VERSION 5.8 ;
BUSBITCHARS "[]" ;
DIVIDERCHAR "/" ;
UNITS
    DATABASE MICRONS 1000 ;
END UNITS

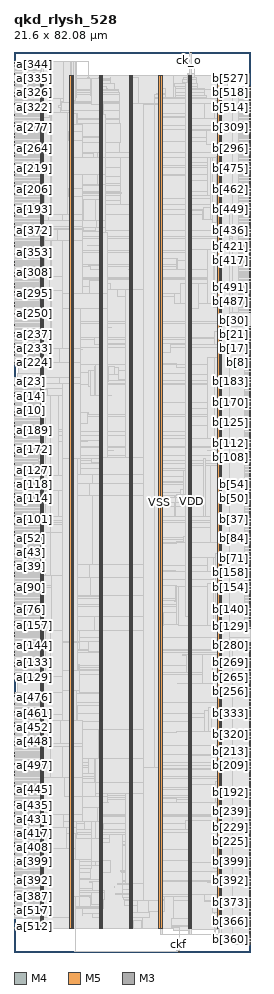
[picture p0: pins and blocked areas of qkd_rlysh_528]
MACRO qkd_rlysh_528
  FOREIGN qkd_rlysh_528 0 0 ;
  CLASS BLOCK ;
  SIZE 21.6 BY 82.08 ;
  PIN a[0]
    DIRECTION INPUT ;
    USE SIGNAL ;
    PORT
      LAYER M4 ;
        RECT  0 47.952 0.084 47.976 ;
    END
  END a[0]
  PIN a[100]
    DIRECTION INPUT ;
    USE SIGNAL ;
    PORT
      LAYER M4 ;
        RECT  0 39.312 0.084 39.336 ;
    END
  END a[100]
  PIN a[101]
    DIRECTION INPUT ;
    USE SIGNAL ;
    PORT
      LAYER M4 ;
        RECT  0 39.456 0.084 39.48 ;
    END
  END a[101]
  PIN a[102]
    DIRECTION INPUT ;
    USE SIGNAL ;
    PORT
      LAYER M4 ;
        RECT  0 39.6 0.084 39.624 ;
    END
  END a[102]
  PIN a[103]
    DIRECTION INPUT ;
    USE SIGNAL ;
    PORT
      LAYER M4 ;
        RECT  0 39.744 0.084 39.768 ;
    END
  END a[103]
  PIN a[104]
    DIRECTION INPUT ;
    USE SIGNAL ;
    PORT
      LAYER M4 ;
        RECT  0 39.888 0.084 39.912 ;
    END
  END a[104]
  PIN a[105]
    DIRECTION INPUT ;
    USE SIGNAL ;
    PORT
      LAYER M4 ;
        RECT  0 40.032 0.084 40.056 ;
    END
  END a[105]
  PIN a[106]
    DIRECTION INPUT ;
    USE SIGNAL ;
    PORT
      LAYER M4 ;
        RECT  0 40.176 0.084 40.2 ;
    END
  END a[106]
  PIN a[107]
    DIRECTION INPUT ;
    USE SIGNAL ;
    PORT
      LAYER M4 ;
        RECT  0 40.32 0.084 40.344 ;
    END
  END a[107]
  PIN a[108]
    DIRECTION INPUT ;
    USE SIGNAL ;
    PORT
      LAYER M4 ;
        RECT  0 40.464 0.084 40.488 ;
    END
  END a[108]
  PIN a[109]
    DIRECTION INPUT ;
    USE SIGNAL ;
    PORT
      LAYER M4 ;
        RECT  0 40.608 0.084 40.632 ;
    END
  END a[109]
  PIN a[10]
    DIRECTION INPUT ;
    USE SIGNAL ;
    PORT
      LAYER M4 ;
        RECT  0 49.392 0.084 49.416 ;
    END
  END a[10]
  PIN a[110]
    DIRECTION INPUT ;
    USE SIGNAL ;
    PORT
      LAYER M4 ;
        RECT  0 40.752 0.084 40.776 ;
    END
  END a[110]
  PIN a[111]
    DIRECTION INPUT ;
    USE SIGNAL ;
    PORT
      LAYER M4 ;
        RECT  0 40.896 0.084 40.92 ;
    END
  END a[111]
  PIN a[112]
    DIRECTION INPUT ;
    USE SIGNAL ;
    PORT
      LAYER M4 ;
        RECT  0 41.04 0.084 41.064 ;
    END
  END a[112]
  PIN a[113]
    DIRECTION INPUT ;
    USE SIGNAL ;
    PORT
      LAYER M4 ;
        RECT  0 41.184 0.084 41.208 ;
    END
  END a[113]
  PIN a[114]
    DIRECTION INPUT ;
    USE SIGNAL ;
    PORT
      LAYER M4 ;
        RECT  0 41.328 0.084 41.352 ;
    END
  END a[114]
  PIN a[115]
    DIRECTION INPUT ;
    USE SIGNAL ;
    PORT
      LAYER M4 ;
        RECT  0 41.472 0.084 41.496 ;
    END
  END a[115]
  PIN a[116]
    DIRECTION INPUT ;
    USE SIGNAL ;
    PORT
      LAYER M4 ;
        RECT  0 41.616 0.084 41.64 ;
    END
  END a[116]
  PIN a[117]
    DIRECTION INPUT ;
    USE SIGNAL ;
    PORT
      LAYER M4 ;
        RECT  0 41.76 0.084 41.784 ;
    END
  END a[117]
  PIN a[118]
    DIRECTION INPUT ;
    USE SIGNAL ;
    PORT
      LAYER M4 ;
        RECT  0 41.904 0.084 41.928 ;
    END
  END a[118]
  PIN a[119]
    DIRECTION INPUT ;
    USE SIGNAL ;
    PORT
      LAYER M4 ;
        RECT  0 42.048 0.084 42.072 ;
    END
  END a[119]
  PIN a[11]
    DIRECTION INPUT ;
    USE SIGNAL ;
    PORT
      LAYER M4 ;
        RECT  0 49.536 0.084 49.56 ;
    END
  END a[11]
  PIN a[120]
    DIRECTION INPUT ;
    USE SIGNAL ;
    PORT
      LAYER M4 ;
        RECT  0 42.192 0.084 42.216 ;
    END
  END a[120]
  PIN a[121]
    DIRECTION INPUT ;
    USE SIGNAL ;
    PORT
      LAYER M4 ;
        RECT  0 42.336 0.084 42.36 ;
    END
  END a[121]
  PIN a[122]
    DIRECTION INPUT ;
    USE SIGNAL ;
    PORT
      LAYER M4 ;
        RECT  0 42.48 0.084 42.504 ;
    END
  END a[122]
  PIN a[123]
    DIRECTION INPUT ;
    USE SIGNAL ;
    PORT
      LAYER M4 ;
        RECT  0 42.624 0.084 42.648 ;
    END
  END a[123]
  PIN a[124]
    DIRECTION INPUT ;
    USE SIGNAL ;
    PORT
      LAYER M4 ;
        RECT  0 42.768 0.084 42.792 ;
    END
  END a[124]
  PIN a[125]
    DIRECTION INPUT ;
    USE SIGNAL ;
    PORT
      LAYER M4 ;
        RECT  0 42.912 0.084 42.936 ;
    END
  END a[125]
  PIN a[126]
    DIRECTION INPUT ;
    USE SIGNAL ;
    PORT
      LAYER M4 ;
        RECT  0 43.056 0.084 43.08 ;
    END
  END a[126]
  PIN a[127]
    DIRECTION INPUT ;
    USE SIGNAL ;
    PORT
      LAYER M4 ;
        RECT  0 43.2 0.084 43.224 ;
    END
  END a[127]
  PIN a[128]
    DIRECTION INPUT ;
    USE SIGNAL ;
    PORT
      LAYER M4 ;
        RECT  0 24.912 0.084 24.936 ;
    END
  END a[128]
  PIN a[129]
    DIRECTION INPUT ;
    USE SIGNAL ;
    PORT
      LAYER M4 ;
        RECT  0 25.056 0.084 25.08 ;
    END
  END a[129]
  PIN a[12]
    DIRECTION INPUT ;
    USE SIGNAL ;
    PORT
      LAYER M4 ;
        RECT  0 49.68 0.084 49.704 ;
    END
  END a[12]
  PIN a[130]
    DIRECTION INPUT ;
    USE SIGNAL ;
    PORT
      LAYER M4 ;
        RECT  0 25.2 0.084 25.224 ;
    END
  END a[130]
  PIN a[131]
    DIRECTION INPUT ;
    USE SIGNAL ;
    PORT
      LAYER M4 ;
        RECT  0 25.344 0.084 25.368 ;
    END
  END a[131]
  PIN a[132]
    DIRECTION INPUT ;
    USE SIGNAL ;
    PORT
      LAYER M4 ;
        RECT  0 25.488 0.084 25.512 ;
    END
  END a[132]
  PIN a[133]
    DIRECTION INPUT ;
    USE SIGNAL ;
    PORT
      LAYER M4 ;
        RECT  0 25.632 0.084 25.656 ;
    END
  END a[133]
  PIN a[134]
    DIRECTION INPUT ;
    USE SIGNAL ;
    PORT
      LAYER M4 ;
        RECT  0 25.776 0.084 25.8 ;
    END
  END a[134]
  PIN a[135]
    DIRECTION INPUT ;
    USE SIGNAL ;
    PORT
      LAYER M4 ;
        RECT  0 25.92 0.084 25.944 ;
    END
  END a[135]
  PIN a[136]
    DIRECTION INPUT ;
    USE SIGNAL ;
    PORT
      LAYER M4 ;
        RECT  0 26.064 0.084 26.088 ;
    END
  END a[136]
  PIN a[137]
    DIRECTION INPUT ;
    USE SIGNAL ;
    PORT
      LAYER M4 ;
        RECT  0 26.208 0.084 26.232 ;
    END
  END a[137]
  PIN a[138]
    DIRECTION INPUT ;
    USE SIGNAL ;
    PORT
      LAYER M4 ;
        RECT  0 26.352 0.084 26.376 ;
    END
  END a[138]
  PIN a[139]
    DIRECTION INPUT ;
    USE SIGNAL ;
    PORT
      LAYER M4 ;
        RECT  0 26.496 0.084 26.52 ;
    END
  END a[139]
  PIN a[13]
    DIRECTION INPUT ;
    USE SIGNAL ;
    PORT
      LAYER M4 ;
        RECT  0 49.824 0.084 49.848 ;
    END
  END a[13]
  PIN a[140]
    DIRECTION INPUT ;
    USE SIGNAL ;
    PORT
      LAYER M4 ;
        RECT  0 26.64 0.084 26.664 ;
    END
  END a[140]
  PIN a[141]
    DIRECTION INPUT ;
    USE SIGNAL ;
    PORT
      LAYER M4 ;
        RECT  0 26.784 0.084 26.808 ;
    END
  END a[141]
  PIN a[142]
    DIRECTION INPUT ;
    USE SIGNAL ;
    PORT
      LAYER M4 ;
        RECT  0 26.928 0.084 26.952 ;
    END
  END a[142]
  PIN a[143]
    DIRECTION INPUT ;
    USE SIGNAL ;
    PORT
      LAYER M4 ;
        RECT  0 27.072 0.084 27.096 ;
    END
  END a[143]
  PIN a[144]
    DIRECTION INPUT ;
    USE SIGNAL ;
    PORT
      LAYER M4 ;
        RECT  0 27.216 0.084 27.24 ;
    END
  END a[144]
  PIN a[145]
    DIRECTION INPUT ;
    USE SIGNAL ;
    PORT
      LAYER M4 ;
        RECT  0 27.36 0.084 27.384 ;
    END
  END a[145]
  PIN a[146]
    DIRECTION INPUT ;
    USE SIGNAL ;
    PORT
      LAYER M4 ;
        RECT  0 27.504 0.084 27.528 ;
    END
  END a[146]
  PIN a[147]
    DIRECTION INPUT ;
    USE SIGNAL ;
    PORT
      LAYER M4 ;
        RECT  0 27.648 0.084 27.672 ;
    END
  END a[147]
  PIN a[148]
    DIRECTION INPUT ;
    USE SIGNAL ;
    PORT
      LAYER M4 ;
        RECT  0 27.792 0.084 27.816 ;
    END
  END a[148]
  PIN a[149]
    DIRECTION INPUT ;
    USE SIGNAL ;
    PORT
      LAYER M4 ;
        RECT  0 27.936 0.084 27.96 ;
    END
  END a[149]
  PIN a[14]
    DIRECTION INPUT ;
    USE SIGNAL ;
    PORT
      LAYER M4 ;
        RECT  0 49.968 0.084 49.992 ;
    END
  END a[14]
  PIN a[150]
    DIRECTION INPUT ;
    USE SIGNAL ;
    PORT
      LAYER M4 ;
        RECT  0 28.08 0.084 28.104 ;
    END
  END a[150]
  PIN a[151]
    DIRECTION INPUT ;
    USE SIGNAL ;
    PORT
      LAYER M4 ;
        RECT  0 28.224 0.084 28.248 ;
    END
  END a[151]
  PIN a[152]
    DIRECTION INPUT ;
    USE SIGNAL ;
    PORT
      LAYER M4 ;
        RECT  0 28.368 0.084 28.392 ;
    END
  END a[152]
  PIN a[153]
    DIRECTION INPUT ;
    USE SIGNAL ;
    PORT
      LAYER M4 ;
        RECT  0 28.512 0.084 28.536 ;
    END
  END a[153]
  PIN a[154]
    DIRECTION INPUT ;
    USE SIGNAL ;
    PORT
      LAYER M4 ;
        RECT  0 28.656 0.084 28.68 ;
    END
  END a[154]
  PIN a[155]
    DIRECTION INPUT ;
    USE SIGNAL ;
    PORT
      LAYER M4 ;
        RECT  0 28.8 0.084 28.824 ;
    END
  END a[155]
  PIN a[156]
    DIRECTION INPUT ;
    USE SIGNAL ;
    PORT
      LAYER M4 ;
        RECT  0 28.944 0.084 28.968 ;
    END
  END a[156]
  PIN a[157]
    DIRECTION INPUT ;
    USE SIGNAL ;
    PORT
      LAYER M4 ;
        RECT  0 29.088 0.084 29.112 ;
    END
  END a[157]
  PIN a[158]
    DIRECTION INPUT ;
    USE SIGNAL ;
    PORT
      LAYER M4 ;
        RECT  0 29.232 0.084 29.256 ;
    END
  END a[158]
  PIN a[159]
    DIRECTION INPUT ;
    USE SIGNAL ;
    PORT
      LAYER M4 ;
        RECT  0 29.376 0.084 29.4 ;
    END
  END a[159]
  PIN a[15]
    DIRECTION INPUT ;
    USE SIGNAL ;
    PORT
      LAYER M4 ;
        RECT  0 50.112 0.084 50.136 ;
    END
  END a[15]
  PIN a[160]
    DIRECTION INPUT ;
    USE SIGNAL ;
    PORT
      LAYER M4 ;
        RECT  0 43.344 0.084 43.368 ;
    END
  END a[160]
  PIN a[161]
    DIRECTION INPUT ;
    USE SIGNAL ;
    PORT
      LAYER M4 ;
        RECT  0 43.488 0.084 43.512 ;
    END
  END a[161]
  PIN a[162]
    DIRECTION INPUT ;
    USE SIGNAL ;
    PORT
      LAYER M4 ;
        RECT  0 43.632 0.084 43.656 ;
    END
  END a[162]
  PIN a[163]
    DIRECTION INPUT ;
    USE SIGNAL ;
    PORT
      LAYER M4 ;
        RECT  0 43.776 0.084 43.8 ;
    END
  END a[163]
  PIN a[164]
    DIRECTION INPUT ;
    USE SIGNAL ;
    PORT
      LAYER M4 ;
        RECT  0 43.92 0.084 43.944 ;
    END
  END a[164]
  PIN a[165]
    DIRECTION INPUT ;
    USE SIGNAL ;
    PORT
      LAYER M4 ;
        RECT  0 44.064 0.084 44.088 ;
    END
  END a[165]
  PIN a[166]
    DIRECTION INPUT ;
    USE SIGNAL ;
    PORT
      LAYER M4 ;
        RECT  0 44.208 0.084 44.232 ;
    END
  END a[166]
  PIN a[167]
    DIRECTION INPUT ;
    USE SIGNAL ;
    PORT
      LAYER M4 ;
        RECT  0 44.352 0.084 44.376 ;
    END
  END a[167]
  PIN a[168]
    DIRECTION INPUT ;
    USE SIGNAL ;
    PORT
      LAYER M4 ;
        RECT  0 44.496 0.084 44.52 ;
    END
  END a[168]
  PIN a[169]
    DIRECTION INPUT ;
    USE SIGNAL ;
    PORT
      LAYER M4 ;
        RECT  0 44.64 0.084 44.664 ;
    END
  END a[169]
  PIN a[16]
    DIRECTION INPUT ;
    USE SIGNAL ;
    PORT
      LAYER M4 ;
        RECT  0 50.256 0.084 50.28 ;
    END
  END a[16]
  PIN a[170]
    DIRECTION INPUT ;
    USE SIGNAL ;
    PORT
      LAYER M4 ;
        RECT  0 44.784 0.084 44.808 ;
    END
  END a[170]
  PIN a[171]
    DIRECTION INPUT ;
    USE SIGNAL ;
    PORT
      LAYER M4 ;
        RECT  0 44.928 0.084 44.952 ;
    END
  END a[171]
  PIN a[172]
    DIRECTION INPUT ;
    USE SIGNAL ;
    PORT
      LAYER M4 ;
        RECT  0 45.072 0.084 45.096 ;
    END
  END a[172]
  PIN a[173]
    DIRECTION INPUT ;
    USE SIGNAL ;
    PORT
      LAYER M4 ;
        RECT  0 45.216 0.084 45.24 ;
    END
  END a[173]
  PIN a[174]
    DIRECTION INPUT ;
    USE SIGNAL ;
    PORT
      LAYER M4 ;
        RECT  0 45.36 0.084 45.384 ;
    END
  END a[174]
  PIN a[175]
    DIRECTION INPUT ;
    USE SIGNAL ;
    PORT
      LAYER M4 ;
        RECT  0 45.504 0.084 45.528 ;
    END
  END a[175]
  PIN a[176]
    DIRECTION INPUT ;
    USE SIGNAL ;
    PORT
      LAYER M4 ;
        RECT  0 45.648 0.084 45.672 ;
    END
  END a[176]
  PIN a[177]
    DIRECTION INPUT ;
    USE SIGNAL ;
    PORT
      LAYER M4 ;
        RECT  0 45.792 0.084 45.816 ;
    END
  END a[177]
  PIN a[178]
    DIRECTION INPUT ;
    USE SIGNAL ;
    PORT
      LAYER M4 ;
        RECT  0 45.936 0.084 45.96 ;
    END
  END a[178]
  PIN a[179]
    DIRECTION INPUT ;
    USE SIGNAL ;
    PORT
      LAYER M4 ;
        RECT  0 46.08 0.084 46.104 ;
    END
  END a[179]
  PIN a[17]
    DIRECTION INPUT ;
    USE SIGNAL ;
    PORT
      LAYER M4 ;
        RECT  0 50.4 0.084 50.424 ;
    END
  END a[17]
  PIN a[180]
    DIRECTION INPUT ;
    USE SIGNAL ;
    PORT
      LAYER M4 ;
        RECT  0 46.224 0.084 46.248 ;
    END
  END a[180]
  PIN a[181]
    DIRECTION INPUT ;
    USE SIGNAL ;
    PORT
      LAYER M4 ;
        RECT  0 46.368 0.084 46.392 ;
    END
  END a[181]
  PIN a[182]
    DIRECTION INPUT ;
    USE SIGNAL ;
    PORT
      LAYER M4 ;
        RECT  0 46.512 0.084 46.536 ;
    END
  END a[182]
  PIN a[183]
    DIRECTION INPUT ;
    USE SIGNAL ;
    PORT
      LAYER M4 ;
        RECT  0 46.656 0.084 46.68 ;
    END
  END a[183]
  PIN a[184]
    DIRECTION INPUT ;
    USE SIGNAL ;
    PORT
      LAYER M4 ;
        RECT  0 46.8 0.084 46.824 ;
    END
  END a[184]
  PIN a[185]
    DIRECTION INPUT ;
    USE SIGNAL ;
    PORT
      LAYER M4 ;
        RECT  0 46.944 0.084 46.968 ;
    END
  END a[185]
  PIN a[186]
    DIRECTION INPUT ;
    USE SIGNAL ;
    PORT
      LAYER M4 ;
        RECT  0 47.088 0.084 47.112 ;
    END
  END a[186]
  PIN a[187]
    DIRECTION INPUT ;
    USE SIGNAL ;
    PORT
      LAYER M4 ;
        RECT  0 47.232 0.084 47.256 ;
    END
  END a[187]
  PIN a[188]
    DIRECTION INPUT ;
    USE SIGNAL ;
    PORT
      LAYER M4 ;
        RECT  0 47.376 0.084 47.4 ;
    END
  END a[188]
  PIN a[189]
    DIRECTION INPUT ;
    USE SIGNAL ;
    PORT
      LAYER M4 ;
        RECT  0 47.52 0.084 47.544 ;
    END
  END a[189]
  PIN a[18]
    DIRECTION INPUT ;
    USE SIGNAL ;
    PORT
      LAYER M4 ;
        RECT  0 50.544 0.084 50.568 ;
    END
  END a[18]
  PIN a[190]
    DIRECTION INPUT ;
    USE SIGNAL ;
    PORT
      LAYER M4 ;
        RECT  0 47.664 0.084 47.688 ;
    END
  END a[190]
  PIN a[191]
    DIRECTION INPUT ;
    USE SIGNAL ;
    PORT
      LAYER M4 ;
        RECT  0 47.808 0.084 47.832 ;
    END
  END a[191]
  PIN a[192]
    DIRECTION INPUT ;
    USE SIGNAL ;
    PORT
      LAYER M4 ;
        RECT  0 67.536 0.084 67.56 ;
    END
  END a[192]
  PIN a[193]
    DIRECTION INPUT ;
    USE SIGNAL ;
    PORT
      LAYER M4 ;
        RECT  0 67.68 0.084 67.704 ;
    END
  END a[193]
  PIN a[194]
    DIRECTION INPUT ;
    USE SIGNAL ;
    PORT
      LAYER M4 ;
        RECT  0 67.824 0.084 67.848 ;
    END
  END a[194]
  PIN a[195]
    DIRECTION INPUT ;
    USE SIGNAL ;
    PORT
      LAYER M4 ;
        RECT  0 67.968 0.084 67.992 ;
    END
  END a[195]
  PIN a[196]
    DIRECTION INPUT ;
    USE SIGNAL ;
    PORT
      LAYER M4 ;
        RECT  0 68.112 0.084 68.136 ;
    END
  END a[196]
  PIN a[197]
    DIRECTION INPUT ;
    USE SIGNAL ;
    PORT
      LAYER M4 ;
        RECT  0 68.256 0.084 68.28 ;
    END
  END a[197]
  PIN a[198]
    DIRECTION INPUT ;
    USE SIGNAL ;
    PORT
      LAYER M4 ;
        RECT  0 68.4 0.084 68.424 ;
    END
  END a[198]
  PIN a[199]
    DIRECTION INPUT ;
    USE SIGNAL ;
    PORT
      LAYER M4 ;
        RECT  0 68.544 0.084 68.568 ;
    END
  END a[199]
  PIN a[19]
    DIRECTION INPUT ;
    USE SIGNAL ;
    PORT
      LAYER M4 ;
        RECT  0 50.688 0.084 50.712 ;
    END
  END a[19]
  PIN a[1]
    DIRECTION INPUT ;
    USE SIGNAL ;
    PORT
      LAYER M4 ;
        RECT  0 48.096 0.084 48.12 ;
    END
  END a[1]
  PIN a[200]
    DIRECTION INPUT ;
    USE SIGNAL ;
    PORT
      LAYER M4 ;
        RECT  0 68.688 0.084 68.712 ;
    END
  END a[200]
  PIN a[201]
    DIRECTION INPUT ;
    USE SIGNAL ;
    PORT
      LAYER M4 ;
        RECT  0 68.832 0.084 68.856 ;
    END
  END a[201]
  PIN a[202]
    DIRECTION INPUT ;
    USE SIGNAL ;
    PORT
      LAYER M4 ;
        RECT  0 68.976 0.084 69 ;
    END
  END a[202]
  PIN a[203]
    DIRECTION INPUT ;
    USE SIGNAL ;
    PORT
      LAYER M4 ;
        RECT  0 69.12 0.084 69.144 ;
    END
  END a[203]
  PIN a[204]
    DIRECTION INPUT ;
    USE SIGNAL ;
    PORT
      LAYER M4 ;
        RECT  0 69.264 0.084 69.288 ;
    END
  END a[204]
  PIN a[205]
    DIRECTION INPUT ;
    USE SIGNAL ;
    PORT
      LAYER M4 ;
        RECT  0 69.408 0.084 69.432 ;
    END
  END a[205]
  PIN a[206]
    DIRECTION INPUT ;
    USE SIGNAL ;
    PORT
      LAYER M4 ;
        RECT  0 69.552 0.084 69.576 ;
    END
  END a[206]
  PIN a[207]
    DIRECTION INPUT ;
    USE SIGNAL ;
    PORT
      LAYER M4 ;
        RECT  0 69.696 0.084 69.72 ;
    END
  END a[207]
  PIN a[208]
    DIRECTION INPUT ;
    USE SIGNAL ;
    PORT
      LAYER M4 ;
        RECT  0 69.84 0.084 69.864 ;
    END
  END a[208]
  PIN a[209]
    DIRECTION INPUT ;
    USE SIGNAL ;
    PORT
      LAYER M4 ;
        RECT  0 69.984 0.084 70.008 ;
    END
  END a[209]
  PIN a[20]
    DIRECTION INPUT ;
    USE SIGNAL ;
    PORT
      LAYER M4 ;
        RECT  0 50.832 0.084 50.856 ;
    END
  END a[20]
  PIN a[210]
    DIRECTION INPUT ;
    USE SIGNAL ;
    PORT
      LAYER M4 ;
        RECT  0 70.128 0.084 70.152 ;
    END
  END a[210]
  PIN a[211]
    DIRECTION INPUT ;
    USE SIGNAL ;
    PORT
      LAYER M4 ;
        RECT  0 70.272 0.084 70.296 ;
    END
  END a[211]
  PIN a[212]
    DIRECTION INPUT ;
    USE SIGNAL ;
    PORT
      LAYER M4 ;
        RECT  0 70.416 0.084 70.44 ;
    END
  END a[212]
  PIN a[213]
    DIRECTION INPUT ;
    USE SIGNAL ;
    PORT
      LAYER M4 ;
        RECT  0 70.56 0.084 70.584 ;
    END
  END a[213]
  PIN a[214]
    DIRECTION INPUT ;
    USE SIGNAL ;
    PORT
      LAYER M4 ;
        RECT  0 70.704 0.084 70.728 ;
    END
  END a[214]
  PIN a[215]
    DIRECTION INPUT ;
    USE SIGNAL ;
    PORT
      LAYER M4 ;
        RECT  0 70.848 0.084 70.872 ;
    END
  END a[215]
  PIN a[216]
    DIRECTION INPUT ;
    USE SIGNAL ;
    PORT
      LAYER M4 ;
        RECT  0 70.992 0.084 71.016 ;
    END
  END a[216]
  PIN a[217]
    DIRECTION INPUT ;
    USE SIGNAL ;
    PORT
      LAYER M4 ;
        RECT  0 71.136 0.084 71.16 ;
    END
  END a[217]
  PIN a[218]
    DIRECTION INPUT ;
    USE SIGNAL ;
    PORT
      LAYER M4 ;
        RECT  0 71.28 0.084 71.304 ;
    END
  END a[218]
  PIN a[219]
    DIRECTION INPUT ;
    USE SIGNAL ;
    PORT
      LAYER M4 ;
        RECT  0 71.424 0.084 71.448 ;
    END
  END a[219]
  PIN a[21]
    DIRECTION INPUT ;
    USE SIGNAL ;
    PORT
      LAYER M4 ;
        RECT  0 50.976 0.084 51 ;
    END
  END a[21]
  PIN a[220]
    DIRECTION INPUT ;
    USE SIGNAL ;
    PORT
      LAYER M4 ;
        RECT  0 71.568 0.084 71.592 ;
    END
  END a[220]
  PIN a[221]
    DIRECTION INPUT ;
    USE SIGNAL ;
    PORT
      LAYER M4 ;
        RECT  0 71.712 0.084 71.736 ;
    END
  END a[221]
  PIN a[222]
    DIRECTION INPUT ;
    USE SIGNAL ;
    PORT
      LAYER M4 ;
        RECT  0 71.856 0.084 71.88 ;
    END
  END a[222]
  PIN a[223]
    DIRECTION INPUT ;
    USE SIGNAL ;
    PORT
      LAYER M4 ;
        RECT  0 72 0.084 72.024 ;
    END
  END a[223]
  PIN a[224]
    DIRECTION INPUT ;
    USE SIGNAL ;
    PORT
      LAYER M4 ;
        RECT  0 53.712 0.084 53.736 ;
    END
  END a[224]
  PIN a[225]
    DIRECTION INPUT ;
    USE SIGNAL ;
    PORT
      LAYER M4 ;
        RECT  0 53.856 0.084 53.88 ;
    END
  END a[225]
  PIN a[226]
    DIRECTION INPUT ;
    USE SIGNAL ;
    PORT
      LAYER M4 ;
        RECT  0 54 0.084 54.024 ;
    END
  END a[226]
  PIN a[227]
    DIRECTION INPUT ;
    USE SIGNAL ;
    PORT
      LAYER M4 ;
        RECT  0 54.144 0.084 54.168 ;
    END
  END a[227]
  PIN a[228]
    DIRECTION INPUT ;
    USE SIGNAL ;
    PORT
      LAYER M4 ;
        RECT  0 54.288 0.084 54.312 ;
    END
  END a[228]
  PIN a[229]
    DIRECTION INPUT ;
    USE SIGNAL ;
    PORT
      LAYER M4 ;
        RECT  0 54.432 0.084 54.456 ;
    END
  END a[229]
  PIN a[22]
    DIRECTION INPUT ;
    USE SIGNAL ;
    PORT
      LAYER M4 ;
        RECT  0 51.12 0.084 51.144 ;
    END
  END a[22]
  PIN a[230]
    DIRECTION INPUT ;
    USE SIGNAL ;
    PORT
      LAYER M4 ;
        RECT  0 54.576 0.084 54.6 ;
    END
  END a[230]
  PIN a[231]
    DIRECTION INPUT ;
    USE SIGNAL ;
    PORT
      LAYER M4 ;
        RECT  0 54.72 0.084 54.744 ;
    END
  END a[231]
  PIN a[232]
    DIRECTION INPUT ;
    USE SIGNAL ;
    PORT
      LAYER M4 ;
        RECT  0 54.864 0.084 54.888 ;
    END
  END a[232]
  PIN a[233]
    DIRECTION INPUT ;
    USE SIGNAL ;
    PORT
      LAYER M4 ;
        RECT  0 55.008 0.084 55.032 ;
    END
  END a[233]
  PIN a[234]
    DIRECTION INPUT ;
    USE SIGNAL ;
    PORT
      LAYER M4 ;
        RECT  0 55.152 0.084 55.176 ;
    END
  END a[234]
  PIN a[235]
    DIRECTION INPUT ;
    USE SIGNAL ;
    PORT
      LAYER M4 ;
        RECT  0 55.296 0.084 55.32 ;
    END
  END a[235]
  PIN a[236]
    DIRECTION INPUT ;
    USE SIGNAL ;
    PORT
      LAYER M4 ;
        RECT  0 55.44 0.084 55.464 ;
    END
  END a[236]
  PIN a[237]
    DIRECTION INPUT ;
    USE SIGNAL ;
    PORT
      LAYER M4 ;
        RECT  0 55.584 0.084 55.608 ;
    END
  END a[237]
  PIN a[238]
    DIRECTION INPUT ;
    USE SIGNAL ;
    PORT
      LAYER M4 ;
        RECT  0 55.728 0.084 55.752 ;
    END
  END a[238]
  PIN a[239]
    DIRECTION INPUT ;
    USE SIGNAL ;
    PORT
      LAYER M4 ;
        RECT  0 55.872 0.084 55.896 ;
    END
  END a[239]
  PIN a[23]
    DIRECTION INPUT ;
    USE SIGNAL ;
    PORT
      LAYER M4 ;
        RECT  0 51.264 0.084 51.288 ;
    END
  END a[23]
  PIN a[240]
    DIRECTION INPUT ;
    USE SIGNAL ;
    PORT
      LAYER M4 ;
        RECT  0 56.016 0.084 56.04 ;
    END
  END a[240]
  PIN a[241]
    DIRECTION INPUT ;
    USE SIGNAL ;
    PORT
      LAYER M4 ;
        RECT  0 56.16 0.084 56.184 ;
    END
  END a[241]
  PIN a[242]
    DIRECTION INPUT ;
    USE SIGNAL ;
    PORT
      LAYER M4 ;
        RECT  0 56.304 0.084 56.328 ;
    END
  END a[242]
  PIN a[243]
    DIRECTION INPUT ;
    USE SIGNAL ;
    PORT
      LAYER M4 ;
        RECT  0 56.448 0.084 56.472 ;
    END
  END a[243]
  PIN a[244]
    DIRECTION INPUT ;
    USE SIGNAL ;
    PORT
      LAYER M4 ;
        RECT  0 56.592 0.084 56.616 ;
    END
  END a[244]
  PIN a[245]
    DIRECTION INPUT ;
    USE SIGNAL ;
    PORT
      LAYER M4 ;
        RECT  0 56.736 0.084 56.76 ;
    END
  END a[245]
  PIN a[246]
    DIRECTION INPUT ;
    USE SIGNAL ;
    PORT
      LAYER M4 ;
        RECT  0 56.88 0.084 56.904 ;
    END
  END a[246]
  PIN a[247]
    DIRECTION INPUT ;
    USE SIGNAL ;
    PORT
      LAYER M4 ;
        RECT  0 57.024 0.084 57.048 ;
    END
  END a[247]
  PIN a[248]
    DIRECTION INPUT ;
    USE SIGNAL ;
    PORT
      LAYER M4 ;
        RECT  0 57.168 0.084 57.192 ;
    END
  END a[248]
  PIN a[249]
    DIRECTION INPUT ;
    USE SIGNAL ;
    PORT
      LAYER M4 ;
        RECT  0 57.312 0.084 57.336 ;
    END
  END a[249]
  PIN a[24]
    DIRECTION INPUT ;
    USE SIGNAL ;
    PORT
      LAYER M4 ;
        RECT  0 51.408 0.084 51.432 ;
    END
  END a[24]
  PIN a[250]
    DIRECTION INPUT ;
    USE SIGNAL ;
    PORT
      LAYER M4 ;
        RECT  0 57.456 0.084 57.48 ;
    END
  END a[250]
  PIN a[251]
    DIRECTION INPUT ;
    USE SIGNAL ;
    PORT
      LAYER M4 ;
        RECT  0 57.6 0.084 57.624 ;
    END
  END a[251]
  PIN a[252]
    DIRECTION INPUT ;
    USE SIGNAL ;
    PORT
      LAYER M4 ;
        RECT  0 57.744 0.084 57.768 ;
    END
  END a[252]
  PIN a[253]
    DIRECTION INPUT ;
    USE SIGNAL ;
    PORT
      LAYER M4 ;
        RECT  0 57.888 0.084 57.912 ;
    END
  END a[253]
  PIN a[254]
    DIRECTION INPUT ;
    USE SIGNAL ;
    PORT
      LAYER M4 ;
        RECT  0 58.032 0.084 58.056 ;
    END
  END a[254]
  PIN a[255]
    DIRECTION INPUT ;
    USE SIGNAL ;
    PORT
      LAYER M4 ;
        RECT  0 58.176 0.084 58.2 ;
    END
  END a[255]
  PIN a[256]
    DIRECTION INPUT ;
    USE SIGNAL ;
    PORT
      LAYER M4 ;
        RECT  0 72.144 0.084 72.168 ;
    END
  END a[256]
  PIN a[257]
    DIRECTION INPUT ;
    USE SIGNAL ;
    PORT
      LAYER M4 ;
        RECT  0 72.288 0.084 72.312 ;
    END
  END a[257]
  PIN a[258]
    DIRECTION INPUT ;
    USE SIGNAL ;
    PORT
      LAYER M4 ;
        RECT  0 72.432 0.084 72.456 ;
    END
  END a[258]
  PIN a[259]
    DIRECTION INPUT ;
    USE SIGNAL ;
    PORT
      LAYER M4 ;
        RECT  0 72.576 0.084 72.6 ;
    END
  END a[259]
  PIN a[25]
    DIRECTION INPUT ;
    USE SIGNAL ;
    PORT
      LAYER M4 ;
        RECT  0 51.552 0.084 51.576 ;
    END
  END a[25]
  PIN a[260]
    DIRECTION INPUT ;
    USE SIGNAL ;
    PORT
      LAYER M4 ;
        RECT  0 72.72 0.084 72.744 ;
    END
  END a[260]
  PIN a[261]
    DIRECTION INPUT ;
    USE SIGNAL ;
    PORT
      LAYER M4 ;
        RECT  0 72.864 0.084 72.888 ;
    END
  END a[261]
  PIN a[262]
    DIRECTION INPUT ;
    USE SIGNAL ;
    PORT
      LAYER M4 ;
        RECT  0 73.008 0.084 73.032 ;
    END
  END a[262]
  PIN a[263]
    DIRECTION INPUT ;
    USE SIGNAL ;
    PORT
      LAYER M4 ;
        RECT  0 73.152 0.084 73.176 ;
    END
  END a[263]
  PIN a[264]
    DIRECTION INPUT ;
    USE SIGNAL ;
    PORT
      LAYER M4 ;
        RECT  0 73.296 0.084 73.32 ;
    END
  END a[264]
  PIN a[265]
    DIRECTION INPUT ;
    USE SIGNAL ;
    PORT
      LAYER M4 ;
        RECT  0 73.44 0.084 73.464 ;
    END
  END a[265]
  PIN a[266]
    DIRECTION INPUT ;
    USE SIGNAL ;
    PORT
      LAYER M4 ;
        RECT  0 73.584 0.084 73.608 ;
    END
  END a[266]
  PIN a[267]
    DIRECTION INPUT ;
    USE SIGNAL ;
    PORT
      LAYER M4 ;
        RECT  0 73.728 0.084 73.752 ;
    END
  END a[267]
  PIN a[268]
    DIRECTION INPUT ;
    USE SIGNAL ;
    PORT
      LAYER M4 ;
        RECT  0 73.872 0.084 73.896 ;
    END
  END a[268]
  PIN a[269]
    DIRECTION INPUT ;
    USE SIGNAL ;
    PORT
      LAYER M4 ;
        RECT  0 74.016 0.084 74.04 ;
    END
  END a[269]
  PIN a[26]
    DIRECTION INPUT ;
    USE SIGNAL ;
    PORT
      LAYER M4 ;
        RECT  0 51.696 0.084 51.72 ;
    END
  END a[26]
  PIN a[270]
    DIRECTION INPUT ;
    USE SIGNAL ;
    PORT
      LAYER M4 ;
        RECT  0 74.16 0.084 74.184 ;
    END
  END a[270]
  PIN a[271]
    DIRECTION INPUT ;
    USE SIGNAL ;
    PORT
      LAYER M4 ;
        RECT  0 74.304 0.084 74.328 ;
    END
  END a[271]
  PIN a[272]
    DIRECTION INPUT ;
    USE SIGNAL ;
    PORT
      LAYER M4 ;
        RECT  0 74.448 0.084 74.472 ;
    END
  END a[272]
  PIN a[273]
    DIRECTION INPUT ;
    USE SIGNAL ;
    PORT
      LAYER M4 ;
        RECT  0 74.592 0.084 74.616 ;
    END
  END a[273]
  PIN a[274]
    DIRECTION INPUT ;
    USE SIGNAL ;
    PORT
      LAYER M4 ;
        RECT  0 74.736 0.084 74.76 ;
    END
  END a[274]
  PIN a[275]
    DIRECTION INPUT ;
    USE SIGNAL ;
    PORT
      LAYER M4 ;
        RECT  0 74.88 0.084 74.904 ;
    END
  END a[275]
  PIN a[276]
    DIRECTION INPUT ;
    USE SIGNAL ;
    PORT
      LAYER M4 ;
        RECT  0 75.024 0.084 75.048 ;
    END
  END a[276]
  PIN a[277]
    DIRECTION INPUT ;
    USE SIGNAL ;
    PORT
      LAYER M4 ;
        RECT  0 75.168 0.084 75.192 ;
    END
  END a[277]
  PIN a[278]
    DIRECTION INPUT ;
    USE SIGNAL ;
    PORT
      LAYER M4 ;
        RECT  0 75.312 0.084 75.336 ;
    END
  END a[278]
  PIN a[279]
    DIRECTION INPUT ;
    USE SIGNAL ;
    PORT
      LAYER M4 ;
        RECT  0 75.456 0.084 75.48 ;
    END
  END a[279]
  PIN a[27]
    DIRECTION INPUT ;
    USE SIGNAL ;
    PORT
      LAYER M4 ;
        RECT  0 51.84 0.084 51.864 ;
    END
  END a[27]
  PIN a[280]
    DIRECTION INPUT ;
    USE SIGNAL ;
    PORT
      LAYER M4 ;
        RECT  0 75.6 0.084 75.624 ;
    END
  END a[280]
  PIN a[281]
    DIRECTION INPUT ;
    USE SIGNAL ;
    PORT
      LAYER M4 ;
        RECT  0 75.744 0.084 75.768 ;
    END
  END a[281]
  PIN a[282]
    DIRECTION INPUT ;
    USE SIGNAL ;
    PORT
      LAYER M4 ;
        RECT  0 75.888 0.084 75.912 ;
    END
  END a[282]
  PIN a[283]
    DIRECTION INPUT ;
    USE SIGNAL ;
    PORT
      LAYER M4 ;
        RECT  0 76.032 0.084 76.056 ;
    END
  END a[283]
  PIN a[284]
    DIRECTION INPUT ;
    USE SIGNAL ;
    PORT
      LAYER M4 ;
        RECT  0 76.176 0.084 76.2 ;
    END
  END a[284]
  PIN a[285]
    DIRECTION INPUT ;
    USE SIGNAL ;
    PORT
      LAYER M4 ;
        RECT  0 76.32 0.084 76.344 ;
    END
  END a[285]
  PIN a[286]
    DIRECTION INPUT ;
    USE SIGNAL ;
    PORT
      LAYER M4 ;
        RECT  0 76.464 0.084 76.488 ;
    END
  END a[286]
  PIN a[287]
    DIRECTION INPUT ;
    USE SIGNAL ;
    PORT
      LAYER M4 ;
        RECT  0 76.608 0.084 76.632 ;
    END
  END a[287]
  PIN a[288]
    DIRECTION INPUT ;
    USE SIGNAL ;
    PORT
      LAYER M4 ;
        RECT  0 58.32 0.084 58.344 ;
    END
  END a[288]
  PIN a[289]
    DIRECTION INPUT ;
    USE SIGNAL ;
    PORT
      LAYER M4 ;
        RECT  0 58.464 0.084 58.488 ;
    END
  END a[289]
  PIN a[28]
    DIRECTION INPUT ;
    USE SIGNAL ;
    PORT
      LAYER M4 ;
        RECT  0 51.984 0.084 52.008 ;
    END
  END a[28]
  PIN a[290]
    DIRECTION INPUT ;
    USE SIGNAL ;
    PORT
      LAYER M4 ;
        RECT  0 58.608 0.084 58.632 ;
    END
  END a[290]
  PIN a[291]
    DIRECTION INPUT ;
    USE SIGNAL ;
    PORT
      LAYER M4 ;
        RECT  0 58.752 0.084 58.776 ;
    END
  END a[291]
  PIN a[292]
    DIRECTION INPUT ;
    USE SIGNAL ;
    PORT
      LAYER M4 ;
        RECT  0 58.896 0.084 58.92 ;
    END
  END a[292]
  PIN a[293]
    DIRECTION INPUT ;
    USE SIGNAL ;
    PORT
      LAYER M4 ;
        RECT  0 59.04 0.084 59.064 ;
    END
  END a[293]
  PIN a[294]
    DIRECTION INPUT ;
    USE SIGNAL ;
    PORT
      LAYER M4 ;
        RECT  0 59.184 0.084 59.208 ;
    END
  END a[294]
  PIN a[295]
    DIRECTION INPUT ;
    USE SIGNAL ;
    PORT
      LAYER M4 ;
        RECT  0 59.328 0.084 59.352 ;
    END
  END a[295]
  PIN a[296]
    DIRECTION INPUT ;
    USE SIGNAL ;
    PORT
      LAYER M4 ;
        RECT  0 59.472 0.084 59.496 ;
    END
  END a[296]
  PIN a[297]
    DIRECTION INPUT ;
    USE SIGNAL ;
    PORT
      LAYER M4 ;
        RECT  0 59.616 0.084 59.64 ;
    END
  END a[297]
  PIN a[298]
    DIRECTION INPUT ;
    USE SIGNAL ;
    PORT
      LAYER M4 ;
        RECT  0 59.76 0.084 59.784 ;
    END
  END a[298]
  PIN a[299]
    DIRECTION INPUT ;
    USE SIGNAL ;
    PORT
      LAYER M4 ;
        RECT  0 59.904 0.084 59.928 ;
    END
  END a[299]
  PIN a[29]
    DIRECTION INPUT ;
    USE SIGNAL ;
    PORT
      LAYER M4 ;
        RECT  0 52.128 0.084 52.152 ;
    END
  END a[29]
  PIN a[2]
    DIRECTION INPUT ;
    USE SIGNAL ;
    PORT
      LAYER M4 ;
        RECT  0 48.24 0.084 48.264 ;
    END
  END a[2]
  PIN a[300]
    DIRECTION INPUT ;
    USE SIGNAL ;
    PORT
      LAYER M4 ;
        RECT  0 60.048 0.084 60.072 ;
    END
  END a[300]
  PIN a[301]
    DIRECTION INPUT ;
    USE SIGNAL ;
    PORT
      LAYER M4 ;
        RECT  0 60.192 0.084 60.216 ;
    END
  END a[301]
  PIN a[302]
    DIRECTION INPUT ;
    USE SIGNAL ;
    PORT
      LAYER M4 ;
        RECT  0 60.336 0.084 60.36 ;
    END
  END a[302]
  PIN a[303]
    DIRECTION INPUT ;
    USE SIGNAL ;
    PORT
      LAYER M4 ;
        RECT  0 60.48 0.084 60.504 ;
    END
  END a[303]
  PIN a[304]
    DIRECTION INPUT ;
    USE SIGNAL ;
    PORT
      LAYER M4 ;
        RECT  0 60.624 0.084 60.648 ;
    END
  END a[304]
  PIN a[305]
    DIRECTION INPUT ;
    USE SIGNAL ;
    PORT
      LAYER M4 ;
        RECT  0 60.768 0.084 60.792 ;
    END
  END a[305]
  PIN a[306]
    DIRECTION INPUT ;
    USE SIGNAL ;
    PORT
      LAYER M4 ;
        RECT  0 60.912 0.084 60.936 ;
    END
  END a[306]
  PIN a[307]
    DIRECTION INPUT ;
    USE SIGNAL ;
    PORT
      LAYER M4 ;
        RECT  0 61.056 0.084 61.08 ;
    END
  END a[307]
  PIN a[308]
    DIRECTION INPUT ;
    USE SIGNAL ;
    PORT
      LAYER M4 ;
        RECT  0 61.2 0.084 61.224 ;
    END
  END a[308]
  PIN a[309]
    DIRECTION INPUT ;
    USE SIGNAL ;
    PORT
      LAYER M4 ;
        RECT  0 61.344 0.084 61.368 ;
    END
  END a[309]
  PIN a[30]
    DIRECTION INPUT ;
    USE SIGNAL ;
    PORT
      LAYER M4 ;
        RECT  0 52.272 0.084 52.296 ;
    END
  END a[30]
  PIN a[310]
    DIRECTION INPUT ;
    USE SIGNAL ;
    PORT
      LAYER M4 ;
        RECT  0 61.488 0.084 61.512 ;
    END
  END a[310]
  PIN a[311]
    DIRECTION INPUT ;
    USE SIGNAL ;
    PORT
      LAYER M4 ;
        RECT  0 61.632 0.084 61.656 ;
    END
  END a[311]
  PIN a[312]
    DIRECTION INPUT ;
    USE SIGNAL ;
    PORT
      LAYER M4 ;
        RECT  0 61.776 0.084 61.8 ;
    END
  END a[312]
  PIN a[313]
    DIRECTION INPUT ;
    USE SIGNAL ;
    PORT
      LAYER M4 ;
        RECT  0 61.92 0.084 61.944 ;
    END
  END a[313]
  PIN a[314]
    DIRECTION INPUT ;
    USE SIGNAL ;
    PORT
      LAYER M4 ;
        RECT  0 62.064 0.084 62.088 ;
    END
  END a[314]
  PIN a[315]
    DIRECTION INPUT ;
    USE SIGNAL ;
    PORT
      LAYER M4 ;
        RECT  0 62.208 0.084 62.232 ;
    END
  END a[315]
  PIN a[316]
    DIRECTION INPUT ;
    USE SIGNAL ;
    PORT
      LAYER M4 ;
        RECT  0 62.352 0.084 62.376 ;
    END
  END a[316]
  PIN a[317]
    DIRECTION INPUT ;
    USE SIGNAL ;
    PORT
      LAYER M4 ;
        RECT  0 62.496 0.084 62.52 ;
    END
  END a[317]
  PIN a[318]
    DIRECTION INPUT ;
    USE SIGNAL ;
    PORT
      LAYER M4 ;
        RECT  0 62.64 0.084 62.664 ;
    END
  END a[318]
  PIN a[319]
    DIRECTION INPUT ;
    USE SIGNAL ;
    PORT
      LAYER M4 ;
        RECT  0 62.784 0.084 62.808 ;
    END
  END a[319]
  PIN a[31]
    DIRECTION INPUT ;
    USE SIGNAL ;
    PORT
      LAYER M4 ;
        RECT  0 52.416 0.084 52.44 ;
    END
  END a[31]
  PIN a[320]
    DIRECTION INPUT ;
    USE SIGNAL ;
    PORT
      LAYER M4 ;
        RECT  0 76.752 0.084 76.776 ;
    END
  END a[320]
  PIN a[321]
    DIRECTION INPUT ;
    USE SIGNAL ;
    PORT
      LAYER M4 ;
        RECT  0 76.896 0.084 76.92 ;
    END
  END a[321]
  PIN a[322]
    DIRECTION INPUT ;
    USE SIGNAL ;
    PORT
      LAYER M4 ;
        RECT  0 77.04 0.084 77.064 ;
    END
  END a[322]
  PIN a[323]
    DIRECTION INPUT ;
    USE SIGNAL ;
    PORT
      LAYER M4 ;
        RECT  0 77.184 0.084 77.208 ;
    END
  END a[323]
  PIN a[324]
    DIRECTION INPUT ;
    USE SIGNAL ;
    PORT
      LAYER M4 ;
        RECT  0 77.328 0.084 77.352 ;
    END
  END a[324]
  PIN a[325]
    DIRECTION INPUT ;
    USE SIGNAL ;
    PORT
      LAYER M4 ;
        RECT  0 77.472 0.084 77.496 ;
    END
  END a[325]
  PIN a[326]
    DIRECTION INPUT ;
    USE SIGNAL ;
    PORT
      LAYER M4 ;
        RECT  0 77.616 0.084 77.64 ;
    END
  END a[326]
  PIN a[327]
    DIRECTION INPUT ;
    USE SIGNAL ;
    PORT
      LAYER M4 ;
        RECT  0 77.76 0.084 77.784 ;
    END
  END a[327]
  PIN a[328]
    DIRECTION INPUT ;
    USE SIGNAL ;
    PORT
      LAYER M4 ;
        RECT  0 77.904 0.084 77.928 ;
    END
  END a[328]
  PIN a[329]
    DIRECTION INPUT ;
    USE SIGNAL ;
    PORT
      LAYER M4 ;
        RECT  0 78.048 0.084 78.072 ;
    END
  END a[329]
  PIN a[32]
    DIRECTION INPUT ;
    USE SIGNAL ;
    PORT
      LAYER M4 ;
        RECT  0 34.128 0.084 34.152 ;
    END
  END a[32]
  PIN a[330]
    DIRECTION INPUT ;
    USE SIGNAL ;
    PORT
      LAYER M4 ;
        RECT  0 78.192 0.084 78.216 ;
    END
  END a[330]
  PIN a[331]
    DIRECTION INPUT ;
    USE SIGNAL ;
    PORT
      LAYER M4 ;
        RECT  0 78.336 0.084 78.36 ;
    END
  END a[331]
  PIN a[332]
    DIRECTION INPUT ;
    USE SIGNAL ;
    PORT
      LAYER M4 ;
        RECT  0 78.48 0.084 78.504 ;
    END
  END a[332]
  PIN a[333]
    DIRECTION INPUT ;
    USE SIGNAL ;
    PORT
      LAYER M4 ;
        RECT  0 78.624 0.084 78.648 ;
    END
  END a[333]
  PIN a[334]
    DIRECTION INPUT ;
    USE SIGNAL ;
    PORT
      LAYER M4 ;
        RECT  0 78.768 0.084 78.792 ;
    END
  END a[334]
  PIN a[335]
    DIRECTION INPUT ;
    USE SIGNAL ;
    PORT
      LAYER M4 ;
        RECT  0 78.912 0.084 78.936 ;
    END
  END a[335]
  PIN a[336]
    DIRECTION INPUT ;
    USE SIGNAL ;
    PORT
      LAYER M4 ;
        RECT  0 79.056 0.084 79.08 ;
    END
  END a[336]
  PIN a[337]
    DIRECTION INPUT ;
    USE SIGNAL ;
    PORT
      LAYER M4 ;
        RECT  0 79.2 0.084 79.224 ;
    END
  END a[337]
  PIN a[338]
    DIRECTION INPUT ;
    USE SIGNAL ;
    PORT
      LAYER M4 ;
        RECT  0 79.344 0.084 79.368 ;
    END
  END a[338]
  PIN a[339]
    DIRECTION INPUT ;
    USE SIGNAL ;
    PORT
      LAYER M4 ;
        RECT  0 79.488 0.084 79.512 ;
    END
  END a[339]
  PIN a[33]
    DIRECTION INPUT ;
    USE SIGNAL ;
    PORT
      LAYER M4 ;
        RECT  0 34.272 0.084 34.296 ;
    END
  END a[33]
  PIN a[340]
    DIRECTION INPUT ;
    USE SIGNAL ;
    PORT
      LAYER M4 ;
        RECT  0 79.632 0.084 79.656 ;
    END
  END a[340]
  PIN a[341]
    DIRECTION INPUT ;
    USE SIGNAL ;
    PORT
      LAYER M4 ;
        RECT  0 79.776 0.084 79.8 ;
    END
  END a[341]
  PIN a[342]
    DIRECTION INPUT ;
    USE SIGNAL ;
    PORT
      LAYER M4 ;
        RECT  0 79.92 0.084 79.944 ;
    END
  END a[342]
  PIN a[343]
    DIRECTION INPUT ;
    USE SIGNAL ;
    PORT
      LAYER M4 ;
        RECT  0 80.064 0.084 80.088 ;
    END
  END a[343]
  PIN a[344]
    DIRECTION INPUT ;
    USE SIGNAL ;
    PORT
      LAYER M4 ;
        RECT  0 80.208 0.084 80.232 ;
    END
  END a[344]
  PIN a[345]
    DIRECTION INPUT ;
    USE SIGNAL ;
    PORT
      LAYER M4 ;
        RECT  0 80.352 0.084 80.376 ;
    END
  END a[345]
  PIN a[346]
    DIRECTION INPUT ;
    USE SIGNAL ;
    PORT
      LAYER M4 ;
        RECT  0 80.496 0.084 80.52 ;
    END
  END a[346]
  PIN a[347]
    DIRECTION INPUT ;
    USE SIGNAL ;
    PORT
      LAYER M4 ;
        RECT  0 80.64 0.084 80.664 ;
    END
  END a[347]
  PIN a[348]
    DIRECTION INPUT ;
    USE SIGNAL ;
    PORT
      LAYER M4 ;
        RECT  0 80.784 0.084 80.808 ;
    END
  END a[348]
  PIN a[349]
    DIRECTION INPUT ;
    USE SIGNAL ;
    PORT
      LAYER M4 ;
        RECT  0 80.928 0.084 80.952 ;
    END
  END a[349]
  PIN a[34]
    DIRECTION INPUT ;
    USE SIGNAL ;
    PORT
      LAYER M4 ;
        RECT  0 34.416 0.084 34.44 ;
    END
  END a[34]
  PIN a[350]
    DIRECTION INPUT ;
    USE SIGNAL ;
    PORT
      LAYER M4 ;
        RECT  0 81.072 0.084 81.096 ;
    END
  END a[350]
  PIN a[351]
    DIRECTION INPUT ;
    USE SIGNAL ;
    PORT
      LAYER M4 ;
        RECT  0 81.216 0.084 81.24 ;
    END
  END a[351]
  PIN a[352]
    DIRECTION INPUT ;
    USE SIGNAL ;
    PORT
      LAYER M4 ;
        RECT  0 62.928 0.084 62.952 ;
    END
  END a[352]
  PIN a[353]
    DIRECTION INPUT ;
    USE SIGNAL ;
    PORT
      LAYER M4 ;
        RECT  0 63.072 0.084 63.096 ;
    END
  END a[353]
  PIN a[354]
    DIRECTION INPUT ;
    USE SIGNAL ;
    PORT
      LAYER M4 ;
        RECT  0 63.216 0.084 63.24 ;
    END
  END a[354]
  PIN a[355]
    DIRECTION INPUT ;
    USE SIGNAL ;
    PORT
      LAYER M4 ;
        RECT  0 63.36 0.084 63.384 ;
    END
  END a[355]
  PIN a[356]
    DIRECTION INPUT ;
    USE SIGNAL ;
    PORT
      LAYER M4 ;
        RECT  0 63.504 0.084 63.528 ;
    END
  END a[356]
  PIN a[357]
    DIRECTION INPUT ;
    USE SIGNAL ;
    PORT
      LAYER M4 ;
        RECT  0 63.648 0.084 63.672 ;
    END
  END a[357]
  PIN a[358]
    DIRECTION INPUT ;
    USE SIGNAL ;
    PORT
      LAYER M4 ;
        RECT  0 63.792 0.084 63.816 ;
    END
  END a[358]
  PIN a[359]
    DIRECTION INPUT ;
    USE SIGNAL ;
    PORT
      LAYER M4 ;
        RECT  0 63.936 0.084 63.96 ;
    END
  END a[359]
  PIN a[35]
    DIRECTION INPUT ;
    USE SIGNAL ;
    PORT
      LAYER M4 ;
        RECT  0 34.56 0.084 34.584 ;
    END
  END a[35]
  PIN a[360]
    DIRECTION INPUT ;
    USE SIGNAL ;
    PORT
      LAYER M4 ;
        RECT  0 64.08 0.084 64.104 ;
    END
  END a[360]
  PIN a[361]
    DIRECTION INPUT ;
    USE SIGNAL ;
    PORT
      LAYER M4 ;
        RECT  0 64.224 0.084 64.248 ;
    END
  END a[361]
  PIN a[362]
    DIRECTION INPUT ;
    USE SIGNAL ;
    PORT
      LAYER M4 ;
        RECT  0 64.368 0.084 64.392 ;
    END
  END a[362]
  PIN a[363]
    DIRECTION INPUT ;
    USE SIGNAL ;
    PORT
      LAYER M4 ;
        RECT  0 64.512 0.084 64.536 ;
    END
  END a[363]
  PIN a[364]
    DIRECTION INPUT ;
    USE SIGNAL ;
    PORT
      LAYER M4 ;
        RECT  0 64.656 0.084 64.68 ;
    END
  END a[364]
  PIN a[365]
    DIRECTION INPUT ;
    USE SIGNAL ;
    PORT
      LAYER M4 ;
        RECT  0 64.8 0.084 64.824 ;
    END
  END a[365]
  PIN a[366]
    DIRECTION INPUT ;
    USE SIGNAL ;
    PORT
      LAYER M4 ;
        RECT  0 64.944 0.084 64.968 ;
    END
  END a[366]
  PIN a[367]
    DIRECTION INPUT ;
    USE SIGNAL ;
    PORT
      LAYER M4 ;
        RECT  0 65.088 0.084 65.112 ;
    END
  END a[367]
  PIN a[368]
    DIRECTION INPUT ;
    USE SIGNAL ;
    PORT
      LAYER M4 ;
        RECT  0 65.232 0.084 65.256 ;
    END
  END a[368]
  PIN a[369]
    DIRECTION INPUT ;
    USE SIGNAL ;
    PORT
      LAYER M4 ;
        RECT  0 65.376 0.084 65.4 ;
    END
  END a[369]
  PIN a[36]
    DIRECTION INPUT ;
    USE SIGNAL ;
    PORT
      LAYER M4 ;
        RECT  0 34.704 0.084 34.728 ;
    END
  END a[36]
  PIN a[370]
    DIRECTION INPUT ;
    USE SIGNAL ;
    PORT
      LAYER M4 ;
        RECT  0 65.52 0.084 65.544 ;
    END
  END a[370]
  PIN a[371]
    DIRECTION INPUT ;
    USE SIGNAL ;
    PORT
      LAYER M4 ;
        RECT  0 65.664 0.084 65.688 ;
    END
  END a[371]
  PIN a[372]
    DIRECTION INPUT ;
    USE SIGNAL ;
    PORT
      LAYER M4 ;
        RECT  0 65.808 0.084 65.832 ;
    END
  END a[372]
  PIN a[373]
    DIRECTION INPUT ;
    USE SIGNAL ;
    PORT
      LAYER M4 ;
        RECT  0 65.952 0.084 65.976 ;
    END
  END a[373]
  PIN a[374]
    DIRECTION INPUT ;
    USE SIGNAL ;
    PORT
      LAYER M4 ;
        RECT  0 66.096 0.084 66.12 ;
    END
  END a[374]
  PIN a[375]
    DIRECTION INPUT ;
    USE SIGNAL ;
    PORT
      LAYER M4 ;
        RECT  0 66.24 0.084 66.264 ;
    END
  END a[375]
  PIN a[376]
    DIRECTION INPUT ;
    USE SIGNAL ;
    PORT
      LAYER M4 ;
        RECT  0 66.384 0.084 66.408 ;
    END
  END a[376]
  PIN a[377]
    DIRECTION INPUT ;
    USE SIGNAL ;
    PORT
      LAYER M4 ;
        RECT  0 66.528 0.084 66.552 ;
    END
  END a[377]
  PIN a[378]
    DIRECTION INPUT ;
    USE SIGNAL ;
    PORT
      LAYER M4 ;
        RECT  0 66.672 0.084 66.696 ;
    END
  END a[378]
  PIN a[379]
    DIRECTION INPUT ;
    USE SIGNAL ;
    PORT
      LAYER M4 ;
        RECT  0 66.816 0.084 66.84 ;
    END
  END a[379]
  PIN a[37]
    DIRECTION INPUT ;
    USE SIGNAL ;
    PORT
      LAYER M4 ;
        RECT  0 34.848 0.084 34.872 ;
    END
  END a[37]
  PIN a[380]
    DIRECTION INPUT ;
    USE SIGNAL ;
    PORT
      LAYER M4 ;
        RECT  0 66.96 0.084 66.984 ;
    END
  END a[380]
  PIN a[381]
    DIRECTION INPUT ;
    USE SIGNAL ;
    PORT
      LAYER M4 ;
        RECT  0 67.104 0.084 67.128 ;
    END
  END a[381]
  PIN a[382]
    DIRECTION INPUT ;
    USE SIGNAL ;
    PORT
      LAYER M4 ;
        RECT  0 67.248 0.084 67.272 ;
    END
  END a[382]
  PIN a[383]
    DIRECTION INPUT ;
    USE SIGNAL ;
    PORT
      LAYER M4 ;
        RECT  0 67.392 0.084 67.416 ;
    END
  END a[383]
  PIN a[384]
    DIRECTION INPUT ;
    USE SIGNAL ;
    PORT
      LAYER M4 ;
        RECT  0 5.328 0.084 5.352 ;
    END
  END a[384]
  PIN a[385]
    DIRECTION INPUT ;
    USE SIGNAL ;
    PORT
      LAYER M4 ;
        RECT  0 5.472 0.084 5.496 ;
    END
  END a[385]
  PIN a[386]
    DIRECTION INPUT ;
    USE SIGNAL ;
    PORT
      LAYER M4 ;
        RECT  0 5.616 0.084 5.64 ;
    END
  END a[386]
  PIN a[387]
    DIRECTION INPUT ;
    USE SIGNAL ;
    PORT
      LAYER M4 ;
        RECT  0 5.76 0.084 5.784 ;
    END
  END a[387]
  PIN a[388]
    DIRECTION INPUT ;
    USE SIGNAL ;
    PORT
      LAYER M4 ;
        RECT  0 5.904 0.084 5.928 ;
    END
  END a[388]
  PIN a[389]
    DIRECTION INPUT ;
    USE SIGNAL ;
    PORT
      LAYER M4 ;
        RECT  0 6.048 0.084 6.072 ;
    END
  END a[389]
  PIN a[38]
    DIRECTION INPUT ;
    USE SIGNAL ;
    PORT
      LAYER M4 ;
        RECT  0 34.992 0.084 35.016 ;
    END
  END a[38]
  PIN a[390]
    DIRECTION INPUT ;
    USE SIGNAL ;
    PORT
      LAYER M4 ;
        RECT  0 6.192 0.084 6.216 ;
    END
  END a[390]
  PIN a[391]
    DIRECTION INPUT ;
    USE SIGNAL ;
    PORT
      LAYER M4 ;
        RECT  0 6.336 0.084 6.36 ;
    END
  END a[391]
  PIN a[392]
    DIRECTION INPUT ;
    USE SIGNAL ;
    PORT
      LAYER M4 ;
        RECT  0 6.48 0.084 6.504 ;
    END
  END a[392]
  PIN a[393]
    DIRECTION INPUT ;
    USE SIGNAL ;
    PORT
      LAYER M4 ;
        RECT  0 6.624 0.084 6.648 ;
    END
  END a[393]
  PIN a[394]
    DIRECTION INPUT ;
    USE SIGNAL ;
    PORT
      LAYER M4 ;
        RECT  0 6.768 0.084 6.792 ;
    END
  END a[394]
  PIN a[395]
    DIRECTION INPUT ;
    USE SIGNAL ;
    PORT
      LAYER M4 ;
        RECT  0 6.912 0.084 6.936 ;
    END
  END a[395]
  PIN a[396]
    DIRECTION INPUT ;
    USE SIGNAL ;
    PORT
      LAYER M4 ;
        RECT  0 7.056 0.084 7.08 ;
    END
  END a[396]
  PIN a[397]
    DIRECTION INPUT ;
    USE SIGNAL ;
    PORT
      LAYER M4 ;
        RECT  0 7.2 0.084 7.224 ;
    END
  END a[397]
  PIN a[398]
    DIRECTION INPUT ;
    USE SIGNAL ;
    PORT
      LAYER M4 ;
        RECT  0 7.344 0.084 7.368 ;
    END
  END a[398]
  PIN a[399]
    DIRECTION INPUT ;
    USE SIGNAL ;
    PORT
      LAYER M4 ;
        RECT  0 7.488 0.084 7.512 ;
    END
  END a[399]
  PIN a[39]
    DIRECTION INPUT ;
    USE SIGNAL ;
    PORT
      LAYER M4 ;
        RECT  0 35.136 0.084 35.16 ;
    END
  END a[39]
  PIN a[3]
    DIRECTION INPUT ;
    USE SIGNAL ;
    PORT
      LAYER M4 ;
        RECT  0 48.384 0.084 48.408 ;
    END
  END a[3]
  PIN a[400]
    DIRECTION INPUT ;
    USE SIGNAL ;
    PORT
      LAYER M4 ;
        RECT  0 7.632 0.084 7.656 ;
    END
  END a[400]
  PIN a[401]
    DIRECTION INPUT ;
    USE SIGNAL ;
    PORT
      LAYER M4 ;
        RECT  0 7.776 0.084 7.8 ;
    END
  END a[401]
  PIN a[402]
    DIRECTION INPUT ;
    USE SIGNAL ;
    PORT
      LAYER M4 ;
        RECT  0 7.92 0.084 7.944 ;
    END
  END a[402]
  PIN a[403]
    DIRECTION INPUT ;
    USE SIGNAL ;
    PORT
      LAYER M4 ;
        RECT  0 8.064 0.084 8.088 ;
    END
  END a[403]
  PIN a[404]
    DIRECTION INPUT ;
    USE SIGNAL ;
    PORT
      LAYER M4 ;
        RECT  0 8.208 0.084 8.232 ;
    END
  END a[404]
  PIN a[405]
    DIRECTION INPUT ;
    USE SIGNAL ;
    PORT
      LAYER M4 ;
        RECT  0 8.352 0.084 8.376 ;
    END
  END a[405]
  PIN a[406]
    DIRECTION INPUT ;
    USE SIGNAL ;
    PORT
      LAYER M4 ;
        RECT  0 8.496 0.084 8.52 ;
    END
  END a[406]
  PIN a[407]
    DIRECTION INPUT ;
    USE SIGNAL ;
    PORT
      LAYER M4 ;
        RECT  0 8.64 0.084 8.664 ;
    END
  END a[407]
  PIN a[408]
    DIRECTION INPUT ;
    USE SIGNAL ;
    PORT
      LAYER M4 ;
        RECT  0 8.784 0.084 8.808 ;
    END
  END a[408]
  PIN a[409]
    DIRECTION INPUT ;
    USE SIGNAL ;
    PORT
      LAYER M4 ;
        RECT  0 8.928 0.084 8.952 ;
    END
  END a[409]
  PIN a[40]
    DIRECTION INPUT ;
    USE SIGNAL ;
    PORT
      LAYER M4 ;
        RECT  0 35.28 0.084 35.304 ;
    END
  END a[40]
  PIN a[410]
    DIRECTION INPUT ;
    USE SIGNAL ;
    PORT
      LAYER M4 ;
        RECT  0 9.072 0.084 9.096 ;
    END
  END a[410]
  PIN a[411]
    DIRECTION INPUT ;
    USE SIGNAL ;
    PORT
      LAYER M4 ;
        RECT  0 9.216 0.084 9.24 ;
    END
  END a[411]
  PIN a[412]
    DIRECTION INPUT ;
    USE SIGNAL ;
    PORT
      LAYER M4 ;
        RECT  0 9.36 0.084 9.384 ;
    END
  END a[412]
  PIN a[413]
    DIRECTION INPUT ;
    USE SIGNAL ;
    PORT
      LAYER M4 ;
        RECT  0 9.504 0.084 9.528 ;
    END
  END a[413]
  PIN a[414]
    DIRECTION INPUT ;
    USE SIGNAL ;
    PORT
      LAYER M4 ;
        RECT  0 9.648 0.084 9.672 ;
    END
  END a[414]
  PIN a[415]
    DIRECTION INPUT ;
    USE SIGNAL ;
    PORT
      LAYER M4 ;
        RECT  0 9.792 0.084 9.816 ;
    END
  END a[415]
  PIN a[416]
    DIRECTION INPUT ;
    USE SIGNAL ;
    PORT
      LAYER M4 ;
        RECT  0 9.936 0.084 9.96 ;
    END
  END a[416]
  PIN a[417]
    DIRECTION INPUT ;
    USE SIGNAL ;
    PORT
      LAYER M4 ;
        RECT  0 10.08 0.084 10.104 ;
    END
  END a[417]
  PIN a[418]
    DIRECTION INPUT ;
    USE SIGNAL ;
    PORT
      LAYER M4 ;
        RECT  0 10.224 0.084 10.248 ;
    END
  END a[418]
  PIN a[419]
    DIRECTION INPUT ;
    USE SIGNAL ;
    PORT
      LAYER M4 ;
        RECT  0 10.368 0.084 10.392 ;
    END
  END a[419]
  PIN a[41]
    DIRECTION INPUT ;
    USE SIGNAL ;
    PORT
      LAYER M4 ;
        RECT  0 35.424 0.084 35.448 ;
    END
  END a[41]
  PIN a[420]
    DIRECTION INPUT ;
    USE SIGNAL ;
    PORT
      LAYER M4 ;
        RECT  0 10.512 0.084 10.536 ;
    END
  END a[420]
  PIN a[421]
    DIRECTION INPUT ;
    USE SIGNAL ;
    PORT
      LAYER M4 ;
        RECT  0 10.656 0.084 10.68 ;
    END
  END a[421]
  PIN a[422]
    DIRECTION INPUT ;
    USE SIGNAL ;
    PORT
      LAYER M4 ;
        RECT  0 10.8 0.084 10.824 ;
    END
  END a[422]
  PIN a[423]
    DIRECTION INPUT ;
    USE SIGNAL ;
    PORT
      LAYER M4 ;
        RECT  0 10.944 0.084 10.968 ;
    END
  END a[423]
  PIN a[424]
    DIRECTION INPUT ;
    USE SIGNAL ;
    PORT
      LAYER M4 ;
        RECT  0 11.088 0.084 11.112 ;
    END
  END a[424]
  PIN a[425]
    DIRECTION INPUT ;
    USE SIGNAL ;
    PORT
      LAYER M4 ;
        RECT  0 11.232 0.084 11.256 ;
    END
  END a[425]
  PIN a[426]
    DIRECTION INPUT ;
    USE SIGNAL ;
    PORT
      LAYER M4 ;
        RECT  0 11.376 0.084 11.4 ;
    END
  END a[426]
  PIN a[427]
    DIRECTION INPUT ;
    USE SIGNAL ;
    PORT
      LAYER M4 ;
        RECT  0 11.52 0.084 11.544 ;
    END
  END a[427]
  PIN a[428]
    DIRECTION INPUT ;
    USE SIGNAL ;
    PORT
      LAYER M4 ;
        RECT  0 11.664 0.084 11.688 ;
    END
  END a[428]
  PIN a[429]
    DIRECTION INPUT ;
    USE SIGNAL ;
    PORT
      LAYER M4 ;
        RECT  0 11.808 0.084 11.832 ;
    END
  END a[429]
  PIN a[42]
    DIRECTION INPUT ;
    USE SIGNAL ;
    PORT
      LAYER M4 ;
        RECT  0 35.568 0.084 35.592 ;
    END
  END a[42]
  PIN a[430]
    DIRECTION INPUT ;
    USE SIGNAL ;
    PORT
      LAYER M4 ;
        RECT  0 11.952 0.084 11.976 ;
    END
  END a[430]
  PIN a[431]
    DIRECTION INPUT ;
    USE SIGNAL ;
    PORT
      LAYER M4 ;
        RECT  0 12.096 0.084 12.12 ;
    END
  END a[431]
  PIN a[432]
    DIRECTION INPUT ;
    USE SIGNAL ;
    PORT
      LAYER M4 ;
        RECT  0 12.24 0.084 12.264 ;
    END
  END a[432]
  PIN a[433]
    DIRECTION INPUT ;
    USE SIGNAL ;
    PORT
      LAYER M4 ;
        RECT  0 12.384 0.084 12.408 ;
    END
  END a[433]
  PIN a[434]
    DIRECTION INPUT ;
    USE SIGNAL ;
    PORT
      LAYER M4 ;
        RECT  0 12.528 0.084 12.552 ;
    END
  END a[434]
  PIN a[435]
    DIRECTION INPUT ;
    USE SIGNAL ;
    PORT
      LAYER M4 ;
        RECT  0 12.672 0.084 12.696 ;
    END
  END a[435]
  PIN a[436]
    DIRECTION INPUT ;
    USE SIGNAL ;
    PORT
      LAYER M4 ;
        RECT  0 12.816 0.084 12.84 ;
    END
  END a[436]
  PIN a[437]
    DIRECTION INPUT ;
    USE SIGNAL ;
    PORT
      LAYER M4 ;
        RECT  0 12.96 0.084 12.984 ;
    END
  END a[437]
  PIN a[438]
    DIRECTION INPUT ;
    USE SIGNAL ;
    PORT
      LAYER M4 ;
        RECT  0 13.104 0.084 13.128 ;
    END
  END a[438]
  PIN a[439]
    DIRECTION INPUT ;
    USE SIGNAL ;
    PORT
      LAYER M4 ;
        RECT  0 13.248 0.084 13.272 ;
    END
  END a[439]
  PIN a[43]
    DIRECTION INPUT ;
    USE SIGNAL ;
    PORT
      LAYER M4 ;
        RECT  0 35.712 0.084 35.736 ;
    END
  END a[43]
  PIN a[440]
    DIRECTION INPUT ;
    USE SIGNAL ;
    PORT
      LAYER M4 ;
        RECT  0 13.392 0.084 13.416 ;
    END
  END a[440]
  PIN a[441]
    DIRECTION INPUT ;
    USE SIGNAL ;
    PORT
      LAYER M4 ;
        RECT  0 13.536 0.084 13.56 ;
    END
  END a[441]
  PIN a[442]
    DIRECTION INPUT ;
    USE SIGNAL ;
    PORT
      LAYER M4 ;
        RECT  0 13.68 0.084 13.704 ;
    END
  END a[442]
  PIN a[443]
    DIRECTION INPUT ;
    USE SIGNAL ;
    PORT
      LAYER M4 ;
        RECT  0 13.824 0.084 13.848 ;
    END
  END a[443]
  PIN a[444]
    DIRECTION INPUT ;
    USE SIGNAL ;
    PORT
      LAYER M4 ;
        RECT  0 13.968 0.084 13.992 ;
    END
  END a[444]
  PIN a[445]
    DIRECTION INPUT ;
    USE SIGNAL ;
    PORT
      LAYER M4 ;
        RECT  0 14.112 0.084 14.136 ;
    END
  END a[445]
  PIN a[446]
    DIRECTION INPUT ;
    USE SIGNAL ;
    PORT
      LAYER M4 ;
        RECT  0 14.256 0.084 14.28 ;
    END
  END a[446]
  PIN a[447]
    DIRECTION INPUT ;
    USE SIGNAL ;
    PORT
      LAYER M4 ;
        RECT  0 14.4 0.084 14.424 ;
    END
  END a[447]
  PIN a[448]
    DIRECTION INPUT ;
    USE SIGNAL ;
    PORT
      LAYER M4 ;
        RECT  0 19.152 0.084 19.176 ;
    END
  END a[448]
  PIN a[449]
    DIRECTION INPUT ;
    USE SIGNAL ;
    PORT
      LAYER M4 ;
        RECT  0 19.296 0.084 19.32 ;
    END
  END a[449]
  PIN a[44]
    DIRECTION INPUT ;
    USE SIGNAL ;
    PORT
      LAYER M4 ;
        RECT  0 35.856 0.084 35.88 ;
    END
  END a[44]
  PIN a[450]
    DIRECTION INPUT ;
    USE SIGNAL ;
    PORT
      LAYER M4 ;
        RECT  0 19.44 0.084 19.464 ;
    END
  END a[450]
  PIN a[451]
    DIRECTION INPUT ;
    USE SIGNAL ;
    PORT
      LAYER M4 ;
        RECT  0 19.584 0.084 19.608 ;
    END
  END a[451]
  PIN a[452]
    DIRECTION INPUT ;
    USE SIGNAL ;
    PORT
      LAYER M4 ;
        RECT  0 19.728 0.084 19.752 ;
    END
  END a[452]
  PIN a[453]
    DIRECTION INPUT ;
    USE SIGNAL ;
    PORT
      LAYER M4 ;
        RECT  0 19.872 0.084 19.896 ;
    END
  END a[453]
  PIN a[454]
    DIRECTION INPUT ;
    USE SIGNAL ;
    PORT
      LAYER M4 ;
        RECT  0 20.016 0.084 20.04 ;
    END
  END a[454]
  PIN a[455]
    DIRECTION INPUT ;
    USE SIGNAL ;
    PORT
      LAYER M4 ;
        RECT  0 20.16 0.084 20.184 ;
    END
  END a[455]
  PIN a[456]
    DIRECTION INPUT ;
    USE SIGNAL ;
    PORT
      LAYER M4 ;
        RECT  0 20.304 0.084 20.328 ;
    END
  END a[456]
  PIN a[457]
    DIRECTION INPUT ;
    USE SIGNAL ;
    PORT
      LAYER M4 ;
        RECT  0 20.448 0.084 20.472 ;
    END
  END a[457]
  PIN a[458]
    DIRECTION INPUT ;
    USE SIGNAL ;
    PORT
      LAYER M4 ;
        RECT  0 20.592 0.084 20.616 ;
    END
  END a[458]
  PIN a[459]
    DIRECTION INPUT ;
    USE SIGNAL ;
    PORT
      LAYER M4 ;
        RECT  0 20.736 0.084 20.76 ;
    END
  END a[459]
  PIN a[45]
    DIRECTION INPUT ;
    USE SIGNAL ;
    PORT
      LAYER M4 ;
        RECT  0 36 0.084 36.024 ;
    END
  END a[45]
  PIN a[460]
    DIRECTION INPUT ;
    USE SIGNAL ;
    PORT
      LAYER M4 ;
        RECT  0 20.88 0.084 20.904 ;
    END
  END a[460]
  PIN a[461]
    DIRECTION INPUT ;
    USE SIGNAL ;
    PORT
      LAYER M4 ;
        RECT  0 21.024 0.084 21.048 ;
    END
  END a[461]
  PIN a[462]
    DIRECTION INPUT ;
    USE SIGNAL ;
    PORT
      LAYER M4 ;
        RECT  0 21.168 0.084 21.192 ;
    END
  END a[462]
  PIN a[463]
    DIRECTION INPUT ;
    USE SIGNAL ;
    PORT
      LAYER M4 ;
        RECT  0 21.312 0.084 21.336 ;
    END
  END a[463]
  PIN a[464]
    DIRECTION INPUT ;
    USE SIGNAL ;
    PORT
      LAYER M4 ;
        RECT  0 21.456 0.084 21.48 ;
    END
  END a[464]
  PIN a[465]
    DIRECTION INPUT ;
    USE SIGNAL ;
    PORT
      LAYER M4 ;
        RECT  0 21.6 0.084 21.624 ;
    END
  END a[465]
  PIN a[466]
    DIRECTION INPUT ;
    USE SIGNAL ;
    PORT
      LAYER M4 ;
        RECT  0 21.744 0.084 21.768 ;
    END
  END a[466]
  PIN a[467]
    DIRECTION INPUT ;
    USE SIGNAL ;
    PORT
      LAYER M4 ;
        RECT  0 21.888 0.084 21.912 ;
    END
  END a[467]
  PIN a[468]
    DIRECTION INPUT ;
    USE SIGNAL ;
    PORT
      LAYER M4 ;
        RECT  0 22.032 0.084 22.056 ;
    END
  END a[468]
  PIN a[469]
    DIRECTION INPUT ;
    USE SIGNAL ;
    PORT
      LAYER M4 ;
        RECT  0 22.176 0.084 22.2 ;
    END
  END a[469]
  PIN a[46]
    DIRECTION INPUT ;
    USE SIGNAL ;
    PORT
      LAYER M4 ;
        RECT  0 36.144 0.084 36.168 ;
    END
  END a[46]
  PIN a[470]
    DIRECTION INPUT ;
    USE SIGNAL ;
    PORT
      LAYER M4 ;
        RECT  0 22.32 0.084 22.344 ;
    END
  END a[470]
  PIN a[471]
    DIRECTION INPUT ;
    USE SIGNAL ;
    PORT
      LAYER M4 ;
        RECT  0 22.464 0.084 22.488 ;
    END
  END a[471]
  PIN a[472]
    DIRECTION INPUT ;
    USE SIGNAL ;
    PORT
      LAYER M4 ;
        RECT  0 22.608 0.084 22.632 ;
    END
  END a[472]
  PIN a[473]
    DIRECTION INPUT ;
    USE SIGNAL ;
    PORT
      LAYER M4 ;
        RECT  0 22.752 0.084 22.776 ;
    END
  END a[473]
  PIN a[474]
    DIRECTION INPUT ;
    USE SIGNAL ;
    PORT
      LAYER M4 ;
        RECT  0 22.896 0.084 22.92 ;
    END
  END a[474]
  PIN a[475]
    DIRECTION INPUT ;
    USE SIGNAL ;
    PORT
      LAYER M4 ;
        RECT  0 23.04 0.084 23.064 ;
    END
  END a[475]
  PIN a[476]
    DIRECTION INPUT ;
    USE SIGNAL ;
    PORT
      LAYER M4 ;
        RECT  0 23.184 0.084 23.208 ;
    END
  END a[476]
  PIN a[477]
    DIRECTION INPUT ;
    USE SIGNAL ;
    PORT
      LAYER M4 ;
        RECT  0 23.328 0.084 23.352 ;
    END
  END a[477]
  PIN a[478]
    DIRECTION INPUT ;
    USE SIGNAL ;
    PORT
      LAYER M4 ;
        RECT  0 23.472 0.084 23.496 ;
    END
  END a[478]
  PIN a[479]
    DIRECTION INPUT ;
    USE SIGNAL ;
    PORT
      LAYER M4 ;
        RECT  0 23.616 0.084 23.64 ;
    END
  END a[479]
  PIN a[47]
    DIRECTION INPUT ;
    USE SIGNAL ;
    PORT
      LAYER M4 ;
        RECT  0 36.288 0.084 36.312 ;
    END
  END a[47]
  PIN a[480]
    DIRECTION INPUT ;
    USE SIGNAL ;
    PORT
      LAYER M4 ;
        RECT  0 14.544 0.084 14.568 ;
    END
  END a[480]
  PIN a[481]
    DIRECTION INPUT ;
    USE SIGNAL ;
    PORT
      LAYER M4 ;
        RECT  0 14.688 0.084 14.712 ;
    END
  END a[481]
  PIN a[482]
    DIRECTION INPUT ;
    USE SIGNAL ;
    PORT
      LAYER M4 ;
        RECT  0 14.832 0.084 14.856 ;
    END
  END a[482]
  PIN a[483]
    DIRECTION INPUT ;
    USE SIGNAL ;
    PORT
      LAYER M4 ;
        RECT  0 14.976 0.084 15 ;
    END
  END a[483]
  PIN a[484]
    DIRECTION INPUT ;
    USE SIGNAL ;
    PORT
      LAYER M4 ;
        RECT  0 15.12 0.084 15.144 ;
    END
  END a[484]
  PIN a[485]
    DIRECTION INPUT ;
    USE SIGNAL ;
    PORT
      LAYER M4 ;
        RECT  0 15.264 0.084 15.288 ;
    END
  END a[485]
  PIN a[486]
    DIRECTION INPUT ;
    USE SIGNAL ;
    PORT
      LAYER M4 ;
        RECT  0 15.408 0.084 15.432 ;
    END
  END a[486]
  PIN a[487]
    DIRECTION INPUT ;
    USE SIGNAL ;
    PORT
      LAYER M4 ;
        RECT  0 15.552 0.084 15.576 ;
    END
  END a[487]
  PIN a[488]
    DIRECTION INPUT ;
    USE SIGNAL ;
    PORT
      LAYER M4 ;
        RECT  0 15.696 0.084 15.72 ;
    END
  END a[488]
  PIN a[489]
    DIRECTION INPUT ;
    USE SIGNAL ;
    PORT
      LAYER M4 ;
        RECT  0 15.84 0.084 15.864 ;
    END
  END a[489]
  PIN a[48]
    DIRECTION INPUT ;
    USE SIGNAL ;
    PORT
      LAYER M4 ;
        RECT  0 36.432 0.084 36.456 ;
    END
  END a[48]
  PIN a[490]
    DIRECTION INPUT ;
    USE SIGNAL ;
    PORT
      LAYER M4 ;
        RECT  0 15.984 0.084 16.008 ;
    END
  END a[490]
  PIN a[491]
    DIRECTION INPUT ;
    USE SIGNAL ;
    PORT
      LAYER M4 ;
        RECT  0 16.128 0.084 16.152 ;
    END
  END a[491]
  PIN a[492]
    DIRECTION INPUT ;
    USE SIGNAL ;
    PORT
      LAYER M4 ;
        RECT  0 16.272 0.084 16.296 ;
    END
  END a[492]
  PIN a[493]
    DIRECTION INPUT ;
    USE SIGNAL ;
    PORT
      LAYER M4 ;
        RECT  0 16.416 0.084 16.44 ;
    END
  END a[493]
  PIN a[494]
    DIRECTION INPUT ;
    USE SIGNAL ;
    PORT
      LAYER M4 ;
        RECT  0 16.56 0.084 16.584 ;
    END
  END a[494]
  PIN a[495]
    DIRECTION INPUT ;
    USE SIGNAL ;
    PORT
      LAYER M4 ;
        RECT  0 16.704 0.084 16.728 ;
    END
  END a[495]
  PIN a[496]
    DIRECTION INPUT ;
    USE SIGNAL ;
    PORT
      LAYER M4 ;
        RECT  0 16.848 0.084 16.872 ;
    END
  END a[496]
  PIN a[497]
    DIRECTION INPUT ;
    USE SIGNAL ;
    PORT
      LAYER M4 ;
        RECT  0 16.992 0.084 17.016 ;
    END
  END a[497]
  PIN a[498]
    DIRECTION INPUT ;
    USE SIGNAL ;
    PORT
      LAYER M4 ;
        RECT  0 17.136 0.084 17.16 ;
    END
  END a[498]
  PIN a[499]
    DIRECTION INPUT ;
    USE SIGNAL ;
    PORT
      LAYER M4 ;
        RECT  0 17.28 0.084 17.304 ;
    END
  END a[499]
  PIN a[49]
    DIRECTION INPUT ;
    USE SIGNAL ;
    PORT
      LAYER M4 ;
        RECT  0 36.576 0.084 36.6 ;
    END
  END a[49]
  PIN a[4]
    DIRECTION INPUT ;
    USE SIGNAL ;
    PORT
      LAYER M4 ;
        RECT  0 48.528 0.084 48.552 ;
    END
  END a[4]
  PIN a[500]
    DIRECTION INPUT ;
    USE SIGNAL ;
    PORT
      LAYER M4 ;
        RECT  0 17.424 0.084 17.448 ;
    END
  END a[500]
  PIN a[501]
    DIRECTION INPUT ;
    USE SIGNAL ;
    PORT
      LAYER M4 ;
        RECT  0 17.568 0.084 17.592 ;
    END
  END a[501]
  PIN a[502]
    DIRECTION INPUT ;
    USE SIGNAL ;
    PORT
      LAYER M4 ;
        RECT  0 17.712 0.084 17.736 ;
    END
  END a[502]
  PIN a[503]
    DIRECTION INPUT ;
    USE SIGNAL ;
    PORT
      LAYER M4 ;
        RECT  0 17.856 0.084 17.88 ;
    END
  END a[503]
  PIN a[504]
    DIRECTION INPUT ;
    USE SIGNAL ;
    PORT
      LAYER M4 ;
        RECT  0 18 0.084 18.024 ;
    END
  END a[504]
  PIN a[505]
    DIRECTION INPUT ;
    USE SIGNAL ;
    PORT
      LAYER M4 ;
        RECT  0 18.144 0.084 18.168 ;
    END
  END a[505]
  PIN a[506]
    DIRECTION INPUT ;
    USE SIGNAL ;
    PORT
      LAYER M4 ;
        RECT  0 18.288 0.084 18.312 ;
    END
  END a[506]
  PIN a[507]
    DIRECTION INPUT ;
    USE SIGNAL ;
    PORT
      LAYER M4 ;
        RECT  0 18.432 0.084 18.456 ;
    END
  END a[507]
  PIN a[508]
    DIRECTION INPUT ;
    USE SIGNAL ;
    PORT
      LAYER M4 ;
        RECT  0 18.576 0.084 18.6 ;
    END
  END a[508]
  PIN a[509]
    DIRECTION INPUT ;
    USE SIGNAL ;
    PORT
      LAYER M4 ;
        RECT  0 18.72 0.084 18.744 ;
    END
  END a[509]
  PIN a[50]
    DIRECTION INPUT ;
    USE SIGNAL ;
    PORT
      LAYER M4 ;
        RECT  0 36.72 0.084 36.744 ;
    END
  END a[50]
  PIN a[510]
    DIRECTION INPUT ;
    USE SIGNAL ;
    PORT
      LAYER M4 ;
        RECT  0 18.864 0.084 18.888 ;
    END
  END a[510]
  PIN a[511]
    DIRECTION INPUT ;
    USE SIGNAL ;
    PORT
      LAYER M4 ;
        RECT  0 19.008 0.084 19.032 ;
    END
  END a[511]
  PIN a[512]
    DIRECTION INPUT ;
    USE SIGNAL ;
    PORT
      LAYER M4 ;
        RECT  0 3.024 0.084 3.048 ;
    END
  END a[512]
  PIN a[513]
    DIRECTION INPUT ;
    USE SIGNAL ;
    PORT
      LAYER M4 ;
        RECT  0 3.168 0.084 3.192 ;
    END
  END a[513]
  PIN a[514]
    DIRECTION INPUT ;
    USE SIGNAL ;
    PORT
      LAYER M4 ;
        RECT  0 3.312 0.084 3.336 ;
    END
  END a[514]
  PIN a[515]
    DIRECTION INPUT ;
    USE SIGNAL ;
    PORT
      LAYER M4 ;
        RECT  0 3.456 0.084 3.48 ;
    END
  END a[515]
  PIN a[516]
    DIRECTION INPUT ;
    USE SIGNAL ;
    PORT
      LAYER M4 ;
        RECT  0 3.6 0.084 3.624 ;
    END
  END a[516]
  PIN a[517]
    DIRECTION INPUT ;
    USE SIGNAL ;
    PORT
      LAYER M4 ;
        RECT  0 3.744 0.084 3.768 ;
    END
  END a[517]
  PIN a[518]
    DIRECTION INPUT ;
    USE SIGNAL ;
    PORT
      LAYER M4 ;
        RECT  0 3.888 0.084 3.912 ;
    END
  END a[518]
  PIN a[519]
    DIRECTION INPUT ;
    USE SIGNAL ;
    PORT
      LAYER M4 ;
        RECT  0 4.032 0.084 4.056 ;
    END
  END a[519]
  PIN a[51]
    DIRECTION INPUT ;
    USE SIGNAL ;
    PORT
      LAYER M4 ;
        RECT  0 36.864 0.084 36.888 ;
    END
  END a[51]
  PIN a[520]
    DIRECTION INPUT ;
    USE SIGNAL ;
    PORT
      LAYER M4 ;
        RECT  0 4.176 0.084 4.2 ;
    END
  END a[520]
  PIN a[521]
    DIRECTION INPUT ;
    USE SIGNAL ;
    PORT
      LAYER M4 ;
        RECT  0 4.32 0.084 4.344 ;
    END
  END a[521]
  PIN a[522]
    DIRECTION INPUT ;
    USE SIGNAL ;
    PORT
      LAYER M4 ;
        RECT  0 4.464 0.084 4.488 ;
    END
  END a[522]
  PIN a[523]
    DIRECTION INPUT ;
    USE SIGNAL ;
    PORT
      LAYER M4 ;
        RECT  0 4.608 0.084 4.632 ;
    END
  END a[523]
  PIN a[524]
    DIRECTION INPUT ;
    USE SIGNAL ;
    PORT
      LAYER M4 ;
        RECT  0 4.752 0.084 4.776 ;
    END
  END a[524]
  PIN a[525]
    DIRECTION INPUT ;
    USE SIGNAL ;
    PORT
      LAYER M4 ;
        RECT  0 4.896 0.084 4.92 ;
    END
  END a[525]
  PIN a[526]
    DIRECTION INPUT ;
    USE SIGNAL ;
    PORT
      LAYER M4 ;
        RECT  0 5.04 0.084 5.064 ;
    END
  END a[526]
  PIN a[527]
    DIRECTION INPUT ;
    USE SIGNAL ;
    PORT
      LAYER M4 ;
        RECT  0 5.184 0.084 5.208 ;
    END
  END a[527]
  PIN a[52]
    DIRECTION INPUT ;
    USE SIGNAL ;
    PORT
      LAYER M4 ;
        RECT  0 37.008 0.084 37.032 ;
    END
  END a[52]
  PIN a[53]
    DIRECTION INPUT ;
    USE SIGNAL ;
    PORT
      LAYER M4 ;
        RECT  0 37.152 0.084 37.176 ;
    END
  END a[53]
  PIN a[54]
    DIRECTION INPUT ;
    USE SIGNAL ;
    PORT
      LAYER M4 ;
        RECT  0 37.296 0.084 37.32 ;
    END
  END a[54]
  PIN a[55]
    DIRECTION INPUT ;
    USE SIGNAL ;
    PORT
      LAYER M4 ;
        RECT  0 37.44 0.084 37.464 ;
    END
  END a[55]
  PIN a[56]
    DIRECTION INPUT ;
    USE SIGNAL ;
    PORT
      LAYER M4 ;
        RECT  0 37.584 0.084 37.608 ;
    END
  END a[56]
  PIN a[57]
    DIRECTION INPUT ;
    USE SIGNAL ;
    PORT
      LAYER M4 ;
        RECT  0 37.728 0.084 37.752 ;
    END
  END a[57]
  PIN a[58]
    DIRECTION INPUT ;
    USE SIGNAL ;
    PORT
      LAYER M4 ;
        RECT  0 37.872 0.084 37.896 ;
    END
  END a[58]
  PIN a[59]
    DIRECTION INPUT ;
    USE SIGNAL ;
    PORT
      LAYER M4 ;
        RECT  0 38.016 0.084 38.04 ;
    END
  END a[59]
  PIN a[5]
    DIRECTION INPUT ;
    USE SIGNAL ;
    PORT
      LAYER M4 ;
        RECT  0 48.672 0.084 48.696 ;
    END
  END a[5]
  PIN a[60]
    DIRECTION INPUT ;
    USE SIGNAL ;
    PORT
      LAYER M4 ;
        RECT  0 38.16 0.084 38.184 ;
    END
  END a[60]
  PIN a[61]
    DIRECTION INPUT ;
    USE SIGNAL ;
    PORT
      LAYER M4 ;
        RECT  0 38.304 0.084 38.328 ;
    END
  END a[61]
  PIN a[62]
    DIRECTION INPUT ;
    USE SIGNAL ;
    PORT
      LAYER M4 ;
        RECT  0 38.448 0.084 38.472 ;
    END
  END a[62]
  PIN a[63]
    DIRECTION INPUT ;
    USE SIGNAL ;
    PORT
      LAYER M4 ;
        RECT  0 38.592 0.084 38.616 ;
    END
  END a[63]
  PIN a[64]
    DIRECTION INPUT ;
    USE SIGNAL ;
    PORT
      LAYER M4 ;
        RECT  0 29.52 0.084 29.544 ;
    END
  END a[64]
  PIN a[65]
    DIRECTION INPUT ;
    USE SIGNAL ;
    PORT
      LAYER M4 ;
        RECT  0 29.664 0.084 29.688 ;
    END
  END a[65]
  PIN a[66]
    DIRECTION INPUT ;
    USE SIGNAL ;
    PORT
      LAYER M4 ;
        RECT  0 29.808 0.084 29.832 ;
    END
  END a[66]
  PIN a[67]
    DIRECTION INPUT ;
    USE SIGNAL ;
    PORT
      LAYER M4 ;
        RECT  0 29.952 0.084 29.976 ;
    END
  END a[67]
  PIN a[68]
    DIRECTION INPUT ;
    USE SIGNAL ;
    PORT
      LAYER M4 ;
        RECT  0 30.096 0.084 30.12 ;
    END
  END a[68]
  PIN a[69]
    DIRECTION INPUT ;
    USE SIGNAL ;
    PORT
      LAYER M4 ;
        RECT  0 30.24 0.084 30.264 ;
    END
  END a[69]
  PIN a[6]
    DIRECTION INPUT ;
    USE SIGNAL ;
    PORT
      LAYER M4 ;
        RECT  0 48.816 0.084 48.84 ;
    END
  END a[6]
  PIN a[70]
    DIRECTION INPUT ;
    USE SIGNAL ;
    PORT
      LAYER M4 ;
        RECT  0 30.384 0.084 30.408 ;
    END
  END a[70]
  PIN a[71]
    DIRECTION INPUT ;
    USE SIGNAL ;
    PORT
      LAYER M4 ;
        RECT  0 30.528 0.084 30.552 ;
    END
  END a[71]
  PIN a[72]
    DIRECTION INPUT ;
    USE SIGNAL ;
    PORT
      LAYER M4 ;
        RECT  0 30.672 0.084 30.696 ;
    END
  END a[72]
  PIN a[73]
    DIRECTION INPUT ;
    USE SIGNAL ;
    PORT
      LAYER M4 ;
        RECT  0 30.816 0.084 30.84 ;
    END
  END a[73]
  PIN a[74]
    DIRECTION INPUT ;
    USE SIGNAL ;
    PORT
      LAYER M4 ;
        RECT  0 30.96 0.084 30.984 ;
    END
  END a[74]
  PIN a[75]
    DIRECTION INPUT ;
    USE SIGNAL ;
    PORT
      LAYER M4 ;
        RECT  0 31.104 0.084 31.128 ;
    END
  END a[75]
  PIN a[76]
    DIRECTION INPUT ;
    USE SIGNAL ;
    PORT
      LAYER M4 ;
        RECT  0 31.248 0.084 31.272 ;
    END
  END a[76]
  PIN a[77]
    DIRECTION INPUT ;
    USE SIGNAL ;
    PORT
      LAYER M4 ;
        RECT  0 31.392 0.084 31.416 ;
    END
  END a[77]
  PIN a[78]
    DIRECTION INPUT ;
    USE SIGNAL ;
    PORT
      LAYER M4 ;
        RECT  0 31.536 0.084 31.56 ;
    END
  END a[78]
  PIN a[79]
    DIRECTION INPUT ;
    USE SIGNAL ;
    PORT
      LAYER M4 ;
        RECT  0 31.68 0.084 31.704 ;
    END
  END a[79]
  PIN a[7]
    DIRECTION INPUT ;
    USE SIGNAL ;
    PORT
      LAYER M4 ;
        RECT  0 48.96 0.084 48.984 ;
    END
  END a[7]
  PIN a[80]
    DIRECTION INPUT ;
    USE SIGNAL ;
    PORT
      LAYER M4 ;
        RECT  0 31.824 0.084 31.848 ;
    END
  END a[80]
  PIN a[81]
    DIRECTION INPUT ;
    USE SIGNAL ;
    PORT
      LAYER M4 ;
        RECT  0 31.968 0.084 31.992 ;
    END
  END a[81]
  PIN a[82]
    DIRECTION INPUT ;
    USE SIGNAL ;
    PORT
      LAYER M4 ;
        RECT  0 32.112 0.084 32.136 ;
    END
  END a[82]
  PIN a[83]
    DIRECTION INPUT ;
    USE SIGNAL ;
    PORT
      LAYER M4 ;
        RECT  0 32.256 0.084 32.28 ;
    END
  END a[83]
  PIN a[84]
    DIRECTION INPUT ;
    USE SIGNAL ;
    PORT
      LAYER M4 ;
        RECT  0 32.4 0.084 32.424 ;
    END
  END a[84]
  PIN a[85]
    DIRECTION INPUT ;
    USE SIGNAL ;
    PORT
      LAYER M4 ;
        RECT  0 32.544 0.084 32.568 ;
    END
  END a[85]
  PIN a[86]
    DIRECTION INPUT ;
    USE SIGNAL ;
    PORT
      LAYER M4 ;
        RECT  0 32.688 0.084 32.712 ;
    END
  END a[86]
  PIN a[87]
    DIRECTION INPUT ;
    USE SIGNAL ;
    PORT
      LAYER M4 ;
        RECT  0 32.832 0.084 32.856 ;
    END
  END a[87]
  PIN a[88]
    DIRECTION INPUT ;
    USE SIGNAL ;
    PORT
      LAYER M4 ;
        RECT  0 32.976 0.084 33 ;
    END
  END a[88]
  PIN a[89]
    DIRECTION INPUT ;
    USE SIGNAL ;
    PORT
      LAYER M4 ;
        RECT  0 33.12 0.084 33.144 ;
    END
  END a[89]
  PIN a[8]
    DIRECTION INPUT ;
    USE SIGNAL ;
    PORT
      LAYER M4 ;
        RECT  0 49.104 0.084 49.128 ;
    END
  END a[8]
  PIN a[90]
    DIRECTION INPUT ;
    USE SIGNAL ;
    PORT
      LAYER M4 ;
        RECT  0 33.264 0.084 33.288 ;
    END
  END a[90]
  PIN a[91]
    DIRECTION INPUT ;
    USE SIGNAL ;
    PORT
      LAYER M4 ;
        RECT  0 33.408 0.084 33.432 ;
    END
  END a[91]
  PIN a[92]
    DIRECTION INPUT ;
    USE SIGNAL ;
    PORT
      LAYER M4 ;
        RECT  0 33.552 0.084 33.576 ;
    END
  END a[92]
  PIN a[93]
    DIRECTION INPUT ;
    USE SIGNAL ;
    PORT
      LAYER M4 ;
        RECT  0 33.696 0.084 33.72 ;
    END
  END a[93]
  PIN a[94]
    DIRECTION INPUT ;
    USE SIGNAL ;
    PORT
      LAYER M4 ;
        RECT  0 33.84 0.084 33.864 ;
    END
  END a[94]
  PIN a[95]
    DIRECTION INPUT ;
    USE SIGNAL ;
    PORT
      LAYER M4 ;
        RECT  0 33.984 0.084 34.008 ;
    END
  END a[95]
  PIN a[96]
    DIRECTION INPUT ;
    USE SIGNAL ;
    PORT
      LAYER M4 ;
        RECT  0 38.736 0.084 38.76 ;
    END
  END a[96]
  PIN a[97]
    DIRECTION INPUT ;
    USE SIGNAL ;
    PORT
      LAYER M4 ;
        RECT  0 38.88 0.084 38.904 ;
    END
  END a[97]
  PIN a[98]
    DIRECTION INPUT ;
    USE SIGNAL ;
    PORT
      LAYER M4 ;
        RECT  0 39.024 0.084 39.048 ;
    END
  END a[98]
  PIN a[99]
    DIRECTION INPUT ;
    USE SIGNAL ;
    PORT
      LAYER M4 ;
        RECT  0 39.168 0.084 39.192 ;
    END
  END a[99]
  PIN a[9]
    DIRECTION INPUT ;
    USE SIGNAL ;
    PORT
      LAYER M4 ;
        RECT  0 49.248 0.084 49.272 ;
    END
  END a[9]
  PIN b[0]
    DIRECTION OUTPUT ;
    USE SIGNAL ;
    PORT
      LAYER M4 ;
        RECT  21.516 52.56 21.6 52.584 ;
    END
  END b[0]
  PIN b[100]
    DIRECTION OUTPUT ;
    USE SIGNAL ;
    PORT
      LAYER M4 ;
        RECT  21.516 43.92 21.6 43.944 ;
    END
  END b[100]
  PIN b[101]
    DIRECTION OUTPUT ;
    USE SIGNAL ;
    PORT
      LAYER M4 ;
        RECT  21.516 44.064 21.6 44.088 ;
    END
  END b[101]
  PIN b[102]
    DIRECTION OUTPUT ;
    USE SIGNAL ;
    PORT
      LAYER M4 ;
        RECT  21.516 44.208 21.6 44.232 ;
    END
  END b[102]
  PIN b[103]
    DIRECTION OUTPUT ;
    USE SIGNAL ;
    PORT
      LAYER M4 ;
        RECT  21.516 44.352 21.6 44.376 ;
    END
  END b[103]
  PIN b[104]
    DIRECTION OUTPUT ;
    USE SIGNAL ;
    PORT
      LAYER M4 ;
        RECT  21.516 44.496 21.6 44.52 ;
    END
  END b[104]
  PIN b[105]
    DIRECTION OUTPUT ;
    USE SIGNAL ;
    PORT
      LAYER M4 ;
        RECT  21.516 44.64 21.6 44.664 ;
    END
  END b[105]
  PIN b[106]
    DIRECTION OUTPUT ;
    USE SIGNAL ;
    PORT
      LAYER M4 ;
        RECT  21.516 44.784 21.6 44.808 ;
    END
  END b[106]
  PIN b[107]
    DIRECTION OUTPUT ;
    USE SIGNAL ;
    PORT
      LAYER M4 ;
        RECT  21.516 44.928 21.6 44.952 ;
    END
  END b[107]
  PIN b[108]
    DIRECTION OUTPUT ;
    USE SIGNAL ;
    PORT
      LAYER M4 ;
        RECT  21.516 45.072 21.6 45.096 ;
    END
  END b[108]
  PIN b[109]
    DIRECTION OUTPUT ;
    USE SIGNAL ;
    PORT
      LAYER M4 ;
        RECT  21.516 45.216 21.6 45.24 ;
    END
  END b[109]
  PIN b[10]
    DIRECTION OUTPUT ;
    USE SIGNAL ;
    PORT
      LAYER M4 ;
        RECT  21.516 54 21.6 54.024 ;
    END
  END b[10]
  PIN b[110]
    DIRECTION OUTPUT ;
    USE SIGNAL ;
    PORT
      LAYER M4 ;
        RECT  21.516 45.36 21.6 45.384 ;
    END
  END b[110]
  PIN b[111]
    DIRECTION OUTPUT ;
    USE SIGNAL ;
    PORT
      LAYER M4 ;
        RECT  21.516 45.504 21.6 45.528 ;
    END
  END b[111]
  PIN b[112]
    DIRECTION OUTPUT ;
    USE SIGNAL ;
    PORT
      LAYER M4 ;
        RECT  21.516 45.648 21.6 45.672 ;
    END
  END b[112]
  PIN b[113]
    DIRECTION OUTPUT ;
    USE SIGNAL ;
    PORT
      LAYER M4 ;
        RECT  21.516 45.792 21.6 45.816 ;
    END
  END b[113]
  PIN b[114]
    DIRECTION OUTPUT ;
    USE SIGNAL ;
    PORT
      LAYER M4 ;
        RECT  21.516 45.936 21.6 45.96 ;
    END
  END b[114]
  PIN b[115]
    DIRECTION OUTPUT ;
    USE SIGNAL ;
    PORT
      LAYER M4 ;
        RECT  21.516 46.08 21.6 46.104 ;
    END
  END b[115]
  PIN b[116]
    DIRECTION OUTPUT ;
    USE SIGNAL ;
    PORT
      LAYER M4 ;
        RECT  21.516 46.224 21.6 46.248 ;
    END
  END b[116]
  PIN b[117]
    DIRECTION OUTPUT ;
    USE SIGNAL ;
    PORT
      LAYER M4 ;
        RECT  21.516 46.368 21.6 46.392 ;
    END
  END b[117]
  PIN b[118]
    DIRECTION OUTPUT ;
    USE SIGNAL ;
    PORT
      LAYER M4 ;
        RECT  21.516 46.512 21.6 46.536 ;
    END
  END b[118]
  PIN b[119]
    DIRECTION OUTPUT ;
    USE SIGNAL ;
    PORT
      LAYER M4 ;
        RECT  21.516 46.656 21.6 46.68 ;
    END
  END b[119]
  PIN b[11]
    DIRECTION OUTPUT ;
    USE SIGNAL ;
    PORT
      LAYER M4 ;
        RECT  21.516 54.144 21.6 54.168 ;
    END
  END b[11]
  PIN b[120]
    DIRECTION OUTPUT ;
    USE SIGNAL ;
    PORT
      LAYER M4 ;
        RECT  21.516 46.8 21.6 46.824 ;
    END
  END b[120]
  PIN b[121]
    DIRECTION OUTPUT ;
    USE SIGNAL ;
    PORT
      LAYER M4 ;
        RECT  21.516 46.944 21.6 46.968 ;
    END
  END b[121]
  PIN b[122]
    DIRECTION OUTPUT ;
    USE SIGNAL ;
    PORT
      LAYER M4 ;
        RECT  21.516 47.088 21.6 47.112 ;
    END
  END b[122]
  PIN b[123]
    DIRECTION OUTPUT ;
    USE SIGNAL ;
    PORT
      LAYER M4 ;
        RECT  21.516 47.232 21.6 47.256 ;
    END
  END b[123]
  PIN b[124]
    DIRECTION OUTPUT ;
    USE SIGNAL ;
    PORT
      LAYER M4 ;
        RECT  21.516 47.376 21.6 47.4 ;
    END
  END b[124]
  PIN b[125]
    DIRECTION OUTPUT ;
    USE SIGNAL ;
    PORT
      LAYER M4 ;
        RECT  21.516 47.52 21.6 47.544 ;
    END
  END b[125]
  PIN b[126]
    DIRECTION OUTPUT ;
    USE SIGNAL ;
    PORT
      LAYER M4 ;
        RECT  21.516 47.664 21.6 47.688 ;
    END
  END b[126]
  PIN b[127]
    DIRECTION OUTPUT ;
    USE SIGNAL ;
    PORT
      LAYER M4 ;
        RECT  21.516 47.808 21.6 47.832 ;
    END
  END b[127]
  PIN b[128]
    DIRECTION OUTPUT ;
    USE SIGNAL ;
    PORT
      LAYER M4 ;
        RECT  21.516 29.52 21.6 29.544 ;
    END
  END b[128]
  PIN b[129]
    DIRECTION OUTPUT ;
    USE SIGNAL ;
    PORT
      LAYER M4 ;
        RECT  21.516 29.664 21.6 29.688 ;
    END
  END b[129]
  PIN b[12]
    DIRECTION OUTPUT ;
    USE SIGNAL ;
    PORT
      LAYER M4 ;
        RECT  21.516 54.288 21.6 54.312 ;
    END
  END b[12]
  PIN b[130]
    DIRECTION OUTPUT ;
    USE SIGNAL ;
    PORT
      LAYER M4 ;
        RECT  21.516 29.808 21.6 29.832 ;
    END
  END b[130]
  PIN b[131]
    DIRECTION OUTPUT ;
    USE SIGNAL ;
    PORT
      LAYER M4 ;
        RECT  21.516 29.952 21.6 29.976 ;
    END
  END b[131]
  PIN b[132]
    DIRECTION OUTPUT ;
    USE SIGNAL ;
    PORT
      LAYER M4 ;
        RECT  21.516 30.096 21.6 30.12 ;
    END
  END b[132]
  PIN b[133]
    DIRECTION OUTPUT ;
    USE SIGNAL ;
    PORT
      LAYER M4 ;
        RECT  21.516 30.24 21.6 30.264 ;
    END
  END b[133]
  PIN b[134]
    DIRECTION OUTPUT ;
    USE SIGNAL ;
    PORT
      LAYER M4 ;
        RECT  21.516 30.384 21.6 30.408 ;
    END
  END b[134]
  PIN b[135]
    DIRECTION OUTPUT ;
    USE SIGNAL ;
    PORT
      LAYER M4 ;
        RECT  21.516 30.528 21.6 30.552 ;
    END
  END b[135]
  PIN b[136]
    DIRECTION OUTPUT ;
    USE SIGNAL ;
    PORT
      LAYER M4 ;
        RECT  21.516 30.672 21.6 30.696 ;
    END
  END b[136]
  PIN b[137]
    DIRECTION OUTPUT ;
    USE SIGNAL ;
    PORT
      LAYER M4 ;
        RECT  21.516 30.816 21.6 30.84 ;
    END
  END b[137]
  PIN b[138]
    DIRECTION OUTPUT ;
    USE SIGNAL ;
    PORT
      LAYER M4 ;
        RECT  21.516 30.96 21.6 30.984 ;
    END
  END b[138]
  PIN b[139]
    DIRECTION OUTPUT ;
    USE SIGNAL ;
    PORT
      LAYER M4 ;
        RECT  21.516 31.104 21.6 31.128 ;
    END
  END b[139]
  PIN b[13]
    DIRECTION OUTPUT ;
    USE SIGNAL ;
    PORT
      LAYER M4 ;
        RECT  21.516 54.432 21.6 54.456 ;
    END
  END b[13]
  PIN b[140]
    DIRECTION OUTPUT ;
    USE SIGNAL ;
    PORT
      LAYER M4 ;
        RECT  21.516 31.248 21.6 31.272 ;
    END
  END b[140]
  PIN b[141]
    DIRECTION OUTPUT ;
    USE SIGNAL ;
    PORT
      LAYER M4 ;
        RECT  21.516 31.392 21.6 31.416 ;
    END
  END b[141]
  PIN b[142]
    DIRECTION OUTPUT ;
    USE SIGNAL ;
    PORT
      LAYER M4 ;
        RECT  21.516 31.536 21.6 31.56 ;
    END
  END b[142]
  PIN b[143]
    DIRECTION OUTPUT ;
    USE SIGNAL ;
    PORT
      LAYER M4 ;
        RECT  21.516 31.68 21.6 31.704 ;
    END
  END b[143]
  PIN b[144]
    DIRECTION OUTPUT ;
    USE SIGNAL ;
    PORT
      LAYER M4 ;
        RECT  21.516 31.824 21.6 31.848 ;
    END
  END b[144]
  PIN b[145]
    DIRECTION OUTPUT ;
    USE SIGNAL ;
    PORT
      LAYER M4 ;
        RECT  21.516 31.968 21.6 31.992 ;
    END
  END b[145]
  PIN b[146]
    DIRECTION OUTPUT ;
    USE SIGNAL ;
    PORT
      LAYER M4 ;
        RECT  21.516 32.112 21.6 32.136 ;
    END
  END b[146]
  PIN b[147]
    DIRECTION OUTPUT ;
    USE SIGNAL ;
    PORT
      LAYER M4 ;
        RECT  21.516 32.256 21.6 32.28 ;
    END
  END b[147]
  PIN b[148]
    DIRECTION OUTPUT ;
    USE SIGNAL ;
    PORT
      LAYER M4 ;
        RECT  21.516 32.4 21.6 32.424 ;
    END
  END b[148]
  PIN b[149]
    DIRECTION OUTPUT ;
    USE SIGNAL ;
    PORT
      LAYER M4 ;
        RECT  21.516 32.544 21.6 32.568 ;
    END
  END b[149]
  PIN b[14]
    DIRECTION OUTPUT ;
    USE SIGNAL ;
    PORT
      LAYER M4 ;
        RECT  21.516 54.576 21.6 54.6 ;
    END
  END b[14]
  PIN b[150]
    DIRECTION OUTPUT ;
    USE SIGNAL ;
    PORT
      LAYER M4 ;
        RECT  21.516 32.688 21.6 32.712 ;
    END
  END b[150]
  PIN b[151]
    DIRECTION OUTPUT ;
    USE SIGNAL ;
    PORT
      LAYER M4 ;
        RECT  21.516 32.832 21.6 32.856 ;
    END
  END b[151]
  PIN b[152]
    DIRECTION OUTPUT ;
    USE SIGNAL ;
    PORT
      LAYER M4 ;
        RECT  21.516 32.976 21.6 33 ;
    END
  END b[152]
  PIN b[153]
    DIRECTION OUTPUT ;
    USE SIGNAL ;
    PORT
      LAYER M4 ;
        RECT  21.516 33.12 21.6 33.144 ;
    END
  END b[153]
  PIN b[154]
    DIRECTION OUTPUT ;
    USE SIGNAL ;
    PORT
      LAYER M4 ;
        RECT  21.516 33.264 21.6 33.288 ;
    END
  END b[154]
  PIN b[155]
    DIRECTION OUTPUT ;
    USE SIGNAL ;
    PORT
      LAYER M4 ;
        RECT  21.516 33.408 21.6 33.432 ;
    END
  END b[155]
  PIN b[156]
    DIRECTION OUTPUT ;
    USE SIGNAL ;
    PORT
      LAYER M4 ;
        RECT  21.516 33.552 21.6 33.576 ;
    END
  END b[156]
  PIN b[157]
    DIRECTION OUTPUT ;
    USE SIGNAL ;
    PORT
      LAYER M4 ;
        RECT  21.516 33.696 21.6 33.72 ;
    END
  END b[157]
  PIN b[158]
    DIRECTION OUTPUT ;
    USE SIGNAL ;
    PORT
      LAYER M4 ;
        RECT  21.516 33.84 21.6 33.864 ;
    END
  END b[158]
  PIN b[159]
    DIRECTION OUTPUT ;
    USE SIGNAL ;
    PORT
      LAYER M4 ;
        RECT  21.516 33.984 21.6 34.008 ;
    END
  END b[159]
  PIN b[15]
    DIRECTION OUTPUT ;
    USE SIGNAL ;
    PORT
      LAYER M4 ;
        RECT  21.516 54.72 21.6 54.744 ;
    END
  END b[15]
  PIN b[160]
    DIRECTION OUTPUT ;
    USE SIGNAL ;
    PORT
      LAYER M4 ;
        RECT  21.516 47.952 21.6 47.976 ;
    END
  END b[160]
  PIN b[161]
    DIRECTION OUTPUT ;
    USE SIGNAL ;
    PORT
      LAYER M4 ;
        RECT  21.516 48.096 21.6 48.12 ;
    END
  END b[161]
  PIN b[162]
    DIRECTION OUTPUT ;
    USE SIGNAL ;
    PORT
      LAYER M4 ;
        RECT  21.516 48.24 21.6 48.264 ;
    END
  END b[162]
  PIN b[163]
    DIRECTION OUTPUT ;
    USE SIGNAL ;
    PORT
      LAYER M4 ;
        RECT  21.516 48.384 21.6 48.408 ;
    END
  END b[163]
  PIN b[164]
    DIRECTION OUTPUT ;
    USE SIGNAL ;
    PORT
      LAYER M4 ;
        RECT  21.516 48.528 21.6 48.552 ;
    END
  END b[164]
  PIN b[165]
    DIRECTION OUTPUT ;
    USE SIGNAL ;
    PORT
      LAYER M4 ;
        RECT  21.516 48.672 21.6 48.696 ;
    END
  END b[165]
  PIN b[166]
    DIRECTION OUTPUT ;
    USE SIGNAL ;
    PORT
      LAYER M4 ;
        RECT  21.516 48.816 21.6 48.84 ;
    END
  END b[166]
  PIN b[167]
    DIRECTION OUTPUT ;
    USE SIGNAL ;
    PORT
      LAYER M4 ;
        RECT  21.516 48.96 21.6 48.984 ;
    END
  END b[167]
  PIN b[168]
    DIRECTION OUTPUT ;
    USE SIGNAL ;
    PORT
      LAYER M4 ;
        RECT  21.516 49.104 21.6 49.128 ;
    END
  END b[168]
  PIN b[169]
    DIRECTION OUTPUT ;
    USE SIGNAL ;
    PORT
      LAYER M4 ;
        RECT  21.516 49.248 21.6 49.272 ;
    END
  END b[169]
  PIN b[16]
    DIRECTION OUTPUT ;
    USE SIGNAL ;
    PORT
      LAYER M4 ;
        RECT  21.516 54.864 21.6 54.888 ;
    END
  END b[16]
  PIN b[170]
    DIRECTION OUTPUT ;
    USE SIGNAL ;
    PORT
      LAYER M4 ;
        RECT  21.516 49.392 21.6 49.416 ;
    END
  END b[170]
  PIN b[171]
    DIRECTION OUTPUT ;
    USE SIGNAL ;
    PORT
      LAYER M4 ;
        RECT  21.516 49.536 21.6 49.56 ;
    END
  END b[171]
  PIN b[172]
    DIRECTION OUTPUT ;
    USE SIGNAL ;
    PORT
      LAYER M4 ;
        RECT  21.516 49.68 21.6 49.704 ;
    END
  END b[172]
  PIN b[173]
    DIRECTION OUTPUT ;
    USE SIGNAL ;
    PORT
      LAYER M4 ;
        RECT  21.516 49.824 21.6 49.848 ;
    END
  END b[173]
  PIN b[174]
    DIRECTION OUTPUT ;
    USE SIGNAL ;
    PORT
      LAYER M4 ;
        RECT  21.516 49.968 21.6 49.992 ;
    END
  END b[174]
  PIN b[175]
    DIRECTION OUTPUT ;
    USE SIGNAL ;
    PORT
      LAYER M4 ;
        RECT  21.516 50.112 21.6 50.136 ;
    END
  END b[175]
  PIN b[176]
    DIRECTION OUTPUT ;
    USE SIGNAL ;
    PORT
      LAYER M4 ;
        RECT  21.516 50.256 21.6 50.28 ;
    END
  END b[176]
  PIN b[177]
    DIRECTION OUTPUT ;
    USE SIGNAL ;
    PORT
      LAYER M4 ;
        RECT  21.516 50.4 21.6 50.424 ;
    END
  END b[177]
  PIN b[178]
    DIRECTION OUTPUT ;
    USE SIGNAL ;
    PORT
      LAYER M4 ;
        RECT  21.516 50.544 21.6 50.568 ;
    END
  END b[178]
  PIN b[179]
    DIRECTION OUTPUT ;
    USE SIGNAL ;
    PORT
      LAYER M4 ;
        RECT  21.516 50.688 21.6 50.712 ;
    END
  END b[179]
  PIN b[17]
    DIRECTION OUTPUT ;
    USE SIGNAL ;
    PORT
      LAYER M4 ;
        RECT  21.516 55.008 21.6 55.032 ;
    END
  END b[17]
  PIN b[180]
    DIRECTION OUTPUT ;
    USE SIGNAL ;
    PORT
      LAYER M4 ;
        RECT  21.516 50.832 21.6 50.856 ;
    END
  END b[180]
  PIN b[181]
    DIRECTION OUTPUT ;
    USE SIGNAL ;
    PORT
      LAYER M4 ;
        RECT  21.516 50.976 21.6 51 ;
    END
  END b[181]
  PIN b[182]
    DIRECTION OUTPUT ;
    USE SIGNAL ;
    PORT
      LAYER M4 ;
        RECT  21.516 51.12 21.6 51.144 ;
    END
  END b[182]
  PIN b[183]
    DIRECTION OUTPUT ;
    USE SIGNAL ;
    PORT
      LAYER M4 ;
        RECT  21.516 51.264 21.6 51.288 ;
    END
  END b[183]
  PIN b[184]
    DIRECTION OUTPUT ;
    USE SIGNAL ;
    PORT
      LAYER M4 ;
        RECT  21.516 51.408 21.6 51.432 ;
    END
  END b[184]
  PIN b[185]
    DIRECTION OUTPUT ;
    USE SIGNAL ;
    PORT
      LAYER M4 ;
        RECT  21.516 51.552 21.6 51.576 ;
    END
  END b[185]
  PIN b[186]
    DIRECTION OUTPUT ;
    USE SIGNAL ;
    PORT
      LAYER M4 ;
        RECT  21.516 51.696 21.6 51.72 ;
    END
  END b[186]
  PIN b[187]
    DIRECTION OUTPUT ;
    USE SIGNAL ;
    PORT
      LAYER M4 ;
        RECT  21.516 51.84 21.6 51.864 ;
    END
  END b[187]
  PIN b[188]
    DIRECTION OUTPUT ;
    USE SIGNAL ;
    PORT
      LAYER M4 ;
        RECT  21.516 51.984 21.6 52.008 ;
    END
  END b[188]
  PIN b[189]
    DIRECTION OUTPUT ;
    USE SIGNAL ;
    PORT
      LAYER M4 ;
        RECT  21.516 52.128 21.6 52.152 ;
    END
  END b[189]
  PIN b[18]
    DIRECTION OUTPUT ;
    USE SIGNAL ;
    PORT
      LAYER M4 ;
        RECT  21.516 55.152 21.6 55.176 ;
    END
  END b[18]
  PIN b[190]
    DIRECTION OUTPUT ;
    USE SIGNAL ;
    PORT
      LAYER M4 ;
        RECT  21.516 52.272 21.6 52.296 ;
    END
  END b[190]
  PIN b[191]
    DIRECTION OUTPUT ;
    USE SIGNAL ;
    PORT
      LAYER M4 ;
        RECT  21.516 52.416 21.6 52.44 ;
    END
  END b[191]
  PIN b[192]
    DIRECTION OUTPUT ;
    USE SIGNAL ;
    PORT
      LAYER M4 ;
        RECT  21.516 14.544 21.6 14.568 ;
    END
  END b[192]
  PIN b[193]
    DIRECTION OUTPUT ;
    USE SIGNAL ;
    PORT
      LAYER M4 ;
        RECT  21.516 14.688 21.6 14.712 ;
    END
  END b[193]
  PIN b[194]
    DIRECTION OUTPUT ;
    USE SIGNAL ;
    PORT
      LAYER M4 ;
        RECT  21.516 14.832 21.6 14.856 ;
    END
  END b[194]
  PIN b[195]
    DIRECTION OUTPUT ;
    USE SIGNAL ;
    PORT
      LAYER M4 ;
        RECT  21.516 14.976 21.6 15 ;
    END
  END b[195]
  PIN b[196]
    DIRECTION OUTPUT ;
    USE SIGNAL ;
    PORT
      LAYER M4 ;
        RECT  21.516 15.12 21.6 15.144 ;
    END
  END b[196]
  PIN b[197]
    DIRECTION OUTPUT ;
    USE SIGNAL ;
    PORT
      LAYER M4 ;
        RECT  21.516 15.264 21.6 15.288 ;
    END
  END b[197]
  PIN b[198]
    DIRECTION OUTPUT ;
    USE SIGNAL ;
    PORT
      LAYER M4 ;
        RECT  21.516 15.408 21.6 15.432 ;
    END
  END b[198]
  PIN b[199]
    DIRECTION OUTPUT ;
    USE SIGNAL ;
    PORT
      LAYER M4 ;
        RECT  21.516 15.552 21.6 15.576 ;
    END
  END b[199]
  PIN b[19]
    DIRECTION OUTPUT ;
    USE SIGNAL ;
    PORT
      LAYER M4 ;
        RECT  21.516 55.296 21.6 55.32 ;
    END
  END b[19]
  PIN b[1]
    DIRECTION OUTPUT ;
    USE SIGNAL ;
    PORT
      LAYER M4 ;
        RECT  21.516 52.704 21.6 52.728 ;
    END
  END b[1]
  PIN b[200]
    DIRECTION OUTPUT ;
    USE SIGNAL ;
    PORT
      LAYER M4 ;
        RECT  21.516 15.696 21.6 15.72 ;
    END
  END b[200]
  PIN b[201]
    DIRECTION OUTPUT ;
    USE SIGNAL ;
    PORT
      LAYER M4 ;
        RECT  21.516 15.84 21.6 15.864 ;
    END
  END b[201]
  PIN b[202]
    DIRECTION OUTPUT ;
    USE SIGNAL ;
    PORT
      LAYER M4 ;
        RECT  21.516 15.984 21.6 16.008 ;
    END
  END b[202]
  PIN b[203]
    DIRECTION OUTPUT ;
    USE SIGNAL ;
    PORT
      LAYER M4 ;
        RECT  21.516 16.128 21.6 16.152 ;
    END
  END b[203]
  PIN b[204]
    DIRECTION OUTPUT ;
    USE SIGNAL ;
    PORT
      LAYER M4 ;
        RECT  21.516 16.272 21.6 16.296 ;
    END
  END b[204]
  PIN b[205]
    DIRECTION OUTPUT ;
    USE SIGNAL ;
    PORT
      LAYER M4 ;
        RECT  21.516 16.416 21.6 16.44 ;
    END
  END b[205]
  PIN b[206]
    DIRECTION OUTPUT ;
    USE SIGNAL ;
    PORT
      LAYER M4 ;
        RECT  21.516 16.56 21.6 16.584 ;
    END
  END b[206]
  PIN b[207]
    DIRECTION OUTPUT ;
    USE SIGNAL ;
    PORT
      LAYER M4 ;
        RECT  21.516 16.704 21.6 16.728 ;
    END
  END b[207]
  PIN b[208]
    DIRECTION OUTPUT ;
    USE SIGNAL ;
    PORT
      LAYER M4 ;
        RECT  21.516 16.848 21.6 16.872 ;
    END
  END b[208]
  PIN b[209]
    DIRECTION OUTPUT ;
    USE SIGNAL ;
    PORT
      LAYER M4 ;
        RECT  21.516 16.992 21.6 17.016 ;
    END
  END b[209]
  PIN b[20]
    DIRECTION OUTPUT ;
    USE SIGNAL ;
    PORT
      LAYER M4 ;
        RECT  21.516 55.44 21.6 55.464 ;
    END
  END b[20]
  PIN b[210]
    DIRECTION OUTPUT ;
    USE SIGNAL ;
    PORT
      LAYER M4 ;
        RECT  21.516 17.136 21.6 17.16 ;
    END
  END b[210]
  PIN b[211]
    DIRECTION OUTPUT ;
    USE SIGNAL ;
    PORT
      LAYER M4 ;
        RECT  21.516 17.28 21.6 17.304 ;
    END
  END b[211]
  PIN b[212]
    DIRECTION OUTPUT ;
    USE SIGNAL ;
    PORT
      LAYER M4 ;
        RECT  21.516 17.424 21.6 17.448 ;
    END
  END b[212]
  PIN b[213]
    DIRECTION OUTPUT ;
    USE SIGNAL ;
    PORT
      LAYER M4 ;
        RECT  21.516 17.568 21.6 17.592 ;
    END
  END b[213]
  PIN b[214]
    DIRECTION OUTPUT ;
    USE SIGNAL ;
    PORT
      LAYER M4 ;
        RECT  21.516 17.712 21.6 17.736 ;
    END
  END b[214]
  PIN b[215]
    DIRECTION OUTPUT ;
    USE SIGNAL ;
    PORT
      LAYER M4 ;
        RECT  21.516 17.856 21.6 17.88 ;
    END
  END b[215]
  PIN b[216]
    DIRECTION OUTPUT ;
    USE SIGNAL ;
    PORT
      LAYER M4 ;
        RECT  21.516 18 21.6 18.024 ;
    END
  END b[216]
  PIN b[217]
    DIRECTION OUTPUT ;
    USE SIGNAL ;
    PORT
      LAYER M4 ;
        RECT  21.516 18.144 21.6 18.168 ;
    END
  END b[217]
  PIN b[218]
    DIRECTION OUTPUT ;
    USE SIGNAL ;
    PORT
      LAYER M4 ;
        RECT  21.516 18.288 21.6 18.312 ;
    END
  END b[218]
  PIN b[219]
    DIRECTION OUTPUT ;
    USE SIGNAL ;
    PORT
      LAYER M4 ;
        RECT  21.516 18.432 21.6 18.456 ;
    END
  END b[219]
  PIN b[21]
    DIRECTION OUTPUT ;
    USE SIGNAL ;
    PORT
      LAYER M4 ;
        RECT  21.516 55.584 21.6 55.608 ;
    END
  END b[21]
  PIN b[220]
    DIRECTION OUTPUT ;
    USE SIGNAL ;
    PORT
      LAYER M4 ;
        RECT  21.516 18.576 21.6 18.6 ;
    END
  END b[220]
  PIN b[221]
    DIRECTION OUTPUT ;
    USE SIGNAL ;
    PORT
      LAYER M4 ;
        RECT  21.516 18.72 21.6 18.744 ;
    END
  END b[221]
  PIN b[222]
    DIRECTION OUTPUT ;
    USE SIGNAL ;
    PORT
      LAYER M4 ;
        RECT  21.516 18.864 21.6 18.888 ;
    END
  END b[222]
  PIN b[223]
    DIRECTION OUTPUT ;
    USE SIGNAL ;
    PORT
      LAYER M4 ;
        RECT  21.516 19.008 21.6 19.032 ;
    END
  END b[223]
  PIN b[224]
    DIRECTION OUTPUT ;
    USE SIGNAL ;
    PORT
      LAYER M4 ;
        RECT  21.516 9.936 21.6 9.96 ;
    END
  END b[224]
  PIN b[225]
    DIRECTION OUTPUT ;
    USE SIGNAL ;
    PORT
      LAYER M4 ;
        RECT  21.516 10.08 21.6 10.104 ;
    END
  END b[225]
  PIN b[226]
    DIRECTION OUTPUT ;
    USE SIGNAL ;
    PORT
      LAYER M4 ;
        RECT  21.516 10.224 21.6 10.248 ;
    END
  END b[226]
  PIN b[227]
    DIRECTION OUTPUT ;
    USE SIGNAL ;
    PORT
      LAYER M4 ;
        RECT  21.516 10.368 21.6 10.392 ;
    END
  END b[227]
  PIN b[228]
    DIRECTION OUTPUT ;
    USE SIGNAL ;
    PORT
      LAYER M4 ;
        RECT  21.516 10.512 21.6 10.536 ;
    END
  END b[228]
  PIN b[229]
    DIRECTION OUTPUT ;
    USE SIGNAL ;
    PORT
      LAYER M4 ;
        RECT  21.516 10.656 21.6 10.68 ;
    END
  END b[229]
  PIN b[22]
    DIRECTION OUTPUT ;
    USE SIGNAL ;
    PORT
      LAYER M4 ;
        RECT  21.516 55.728 21.6 55.752 ;
    END
  END b[22]
  PIN b[230]
    DIRECTION OUTPUT ;
    USE SIGNAL ;
    PORT
      LAYER M4 ;
        RECT  21.516 10.8 21.6 10.824 ;
    END
  END b[230]
  PIN b[231]
    DIRECTION OUTPUT ;
    USE SIGNAL ;
    PORT
      LAYER M4 ;
        RECT  21.516 10.944 21.6 10.968 ;
    END
  END b[231]
  PIN b[232]
    DIRECTION OUTPUT ;
    USE SIGNAL ;
    PORT
      LAYER M4 ;
        RECT  21.516 11.088 21.6 11.112 ;
    END
  END b[232]
  PIN b[233]
    DIRECTION OUTPUT ;
    USE SIGNAL ;
    PORT
      LAYER M4 ;
        RECT  21.516 11.232 21.6 11.256 ;
    END
  END b[233]
  PIN b[234]
    DIRECTION OUTPUT ;
    USE SIGNAL ;
    PORT
      LAYER M4 ;
        RECT  21.516 11.376 21.6 11.4 ;
    END
  END b[234]
  PIN b[235]
    DIRECTION OUTPUT ;
    USE SIGNAL ;
    PORT
      LAYER M4 ;
        RECT  21.516 11.52 21.6 11.544 ;
    END
  END b[235]
  PIN b[236]
    DIRECTION OUTPUT ;
    USE SIGNAL ;
    PORT
      LAYER M4 ;
        RECT  21.516 11.664 21.6 11.688 ;
    END
  END b[236]
  PIN b[237]
    DIRECTION OUTPUT ;
    USE SIGNAL ;
    PORT
      LAYER M4 ;
        RECT  21.516 11.808 21.6 11.832 ;
    END
  END b[237]
  PIN b[238]
    DIRECTION OUTPUT ;
    USE SIGNAL ;
    PORT
      LAYER M4 ;
        RECT  21.516 11.952 21.6 11.976 ;
    END
  END b[238]
  PIN b[239]
    DIRECTION OUTPUT ;
    USE SIGNAL ;
    PORT
      LAYER M4 ;
        RECT  21.516 12.096 21.6 12.12 ;
    END
  END b[239]
  PIN b[23]
    DIRECTION OUTPUT ;
    USE SIGNAL ;
    PORT
      LAYER M4 ;
        RECT  21.516 55.872 21.6 55.896 ;
    END
  END b[23]
  PIN b[240]
    DIRECTION OUTPUT ;
    USE SIGNAL ;
    PORT
      LAYER M4 ;
        RECT  21.516 12.24 21.6 12.264 ;
    END
  END b[240]
  PIN b[241]
    DIRECTION OUTPUT ;
    USE SIGNAL ;
    PORT
      LAYER M4 ;
        RECT  21.516 12.384 21.6 12.408 ;
    END
  END b[241]
  PIN b[242]
    DIRECTION OUTPUT ;
    USE SIGNAL ;
    PORT
      LAYER M4 ;
        RECT  21.516 12.528 21.6 12.552 ;
    END
  END b[242]
  PIN b[243]
    DIRECTION OUTPUT ;
    USE SIGNAL ;
    PORT
      LAYER M4 ;
        RECT  21.516 12.672 21.6 12.696 ;
    END
  END b[243]
  PIN b[244]
    DIRECTION OUTPUT ;
    USE SIGNAL ;
    PORT
      LAYER M4 ;
        RECT  21.516 12.816 21.6 12.84 ;
    END
  END b[244]
  PIN b[245]
    DIRECTION OUTPUT ;
    USE SIGNAL ;
    PORT
      LAYER M4 ;
        RECT  21.516 12.96 21.6 12.984 ;
    END
  END b[245]
  PIN b[246]
    DIRECTION OUTPUT ;
    USE SIGNAL ;
    PORT
      LAYER M4 ;
        RECT  21.516 13.104 21.6 13.128 ;
    END
  END b[246]
  PIN b[247]
    DIRECTION OUTPUT ;
    USE SIGNAL ;
    PORT
      LAYER M4 ;
        RECT  21.516 13.248 21.6 13.272 ;
    END
  END b[247]
  PIN b[248]
    DIRECTION OUTPUT ;
    USE SIGNAL ;
    PORT
      LAYER M4 ;
        RECT  21.516 13.392 21.6 13.416 ;
    END
  END b[248]
  PIN b[249]
    DIRECTION OUTPUT ;
    USE SIGNAL ;
    PORT
      LAYER M4 ;
        RECT  21.516 13.536 21.6 13.56 ;
    END
  END b[249]
  PIN b[24]
    DIRECTION OUTPUT ;
    USE SIGNAL ;
    PORT
      LAYER M4 ;
        RECT  21.516 56.016 21.6 56.04 ;
    END
  END b[24]
  PIN b[250]
    DIRECTION OUTPUT ;
    USE SIGNAL ;
    PORT
      LAYER M4 ;
        RECT  21.516 13.68 21.6 13.704 ;
    END
  END b[250]
  PIN b[251]
    DIRECTION OUTPUT ;
    USE SIGNAL ;
    PORT
      LAYER M4 ;
        RECT  21.516 13.824 21.6 13.848 ;
    END
  END b[251]
  PIN b[252]
    DIRECTION OUTPUT ;
    USE SIGNAL ;
    PORT
      LAYER M4 ;
        RECT  21.516 13.968 21.6 13.992 ;
    END
  END b[252]
  PIN b[253]
    DIRECTION OUTPUT ;
    USE SIGNAL ;
    PORT
      LAYER M4 ;
        RECT  21.516 14.112 21.6 14.136 ;
    END
  END b[253]
  PIN b[254]
    DIRECTION OUTPUT ;
    USE SIGNAL ;
    PORT
      LAYER M4 ;
        RECT  21.516 14.256 21.6 14.28 ;
    END
  END b[254]
  PIN b[255]
    DIRECTION OUTPUT ;
    USE SIGNAL ;
    PORT
      LAYER M4 ;
        RECT  21.516 14.4 21.6 14.424 ;
    END
  END b[255]
  PIN b[256]
    DIRECTION OUTPUT ;
    USE SIGNAL ;
    PORT
      LAYER M4 ;
        RECT  21.516 23.76 21.6 23.784 ;
    END
  END b[256]
  PIN b[257]
    DIRECTION OUTPUT ;
    USE SIGNAL ;
    PORT
      LAYER M4 ;
        RECT  21.516 23.904 21.6 23.928 ;
    END
  END b[257]
  PIN b[258]
    DIRECTION OUTPUT ;
    USE SIGNAL ;
    PORT
      LAYER M4 ;
        RECT  21.516 24.048 21.6 24.072 ;
    END
  END b[258]
  PIN b[259]
    DIRECTION OUTPUT ;
    USE SIGNAL ;
    PORT
      LAYER M4 ;
        RECT  21.516 24.192 21.6 24.216 ;
    END
  END b[259]
  PIN b[25]
    DIRECTION OUTPUT ;
    USE SIGNAL ;
    PORT
      LAYER M4 ;
        RECT  21.516 56.16 21.6 56.184 ;
    END
  END b[25]
  PIN b[260]
    DIRECTION OUTPUT ;
    USE SIGNAL ;
    PORT
      LAYER M4 ;
        RECT  21.516 24.336 21.6 24.36 ;
    END
  END b[260]
  PIN b[261]
    DIRECTION OUTPUT ;
    USE SIGNAL ;
    PORT
      LAYER M4 ;
        RECT  21.516 24.48 21.6 24.504 ;
    END
  END b[261]
  PIN b[262]
    DIRECTION OUTPUT ;
    USE SIGNAL ;
    PORT
      LAYER M4 ;
        RECT  21.516 24.624 21.6 24.648 ;
    END
  END b[262]
  PIN b[263]
    DIRECTION OUTPUT ;
    USE SIGNAL ;
    PORT
      LAYER M4 ;
        RECT  21.516 24.768 21.6 24.792 ;
    END
  END b[263]
  PIN b[264]
    DIRECTION OUTPUT ;
    USE SIGNAL ;
    PORT
      LAYER M4 ;
        RECT  21.516 24.912 21.6 24.936 ;
    END
  END b[264]
  PIN b[265]
    DIRECTION OUTPUT ;
    USE SIGNAL ;
    PORT
      LAYER M4 ;
        RECT  21.516 25.056 21.6 25.08 ;
    END
  END b[265]
  PIN b[266]
    DIRECTION OUTPUT ;
    USE SIGNAL ;
    PORT
      LAYER M4 ;
        RECT  21.516 25.2 21.6 25.224 ;
    END
  END b[266]
  PIN b[267]
    DIRECTION OUTPUT ;
    USE SIGNAL ;
    PORT
      LAYER M4 ;
        RECT  21.516 25.344 21.6 25.368 ;
    END
  END b[267]
  PIN b[268]
    DIRECTION OUTPUT ;
    USE SIGNAL ;
    PORT
      LAYER M4 ;
        RECT  21.516 25.488 21.6 25.512 ;
    END
  END b[268]
  PIN b[269]
    DIRECTION OUTPUT ;
    USE SIGNAL ;
    PORT
      LAYER M4 ;
        RECT  21.516 25.632 21.6 25.656 ;
    END
  END b[269]
  PIN b[26]
    DIRECTION OUTPUT ;
    USE SIGNAL ;
    PORT
      LAYER M4 ;
        RECT  21.516 56.304 21.6 56.328 ;
    END
  END b[26]
  PIN b[270]
    DIRECTION OUTPUT ;
    USE SIGNAL ;
    PORT
      LAYER M4 ;
        RECT  21.516 25.776 21.6 25.8 ;
    END
  END b[270]
  PIN b[271]
    DIRECTION OUTPUT ;
    USE SIGNAL ;
    PORT
      LAYER M4 ;
        RECT  21.516 25.92 21.6 25.944 ;
    END
  END b[271]
  PIN b[272]
    DIRECTION OUTPUT ;
    USE SIGNAL ;
    PORT
      LAYER M4 ;
        RECT  21.516 26.064 21.6 26.088 ;
    END
  END b[272]
  PIN b[273]
    DIRECTION OUTPUT ;
    USE SIGNAL ;
    PORT
      LAYER M4 ;
        RECT  21.516 26.208 21.6 26.232 ;
    END
  END b[273]
  PIN b[274]
    DIRECTION OUTPUT ;
    USE SIGNAL ;
    PORT
      LAYER M4 ;
        RECT  21.516 26.352 21.6 26.376 ;
    END
  END b[274]
  PIN b[275]
    DIRECTION OUTPUT ;
    USE SIGNAL ;
    PORT
      LAYER M4 ;
        RECT  21.516 26.496 21.6 26.52 ;
    END
  END b[275]
  PIN b[276]
    DIRECTION OUTPUT ;
    USE SIGNAL ;
    PORT
      LAYER M4 ;
        RECT  21.516 26.64 21.6 26.664 ;
    END
  END b[276]
  PIN b[277]
    DIRECTION OUTPUT ;
    USE SIGNAL ;
    PORT
      LAYER M4 ;
        RECT  21.516 26.784 21.6 26.808 ;
    END
  END b[277]
  PIN b[278]
    DIRECTION OUTPUT ;
    USE SIGNAL ;
    PORT
      LAYER M4 ;
        RECT  21.516 26.928 21.6 26.952 ;
    END
  END b[278]
  PIN b[279]
    DIRECTION OUTPUT ;
    USE SIGNAL ;
    PORT
      LAYER M4 ;
        RECT  21.516 27.072 21.6 27.096 ;
    END
  END b[279]
  PIN b[27]
    DIRECTION OUTPUT ;
    USE SIGNAL ;
    PORT
      LAYER M4 ;
        RECT  21.516 56.448 21.6 56.472 ;
    END
  END b[27]
  PIN b[280]
    DIRECTION OUTPUT ;
    USE SIGNAL ;
    PORT
      LAYER M4 ;
        RECT  21.516 27.216 21.6 27.24 ;
    END
  END b[280]
  PIN b[281]
    DIRECTION OUTPUT ;
    USE SIGNAL ;
    PORT
      LAYER M4 ;
        RECT  21.516 27.36 21.6 27.384 ;
    END
  END b[281]
  PIN b[282]
    DIRECTION OUTPUT ;
    USE SIGNAL ;
    PORT
      LAYER M4 ;
        RECT  21.516 27.504 21.6 27.528 ;
    END
  END b[282]
  PIN b[283]
    DIRECTION OUTPUT ;
    USE SIGNAL ;
    PORT
      LAYER M4 ;
        RECT  21.516 27.648 21.6 27.672 ;
    END
  END b[283]
  PIN b[284]
    DIRECTION OUTPUT ;
    USE SIGNAL ;
    PORT
      LAYER M4 ;
        RECT  21.516 27.792 21.6 27.816 ;
    END
  END b[284]
  PIN b[285]
    DIRECTION OUTPUT ;
    USE SIGNAL ;
    PORT
      LAYER M4 ;
        RECT  21.516 27.936 21.6 27.96 ;
    END
  END b[285]
  PIN b[286]
    DIRECTION OUTPUT ;
    USE SIGNAL ;
    PORT
      LAYER M4 ;
        RECT  21.516 28.08 21.6 28.104 ;
    END
  END b[286]
  PIN b[287]
    DIRECTION OUTPUT ;
    USE SIGNAL ;
    PORT
      LAYER M4 ;
        RECT  21.516 28.224 21.6 28.248 ;
    END
  END b[287]
  PIN b[288]
    DIRECTION OUTPUT ;
    USE SIGNAL ;
    PORT
      LAYER M4 ;
        RECT  21.516 72.144 21.6 72.168 ;
    END
  END b[288]
  PIN b[289]
    DIRECTION OUTPUT ;
    USE SIGNAL ;
    PORT
      LAYER M4 ;
        RECT  21.516 72.288 21.6 72.312 ;
    END
  END b[289]
  PIN b[28]
    DIRECTION OUTPUT ;
    USE SIGNAL ;
    PORT
      LAYER M4 ;
        RECT  21.516 56.592 21.6 56.616 ;
    END
  END b[28]
  PIN b[290]
    DIRECTION OUTPUT ;
    USE SIGNAL ;
    PORT
      LAYER M4 ;
        RECT  21.516 72.432 21.6 72.456 ;
    END
  END b[290]
  PIN b[291]
    DIRECTION OUTPUT ;
    USE SIGNAL ;
    PORT
      LAYER M4 ;
        RECT  21.516 72.576 21.6 72.6 ;
    END
  END b[291]
  PIN b[292]
    DIRECTION OUTPUT ;
    USE SIGNAL ;
    PORT
      LAYER M4 ;
        RECT  21.516 72.72 21.6 72.744 ;
    END
  END b[292]
  PIN b[293]
    DIRECTION OUTPUT ;
    USE SIGNAL ;
    PORT
      LAYER M4 ;
        RECT  21.516 72.864 21.6 72.888 ;
    END
  END b[293]
  PIN b[294]
    DIRECTION OUTPUT ;
    USE SIGNAL ;
    PORT
      LAYER M4 ;
        RECT  21.516 73.008 21.6 73.032 ;
    END
  END b[294]
  PIN b[295]
    DIRECTION OUTPUT ;
    USE SIGNAL ;
    PORT
      LAYER M4 ;
        RECT  21.516 73.152 21.6 73.176 ;
    END
  END b[295]
  PIN b[296]
    DIRECTION OUTPUT ;
    USE SIGNAL ;
    PORT
      LAYER M4 ;
        RECT  21.516 73.296 21.6 73.32 ;
    END
  END b[296]
  PIN b[297]
    DIRECTION OUTPUT ;
    USE SIGNAL ;
    PORT
      LAYER M4 ;
        RECT  21.516 73.44 21.6 73.464 ;
    END
  END b[297]
  PIN b[298]
    DIRECTION OUTPUT ;
    USE SIGNAL ;
    PORT
      LAYER M4 ;
        RECT  21.516 73.584 21.6 73.608 ;
    END
  END b[298]
  PIN b[299]
    DIRECTION OUTPUT ;
    USE SIGNAL ;
    PORT
      LAYER M4 ;
        RECT  21.516 73.728 21.6 73.752 ;
    END
  END b[299]
  PIN b[29]
    DIRECTION OUTPUT ;
    USE SIGNAL ;
    PORT
      LAYER M4 ;
        RECT  21.516 56.736 21.6 56.76 ;
    END
  END b[29]
  PIN b[2]
    DIRECTION OUTPUT ;
    USE SIGNAL ;
    PORT
      LAYER M4 ;
        RECT  21.516 52.848 21.6 52.872 ;
    END
  END b[2]
  PIN b[300]
    DIRECTION OUTPUT ;
    USE SIGNAL ;
    PORT
      LAYER M4 ;
        RECT  21.516 73.872 21.6 73.896 ;
    END
  END b[300]
  PIN b[301]
    DIRECTION OUTPUT ;
    USE SIGNAL ;
    PORT
      LAYER M4 ;
        RECT  21.516 74.016 21.6 74.04 ;
    END
  END b[301]
  PIN b[302]
    DIRECTION OUTPUT ;
    USE SIGNAL ;
    PORT
      LAYER M4 ;
        RECT  21.516 74.16 21.6 74.184 ;
    END
  END b[302]
  PIN b[303]
    DIRECTION OUTPUT ;
    USE SIGNAL ;
    PORT
      LAYER M4 ;
        RECT  21.516 74.304 21.6 74.328 ;
    END
  END b[303]
  PIN b[304]
    DIRECTION OUTPUT ;
    USE SIGNAL ;
    PORT
      LAYER M4 ;
        RECT  21.516 74.448 21.6 74.472 ;
    END
  END b[304]
  PIN b[305]
    DIRECTION OUTPUT ;
    USE SIGNAL ;
    PORT
      LAYER M4 ;
        RECT  21.516 74.592 21.6 74.616 ;
    END
  END b[305]
  PIN b[306]
    DIRECTION OUTPUT ;
    USE SIGNAL ;
    PORT
      LAYER M4 ;
        RECT  21.516 74.736 21.6 74.76 ;
    END
  END b[306]
  PIN b[307]
    DIRECTION OUTPUT ;
    USE SIGNAL ;
    PORT
      LAYER M4 ;
        RECT  21.516 74.88 21.6 74.904 ;
    END
  END b[307]
  PIN b[308]
    DIRECTION OUTPUT ;
    USE SIGNAL ;
    PORT
      LAYER M4 ;
        RECT  21.516 75.024 21.6 75.048 ;
    END
  END b[308]
  PIN b[309]
    DIRECTION OUTPUT ;
    USE SIGNAL ;
    PORT
      LAYER M4 ;
        RECT  21.516 75.168 21.6 75.192 ;
    END
  END b[309]
  PIN b[30]
    DIRECTION OUTPUT ;
    USE SIGNAL ;
    PORT
      LAYER M4 ;
        RECT  21.516 56.88 21.6 56.904 ;
    END
  END b[30]
  PIN b[310]
    DIRECTION OUTPUT ;
    USE SIGNAL ;
    PORT
      LAYER M4 ;
        RECT  21.516 75.312 21.6 75.336 ;
    END
  END b[310]
  PIN b[311]
    DIRECTION OUTPUT ;
    USE SIGNAL ;
    PORT
      LAYER M4 ;
        RECT  21.516 75.456 21.6 75.48 ;
    END
  END b[311]
  PIN b[312]
    DIRECTION OUTPUT ;
    USE SIGNAL ;
    PORT
      LAYER M4 ;
        RECT  21.516 75.6 21.6 75.624 ;
    END
  END b[312]
  PIN b[313]
    DIRECTION OUTPUT ;
    USE SIGNAL ;
    PORT
      LAYER M4 ;
        RECT  21.516 75.744 21.6 75.768 ;
    END
  END b[313]
  PIN b[314]
    DIRECTION OUTPUT ;
    USE SIGNAL ;
    PORT
      LAYER M4 ;
        RECT  21.516 75.888 21.6 75.912 ;
    END
  END b[314]
  PIN b[315]
    DIRECTION OUTPUT ;
    USE SIGNAL ;
    PORT
      LAYER M4 ;
        RECT  21.516 76.032 21.6 76.056 ;
    END
  END b[315]
  PIN b[316]
    DIRECTION OUTPUT ;
    USE SIGNAL ;
    PORT
      LAYER M4 ;
        RECT  21.516 76.176 21.6 76.2 ;
    END
  END b[316]
  PIN b[317]
    DIRECTION OUTPUT ;
    USE SIGNAL ;
    PORT
      LAYER M4 ;
        RECT  21.516 76.32 21.6 76.344 ;
    END
  END b[317]
  PIN b[318]
    DIRECTION OUTPUT ;
    USE SIGNAL ;
    PORT
      LAYER M4 ;
        RECT  21.516 76.464 21.6 76.488 ;
    END
  END b[318]
  PIN b[319]
    DIRECTION OUTPUT ;
    USE SIGNAL ;
    PORT
      LAYER M4 ;
        RECT  21.516 76.608 21.6 76.632 ;
    END
  END b[319]
  PIN b[31]
    DIRECTION OUTPUT ;
    USE SIGNAL ;
    PORT
      LAYER M4 ;
        RECT  21.516 57.024 21.6 57.048 ;
    END
  END b[31]
  PIN b[320]
    DIRECTION OUTPUT ;
    USE SIGNAL ;
    PORT
      LAYER M4 ;
        RECT  21.516 19.152 21.6 19.176 ;
    END
  END b[320]
  PIN b[321]
    DIRECTION OUTPUT ;
    USE SIGNAL ;
    PORT
      LAYER M4 ;
        RECT  21.516 19.296 21.6 19.32 ;
    END
  END b[321]
  PIN b[322]
    DIRECTION OUTPUT ;
    USE SIGNAL ;
    PORT
      LAYER M4 ;
        RECT  21.516 19.44 21.6 19.464 ;
    END
  END b[322]
  PIN b[323]
    DIRECTION OUTPUT ;
    USE SIGNAL ;
    PORT
      LAYER M4 ;
        RECT  21.516 19.584 21.6 19.608 ;
    END
  END b[323]
  PIN b[324]
    DIRECTION OUTPUT ;
    USE SIGNAL ;
    PORT
      LAYER M4 ;
        RECT  21.516 19.728 21.6 19.752 ;
    END
  END b[324]
  PIN b[325]
    DIRECTION OUTPUT ;
    USE SIGNAL ;
    PORT
      LAYER M4 ;
        RECT  21.516 19.872 21.6 19.896 ;
    END
  END b[325]
  PIN b[326]
    DIRECTION OUTPUT ;
    USE SIGNAL ;
    PORT
      LAYER M4 ;
        RECT  21.516 20.016 21.6 20.04 ;
    END
  END b[326]
  PIN b[327]
    DIRECTION OUTPUT ;
    USE SIGNAL ;
    PORT
      LAYER M4 ;
        RECT  21.516 20.16 21.6 20.184 ;
    END
  END b[327]
  PIN b[328]
    DIRECTION OUTPUT ;
    USE SIGNAL ;
    PORT
      LAYER M4 ;
        RECT  21.516 20.304 21.6 20.328 ;
    END
  END b[328]
  PIN b[329]
    DIRECTION OUTPUT ;
    USE SIGNAL ;
    PORT
      LAYER M4 ;
        RECT  21.516 20.448 21.6 20.472 ;
    END
  END b[329]
  PIN b[32]
    DIRECTION OUTPUT ;
    USE SIGNAL ;
    PORT
      LAYER M4 ;
        RECT  21.516 38.736 21.6 38.76 ;
    END
  END b[32]
  PIN b[330]
    DIRECTION OUTPUT ;
    USE SIGNAL ;
    PORT
      LAYER M4 ;
        RECT  21.516 20.592 21.6 20.616 ;
    END
  END b[330]
  PIN b[331]
    DIRECTION OUTPUT ;
    USE SIGNAL ;
    PORT
      LAYER M4 ;
        RECT  21.516 20.736 21.6 20.76 ;
    END
  END b[331]
  PIN b[332]
    DIRECTION OUTPUT ;
    USE SIGNAL ;
    PORT
      LAYER M4 ;
        RECT  21.516 20.88 21.6 20.904 ;
    END
  END b[332]
  PIN b[333]
    DIRECTION OUTPUT ;
    USE SIGNAL ;
    PORT
      LAYER M4 ;
        RECT  21.516 21.024 21.6 21.048 ;
    END
  END b[333]
  PIN b[334]
    DIRECTION OUTPUT ;
    USE SIGNAL ;
    PORT
      LAYER M4 ;
        RECT  21.516 21.168 21.6 21.192 ;
    END
  END b[334]
  PIN b[335]
    DIRECTION OUTPUT ;
    USE SIGNAL ;
    PORT
      LAYER M4 ;
        RECT  21.516 21.312 21.6 21.336 ;
    END
  END b[335]
  PIN b[336]
    DIRECTION OUTPUT ;
    USE SIGNAL ;
    PORT
      LAYER M4 ;
        RECT  21.516 21.456 21.6 21.48 ;
    END
  END b[336]
  PIN b[337]
    DIRECTION OUTPUT ;
    USE SIGNAL ;
    PORT
      LAYER M4 ;
        RECT  21.516 21.6 21.6 21.624 ;
    END
  END b[337]
  PIN b[338]
    DIRECTION OUTPUT ;
    USE SIGNAL ;
    PORT
      LAYER M4 ;
        RECT  21.516 21.744 21.6 21.768 ;
    END
  END b[338]
  PIN b[339]
    DIRECTION OUTPUT ;
    USE SIGNAL ;
    PORT
      LAYER M4 ;
        RECT  21.516 21.888 21.6 21.912 ;
    END
  END b[339]
  PIN b[33]
    DIRECTION OUTPUT ;
    USE SIGNAL ;
    PORT
      LAYER M4 ;
        RECT  21.516 38.88 21.6 38.904 ;
    END
  END b[33]
  PIN b[340]
    DIRECTION OUTPUT ;
    USE SIGNAL ;
    PORT
      LAYER M4 ;
        RECT  21.516 22.032 21.6 22.056 ;
    END
  END b[340]
  PIN b[341]
    DIRECTION OUTPUT ;
    USE SIGNAL ;
    PORT
      LAYER M4 ;
        RECT  21.516 22.176 21.6 22.2 ;
    END
  END b[341]
  PIN b[342]
    DIRECTION OUTPUT ;
    USE SIGNAL ;
    PORT
      LAYER M4 ;
        RECT  21.516 22.32 21.6 22.344 ;
    END
  END b[342]
  PIN b[343]
    DIRECTION OUTPUT ;
    USE SIGNAL ;
    PORT
      LAYER M4 ;
        RECT  21.516 22.464 21.6 22.488 ;
    END
  END b[343]
  PIN b[344]
    DIRECTION OUTPUT ;
    USE SIGNAL ;
    PORT
      LAYER M4 ;
        RECT  21.516 22.608 21.6 22.632 ;
    END
  END b[344]
  PIN b[345]
    DIRECTION OUTPUT ;
    USE SIGNAL ;
    PORT
      LAYER M4 ;
        RECT  21.516 22.752 21.6 22.776 ;
    END
  END b[345]
  PIN b[346]
    DIRECTION OUTPUT ;
    USE SIGNAL ;
    PORT
      LAYER M4 ;
        RECT  21.516 22.896 21.6 22.92 ;
    END
  END b[346]
  PIN b[347]
    DIRECTION OUTPUT ;
    USE SIGNAL ;
    PORT
      LAYER M4 ;
        RECT  21.516 23.04 21.6 23.064 ;
    END
  END b[347]
  PIN b[348]
    DIRECTION OUTPUT ;
    USE SIGNAL ;
    PORT
      LAYER M4 ;
        RECT  21.516 23.184 21.6 23.208 ;
    END
  END b[348]
  PIN b[349]
    DIRECTION OUTPUT ;
    USE SIGNAL ;
    PORT
      LAYER M4 ;
        RECT  21.516 23.328 21.6 23.352 ;
    END
  END b[349]
  PIN b[34]
    DIRECTION OUTPUT ;
    USE SIGNAL ;
    PORT
      LAYER M4 ;
        RECT  21.516 39.024 21.6 39.048 ;
    END
  END b[34]
  PIN b[350]
    DIRECTION OUTPUT ;
    USE SIGNAL ;
    PORT
      LAYER M4 ;
        RECT  21.516 23.472 21.6 23.496 ;
    END
  END b[350]
  PIN b[351]
    DIRECTION OUTPUT ;
    USE SIGNAL ;
    PORT
      LAYER M4 ;
        RECT  21.516 23.616 21.6 23.64 ;
    END
  END b[351]
  PIN b[352]
    DIRECTION OUTPUT ;
    USE SIGNAL ;
    PORT
      LAYER M4 ;
        RECT  21.516 0.72 21.6 0.744 ;
    END
  END b[352]
  PIN b[353]
    DIRECTION OUTPUT ;
    USE SIGNAL ;
    PORT
      LAYER M4 ;
        RECT  21.516 0.864 21.6 0.888 ;
    END
  END b[353]
  PIN b[354]
    DIRECTION OUTPUT ;
    USE SIGNAL ;
    PORT
      LAYER M4 ;
        RECT  21.516 1.008 21.6 1.032 ;
    END
  END b[354]
  PIN b[355]
    DIRECTION OUTPUT ;
    USE SIGNAL ;
    PORT
      LAYER M4 ;
        RECT  21.516 1.152 21.6 1.176 ;
    END
  END b[355]
  PIN b[356]
    DIRECTION OUTPUT ;
    USE SIGNAL ;
    PORT
      LAYER M4 ;
        RECT  21.516 1.296 21.6 1.32 ;
    END
  END b[356]
  PIN b[357]
    DIRECTION OUTPUT ;
    USE SIGNAL ;
    PORT
      LAYER M4 ;
        RECT  21.516 1.44 21.6 1.464 ;
    END
  END b[357]
  PIN b[358]
    DIRECTION OUTPUT ;
    USE SIGNAL ;
    PORT
      LAYER M4 ;
        RECT  21.516 1.584 21.6 1.608 ;
    END
  END b[358]
  PIN b[359]
    DIRECTION OUTPUT ;
    USE SIGNAL ;
    PORT
      LAYER M4 ;
        RECT  21.516 1.728 21.6 1.752 ;
    END
  END b[359]
  PIN b[35]
    DIRECTION OUTPUT ;
    USE SIGNAL ;
    PORT
      LAYER M4 ;
        RECT  21.516 39.168 21.6 39.192 ;
    END
  END b[35]
  PIN b[360]
    DIRECTION OUTPUT ;
    USE SIGNAL ;
    PORT
      LAYER M4 ;
        RECT  21.516 1.872 21.6 1.896 ;
    END
  END b[360]
  PIN b[361]
    DIRECTION OUTPUT ;
    USE SIGNAL ;
    PORT
      LAYER M4 ;
        RECT  21.516 2.016 21.6 2.04 ;
    END
  END b[361]
  PIN b[362]
    DIRECTION OUTPUT ;
    USE SIGNAL ;
    PORT
      LAYER M4 ;
        RECT  21.516 2.16 21.6 2.184 ;
    END
  END b[362]
  PIN b[363]
    DIRECTION OUTPUT ;
    USE SIGNAL ;
    PORT
      LAYER M4 ;
        RECT  21.516 2.304 21.6 2.328 ;
    END
  END b[363]
  PIN b[364]
    DIRECTION OUTPUT ;
    USE SIGNAL ;
    PORT
      LAYER M4 ;
        RECT  21.516 2.448 21.6 2.472 ;
    END
  END b[364]
  PIN b[365]
    DIRECTION OUTPUT ;
    USE SIGNAL ;
    PORT
      LAYER M4 ;
        RECT  21.516 2.592 21.6 2.616 ;
    END
  END b[365]
  PIN b[366]
    DIRECTION OUTPUT ;
    USE SIGNAL ;
    PORT
      LAYER M4 ;
        RECT  21.516 2.736 21.6 2.76 ;
    END
  END b[366]
  PIN b[367]
    DIRECTION OUTPUT ;
    USE SIGNAL ;
    PORT
      LAYER M4 ;
        RECT  21.516 2.88 21.6 2.904 ;
    END
  END b[367]
  PIN b[368]
    DIRECTION OUTPUT ;
    USE SIGNAL ;
    PORT
      LAYER M4 ;
        RECT  21.516 3.024 21.6 3.048 ;
    END
  END b[368]
  PIN b[369]
    DIRECTION OUTPUT ;
    USE SIGNAL ;
    PORT
      LAYER M4 ;
        RECT  21.516 3.168 21.6 3.192 ;
    END
  END b[369]
  PIN b[36]
    DIRECTION OUTPUT ;
    USE SIGNAL ;
    PORT
      LAYER M4 ;
        RECT  21.516 39.312 21.6 39.336 ;
    END
  END b[36]
  PIN b[370]
    DIRECTION OUTPUT ;
    USE SIGNAL ;
    PORT
      LAYER M4 ;
        RECT  21.516 3.312 21.6 3.336 ;
    END
  END b[370]
  PIN b[371]
    DIRECTION OUTPUT ;
    USE SIGNAL ;
    PORT
      LAYER M4 ;
        RECT  21.516 3.456 21.6 3.48 ;
    END
  END b[371]
  PIN b[372]
    DIRECTION OUTPUT ;
    USE SIGNAL ;
    PORT
      LAYER M4 ;
        RECT  21.516 3.6 21.6 3.624 ;
    END
  END b[372]
  PIN b[373]
    DIRECTION OUTPUT ;
    USE SIGNAL ;
    PORT
      LAYER M4 ;
        RECT  21.516 3.744 21.6 3.768 ;
    END
  END b[373]
  PIN b[374]
    DIRECTION OUTPUT ;
    USE SIGNAL ;
    PORT
      LAYER M4 ;
        RECT  21.516 3.888 21.6 3.912 ;
    END
  END b[374]
  PIN b[375]
    DIRECTION OUTPUT ;
    USE SIGNAL ;
    PORT
      LAYER M4 ;
        RECT  21.516 4.032 21.6 4.056 ;
    END
  END b[375]
  PIN b[376]
    DIRECTION OUTPUT ;
    USE SIGNAL ;
    PORT
      LAYER M4 ;
        RECT  21.516 4.176 21.6 4.2 ;
    END
  END b[376]
  PIN b[377]
    DIRECTION OUTPUT ;
    USE SIGNAL ;
    PORT
      LAYER M4 ;
        RECT  21.516 4.32 21.6 4.344 ;
    END
  END b[377]
  PIN b[378]
    DIRECTION OUTPUT ;
    USE SIGNAL ;
    PORT
      LAYER M4 ;
        RECT  21.516 4.464 21.6 4.488 ;
    END
  END b[378]
  PIN b[379]
    DIRECTION OUTPUT ;
    USE SIGNAL ;
    PORT
      LAYER M4 ;
        RECT  21.516 4.608 21.6 4.632 ;
    END
  END b[379]
  PIN b[37]
    DIRECTION OUTPUT ;
    USE SIGNAL ;
    PORT
      LAYER M4 ;
        RECT  21.516 39.456 21.6 39.48 ;
    END
  END b[37]
  PIN b[380]
    DIRECTION OUTPUT ;
    USE SIGNAL ;
    PORT
      LAYER M4 ;
        RECT  21.516 4.752 21.6 4.776 ;
    END
  END b[380]
  PIN b[381]
    DIRECTION OUTPUT ;
    USE SIGNAL ;
    PORT
      LAYER M4 ;
        RECT  21.516 4.896 21.6 4.92 ;
    END
  END b[381]
  PIN b[382]
    DIRECTION OUTPUT ;
    USE SIGNAL ;
    PORT
      LAYER M4 ;
        RECT  21.516 5.04 21.6 5.064 ;
    END
  END b[382]
  PIN b[383]
    DIRECTION OUTPUT ;
    USE SIGNAL ;
    PORT
      LAYER M4 ;
        RECT  21.516 5.184 21.6 5.208 ;
    END
  END b[383]
  PIN b[384]
    DIRECTION OUTPUT ;
    USE SIGNAL ;
    PORT
      LAYER M4 ;
        RECT  21.516 5.328 21.6 5.352 ;
    END
  END b[384]
  PIN b[385]
    DIRECTION OUTPUT ;
    USE SIGNAL ;
    PORT
      LAYER M4 ;
        RECT  21.516 5.472 21.6 5.496 ;
    END
  END b[385]
  PIN b[386]
    DIRECTION OUTPUT ;
    USE SIGNAL ;
    PORT
      LAYER M4 ;
        RECT  21.516 5.616 21.6 5.64 ;
    END
  END b[386]
  PIN b[387]
    DIRECTION OUTPUT ;
    USE SIGNAL ;
    PORT
      LAYER M4 ;
        RECT  21.516 5.76 21.6 5.784 ;
    END
  END b[387]
  PIN b[388]
    DIRECTION OUTPUT ;
    USE SIGNAL ;
    PORT
      LAYER M4 ;
        RECT  21.516 5.904 21.6 5.928 ;
    END
  END b[388]
  PIN b[389]
    DIRECTION OUTPUT ;
    USE SIGNAL ;
    PORT
      LAYER M4 ;
        RECT  21.516 6.048 21.6 6.072 ;
    END
  END b[389]
  PIN b[38]
    DIRECTION OUTPUT ;
    USE SIGNAL ;
    PORT
      LAYER M4 ;
        RECT  21.516 39.6 21.6 39.624 ;
    END
  END b[38]
  PIN b[390]
    DIRECTION OUTPUT ;
    USE SIGNAL ;
    PORT
      LAYER M4 ;
        RECT  21.516 6.192 21.6 6.216 ;
    END
  END b[390]
  PIN b[391]
    DIRECTION OUTPUT ;
    USE SIGNAL ;
    PORT
      LAYER M4 ;
        RECT  21.516 6.336 21.6 6.36 ;
    END
  END b[391]
  PIN b[392]
    DIRECTION OUTPUT ;
    USE SIGNAL ;
    PORT
      LAYER M4 ;
        RECT  21.516 6.48 21.6 6.504 ;
    END
  END b[392]
  PIN b[393]
    DIRECTION OUTPUT ;
    USE SIGNAL ;
    PORT
      LAYER M4 ;
        RECT  21.516 6.624 21.6 6.648 ;
    END
  END b[393]
  PIN b[394]
    DIRECTION OUTPUT ;
    USE SIGNAL ;
    PORT
      LAYER M4 ;
        RECT  21.516 6.768 21.6 6.792 ;
    END
  END b[394]
  PIN b[395]
    DIRECTION OUTPUT ;
    USE SIGNAL ;
    PORT
      LAYER M4 ;
        RECT  21.516 6.912 21.6 6.936 ;
    END
  END b[395]
  PIN b[396]
    DIRECTION OUTPUT ;
    USE SIGNAL ;
    PORT
      LAYER M4 ;
        RECT  21.516 7.056 21.6 7.08 ;
    END
  END b[396]
  PIN b[397]
    DIRECTION OUTPUT ;
    USE SIGNAL ;
    PORT
      LAYER M4 ;
        RECT  21.516 7.2 21.6 7.224 ;
    END
  END b[397]
  PIN b[398]
    DIRECTION OUTPUT ;
    USE SIGNAL ;
    PORT
      LAYER M4 ;
        RECT  21.516 7.344 21.6 7.368 ;
    END
  END b[398]
  PIN b[399]
    DIRECTION OUTPUT ;
    USE SIGNAL ;
    PORT
      LAYER M4 ;
        RECT  21.516 7.488 21.6 7.512 ;
    END
  END b[399]
  PIN b[39]
    DIRECTION OUTPUT ;
    USE SIGNAL ;
    PORT
      LAYER M4 ;
        RECT  21.516 39.744 21.6 39.768 ;
    END
  END b[39]
  PIN b[3]
    DIRECTION OUTPUT ;
    USE SIGNAL ;
    PORT
      LAYER M4 ;
        RECT  21.516 52.992 21.6 53.016 ;
    END
  END b[3]
  PIN b[400]
    DIRECTION OUTPUT ;
    USE SIGNAL ;
    PORT
      LAYER M4 ;
        RECT  21.516 7.632 21.6 7.656 ;
    END
  END b[400]
  PIN b[401]
    DIRECTION OUTPUT ;
    USE SIGNAL ;
    PORT
      LAYER M4 ;
        RECT  21.516 7.776 21.6 7.8 ;
    END
  END b[401]
  PIN b[402]
    DIRECTION OUTPUT ;
    USE SIGNAL ;
    PORT
      LAYER M4 ;
        RECT  21.516 7.92 21.6 7.944 ;
    END
  END b[402]
  PIN b[403]
    DIRECTION OUTPUT ;
    USE SIGNAL ;
    PORT
      LAYER M4 ;
        RECT  21.516 8.064 21.6 8.088 ;
    END
  END b[403]
  PIN b[404]
    DIRECTION OUTPUT ;
    USE SIGNAL ;
    PORT
      LAYER M4 ;
        RECT  21.516 8.208 21.6 8.232 ;
    END
  END b[404]
  PIN b[405]
    DIRECTION OUTPUT ;
    USE SIGNAL ;
    PORT
      LAYER M4 ;
        RECT  21.516 8.352 21.6 8.376 ;
    END
  END b[405]
  PIN b[406]
    DIRECTION OUTPUT ;
    USE SIGNAL ;
    PORT
      LAYER M4 ;
        RECT  21.516 8.496 21.6 8.52 ;
    END
  END b[406]
  PIN b[407]
    DIRECTION OUTPUT ;
    USE SIGNAL ;
    PORT
      LAYER M4 ;
        RECT  21.516 8.64 21.6 8.664 ;
    END
  END b[407]
  PIN b[408]
    DIRECTION OUTPUT ;
    USE SIGNAL ;
    PORT
      LAYER M4 ;
        RECT  21.516 8.784 21.6 8.808 ;
    END
  END b[408]
  PIN b[409]
    DIRECTION OUTPUT ;
    USE SIGNAL ;
    PORT
      LAYER M4 ;
        RECT  21.516 8.928 21.6 8.952 ;
    END
  END b[409]
  PIN b[40]
    DIRECTION OUTPUT ;
    USE SIGNAL ;
    PORT
      LAYER M4 ;
        RECT  21.516 39.888 21.6 39.912 ;
    END
  END b[40]
  PIN b[410]
    DIRECTION OUTPUT ;
    USE SIGNAL ;
    PORT
      LAYER M4 ;
        RECT  21.516 9.072 21.6 9.096 ;
    END
  END b[410]
  PIN b[411]
    DIRECTION OUTPUT ;
    USE SIGNAL ;
    PORT
      LAYER M4 ;
        RECT  21.516 9.216 21.6 9.24 ;
    END
  END b[411]
  PIN b[412]
    DIRECTION OUTPUT ;
    USE SIGNAL ;
    PORT
      LAYER M4 ;
        RECT  21.516 9.36 21.6 9.384 ;
    END
  END b[412]
  PIN b[413]
    DIRECTION OUTPUT ;
    USE SIGNAL ;
    PORT
      LAYER M4 ;
        RECT  21.516 9.504 21.6 9.528 ;
    END
  END b[413]
  PIN b[414]
    DIRECTION OUTPUT ;
    USE SIGNAL ;
    PORT
      LAYER M4 ;
        RECT  21.516 9.648 21.6 9.672 ;
    END
  END b[414]
  PIN b[415]
    DIRECTION OUTPUT ;
    USE SIGNAL ;
    PORT
      LAYER M4 ;
        RECT  21.516 9.792 21.6 9.816 ;
    END
  END b[415]
  PIN b[416]
    DIRECTION OUTPUT ;
    USE SIGNAL ;
    PORT
      LAYER M4 ;
        RECT  21.516 62.928 21.6 62.952 ;
    END
  END b[416]
  PIN b[417]
    DIRECTION OUTPUT ;
    USE SIGNAL ;
    PORT
      LAYER M4 ;
        RECT  21.516 63.072 21.6 63.096 ;
    END
  END b[417]
  PIN b[418]
    DIRECTION OUTPUT ;
    USE SIGNAL ;
    PORT
      LAYER M4 ;
        RECT  21.516 63.216 21.6 63.24 ;
    END
  END b[418]
  PIN b[419]
    DIRECTION OUTPUT ;
    USE SIGNAL ;
    PORT
      LAYER M4 ;
        RECT  21.516 63.36 21.6 63.384 ;
    END
  END b[419]
  PIN b[41]
    DIRECTION OUTPUT ;
    USE SIGNAL ;
    PORT
      LAYER M4 ;
        RECT  21.516 40.032 21.6 40.056 ;
    END
  END b[41]
  PIN b[420]
    DIRECTION OUTPUT ;
    USE SIGNAL ;
    PORT
      LAYER M4 ;
        RECT  21.516 63.504 21.6 63.528 ;
    END
  END b[420]
  PIN b[421]
    DIRECTION OUTPUT ;
    USE SIGNAL ;
    PORT
      LAYER M4 ;
        RECT  21.516 63.648 21.6 63.672 ;
    END
  END b[421]
  PIN b[422]
    DIRECTION OUTPUT ;
    USE SIGNAL ;
    PORT
      LAYER M4 ;
        RECT  21.516 63.792 21.6 63.816 ;
    END
  END b[422]
  PIN b[423]
    DIRECTION OUTPUT ;
    USE SIGNAL ;
    PORT
      LAYER M4 ;
        RECT  21.516 63.936 21.6 63.96 ;
    END
  END b[423]
  PIN b[424]
    DIRECTION OUTPUT ;
    USE SIGNAL ;
    PORT
      LAYER M4 ;
        RECT  21.516 64.08 21.6 64.104 ;
    END
  END b[424]
  PIN b[425]
    DIRECTION OUTPUT ;
    USE SIGNAL ;
    PORT
      LAYER M4 ;
        RECT  21.516 64.224 21.6 64.248 ;
    END
  END b[425]
  PIN b[426]
    DIRECTION OUTPUT ;
    USE SIGNAL ;
    PORT
      LAYER M4 ;
        RECT  21.516 64.368 21.6 64.392 ;
    END
  END b[426]
  PIN b[427]
    DIRECTION OUTPUT ;
    USE SIGNAL ;
    PORT
      LAYER M4 ;
        RECT  21.516 64.512 21.6 64.536 ;
    END
  END b[427]
  PIN b[428]
    DIRECTION OUTPUT ;
    USE SIGNAL ;
    PORT
      LAYER M4 ;
        RECT  21.516 64.656 21.6 64.68 ;
    END
  END b[428]
  PIN b[429]
    DIRECTION OUTPUT ;
    USE SIGNAL ;
    PORT
      LAYER M4 ;
        RECT  21.516 64.8 21.6 64.824 ;
    END
  END b[429]
  PIN b[42]
    DIRECTION OUTPUT ;
    USE SIGNAL ;
    PORT
      LAYER M4 ;
        RECT  21.516 40.176 21.6 40.2 ;
    END
  END b[42]
  PIN b[430]
    DIRECTION OUTPUT ;
    USE SIGNAL ;
    PORT
      LAYER M4 ;
        RECT  21.516 64.944 21.6 64.968 ;
    END
  END b[430]
  PIN b[431]
    DIRECTION OUTPUT ;
    USE SIGNAL ;
    PORT
      LAYER M4 ;
        RECT  21.516 65.088 21.6 65.112 ;
    END
  END b[431]
  PIN b[432]
    DIRECTION OUTPUT ;
    USE SIGNAL ;
    PORT
      LAYER M4 ;
        RECT  21.516 65.232 21.6 65.256 ;
    END
  END b[432]
  PIN b[433]
    DIRECTION OUTPUT ;
    USE SIGNAL ;
    PORT
      LAYER M4 ;
        RECT  21.516 65.376 21.6 65.4 ;
    END
  END b[433]
  PIN b[434]
    DIRECTION OUTPUT ;
    USE SIGNAL ;
    PORT
      LAYER M4 ;
        RECT  21.516 65.52 21.6 65.544 ;
    END
  END b[434]
  PIN b[435]
    DIRECTION OUTPUT ;
    USE SIGNAL ;
    PORT
      LAYER M4 ;
        RECT  21.516 65.664 21.6 65.688 ;
    END
  END b[435]
  PIN b[436]
    DIRECTION OUTPUT ;
    USE SIGNAL ;
    PORT
      LAYER M4 ;
        RECT  21.516 65.808 21.6 65.832 ;
    END
  END b[436]
  PIN b[437]
    DIRECTION OUTPUT ;
    USE SIGNAL ;
    PORT
      LAYER M4 ;
        RECT  21.516 65.952 21.6 65.976 ;
    END
  END b[437]
  PIN b[438]
    DIRECTION OUTPUT ;
    USE SIGNAL ;
    PORT
      LAYER M4 ;
        RECT  21.516 66.096 21.6 66.12 ;
    END
  END b[438]
  PIN b[439]
    DIRECTION OUTPUT ;
    USE SIGNAL ;
    PORT
      LAYER M4 ;
        RECT  21.516 66.24 21.6 66.264 ;
    END
  END b[439]
  PIN b[43]
    DIRECTION OUTPUT ;
    USE SIGNAL ;
    PORT
      LAYER M4 ;
        RECT  21.516 40.32 21.6 40.344 ;
    END
  END b[43]
  PIN b[440]
    DIRECTION OUTPUT ;
    USE SIGNAL ;
    PORT
      LAYER M4 ;
        RECT  21.516 66.384 21.6 66.408 ;
    END
  END b[440]
  PIN b[441]
    DIRECTION OUTPUT ;
    USE SIGNAL ;
    PORT
      LAYER M4 ;
        RECT  21.516 66.528 21.6 66.552 ;
    END
  END b[441]
  PIN b[442]
    DIRECTION OUTPUT ;
    USE SIGNAL ;
    PORT
      LAYER M4 ;
        RECT  21.516 66.672 21.6 66.696 ;
    END
  END b[442]
  PIN b[443]
    DIRECTION OUTPUT ;
    USE SIGNAL ;
    PORT
      LAYER M4 ;
        RECT  21.516 66.816 21.6 66.84 ;
    END
  END b[443]
  PIN b[444]
    DIRECTION OUTPUT ;
    USE SIGNAL ;
    PORT
      LAYER M4 ;
        RECT  21.516 66.96 21.6 66.984 ;
    END
  END b[444]
  PIN b[445]
    DIRECTION OUTPUT ;
    USE SIGNAL ;
    PORT
      LAYER M4 ;
        RECT  21.516 67.104 21.6 67.128 ;
    END
  END b[445]
  PIN b[446]
    DIRECTION OUTPUT ;
    USE SIGNAL ;
    PORT
      LAYER M4 ;
        RECT  21.516 67.248 21.6 67.272 ;
    END
  END b[446]
  PIN b[447]
    DIRECTION OUTPUT ;
    USE SIGNAL ;
    PORT
      LAYER M4 ;
        RECT  21.516 67.392 21.6 67.416 ;
    END
  END b[447]
  PIN b[448]
    DIRECTION OUTPUT ;
    USE SIGNAL ;
    PORT
      LAYER M4 ;
        RECT  21.516 67.536 21.6 67.56 ;
    END
  END b[448]
  PIN b[449]
    DIRECTION OUTPUT ;
    USE SIGNAL ;
    PORT
      LAYER M4 ;
        RECT  21.516 67.68 21.6 67.704 ;
    END
  END b[449]
  PIN b[44]
    DIRECTION OUTPUT ;
    USE SIGNAL ;
    PORT
      LAYER M4 ;
        RECT  21.516 40.464 21.6 40.488 ;
    END
  END b[44]
  PIN b[450]
    DIRECTION OUTPUT ;
    USE SIGNAL ;
    PORT
      LAYER M4 ;
        RECT  21.516 67.824 21.6 67.848 ;
    END
  END b[450]
  PIN b[451]
    DIRECTION OUTPUT ;
    USE SIGNAL ;
    PORT
      LAYER M4 ;
        RECT  21.516 67.968 21.6 67.992 ;
    END
  END b[451]
  PIN b[452]
    DIRECTION OUTPUT ;
    USE SIGNAL ;
    PORT
      LAYER M4 ;
        RECT  21.516 68.112 21.6 68.136 ;
    END
  END b[452]
  PIN b[453]
    DIRECTION OUTPUT ;
    USE SIGNAL ;
    PORT
      LAYER M4 ;
        RECT  21.516 68.256 21.6 68.28 ;
    END
  END b[453]
  PIN b[454]
    DIRECTION OUTPUT ;
    USE SIGNAL ;
    PORT
      LAYER M4 ;
        RECT  21.516 68.4 21.6 68.424 ;
    END
  END b[454]
  PIN b[455]
    DIRECTION OUTPUT ;
    USE SIGNAL ;
    PORT
      LAYER M4 ;
        RECT  21.516 68.544 21.6 68.568 ;
    END
  END b[455]
  PIN b[456]
    DIRECTION OUTPUT ;
    USE SIGNAL ;
    PORT
      LAYER M4 ;
        RECT  21.516 68.688 21.6 68.712 ;
    END
  END b[456]
  PIN b[457]
    DIRECTION OUTPUT ;
    USE SIGNAL ;
    PORT
      LAYER M4 ;
        RECT  21.516 68.832 21.6 68.856 ;
    END
  END b[457]
  PIN b[458]
    DIRECTION OUTPUT ;
    USE SIGNAL ;
    PORT
      LAYER M4 ;
        RECT  21.516 68.976 21.6 69 ;
    END
  END b[458]
  PIN b[459]
    DIRECTION OUTPUT ;
    USE SIGNAL ;
    PORT
      LAYER M4 ;
        RECT  21.516 69.12 21.6 69.144 ;
    END
  END b[459]
  PIN b[45]
    DIRECTION OUTPUT ;
    USE SIGNAL ;
    PORT
      LAYER M4 ;
        RECT  21.516 40.608 21.6 40.632 ;
    END
  END b[45]
  PIN b[460]
    DIRECTION OUTPUT ;
    USE SIGNAL ;
    PORT
      LAYER M4 ;
        RECT  21.516 69.264 21.6 69.288 ;
    END
  END b[460]
  PIN b[461]
    DIRECTION OUTPUT ;
    USE SIGNAL ;
    PORT
      LAYER M4 ;
        RECT  21.516 69.408 21.6 69.432 ;
    END
  END b[461]
  PIN b[462]
    DIRECTION OUTPUT ;
    USE SIGNAL ;
    PORT
      LAYER M4 ;
        RECT  21.516 69.552 21.6 69.576 ;
    END
  END b[462]
  PIN b[463]
    DIRECTION OUTPUT ;
    USE SIGNAL ;
    PORT
      LAYER M4 ;
        RECT  21.516 69.696 21.6 69.72 ;
    END
  END b[463]
  PIN b[464]
    DIRECTION OUTPUT ;
    USE SIGNAL ;
    PORT
      LAYER M4 ;
        RECT  21.516 69.84 21.6 69.864 ;
    END
  END b[464]
  PIN b[465]
    DIRECTION OUTPUT ;
    USE SIGNAL ;
    PORT
      LAYER M4 ;
        RECT  21.516 69.984 21.6 70.008 ;
    END
  END b[465]
  PIN b[466]
    DIRECTION OUTPUT ;
    USE SIGNAL ;
    PORT
      LAYER M4 ;
        RECT  21.516 70.128 21.6 70.152 ;
    END
  END b[466]
  PIN b[467]
    DIRECTION OUTPUT ;
    USE SIGNAL ;
    PORT
      LAYER M4 ;
        RECT  21.516 70.272 21.6 70.296 ;
    END
  END b[467]
  PIN b[468]
    DIRECTION OUTPUT ;
    USE SIGNAL ;
    PORT
      LAYER M4 ;
        RECT  21.516 70.416 21.6 70.44 ;
    END
  END b[468]
  PIN b[469]
    DIRECTION OUTPUT ;
    USE SIGNAL ;
    PORT
      LAYER M4 ;
        RECT  21.516 70.56 21.6 70.584 ;
    END
  END b[469]
  PIN b[46]
    DIRECTION OUTPUT ;
    USE SIGNAL ;
    PORT
      LAYER M4 ;
        RECT  21.516 40.752 21.6 40.776 ;
    END
  END b[46]
  PIN b[470]
    DIRECTION OUTPUT ;
    USE SIGNAL ;
    PORT
      LAYER M4 ;
        RECT  21.516 70.704 21.6 70.728 ;
    END
  END b[470]
  PIN b[471]
    DIRECTION OUTPUT ;
    USE SIGNAL ;
    PORT
      LAYER M4 ;
        RECT  21.516 70.848 21.6 70.872 ;
    END
  END b[471]
  PIN b[472]
    DIRECTION OUTPUT ;
    USE SIGNAL ;
    PORT
      LAYER M4 ;
        RECT  21.516 70.992 21.6 71.016 ;
    END
  END b[472]
  PIN b[473]
    DIRECTION OUTPUT ;
    USE SIGNAL ;
    PORT
      LAYER M4 ;
        RECT  21.516 71.136 21.6 71.16 ;
    END
  END b[473]
  PIN b[474]
    DIRECTION OUTPUT ;
    USE SIGNAL ;
    PORT
      LAYER M4 ;
        RECT  21.516 71.28 21.6 71.304 ;
    END
  END b[474]
  PIN b[475]
    DIRECTION OUTPUT ;
    USE SIGNAL ;
    PORT
      LAYER M4 ;
        RECT  21.516 71.424 21.6 71.448 ;
    END
  END b[475]
  PIN b[476]
    DIRECTION OUTPUT ;
    USE SIGNAL ;
    PORT
      LAYER M4 ;
        RECT  21.516 71.568 21.6 71.592 ;
    END
  END b[476]
  PIN b[477]
    DIRECTION OUTPUT ;
    USE SIGNAL ;
    PORT
      LAYER M4 ;
        RECT  21.516 71.712 21.6 71.736 ;
    END
  END b[477]
  PIN b[478]
    DIRECTION OUTPUT ;
    USE SIGNAL ;
    PORT
      LAYER M4 ;
        RECT  21.516 71.856 21.6 71.88 ;
    END
  END b[478]
  PIN b[479]
    DIRECTION OUTPUT ;
    USE SIGNAL ;
    PORT
      LAYER M4 ;
        RECT  21.516 72 21.6 72.024 ;
    END
  END b[479]
  PIN b[47]
    DIRECTION OUTPUT ;
    USE SIGNAL ;
    PORT
      LAYER M4 ;
        RECT  21.516 40.896 21.6 40.92 ;
    END
  END b[47]
  PIN b[480]
    DIRECTION OUTPUT ;
    USE SIGNAL ;
    PORT
      LAYER M4 ;
        RECT  21.516 58.32 21.6 58.344 ;
    END
  END b[480]
  PIN b[481]
    DIRECTION OUTPUT ;
    USE SIGNAL ;
    PORT
      LAYER M4 ;
        RECT  21.516 58.464 21.6 58.488 ;
    END
  END b[481]
  PIN b[482]
    DIRECTION OUTPUT ;
    USE SIGNAL ;
    PORT
      LAYER M4 ;
        RECT  21.516 58.608 21.6 58.632 ;
    END
  END b[482]
  PIN b[483]
    DIRECTION OUTPUT ;
    USE SIGNAL ;
    PORT
      LAYER M4 ;
        RECT  21.516 58.752 21.6 58.776 ;
    END
  END b[483]
  PIN b[484]
    DIRECTION OUTPUT ;
    USE SIGNAL ;
    PORT
      LAYER M4 ;
        RECT  21.516 58.896 21.6 58.92 ;
    END
  END b[484]
  PIN b[485]
    DIRECTION OUTPUT ;
    USE SIGNAL ;
    PORT
      LAYER M4 ;
        RECT  21.516 59.04 21.6 59.064 ;
    END
  END b[485]
  PIN b[486]
    DIRECTION OUTPUT ;
    USE SIGNAL ;
    PORT
      LAYER M4 ;
        RECT  21.516 59.184 21.6 59.208 ;
    END
  END b[486]
  PIN b[487]
    DIRECTION OUTPUT ;
    USE SIGNAL ;
    PORT
      LAYER M4 ;
        RECT  21.516 59.328 21.6 59.352 ;
    END
  END b[487]
  PIN b[488]
    DIRECTION OUTPUT ;
    USE SIGNAL ;
    PORT
      LAYER M4 ;
        RECT  21.516 59.472 21.6 59.496 ;
    END
  END b[488]
  PIN b[489]
    DIRECTION OUTPUT ;
    USE SIGNAL ;
    PORT
      LAYER M4 ;
        RECT  21.516 59.616 21.6 59.64 ;
    END
  END b[489]
  PIN b[48]
    DIRECTION OUTPUT ;
    USE SIGNAL ;
    PORT
      LAYER M4 ;
        RECT  21.516 41.04 21.6 41.064 ;
    END
  END b[48]
  PIN b[490]
    DIRECTION OUTPUT ;
    USE SIGNAL ;
    PORT
      LAYER M4 ;
        RECT  21.516 59.76 21.6 59.784 ;
    END
  END b[490]
  PIN b[491]
    DIRECTION OUTPUT ;
    USE SIGNAL ;
    PORT
      LAYER M4 ;
        RECT  21.516 59.904 21.6 59.928 ;
    END
  END b[491]
  PIN b[492]
    DIRECTION OUTPUT ;
    USE SIGNAL ;
    PORT
      LAYER M4 ;
        RECT  21.516 60.048 21.6 60.072 ;
    END
  END b[492]
  PIN b[493]
    DIRECTION OUTPUT ;
    USE SIGNAL ;
    PORT
      LAYER M4 ;
        RECT  21.516 60.192 21.6 60.216 ;
    END
  END b[493]
  PIN b[494]
    DIRECTION OUTPUT ;
    USE SIGNAL ;
    PORT
      LAYER M4 ;
        RECT  21.516 60.336 21.6 60.36 ;
    END
  END b[494]
  PIN b[495]
    DIRECTION OUTPUT ;
    USE SIGNAL ;
    PORT
      LAYER M4 ;
        RECT  21.516 60.48 21.6 60.504 ;
    END
  END b[495]
  PIN b[496]
    DIRECTION OUTPUT ;
    USE SIGNAL ;
    PORT
      LAYER M4 ;
        RECT  21.516 60.624 21.6 60.648 ;
    END
  END b[496]
  PIN b[497]
    DIRECTION OUTPUT ;
    USE SIGNAL ;
    PORT
      LAYER M4 ;
        RECT  21.516 60.768 21.6 60.792 ;
    END
  END b[497]
  PIN b[498]
    DIRECTION OUTPUT ;
    USE SIGNAL ;
    PORT
      LAYER M4 ;
        RECT  21.516 60.912 21.6 60.936 ;
    END
  END b[498]
  PIN b[499]
    DIRECTION OUTPUT ;
    USE SIGNAL ;
    PORT
      LAYER M4 ;
        RECT  21.516 61.056 21.6 61.08 ;
    END
  END b[499]
  PIN b[49]
    DIRECTION OUTPUT ;
    USE SIGNAL ;
    PORT
      LAYER M4 ;
        RECT  21.516 41.184 21.6 41.208 ;
    END
  END b[49]
  PIN b[4]
    DIRECTION OUTPUT ;
    USE SIGNAL ;
    PORT
      LAYER M4 ;
        RECT  21.516 53.136 21.6 53.16 ;
    END
  END b[4]
  PIN b[500]
    DIRECTION OUTPUT ;
    USE SIGNAL ;
    PORT
      LAYER M4 ;
        RECT  21.516 61.2 21.6 61.224 ;
    END
  END b[500]
  PIN b[501]
    DIRECTION OUTPUT ;
    USE SIGNAL ;
    PORT
      LAYER M4 ;
        RECT  21.516 61.344 21.6 61.368 ;
    END
  END b[501]
  PIN b[502]
    DIRECTION OUTPUT ;
    USE SIGNAL ;
    PORT
      LAYER M4 ;
        RECT  21.516 61.488 21.6 61.512 ;
    END
  END b[502]
  PIN b[503]
    DIRECTION OUTPUT ;
    USE SIGNAL ;
    PORT
      LAYER M4 ;
        RECT  21.516 61.632 21.6 61.656 ;
    END
  END b[503]
  PIN b[504]
    DIRECTION OUTPUT ;
    USE SIGNAL ;
    PORT
      LAYER M4 ;
        RECT  21.516 61.776 21.6 61.8 ;
    END
  END b[504]
  PIN b[505]
    DIRECTION OUTPUT ;
    USE SIGNAL ;
    PORT
      LAYER M4 ;
        RECT  21.516 61.92 21.6 61.944 ;
    END
  END b[505]
  PIN b[506]
    DIRECTION OUTPUT ;
    USE SIGNAL ;
    PORT
      LAYER M4 ;
        RECT  21.516 62.064 21.6 62.088 ;
    END
  END b[506]
  PIN b[507]
    DIRECTION OUTPUT ;
    USE SIGNAL ;
    PORT
      LAYER M4 ;
        RECT  21.516 62.208 21.6 62.232 ;
    END
  END b[507]
  PIN b[508]
    DIRECTION OUTPUT ;
    USE SIGNAL ;
    PORT
      LAYER M4 ;
        RECT  21.516 62.352 21.6 62.376 ;
    END
  END b[508]
  PIN b[509]
    DIRECTION OUTPUT ;
    USE SIGNAL ;
    PORT
      LAYER M4 ;
        RECT  21.516 62.496 21.6 62.52 ;
    END
  END b[509]
  PIN b[50]
    DIRECTION OUTPUT ;
    USE SIGNAL ;
    PORT
      LAYER M4 ;
        RECT  21.516 41.328 21.6 41.352 ;
    END
  END b[50]
  PIN b[510]
    DIRECTION OUTPUT ;
    USE SIGNAL ;
    PORT
      LAYER M4 ;
        RECT  21.516 62.64 21.6 62.664 ;
    END
  END b[510]
  PIN b[511]
    DIRECTION OUTPUT ;
    USE SIGNAL ;
    PORT
      LAYER M4 ;
        RECT  21.516 62.784 21.6 62.808 ;
    END
  END b[511]
  PIN b[512]
    DIRECTION OUTPUT ;
    USE SIGNAL ;
    PORT
      LAYER M4 ;
        RECT  21.516 76.752 21.6 76.776 ;
    END
  END b[512]
  PIN b[513]
    DIRECTION OUTPUT ;
    USE SIGNAL ;
    PORT
      LAYER M4 ;
        RECT  21.516 76.896 21.6 76.92 ;
    END
  END b[513]
  PIN b[514]
    DIRECTION OUTPUT ;
    USE SIGNAL ;
    PORT
      LAYER M4 ;
        RECT  21.516 77.04 21.6 77.064 ;
    END
  END b[514]
  PIN b[515]
    DIRECTION OUTPUT ;
    USE SIGNAL ;
    PORT
      LAYER M4 ;
        RECT  21.516 77.184 21.6 77.208 ;
    END
  END b[515]
  PIN b[516]
    DIRECTION OUTPUT ;
    USE SIGNAL ;
    PORT
      LAYER M4 ;
        RECT  21.516 77.328 21.6 77.352 ;
    END
  END b[516]
  PIN b[517]
    DIRECTION OUTPUT ;
    USE SIGNAL ;
    PORT
      LAYER M4 ;
        RECT  21.516 77.472 21.6 77.496 ;
    END
  END b[517]
  PIN b[518]
    DIRECTION OUTPUT ;
    USE SIGNAL ;
    PORT
      LAYER M4 ;
        RECT  21.516 77.616 21.6 77.64 ;
    END
  END b[518]
  PIN b[519]
    DIRECTION OUTPUT ;
    USE SIGNAL ;
    PORT
      LAYER M4 ;
        RECT  21.516 77.76 21.6 77.784 ;
    END
  END b[519]
  PIN b[51]
    DIRECTION OUTPUT ;
    USE SIGNAL ;
    PORT
      LAYER M4 ;
        RECT  21.516 41.472 21.6 41.496 ;
    END
  END b[51]
  PIN b[520]
    DIRECTION OUTPUT ;
    USE SIGNAL ;
    PORT
      LAYER M4 ;
        RECT  21.516 77.904 21.6 77.928 ;
    END
  END b[520]
  PIN b[521]
    DIRECTION OUTPUT ;
    USE SIGNAL ;
    PORT
      LAYER M4 ;
        RECT  21.516 78.048 21.6 78.072 ;
    END
  END b[521]
  PIN b[522]
    DIRECTION OUTPUT ;
    USE SIGNAL ;
    PORT
      LAYER M4 ;
        RECT  21.516 78.192 21.6 78.216 ;
    END
  END b[522]
  PIN b[523]
    DIRECTION OUTPUT ;
    USE SIGNAL ;
    PORT
      LAYER M4 ;
        RECT  21.516 78.336 21.6 78.36 ;
    END
  END b[523]
  PIN b[524]
    DIRECTION OUTPUT ;
    USE SIGNAL ;
    PORT
      LAYER M4 ;
        RECT  21.516 78.48 21.6 78.504 ;
    END
  END b[524]
  PIN b[525]
    DIRECTION OUTPUT ;
    USE SIGNAL ;
    PORT
      LAYER M4 ;
        RECT  21.516 78.624 21.6 78.648 ;
    END
  END b[525]
  PIN b[526]
    DIRECTION OUTPUT ;
    USE SIGNAL ;
    PORT
      LAYER M4 ;
        RECT  21.516 78.768 21.6 78.792 ;
    END
  END b[526]
  PIN b[527]
    DIRECTION OUTPUT ;
    USE SIGNAL ;
    PORT
      LAYER M4 ;
        RECT  21.516 78.912 21.6 78.936 ;
    END
  END b[527]
  PIN b[52]
    DIRECTION OUTPUT ;
    USE SIGNAL ;
    PORT
      LAYER M4 ;
        RECT  21.516 41.616 21.6 41.64 ;
    END
  END b[52]
  PIN b[53]
    DIRECTION OUTPUT ;
    USE SIGNAL ;
    PORT
      LAYER M4 ;
        RECT  21.516 41.76 21.6 41.784 ;
    END
  END b[53]
  PIN b[54]
    DIRECTION OUTPUT ;
    USE SIGNAL ;
    PORT
      LAYER M4 ;
        RECT  21.516 41.904 21.6 41.928 ;
    END
  END b[54]
  PIN b[55]
    DIRECTION OUTPUT ;
    USE SIGNAL ;
    PORT
      LAYER M4 ;
        RECT  21.516 42.048 21.6 42.072 ;
    END
  END b[55]
  PIN b[56]
    DIRECTION OUTPUT ;
    USE SIGNAL ;
    PORT
      LAYER M4 ;
        RECT  21.516 42.192 21.6 42.216 ;
    END
  END b[56]
  PIN b[57]
    DIRECTION OUTPUT ;
    USE SIGNAL ;
    PORT
      LAYER M4 ;
        RECT  21.516 42.336 21.6 42.36 ;
    END
  END b[57]
  PIN b[58]
    DIRECTION OUTPUT ;
    USE SIGNAL ;
    PORT
      LAYER M4 ;
        RECT  21.516 42.48 21.6 42.504 ;
    END
  END b[58]
  PIN b[59]
    DIRECTION OUTPUT ;
    USE SIGNAL ;
    PORT
      LAYER M4 ;
        RECT  21.516 42.624 21.6 42.648 ;
    END
  END b[59]
  PIN b[5]
    DIRECTION OUTPUT ;
    USE SIGNAL ;
    PORT
      LAYER M4 ;
        RECT  21.516 53.28 21.6 53.304 ;
    END
  END b[5]
  PIN b[60]
    DIRECTION OUTPUT ;
    USE SIGNAL ;
    PORT
      LAYER M4 ;
        RECT  21.516 42.768 21.6 42.792 ;
    END
  END b[60]
  PIN b[61]
    DIRECTION OUTPUT ;
    USE SIGNAL ;
    PORT
      LAYER M4 ;
        RECT  21.516 42.912 21.6 42.936 ;
    END
  END b[61]
  PIN b[62]
    DIRECTION OUTPUT ;
    USE SIGNAL ;
    PORT
      LAYER M4 ;
        RECT  21.516 43.056 21.6 43.08 ;
    END
  END b[62]
  PIN b[63]
    DIRECTION OUTPUT ;
    USE SIGNAL ;
    PORT
      LAYER M4 ;
        RECT  21.516 43.2 21.6 43.224 ;
    END
  END b[63]
  PIN b[64]
    DIRECTION OUTPUT ;
    USE SIGNAL ;
    PORT
      LAYER M4 ;
        RECT  21.516 34.128 21.6 34.152 ;
    END
  END b[64]
  PIN b[65]
    DIRECTION OUTPUT ;
    USE SIGNAL ;
    PORT
      LAYER M4 ;
        RECT  21.516 34.272 21.6 34.296 ;
    END
  END b[65]
  PIN b[66]
    DIRECTION OUTPUT ;
    USE SIGNAL ;
    PORT
      LAYER M4 ;
        RECT  21.516 34.416 21.6 34.44 ;
    END
  END b[66]
  PIN b[67]
    DIRECTION OUTPUT ;
    USE SIGNAL ;
    PORT
      LAYER M4 ;
        RECT  21.516 34.56 21.6 34.584 ;
    END
  END b[67]
  PIN b[68]
    DIRECTION OUTPUT ;
    USE SIGNAL ;
    PORT
      LAYER M4 ;
        RECT  21.516 34.704 21.6 34.728 ;
    END
  END b[68]
  PIN b[69]
    DIRECTION OUTPUT ;
    USE SIGNAL ;
    PORT
      LAYER M4 ;
        RECT  21.516 34.848 21.6 34.872 ;
    END
  END b[69]
  PIN b[6]
    DIRECTION OUTPUT ;
    USE SIGNAL ;
    PORT
      LAYER M4 ;
        RECT  21.516 53.424 21.6 53.448 ;
    END
  END b[6]
  PIN b[70]
    DIRECTION OUTPUT ;
    USE SIGNAL ;
    PORT
      LAYER M4 ;
        RECT  21.516 34.992 21.6 35.016 ;
    END
  END b[70]
  PIN b[71]
    DIRECTION OUTPUT ;
    USE SIGNAL ;
    PORT
      LAYER M4 ;
        RECT  21.516 35.136 21.6 35.16 ;
    END
  END b[71]
  PIN b[72]
    DIRECTION OUTPUT ;
    USE SIGNAL ;
    PORT
      LAYER M4 ;
        RECT  21.516 35.28 21.6 35.304 ;
    END
  END b[72]
  PIN b[73]
    DIRECTION OUTPUT ;
    USE SIGNAL ;
    PORT
      LAYER M4 ;
        RECT  21.516 35.424 21.6 35.448 ;
    END
  END b[73]
  PIN b[74]
    DIRECTION OUTPUT ;
    USE SIGNAL ;
    PORT
      LAYER M4 ;
        RECT  21.516 35.568 21.6 35.592 ;
    END
  END b[74]
  PIN b[75]
    DIRECTION OUTPUT ;
    USE SIGNAL ;
    PORT
      LAYER M4 ;
        RECT  21.516 35.712 21.6 35.736 ;
    END
  END b[75]
  PIN b[76]
    DIRECTION OUTPUT ;
    USE SIGNAL ;
    PORT
      LAYER M4 ;
        RECT  21.516 35.856 21.6 35.88 ;
    END
  END b[76]
  PIN b[77]
    DIRECTION OUTPUT ;
    USE SIGNAL ;
    PORT
      LAYER M4 ;
        RECT  21.516 36 21.6 36.024 ;
    END
  END b[77]
  PIN b[78]
    DIRECTION OUTPUT ;
    USE SIGNAL ;
    PORT
      LAYER M4 ;
        RECT  21.516 36.144 21.6 36.168 ;
    END
  END b[78]
  PIN b[79]
    DIRECTION OUTPUT ;
    USE SIGNAL ;
    PORT
      LAYER M4 ;
        RECT  21.516 36.288 21.6 36.312 ;
    END
  END b[79]
  PIN b[7]
    DIRECTION OUTPUT ;
    USE SIGNAL ;
    PORT
      LAYER M4 ;
        RECT  21.516 53.568 21.6 53.592 ;
    END
  END b[7]
  PIN b[80]
    DIRECTION OUTPUT ;
    USE SIGNAL ;
    PORT
      LAYER M4 ;
        RECT  21.516 36.432 21.6 36.456 ;
    END
  END b[80]
  PIN b[81]
    DIRECTION OUTPUT ;
    USE SIGNAL ;
    PORT
      LAYER M4 ;
        RECT  21.516 36.576 21.6 36.6 ;
    END
  END b[81]
  PIN b[82]
    DIRECTION OUTPUT ;
    USE SIGNAL ;
    PORT
      LAYER M4 ;
        RECT  21.516 36.72 21.6 36.744 ;
    END
  END b[82]
  PIN b[83]
    DIRECTION OUTPUT ;
    USE SIGNAL ;
    PORT
      LAYER M4 ;
        RECT  21.516 36.864 21.6 36.888 ;
    END
  END b[83]
  PIN b[84]
    DIRECTION OUTPUT ;
    USE SIGNAL ;
    PORT
      LAYER M4 ;
        RECT  21.516 37.008 21.6 37.032 ;
    END
  END b[84]
  PIN b[85]
    DIRECTION OUTPUT ;
    USE SIGNAL ;
    PORT
      LAYER M4 ;
        RECT  21.516 37.152 21.6 37.176 ;
    END
  END b[85]
  PIN b[86]
    DIRECTION OUTPUT ;
    USE SIGNAL ;
    PORT
      LAYER M4 ;
        RECT  21.516 37.296 21.6 37.32 ;
    END
  END b[86]
  PIN b[87]
    DIRECTION OUTPUT ;
    USE SIGNAL ;
    PORT
      LAYER M4 ;
        RECT  21.516 37.44 21.6 37.464 ;
    END
  END b[87]
  PIN b[88]
    DIRECTION OUTPUT ;
    USE SIGNAL ;
    PORT
      LAYER M4 ;
        RECT  21.516 37.584 21.6 37.608 ;
    END
  END b[88]
  PIN b[89]
    DIRECTION OUTPUT ;
    USE SIGNAL ;
    PORT
      LAYER M4 ;
        RECT  21.516 37.728 21.6 37.752 ;
    END
  END b[89]
  PIN b[8]
    DIRECTION OUTPUT ;
    USE SIGNAL ;
    PORT
      LAYER M4 ;
        RECT  21.516 53.712 21.6 53.736 ;
    END
  END b[8]
  PIN b[90]
    DIRECTION OUTPUT ;
    USE SIGNAL ;
    PORT
      LAYER M4 ;
        RECT  21.516 37.872 21.6 37.896 ;
    END
  END b[90]
  PIN b[91]
    DIRECTION OUTPUT ;
    USE SIGNAL ;
    PORT
      LAYER M4 ;
        RECT  21.516 38.016 21.6 38.04 ;
    END
  END b[91]
  PIN b[92]
    DIRECTION OUTPUT ;
    USE SIGNAL ;
    PORT
      LAYER M4 ;
        RECT  21.516 38.16 21.6 38.184 ;
    END
  END b[92]
  PIN b[93]
    DIRECTION OUTPUT ;
    USE SIGNAL ;
    PORT
      LAYER M4 ;
        RECT  21.516 38.304 21.6 38.328 ;
    END
  END b[93]
  PIN b[94]
    DIRECTION OUTPUT ;
    USE SIGNAL ;
    PORT
      LAYER M4 ;
        RECT  21.516 38.448 21.6 38.472 ;
    END
  END b[94]
  PIN b[95]
    DIRECTION OUTPUT ;
    USE SIGNAL ;
    PORT
      LAYER M4 ;
        RECT  21.516 38.592 21.6 38.616 ;
    END
  END b[95]
  PIN b[96]
    DIRECTION OUTPUT ;
    USE SIGNAL ;
    PORT
      LAYER M4 ;
        RECT  21.516 43.344 21.6 43.368 ;
    END
  END b[96]
  PIN b[97]
    DIRECTION OUTPUT ;
    USE SIGNAL ;
    PORT
      LAYER M4 ;
        RECT  21.516 43.488 21.6 43.512 ;
    END
  END b[97]
  PIN b[98]
    DIRECTION OUTPUT ;
    USE SIGNAL ;
    PORT
      LAYER M4 ;
        RECT  21.516 43.632 21.6 43.656 ;
    END
  END b[98]
  PIN b[99]
    DIRECTION OUTPUT ;
    USE SIGNAL ;
    PORT
      LAYER M4 ;
        RECT  21.516 43.776 21.6 43.8 ;
    END
  END b[99]
  PIN b[9]
    DIRECTION OUTPUT ;
    USE SIGNAL ;
    PORT
      LAYER M4 ;
        RECT  21.516 53.856 21.6 53.88 ;
    END
  END b[9]
  PIN ck_o
    DIRECTION OUTPUT ;
    USE SIGNAL ;
    PORT
      LAYER M5 ;
        RECT  15.984 81.996 16.008 82.08 ;
    END
  END ck_o
  PIN ckf
    DIRECTION INPUT ;
    USE SIGNAL ;
    PORT
      LAYER M3 ;
        RECT  15.012 0 15.03 0.037 ;
    END
  END ckf
  PIN ea
    DIRECTION INPUT ;
    USE SIGNAL ;
    PORT
      LAYER M3 ;
        RECT  15.12 0 15.138 0.037 ;
    END
  END ea
  PIN eb
    DIRECTION OUTPUT ;
    USE SIGNAL ;
    PORT
      LAYER M5 ;
        RECT  16.128 81.996 16.152 82.08 ;
    END
  END eb
  PIN VDD
    DIRECTION INOUT ;
    USE POWER ;
    PORT
      LAYER M5 ;
        RECT  18.792 2.151 18.912 79.929 ;
        RECT  16.092 2.151 16.212 79.929 ;
        RECT  13.392 2.151 13.512 79.929 ;
        RECT  10.692 2.151 10.812 79.929 ;
        RECT  7.992 2.151 8.112 79.929 ;
        RECT  5.292 2.151 5.412 79.929 ;
        RECT  2.592 2.151 2.712 79.929 ;
    END
  END VDD
  PIN VSS
    DIRECTION INOUT ;
    USE GROUND ;
    PORT
      LAYER M5 ;
        RECT  18.6 2.137 18.72 79.943 ;
        RECT  15.9 2.137 16.02 79.943 ;
        RECT  13.2 2.137 13.32 79.943 ;
        RECT  10.5 2.137 10.62 79.943 ;
        RECT  7.8 2.137 7.92 79.943 ;
        RECT  5.1 2.137 5.22 79.943 ;
        RECT  2.4 2.137 2.52 79.943 ;
    END
  END VSS
  # OT_OBS_CLOSED layer=M5 d_um=1.536 added=41
  OBS
    LAYER RVTN ;
     RECT  2.16 2.16 19.44 2.295 ;
     RECT  2.16 2.565 19.44 2.835 ;
     RECT  2.16 3.105 19.44 3.375 ;
     RECT  2.16 3.645 19.44 3.915 ;
     RECT  2.16 4.185 19.44 4.455 ;
     RECT  2.16 4.725 19.44 4.995 ;
     RECT  2.16 5.265 19.44 5.535 ;
     RECT  2.16 5.805 19.44 6.075 ;
     RECT  2.16 6.345 19.44 6.615 ;
     RECT  2.16 6.885 19.44 7.155 ;
     RECT  2.16 7.425 19.44 7.695 ;
     RECT  2.16 7.965 19.44 8.235 ;
     RECT  2.16 8.505 19.44 8.775 ;
     RECT  2.16 9.045 19.44 9.315 ;
     RECT  2.16 9.585 19.44 9.855 ;
     RECT  2.16 10.125 19.44 10.395 ;
     RECT  2.16 10.665 19.44 10.935 ;
     RECT  2.16 11.205 19.44 11.475 ;
     RECT  2.16 11.745 19.44 12.015 ;
     RECT  2.16 12.285 19.44 12.555 ;
     RECT  2.16 12.825 19.44 13.095 ;
     RECT  2.16 13.365 19.44 13.635 ;
     RECT  2.16 13.905 19.44 14.175 ;
     RECT  2.16 14.445 19.44 14.715 ;
     RECT  2.16 14.985 19.44 15.255 ;
     RECT  2.16 15.525 19.44 15.795 ;
     RECT  2.16 16.065 19.44 16.335 ;
     RECT  2.16 16.605 19.44 16.875 ;
     RECT  2.16 17.145 19.44 17.415 ;
     RECT  2.16 17.685 19.44 17.955 ;
     RECT  2.16 18.225 19.44 18.495 ;
     RECT  2.16 18.765 19.44 19.035 ;
     RECT  2.16 19.305 19.44 19.575 ;
     RECT  2.16 19.845 19.44 20.115 ;
     RECT  2.16 20.385 19.44 20.655 ;
     RECT  2.16 20.925 19.44 21.195 ;
     RECT  2.16 21.465 19.44 21.735 ;
     RECT  2.16 22.005 19.44 22.275 ;
     RECT  2.16 22.545 19.44 22.815 ;
     RECT  2.16 23.085 19.44 23.355 ;
     RECT  2.16 23.625 19.44 23.895 ;
     RECT  2.16 24.165 19.44 24.435 ;
     RECT  2.16 24.705 19.44 24.975 ;
     RECT  2.16 25.245 19.44 25.515 ;
     RECT  2.16 25.785 19.44 26.055 ;
     RECT  2.16 26.325 19.44 26.595 ;
     RECT  2.16 26.865 19.44 27.135 ;
     RECT  2.16 27.405 19.44 27.675 ;
     RECT  2.16 27.945 19.44 28.215 ;
     RECT  2.16 28.485 19.44 28.755 ;
     RECT  2.16 29.025 19.44 29.295 ;
     RECT  2.16 29.565 19.44 29.835 ;
     RECT  2.16 30.105 19.44 30.375 ;
     RECT  2.16 30.645 19.44 30.915 ;
     RECT  2.16 31.185 19.44 31.455 ;
     RECT  2.16 31.725 19.44 31.995 ;
     RECT  2.16 32.265 19.44 32.535 ;
     RECT  2.16 32.805 19.44 33.075 ;
     RECT  2.16 33.345 19.44 33.615 ;
     RECT  2.16 33.885 19.44 34.155 ;
     RECT  2.16 34.425 19.44 34.695 ;
     RECT  2.16 34.965 19.44 35.235 ;
     RECT  2.16 35.505 19.44 35.775 ;
     RECT  2.16 36.045 19.44 36.315 ;
     RECT  2.16 36.585 19.44 36.855 ;
     RECT  2.16 37.125 19.44 37.395 ;
     RECT  2.16 37.665 19.44 37.935 ;
     RECT  2.16 38.205 19.44 38.475 ;
     RECT  2.16 38.745 19.44 39.015 ;
     RECT  2.16 39.285 19.44 39.555 ;
     RECT  2.16 39.825 19.44 40.095 ;
     RECT  2.16 40.365 19.44 40.635 ;
     RECT  2.16 40.905 19.44 41.175 ;
     RECT  2.16 41.445 19.44 41.715 ;
     RECT  2.16 41.985 19.44 42.255 ;
     RECT  2.16 42.525 19.44 42.795 ;
     RECT  2.16 43.065 19.44 43.335 ;
     RECT  2.16 43.605 19.44 43.875 ;
     RECT  2.16 44.145 19.44 44.415 ;
     RECT  2.16 44.685 19.44 44.955 ;
     RECT  2.16 45.225 19.44 45.495 ;
     RECT  2.16 45.765 19.44 46.035 ;
     RECT  2.16 46.305 19.44 46.575 ;
     RECT  2.16 46.845 19.44 47.115 ;
     RECT  2.16 47.385 19.44 47.655 ;
     RECT  2.16 47.925 19.44 48.195 ;
     RECT  2.16 48.465 19.44 48.735 ;
     RECT  2.16 49.005 19.44 49.275 ;
     RECT  2.16 49.545 19.44 49.815 ;
     RECT  2.16 50.085 19.44 50.355 ;
     RECT  2.16 50.625 19.44 50.895 ;
     RECT  2.16 51.165 19.44 51.435 ;
     RECT  2.16 51.705 19.44 51.975 ;
     RECT  2.16 52.245 19.44 52.515 ;
     RECT  2.16 52.785 19.44 53.055 ;
     RECT  2.16 53.325 19.44 53.595 ;
     RECT  2.16 53.865 19.44 54.135 ;
     RECT  2.16 54.405 19.44 54.675 ;
     RECT  2.16 54.945 19.44 55.215 ;
     RECT  2.16 55.485 19.44 55.755 ;
     RECT  2.16 56.025 19.44 56.295 ;
     RECT  2.16 56.565 19.44 56.835 ;
     RECT  2.16 57.105 19.44 57.375 ;
     RECT  2.16 57.645 19.44 57.915 ;
     RECT  2.16 58.185 19.44 58.455 ;
     RECT  2.16 58.725 19.44 58.995 ;
     RECT  2.16 59.265 19.44 59.535 ;
     RECT  2.16 59.805 19.44 60.075 ;
     RECT  2.16 60.345 19.44 60.615 ;
     RECT  2.16 60.885 19.44 61.155 ;
     RECT  2.16 61.425 19.44 61.695 ;
     RECT  2.16 61.965 19.44 62.235 ;
     RECT  2.16 62.505 19.44 62.775 ;
     RECT  2.16 63.045 19.44 63.315 ;
     RECT  2.16 63.585 19.44 63.855 ;
     RECT  2.16 64.125 19.44 64.395 ;
     RECT  2.16 64.665 19.44 64.935 ;
     RECT  2.16 65.205 19.44 65.475 ;
     RECT  2.16 65.745 19.44 66.015 ;
     RECT  2.16 66.285 19.44 66.555 ;
     RECT  2.16 66.825 19.44 67.095 ;
     RECT  2.16 67.365 19.44 67.635 ;
     RECT  2.16 67.905 19.44 68.175 ;
     RECT  2.16 68.445 19.44 68.715 ;
     RECT  2.16 68.985 19.44 69.255 ;
     RECT  2.16 69.525 19.44 69.795 ;
     RECT  2.16 70.065 19.44 70.335 ;
     RECT  2.16 70.605 19.44 70.875 ;
     RECT  2.16 71.145 19.44 71.415 ;
     RECT  2.16 71.685 19.44 71.955 ;
     RECT  2.16 72.225 19.44 72.495 ;
     RECT  2.16 72.765 19.44 73.035 ;
     RECT  2.16 73.305 19.44 73.575 ;
     RECT  2.16 73.845 19.44 74.115 ;
     RECT  2.16 74.385 19.44 74.655 ;
     RECT  2.16 74.925 19.44 75.195 ;
     RECT  2.16 75.465 19.44 75.735 ;
     RECT  2.16 76.005 19.44 76.275 ;
     RECT  2.16 76.545 19.44 76.815 ;
     RECT  2.16 77.085 19.44 77.355 ;
     RECT  2.16 77.625 19.44 77.895 ;
     RECT  2.16 78.165 19.44 78.435 ;
     RECT  2.16 78.705 19.44 78.975 ;
     RECT  2.16 79.245 19.44 79.515 ;
     RECT  2.16 79.785 19.44 79.92 ;
    LAYER RVTP ;
     RECT  2.16 2.295 19.44 2.565 ;
     RECT  2.16 2.835 19.44 3.105 ;
     RECT  2.16 3.375 19.44 3.645 ;
     RECT  2.16 3.915 19.44 4.185 ;
     RECT  2.16 4.455 19.44 4.725 ;
     RECT  2.16 4.995 19.44 5.265 ;
     RECT  2.16 5.535 19.44 5.805 ;
     RECT  2.16 6.075 19.44 6.345 ;
     RECT  2.16 6.615 19.44 6.885 ;
     RECT  2.16 7.155 19.44 7.425 ;
     RECT  2.16 7.695 19.44 7.965 ;
     RECT  2.16 8.235 19.44 8.505 ;
     RECT  2.16 8.775 19.44 9.045 ;
     RECT  2.16 9.315 19.44 9.585 ;
     RECT  2.16 9.855 19.44 10.125 ;
     RECT  2.16 10.395 19.44 10.665 ;
     RECT  2.16 10.935 19.44 11.205 ;
     RECT  2.16 11.475 19.44 11.745 ;
     RECT  2.16 12.015 19.44 12.285 ;
     RECT  2.16 12.555 19.44 12.825 ;
     RECT  2.16 13.095 19.44 13.365 ;
     RECT  2.16 13.635 19.44 13.905 ;
     RECT  2.16 14.175 19.44 14.445 ;
     RECT  2.16 14.715 19.44 14.985 ;
     RECT  2.16 15.255 19.44 15.525 ;
     RECT  2.16 15.795 19.44 16.065 ;
     RECT  2.16 16.335 19.44 16.605 ;
     RECT  2.16 16.875 19.44 17.145 ;
     RECT  2.16 17.415 19.44 17.685 ;
     RECT  2.16 17.955 19.44 18.225 ;
     RECT  2.16 18.495 19.44 18.765 ;
     RECT  2.16 19.035 19.44 19.305 ;
     RECT  2.16 19.575 19.44 19.845 ;
     RECT  2.16 20.115 19.44 20.385 ;
     RECT  2.16 20.655 19.44 20.925 ;
     RECT  2.16 21.195 19.44 21.465 ;
     RECT  2.16 21.735 19.44 22.005 ;
     RECT  2.16 22.275 19.44 22.545 ;
     RECT  2.16 22.815 19.44 23.085 ;
     RECT  2.16 23.355 19.44 23.625 ;
     RECT  2.16 23.895 19.44 24.165 ;
     RECT  2.16 24.435 19.44 24.705 ;
     RECT  2.16 24.975 19.44 25.245 ;
     RECT  2.16 25.515 19.44 25.785 ;
     RECT  2.16 26.055 19.44 26.325 ;
     RECT  2.16 26.595 19.44 26.865 ;
     RECT  2.16 27.135 19.44 27.405 ;
     RECT  2.16 27.675 19.44 27.945 ;
     RECT  2.16 28.215 19.44 28.485 ;
     RECT  2.16 28.755 19.44 29.025 ;
     RECT  2.16 29.295 19.44 29.565 ;
     RECT  2.16 29.835 19.44 30.105 ;
     RECT  2.16 30.375 19.44 30.645 ;
     RECT  2.16 30.915 19.44 31.185 ;
     RECT  2.16 31.455 19.44 31.725 ;
     RECT  2.16 31.995 19.44 32.265 ;
     RECT  2.16 32.535 19.44 32.805 ;
     RECT  2.16 33.075 19.44 33.345 ;
     RECT  2.16 33.615 19.44 33.885 ;
     RECT  2.16 34.155 19.44 34.425 ;
     RECT  2.16 34.695 19.44 34.965 ;
     RECT  2.16 35.235 19.44 35.505 ;
     RECT  2.16 35.775 19.44 36.045 ;
     RECT  2.16 36.315 19.44 36.585 ;
     RECT  2.16 36.855 19.44 37.125 ;
     RECT  2.16 37.395 19.44 37.665 ;
     RECT  2.16 37.935 19.44 38.205 ;
     RECT  2.16 38.475 19.44 38.745 ;
     RECT  2.16 39.015 19.44 39.285 ;
     RECT  2.16 39.555 19.44 39.825 ;
     RECT  2.16 40.095 19.44 40.365 ;
     RECT  2.16 40.635 19.44 40.905 ;
     RECT  2.16 41.175 19.44 41.445 ;
     RECT  2.16 41.715 19.44 41.985 ;
     RECT  2.16 42.255 19.44 42.525 ;
     RECT  2.16 42.795 19.44 43.065 ;
     RECT  2.16 43.335 19.44 43.605 ;
     RECT  2.16 43.875 19.44 44.145 ;
     RECT  2.16 44.415 19.44 44.685 ;
     RECT  2.16 44.955 19.44 45.225 ;
     RECT  2.16 45.495 19.44 45.765 ;
     RECT  2.16 46.035 19.44 46.305 ;
     RECT  2.16 46.575 19.44 46.845 ;
     RECT  2.16 47.115 19.44 47.385 ;
     RECT  2.16 47.655 19.44 47.925 ;
     RECT  2.16 48.195 19.44 48.465 ;
     RECT  2.16 48.735 19.44 49.005 ;
     RECT  2.16 49.275 19.44 49.545 ;
     RECT  2.16 49.815 19.44 50.085 ;
     RECT  2.16 50.355 19.44 50.625 ;
     RECT  2.16 50.895 19.44 51.165 ;
     RECT  2.16 51.435 19.44 51.705 ;
     RECT  2.16 51.975 19.44 52.245 ;
     RECT  2.16 52.515 19.44 52.785 ;
     RECT  2.16 53.055 19.44 53.325 ;
     RECT  2.16 53.595 19.44 53.865 ;
     RECT  2.16 54.135 19.44 54.405 ;
     RECT  2.16 54.675 19.44 54.945 ;
     RECT  2.16 55.215 19.44 55.485 ;
     RECT  2.16 55.755 19.44 56.025 ;
     RECT  2.16 56.295 19.44 56.565 ;
     RECT  2.16 56.835 19.44 57.105 ;
     RECT  2.16 57.375 19.44 57.645 ;
     RECT  2.16 57.915 19.44 58.185 ;
     RECT  2.16 58.455 19.44 58.725 ;
     RECT  2.16 58.995 19.44 59.265 ;
     RECT  2.16 59.535 19.44 59.805 ;
     RECT  2.16 60.075 19.44 60.345 ;
     RECT  2.16 60.615 19.44 60.885 ;
     RECT  2.16 61.155 19.44 61.425 ;
     RECT  2.16 61.695 19.44 61.965 ;
     RECT  2.16 62.235 19.44 62.505 ;
     RECT  2.16 62.775 19.44 63.045 ;
     RECT  2.16 63.315 19.44 63.585 ;
     RECT  2.16 63.855 19.44 64.125 ;
     RECT  2.16 64.395 19.44 64.665 ;
     RECT  2.16 64.935 19.44 65.205 ;
     RECT  2.16 65.475 19.44 65.745 ;
     RECT  2.16 66.015 19.44 66.285 ;
     RECT  2.16 66.555 19.44 66.825 ;
     RECT  2.16 67.095 19.44 67.365 ;
     RECT  2.16 67.635 19.44 67.905 ;
     RECT  2.16 68.175 19.44 68.445 ;
     RECT  2.16 68.715 19.44 68.985 ;
     RECT  2.16 69.255 19.44 69.525 ;
     RECT  2.16 69.795 19.44 70.065 ;
     RECT  2.16 70.335 19.44 70.605 ;
     RECT  2.16 70.875 19.44 71.145 ;
     RECT  2.16 71.415 19.44 71.685 ;
     RECT  2.16 71.955 19.44 72.225 ;
     RECT  2.16 72.495 19.44 72.765 ;
     RECT  2.16 73.035 19.44 73.305 ;
     RECT  2.16 73.575 19.44 73.845 ;
     RECT  2.16 74.115 19.44 74.385 ;
     RECT  2.16 74.655 19.44 74.925 ;
     RECT  2.16 75.195 19.44 75.465 ;
     RECT  2.16 75.735 19.44 76.005 ;
     RECT  2.16 76.275 19.44 76.545 ;
     RECT  2.16 76.815 19.44 77.085 ;
     RECT  2.16 77.355 19.44 77.625 ;
     RECT  2.16 77.895 19.44 78.165 ;
     RECT  2.16 78.435 19.44 78.705 ;
     RECT  2.16 78.975 19.44 79.245 ;
     RECT  2.16 79.515 19.44 79.785 ;
    LAYER M1 ;
     RECT  2.16 2.151 19.44 79.929 ;
    LAYER M2 ;
     RECT  0.103 3.456 0.175 3.474 ;
     RECT  0.103 72.576 0.175 72.594 ;
     RECT  0.175 3.348 0.203 3.474 ;
     RECT  0.175 72.468 0.203 72.594 ;
     RECT  0.103 40.338 0.239 40.356 ;
     RECT  0.203 3.348 0.275 3.366 ;
     RECT  0.203 72.468 0.275 72.486 ;
     RECT  0.355 55.188 0.427 55.278 ;
     RECT  0.391 24.066 0.463 24.084 ;
     RECT  0.391 65.754 0.499 65.772 ;
     RECT  0.427 12.834 0.535 12.852 ;
     RECT  0.463 79.182 0.535 79.2 ;
     RECT  0.427 55.188 0.599 55.404 ;
     RECT  0.355 13.878 0.859 13.896 ;
     RECT  0.355 52.722 0.859 52.74 ;
     RECT  0.535 68.724 0.895 68.742 ;
     RECT  0.895 68.724 0.931 69.012 ;
     RECT  0.931 22.518 0.967 22.536 ;
     RECT  0.859 13.878 1.003 14.544 ;
     RECT  0.931 68.688 1.003 69.012 ;
     RECT  0.499 19.89 1.039 19.908 ;
     RECT  0.103 67.266 1.039 67.284 ;
     RECT  0.499 65.556 1.075 65.772 ;
     RECT  0.103 10.206 1.111 10.224 ;
     RECT  0.967 22.518 1.147 23.076 ;
     RECT  0.319 27.342 1.183 27.36 ;
     RECT  1.183 27.108 1.319 27.36 ;
     RECT  0.103 16.686 1.399 16.704 ;
     RECT  0.859 52.722 1.399 53.046 ;
     RECT  1.435 15.876 1.471 15.894 ;
     RECT  1.399 16.686 1.471 16.974 ;
     RECT  1.399 52.29 1.471 53.046 ;
     RECT  1.147 22.518 1.543 23.112 ;
     RECT  0.463 24.066 1.543 24.66 ;
     RECT  0.967 69.876 1.543 69.894 ;
     RECT  1.039 19.89 1.579 20.484 ;
     RECT  0.535 21.276 1.579 21.294 ;
     RECT  1.039 66.87 1.579 67.284 ;
     RECT  1.543 69.876 1.615 70.092 ;
     RECT  0.463 70.956 1.615 70.974 ;
     RECT  1.579 19.89 1.651 21.294 ;
     RECT  0.535 78.642 1.687 79.236 ;
     RECT  0.103 39.294 1.939 39.312 ;
     RECT  1.543 22.518 1.975 24.66 ;
     RECT  0.599 55.26 2.011 55.404 ;
     RECT  1.975 60.084 2.047 60.102 ;
     RECT  1.111 62.514 2.083 62.532 ;
     RECT  2.047 18.774 2.119 18.792 ;
     RECT  2.119 18.306 2.155 18.792 ;
     RECT  2.047 60.084 2.155 60.174 ;
     RECT  1.687 2.466 2.16 2.484 ;
     RECT  0.139 8.046 2.16 8.064 ;
     RECT  1.111 10.206 2.16 10.656 ;
     RECT  2.083 11.682 2.16 11.7 ;
     RECT  0.535 12.528 2.16 12.852 ;
     RECT  1.003 13.842 2.16 14.544 ;
     RECT  1.471 15.876 2.16 16.974 ;
     RECT  2.155 18.036 2.16 18.792 ;
     RECT  1.651 19.656 2.16 21.294 ;
     RECT  1.975 22.086 2.16 24.66 ;
     RECT  1.319 27.342 2.16 27.36 ;
     RECT  0.103 31.698 2.16 31.716 ;
     RECT  0.103 34.704 2.16 34.722 ;
     RECT  0.319 37.602 2.16 37.62 ;
     RECT  1.939 39.294 2.16 39.582 ;
     RECT  0.319 42.606 2.16 42.624 ;
     RECT  0.319 45.54 2.16 45.558 ;
     RECT  1.939 50.706 2.16 50.724 ;
     RECT  1.471 52.29 2.16 53.154 ;
     RECT  2.011 55.26 2.16 55.512 ;
     RECT  0.427 58.122 2.16 58.14 ;
     RECT  2.155 60.084 2.16 60.444 ;
     RECT  2.119 61.2 2.16 61.218 ;
     RECT  2.083 61.974 2.16 62.532 ;
     RECT  1.687 63.936 2.16 63.954 ;
     RECT  1.075 65.25 2.16 65.772 ;
     RECT  1.579 66.87 2.16 67.464 ;
     RECT  1.003 68.688 2.16 69.084 ;
     RECT  1.615 69.876 2.16 70.974 ;
     RECT  0.535 74.628 2.16 74.646 ;
     RECT  0.103 77.292 2.16 77.31 ;
     RECT  1.687 78.642 2.16 79.506 ;
     RECT  2.16 2.151 10.831 79.929 ;
     RECT  10.831 2.106 14.575 79.929 ;
     RECT  14.575 1.998 16.151 79.929 ;
     RECT  16.151 2.07 19.44 79.929 ;
     RECT  19.44 70.236 19.463 70.596 ;
     RECT  19.44 29.808 19.571 42.624 ;
     RECT  19.44 26.028 19.607 29.052 ;
     RECT  19.44 59.544 19.679 65.934 ;
     RECT  19.44 73.242 19.679 73.26 ;
     RECT  19.44 23.796 19.715 24.192 ;
     RECT  19.679 59.616 19.787 65.934 ;
     RECT  19.44 11.016 19.895 15.084 ;
     RECT  19.44 22.626 19.895 22.734 ;
     RECT  19.571 29.808 19.895 41.742 ;
     RECT  19.44 3.546 19.931 3.564 ;
     RECT  19.44 4.626 19.931 9.846 ;
     RECT  19.607 26.028 19.967 26.964 ;
     RECT  19.895 32.472 19.967 41.742 ;
     RECT  19.571 42.498 19.967 42.624 ;
     RECT  19.44 48.204 19.967 56.52 ;
     RECT  19.44 57.42 19.967 58.446 ;
     RECT  19.44 66.906 19.967 68.238 ;
     RECT  19.44 69.228 19.967 69.246 ;
     RECT  19.463 70.236 19.967 70.56 ;
     RECT  19.44 77.166 19.967 78.354 ;
     RECT  19.931 4.626 20.003 7.524 ;
     RECT  19.967 35.82 20.003 41.742 ;
     RECT  19.44 45.126 20.003 47.304 ;
     RECT  19.967 48.276 20.039 55.314 ;
     RECT  20.039 48.276 20.183 51.894 ;
     RECT  19.44 71.586 20.219 72.414 ;
     RECT  19.931 8.316 20.255 9.774 ;
     RECT  20.039 52.956 20.255 55.314 ;
     RECT  19.967 57.42 20.291 58.284 ;
     RECT  19.787 59.616 20.291 61.65 ;
     RECT  20.291 59.814 20.363 61.65 ;
     RECT  19.44 17.586 20.435 17.784 ;
     RECT  19.44 21.636 20.435 21.654 ;
     RECT  19.895 22.716 20.435 22.734 ;
     RECT  20.255 52.956 20.435 55.278 ;
     RECT  19.895 11.016 20.471 14.238 ;
     RECT  19.967 42.534 20.471 42.624 ;
     RECT  19.44 2.07 20.507 2.484 ;
     RECT  20.471 11.016 20.507 12.384 ;
     RECT  20.471 13.176 20.507 14.238 ;
     RECT  19.44 15.966 20.507 16.794 ;
     RECT  20.435 17.586 20.507 17.604 ;
     RECT  20.003 36.486 20.507 41.742 ;
     RECT  19.787 62.712 20.507 65.934 ;
     RECT  19.967 77.328 20.507 78.354 ;
     RECT  20.507 11.016 20.515 11.97 ;
     RECT  20.003 4.626 20.543 7.344 ;
     RECT  20.255 8.316 20.543 9.648 ;
     RECT  19.967 26.028 20.543 26.928 ;
     RECT  19.895 29.808 20.543 31.716 ;
     RECT  19.967 34.164 20.543 34.614 ;
     RECT  20.507 36.486 20.543 39.078 ;
     RECT  20.507 39.87 20.543 41.742 ;
     RECT  20.471 42.534 20.543 42.552 ;
     RECT  20.003 45.126 20.543 46.8 ;
     RECT  20.183 48.276 20.543 50.274 ;
     RECT  20.183 51.138 20.543 51.894 ;
     RECT  20.435 52.956 20.543 53.658 ;
     RECT  20.435 54.612 20.543 55.278 ;
     RECT  19.967 56.07 20.543 56.52 ;
     RECT  20.363 60.894 20.543 61.65 ;
     RECT  20.507 62.712 20.543 63.918 ;
     RECT  20.507 64.674 20.543 65.934 ;
     RECT  19.967 67.104 20.543 67.554 ;
     RECT  20.219 71.586 20.543 71.712 ;
     RECT  20.507 77.976 20.543 78.354 ;
     RECT  20.543 31.392 20.579 31.716 ;
     RECT  20.543 40.68 20.579 41.544 ;
     RECT  20.543 49.626 20.579 50.148 ;
     RECT  20.543 51.336 20.579 51.894 ;
     RECT  20.543 54.612 20.579 55.242 ;
     RECT  20.543 56.196 20.579 56.52 ;
     RECT  20.543 62.712 20.579 62.73 ;
     RECT  20.543 63.792 20.579 63.918 ;
     RECT  20.543 64.908 20.579 65.664 ;
     RECT  19.967 32.472 20.615 33.372 ;
     RECT  20.543 37.836 20.615 39.078 ;
     RECT  20.579 55.224 20.615 55.242 ;
     RECT  20.615 33.354 20.875 33.372 ;
     RECT  20.543 34.164 20.875 34.416 ;
     RECT  19.44 25.218 20.947 25.236 ;
     RECT  20.543 26.028 20.947 26.046 ;
     RECT  19.715 23.976 21.011 24.192 ;
     RECT  20.947 24.984 21.047 26.046 ;
     RECT  19.607 27.918 21.083 29.052 ;
     RECT  20.579 56.196 21.083 56.358 ;
     RECT  21.011 24.174 21.119 24.192 ;
     RECT  21.047 24.984 21.119 25.704 ;
     RECT  20.543 36.486 21.119 36.954 ;
     RECT  20.363 59.814 21.119 60.066 ;
     RECT  20.543 29.808 21.155 30.438 ;
     RECT  21.083 56.34 21.155 56.358 ;
     RECT  20.615 37.836 21.191 38.394 ;
     RECT  20.291 57.924 21.191 58.284 ;
     RECT  20.875 33.354 21.227 34.416 ;
     RECT  20.543 52.956 21.227 53.586 ;
     RECT  20.543 4.626 21.263 6.174 ;
     RECT  20.579 31.392 21.263 31.41 ;
     RECT  21.191 37.944 21.263 38.394 ;
     RECT  20.543 48.276 21.263 48.384 ;
     RECT  21.263 38.376 21.299 38.394 ;
     RECT  20.543 7.326 21.335 7.344 ;
     RECT  21.155 30.42 21.335 30.438 ;
     RECT  21.119 36.936 21.335 36.954 ;
     RECT  20.543 45.126 21.335 46.224 ;
     RECT  21.119 59.814 21.335 59.994 ;
     RECT  20.543 26.91 21.343 26.928 ;
     RECT  21.263 4.698 21.371 6.174 ;
     RECT  21.119 24.984 21.371 25.614 ;
     RECT  20.803 32.274 21.371 32.364 ;
     RECT  20.579 40.914 21.371 41.202 ;
     RECT  20.579 51.876 21.371 51.894 ;
     RECT  21.227 52.956 21.371 52.974 ;
     RECT  19.967 70.236 21.371 70.254 ;
     RECT  20.507 2.106 21.379 2.484 ;
     RECT  20.507 16.272 21.379 16.794 ;
     RECT  20.543 60.894 21.379 61.614 ;
     RECT  21.371 5.778 21.407 6.174 ;
     RECT  21.227 33.354 21.407 33.678 ;
     RECT  21.335 45.126 21.407 46.098 ;
     RECT  21.379 60.741 21.407 62.226 ;
     RECT  20.579 64.908 21.407 64.926 ;
     RECT  21.379 16.272 21.415 17.1 ;
     RECT  21.407 33.354 21.415 33.606 ;
     RECT  21.371 4.698 21.443 4.716 ;
     RECT  21.407 5.778 21.443 5.796 ;
     RECT  20.543 8.946 21.443 9.648 ;
     RECT  21.371 25.056 21.443 25.542 ;
     RECT  21.343 26.91 21.443 26.964 ;
     RECT  21.371 32.274 21.443 32.292 ;
     RECT  19.44 43.578 21.443 44.334 ;
     RECT  20.543 71.694 21.443 71.712 ;
     RECT  21.415 56.88 21.451 56.898 ;
     RECT  21.379 2.106 21.479 2.934 ;
     RECT  20.515 10.908 21.479 11.97 ;
     RECT  21.415 16.272 21.479 17.172 ;
     RECT  21.371 40.914 21.479 40.932 ;
     RECT  21.443 43.578 21.479 43.596 ;
     RECT  21.335 59.976 21.479 59.994 ;
     RECT  21.407 60.741 21.479 61.344 ;
     RECT  20.579 63.792 21.479 63.81 ;
     RECT  21.479 2.106 21.515 2.862 ;
     RECT  21.479 10.98 21.515 11.97 ;
     RECT  20.507 13.176 21.515 13.968 ;
     RECT  19.895 15.066 21.515 15.084 ;
     RECT  21.479 16.776 21.515 17.172 ;
     RECT  19.44 20.088 21.515 20.106 ;
     RECT  21.443 26.91 21.515 26.928 ;
     RECT  21.083 27.918 21.515 28.44 ;
     RECT  21.415 33.084 21.515 33.606 ;
     RECT  21.407 45.702 21.515 45.792 ;
     RECT  20.579 49.716 21.515 50.148 ;
     RECT  21.191 58.266 21.515 58.284 ;
     RECT  21.515 2.844 21.551 2.862 ;
     RECT  21.515 11.016 21.551 11.034 ;
     RECT  21.379 21.096 21.551 21.114 ;
     RECT  21.515 49.716 21.551 50.076 ;
     RECT  21.451 56.88 21.551 56.979 ;
     RECT  21.407 62.136 21.551 62.226 ;
     RECT  21.451 76.716 21.551 76.734 ;
     RECT  21.487 1.188 21.587 1.206 ;
     RECT  21.515 13.68 21.587 13.698 ;
     RECT  21.515 17.154 21.587 17.172 ;
     RECT  21.263 48.276 21.587 48.294 ;
     RECT  21.479 61.326 21.587 61.344 ;
     RECT  21.487 78.75 21.587 78.768 ;
    LAYER M3 ;
     RECT  15.03 0.012 15.12 0.037 ;
     RECT  15.012 0.037 15.138 0.043 ;
     RECT  14.832 0.043 15.138 0.173 ;
     RECT  19.908 0.715 19.926 0.859 ;
     RECT  21.42 1.003 21.438 1.147 ;
     RECT  21.42 1.147 21.51 1.183 ;
     RECT  15.12 0.173 15.138 1.993 ;
     RECT  21.42 1.183 21.582 2.011 ;
     RECT  16.128 1.993 16.146 2.065 ;
     RECT  19.908 0.859 20.502 2.093 ;
     RECT  10.836 2.101 10.854 2.143 ;
     RECT  13.356 1.579 13.374 2.143 ;
     RECT  18.324 1.291 18.342 2.143 ;
     RECT  18.324 2.143 18.705 2.155 ;
     RECT  14.58 1.993 15.138 2.227 ;
     RECT  19.908 2.093 20.466 2.291 ;
     RECT  5.115 2.143 5.205 2.335 ;
     RECT  14.4 2.227 15.138 2.335 ;
     RECT  15.876 2.065 16.146 2.335 ;
     RECT  2.415 2.143 2.505 2.413 ;
     RECT  7.815 2.143 7.905 2.413 ;
     RECT  13.215 2.143 13.374 2.413 ;
     RECT  14.4 2.335 16.146 2.413 ;
     RECT  2.415 2.413 2.697 2.461 ;
     RECT  18.324 2.155 19.17 2.587 ;
     RECT  19.908 2.291 20.25 2.587 ;
     RECT  11.664 2.263 11.682 2.605 ;
     RECT  5.115 2.335 5.562 2.731 ;
     RECT  5.04 2.731 5.562 2.759 ;
     RECT  10.515 2.143 10.854 2.911 ;
     RECT  11.664 2.605 11.754 2.911 ;
     RECT  21.384 2.011 21.582 2.939 ;
     RECT  14.4 2.413 16.197 3.029 ;
     RECT  5.04 2.759 5.397 3.163 ;
     RECT  7.815 2.413 8.097 3.181 ;
     RECT  10.515 2.911 11.754 3.181 ;
     RECT  0.144 3.067 0.162 3.307 ;
     RECT  4.464 3.163 5.397 3.307 ;
     RECT  0.144 3.307 0.198 3.343 ;
     RECT  0.144 3.343 0.27 3.389 ;
     RECT  0.144 3.389 0.198 3.451 ;
     RECT  0.108 3.451 0.198 3.479 ;
     RECT  0.108 3.479 0.126 3.488 ;
     RECT  6.264 3.343 6.282 3.541 ;
     RECT  7.2 3.181 8.097 3.541 ;
     RECT  10.515 3.181 12.33 3.569 ;
     RECT  18.324 2.587 20.25 3.595 ;
     RECT  12.276 3.569 12.33 3.649 ;
     RECT  13.215 2.413 13.497 3.649 ;
     RECT  1.692 2.461 2.697 3.721 ;
     RECT  3.816 3.307 5.397 3.721 ;
     RECT  12.276 3.649 13.497 3.721 ;
     RECT  21.42 2.939 21.582 3.883 ;
     RECT  6.264 3.541 8.097 3.955 ;
     RECT  1.692 3.721 5.397 3.965 ;
     RECT  3.816 3.965 5.397 3.991 ;
     RECT  6.264 3.955 8.154 3.991 ;
     RECT  3.816 3.991 8.154 4.061 ;
     RECT  6.84 4.061 8.154 4.109 ;
     RECT  21.384 3.883 21.582 4.171 ;
     RECT  10.515 3.569 11.286 4.225 ;
     RECT  6.984 4.109 8.154 4.289 ;
     RECT  18.072 3.595 20.25 4.651 ;
     RECT  21.24 4.171 21.582 4.652 ;
     RECT  10.044 4.225 11.286 4.657 ;
     RECT  12.276 3.721 13.734 4.657 ;
     RECT  14.544 3.029 16.197 4.657 ;
     RECT  21.276 4.652 21.582 4.757 ;
     RECT  7.815 4.289 8.154 4.765 ;
     RECT  10.044 4.657 13.734 4.765 ;
     RECT  9.972 4.765 13.734 4.793 ;
     RECT  1.692 3.965 2.862 4.801 ;
     RECT  6.984 4.289 7.074 4.963 ;
     RECT  9.972 4.793 11.43 4.999 ;
     RECT  3.816 4.061 5.994 5.035 ;
     RECT  6.912 4.963 7.074 5.035 ;
     RECT  12.276 4.793 13.734 5.071 ;
     RECT  14.508 4.657 16.197 5.071 ;
     RECT  1.692 4.801 3.078 5.179 ;
     RECT  3.816 5.035 7.074 5.179 ;
     RECT  12.276 5.071 16.197 5.233 ;
     RECT  17.352 4.651 20.25 5.233 ;
     RECT  9.936 4.999 11.43 5.269 ;
     RECT  0.144 4.603 0.162 5.309 ;
     RECT  9.216 5.269 11.43 5.369 ;
     RECT  1.692 5.179 7.074 5.431 ;
     RECT  7.815 4.765 8.262 5.431 ;
     RECT  1.692 5.431 8.262 5.459 ;
     RECT  4.14 5.459 8.262 5.597 ;
     RECT  9.936 5.369 11.43 5.737 ;
     RECT  4.14 5.597 8.097 5.765 ;
     RECT  1.692 5.459 3.33 5.873 ;
     RECT  9.144 5.881 9.162 5.999 ;
     RECT  9.936 5.737 11.502 6.115 ;
     RECT  9.468 6.115 11.502 6.269 ;
     RECT  1.692 5.873 2.97 6.317 ;
     RECT  12.276 5.233 20.25 6.385 ;
     RECT  9.936 6.269 11.502 6.421 ;
     RECT  12.276 6.385 20.538 6.421 ;
     RECT  9.936 6.421 20.538 6.539 ;
     RECT  5.04 5.765 8.097 6.575 ;
     RECT  4.14 5.765 4.302 6.619 ;
     RECT  5.04 6.575 7.002 6.619 ;
     RECT  4.14 6.619 7.002 6.691 ;
     RECT  1.692 6.317 2.826 7.051 ;
     RECT  1.692 7.051 3.258 7.231 ;
     RECT  4.068 6.691 7.002 7.231 ;
     RECT  7.815 6.575 8.097 7.231 ;
     RECT  9.936 6.539 11.43 7.231 ;
     RECT  9.828 7.231 11.43 7.321 ;
     RECT  12.276 6.539 20.538 7.373 ;
     RECT  9.756 7.321 11.43 7.421 ;
     RECT  1.692 7.231 7.002 7.627 ;
     RECT  21.312 4.757 21.582 7.661 ;
     RECT  21.42 7.661 21.582 8.189 ;
     RECT  12.276 7.373 20.25 8.311 ;
     RECT  1.692 7.627 7.074 8.339 ;
     RECT  7.815 7.231 8.802 8.339 ;
     RECT  12.276 8.311 20.538 8.381 ;
     RECT  0.144 7.723 0.162 8.669 ;
     RECT  0.216 8.683 0.234 8.813 ;
     RECT  3.708 8.339 7.074 8.815 ;
     RECT  7.815 8.339 8.097 8.815 ;
     RECT  3.708 8.815 8.097 8.861 ;
     RECT  21.456 8.189 21.582 8.923 ;
     RECT  3.708 8.861 7.074 9.005 ;
     RECT  3.816 9.005 7.074 9.011 ;
     RECT  12.276 8.381 20.25 9.355 ;
     RECT  1.692 8.339 2.934 9.391 ;
     RECT  1.692 9.391 3.078 9.509 ;
     RECT  1.692 9.509 2.79 9.545 ;
     RECT  21.42 8.923 21.582 9.653 ;
     RECT  0.144 9.547 0.162 9.677 ;
     RECT  9.936 7.421 11.43 9.751 ;
     RECT  9.936 9.751 11.466 9.787 ;
     RECT  3.996 9.011 7.074 9.931 ;
     RECT  7.815 8.861 8.097 9.931 ;
     RECT  3.996 9.931 8.097 10.021 ;
     RECT  9.936 9.787 11.502 10.049 ;
     RECT  0.108 10.201 0.126 10.253 ;
     RECT  3.996 10.021 8.694 10.327 ;
     RECT  1.692 9.545 2.697 10.633 ;
     RECT  1.116 10.633 2.697 10.651 ;
     RECT  3.816 10.327 8.694 10.741 ;
     RECT  9.936 10.049 11.43 10.741 ;
     RECT  0.144 10.699 0.162 10.829 ;
     RECT  3.816 10.741 11.43 10.867 ;
     RECT  12.276 9.355 20.502 10.867 ;
     RECT  3.816 10.867 20.502 10.903 ;
     RECT  21.456 9.653 21.582 10.939 ;
     RECT  3.816 10.903 20.538 11.129 ;
     RECT  1.116 10.651 2.862 11.227 ;
     RECT  1.116 11.227 2.97 11.749 ;
     RECT  3.816 11.129 20.502 11.749 ;
     RECT  0.144 11.755 0.162 12.317 ;
     RECT  1.116 11.749 20.502 12.389 ;
     RECT  1.116 12.389 20.466 12.479 ;
     RECT  1.116 12.479 20.214 12.517 ;
     RECT  21.312 10.939 21.582 13.703 ;
     RECT  0.432 12.517 20.214 13.873 ;
     RECT  0.36 13.873 20.214 14.107 ;
     RECT  0.36 14.107 20.502 14.243 ;
     RECT  0.36 14.243 19.926 14.251 ;
     RECT  21.312 13.703 21.51 14.395 ;
     RECT  0.324 14.251 19.926 14.827 ;
     RECT  0.144 14.827 19.926 14.957 ;
     RECT  21.24 14.395 21.51 15.089 ;
     RECT  0.36 14.957 19.926 15.835 ;
     RECT  0.36 15.835 20.502 15.989 ;
     RECT  21.24 15.089 21.474 16.411 ;
     RECT  0.36 15.989 20.466 16.681 ;
     RECT  0.108 16.681 20.466 16.733 ;
     RECT  0.144 16.733 20.466 16.987 ;
     RECT  21.24 16.411 21.51 17.149 ;
     RECT  0.144 16.987 20.502 17.275 ;
     RECT  21.24 17.149 21.582 17.275 ;
     RECT  0.144 17.275 21.582 17.981 ;
     RECT  0.36 17.981 21.582 18.859 ;
     RECT  0.144 18.859 21.582 21.053 ;
     RECT  0.36 21.053 21.582 21.787 ;
     RECT  0.144 21.787 21.582 22.781 ;
     RECT  0.36 22.781 21.582 25.339 ;
     RECT  0.144 25.339 21.582 25.949 ;
     RECT  0.216 25.949 21.582 26.093 ;
     RECT  0.36 26.093 21.582 27.337 ;
     RECT  0.324 27.337 21.582 27.499 ;
     RECT  0.144 27.499 21.582 27.629 ;
     RECT  0.36 27.629 21.582 28.651 ;
     RECT  0.144 28.651 21.582 30.557 ;
     RECT  0.36 30.557 21.582 31.531 ;
     RECT  0.252 31.531 21.582 31.675 ;
     RECT  0.108 31.675 21.582 31.721 ;
     RECT  0.144 31.721 21.582 32.237 ;
     RECT  0.36 32.237 21.582 33.979 ;
     RECT  0.144 33.979 21.582 34.699 ;
     RECT  0.108 34.699 21.582 34.736 ;
     RECT  0.144 34.736 21.582 35.261 ;
     RECT  0.36 35.261 21.582 37.597 ;
     RECT  0.324 37.597 21.582 37.757 ;
     RECT  0.36 37.757 21.582 39.163 ;
     RECT  0.108 39.163 21.582 39.317 ;
     RECT  0.36 39.317 21.582 40.171 ;
     RECT  0.324 40.171 21.582 40.315 ;
     RECT  0.108 40.315 21.582 40.361 ;
     RECT  0.216 40.361 21.582 40.397 ;
     RECT  0.36 40.397 21.582 41.933 ;
     RECT  0.36 41.933 20.574 42.601 ;
     RECT  0.324 42.601 20.574 42.797 ;
     RECT  0.36 42.797 20.538 42.941 ;
     RECT  0.36 42.941 20.502 44.077 ;
     RECT  21.312 41.933 21.582 44.077 ;
     RECT  0.36 44.077 21.582 44.525 ;
     RECT  0.36 44.525 20.61 44.813 ;
     RECT  0.36 44.813 20.502 45.259 ;
     RECT  21.384 44.525 21.582 45.697 ;
     RECT  0.144 45.259 20.502 46.003 ;
     RECT  0.144 46.003 20.538 46.061 ;
     RECT  21.348 45.697 21.582 46.201 ;
     RECT  0.36 46.061 20.538 47.117 ;
     RECT  0.36 47.117 20.502 47.515 ;
     RECT  21.312 46.201 21.582 48.299 ;
     RECT  21.312 48.299 21.546 48.361 ;
     RECT  0.144 47.515 20.502 48.811 ;
     RECT  21.24 48.361 21.546 48.811 ;
     RECT  0.144 48.811 21.546 48.845 ;
     RECT  0.216 48.845 21.546 48.989 ;
     RECT  0.36 48.989 21.546 51.739 ;
     RECT  0.144 51.739 21.546 51.869 ;
     RECT  0.36 51.869 21.546 52.157 ;
     RECT  0.36 52.157 20.502 52.745 ;
     RECT  0.396 52.745 20.502 53.563 ;
     RECT  21.24 52.157 21.546 53.563 ;
     RECT  0.396 53.563 21.546 55.147 ;
     RECT  0.36 55.147 21.546 55.867 ;
     RECT  0.144 55.867 21.546 55.997 ;
     RECT  0.396 55.997 21.546 57.355 ;
     RECT  0.18 57.355 21.546 57.485 ;
     RECT  0.396 57.485 21.546 61.321 ;
     RECT  0.396 61.321 21.582 61.387 ;
     RECT  0.144 61.387 21.582 61.517 ;
     RECT  0.396 61.517 21.582 62.539 ;
     RECT  0.144 62.539 21.582 62.669 ;
     RECT  0.396 62.669 21.582 63.835 ;
     RECT  0.144 63.835 21.582 63.965 ;
     RECT  0.396 63.965 21.582 65.083 ;
     RECT  0.144 65.083 21.582 65.213 ;
     RECT  0.396 65.213 21.582 65.777 ;
     RECT  0.468 65.777 21.582 67.243 ;
     RECT  0.108 67.243 21.582 67.289 ;
     RECT  0.468 67.289 21.582 68.135 ;
     RECT  0.468 68.135 9.738 68.539 ;
     RECT  10.515 68.135 21.582 68.717 ;
     RECT  0.18 68.539 9.738 69.019 ;
     RECT  0.144 69.019 9.738 69.151 ;
     RECT  0.144 69.151 9.774 69.251 ;
     RECT  0.144 69.251 9.738 69.389 ;
     RECT  21.168 68.717 21.582 69.725 ;
     RECT  0.468 69.389 9.738 69.899 ;
     RECT  1.548 69.899 9.738 70.097 ;
     RECT  21.204 69.725 21.582 70.589 ;
     RECT  0.468 69.899 0.486 70.699 ;
     RECT  1.62 70.097 9.738 70.709 ;
     RECT  0.144 70.699 0.486 70.925 ;
     RECT  0.468 70.925 0.486 70.979 ;
     RECT  2.232 70.709 9.738 71.519 ;
     RECT  10.515 68.717 20.43 71.581 ;
     RECT  21.24 70.589 21.582 71.581 ;
     RECT  10.515 71.581 21.582 71.741 ;
     RECT  0.18 72.427 0.198 72.463 ;
     RECT  2.304 71.519 9.738 72.463 ;
     RECT  10.515 71.741 20.43 72.463 ;
     RECT  0.18 72.463 0.27 72.509 ;
     RECT  0.18 72.509 0.198 72.571 ;
     RECT  0.108 72.571 0.198 72.599 ;
     RECT  0.108 72.599 0.126 72.608 ;
     RECT  2.304 72.463 20.43 72.893 ;
     RECT  2.415 72.893 20.43 72.959 ;
     RECT  1.152 73.339 1.17 73.469 ;
     RECT  2.415 72.959 9.63 73.813 ;
     RECT  2.415 73.813 9.702 73.867 ;
     RECT  10.515 72.959 20.43 73.901 ;
     RECT  21.24 71.741 21.582 74.621 ;
     RECT  0.54 74.623 0.558 74.765 ;
     RECT  10.515 73.901 20.358 75.053 ;
     RECT  10.515 75.053 20.322 75.389 ;
     RECT  2.304 73.867 9.702 75.569 ;
     RECT  21.384 74.621 21.582 75.629 ;
     RECT  2.304 75.569 9.594 75.883 ;
     RECT  2.268 75.883 9.594 76.013 ;
     RECT  12.816 75.389 20.322 76.061 ;
     RECT  2.304 76.013 3.474 76.109 ;
     RECT  12.816 76.061 20.214 76.205 ;
     RECT  2.304 76.109 3.33 76.469 ;
     RECT  1.152 76.507 1.17 76.637 ;
     RECT  4.212 76.013 9.594 76.775 ;
     RECT  12.816 76.205 19.674 76.781 ;
     RECT  2.304 76.469 2.718 76.784 ;
     RECT  21.456 75.629 21.582 76.925 ;
     RECT  4.212 76.775 4.374 76.981 ;
     RECT  10.515 75.389 12.006 77.009 ;
     RECT  19.656 76.781 19.674 77.069 ;
     RECT  10.515 77.009 11.862 77.081 ;
     RECT  4.068 76.981 4.374 77.189 ;
     RECT  10.515 77.081 11.394 77.279 ;
     RECT  0.108 77.179 0.126 77.315 ;
     RECT  19.944 77.161 19.962 77.323 ;
     RECT  2.415 76.784 2.718 77.371 ;
     RECT  5.115 76.775 9.594 77.395 ;
     RECT  4.212 77.189 4.374 77.512 ;
     RECT  5.115 77.395 9.666 77.512 ;
     RECT  4.212 77.512 9.666 77.549 ;
     RECT  2.415 77.371 3.294 77.585 ;
     RECT  0.144 77.371 0.162 77.803 ;
     RECT  2.415 77.585 3.186 77.803 ;
     RECT  12.816 76.781 18.897 77.855 ;
     RECT  12.816 77.855 17.514 77.891 ;
     RECT  19.944 77.323 20.502 77.971 ;
     RECT  18.615 77.855 18.897 78.061 ;
     RECT  0.144 77.803 0.234 78.077 ;
     RECT  14.688 77.891 17.514 78.089 ;
     RECT  12.816 77.891 13.806 78.161 ;
     RECT  4.212 77.549 9.594 78.241 ;
     RECT  12.996 78.161 13.806 78.269 ;
     RECT  4.104 78.241 9.594 78.359 ;
     RECT  18.615 78.061 18.99 78.365 ;
     RECT  14.688 78.089 17.406 78.395 ;
     RECT  19.944 77.971 20.538 78.509 ;
     RECT  2.304 77.803 3.186 78.511 ;
     RECT  2.304 78.511 3.294 78.601 ;
     RECT  4.104 78.359 9.558 78.601 ;
     RECT  2.304 78.601 9.558 78.629 ;
     RECT  14.688 78.395 17.37 78.737 ;
     RECT  21.564 76.925 21.582 78.745 ;
     RECT  13.215 78.269 13.806 78.773 ;
     RECT  21.492 78.745 21.582 78.773 ;
     RECT  21.492 78.773 21.51 78.797 ;
     RECT  20.52 78.509 20.538 78.941 ;
     RECT  14.688 78.737 16.758 78.943 ;
     RECT  14.616 78.943 16.758 79.169 ;
     RECT  0.54 78.637 0.558 79.177 ;
     RECT  15.336 79.169 16.758 79.205 ;
     RECT  2.304 78.629 9.162 79.241 ;
     RECT  0.468 79.177 0.558 79.243 ;
     RECT  2.304 79.241 8.802 79.439 ;
     RECT  2.304 79.439 3.69 79.483 ;
     RECT  5.115 79.439 8.802 79.52 ;
     RECT  6.66 79.52 8.802 79.583 ;
     RECT  15.336 79.205 16.614 79.583 ;
     RECT  6.66 79.583 6.93 79.619 ;
     RECT  7.668 79.583 8.802 79.667 ;
     RECT  13.215 78.773 13.497 79.667 ;
     RECT  18.615 78.365 18.897 79.667 ;
     RECT  6.66 79.619 6.858 79.709 ;
     RECT  7.668 79.667 7.905 79.709 ;
     RECT  8.784 79.667 8.802 79.709 ;
     RECT  10.515 77.279 11.358 79.709 ;
     RECT  15.48 79.583 16.614 79.709 ;
     RECT  6.732 79.709 6.822 79.745 ;
     RECT  7.74 79.709 7.905 79.745 ;
     RECT  15.732 79.709 16.614 79.745 ;
     RECT  15.732 79.745 16.434 79.781 ;
     RECT  0.18 79.243 0.558 79.819 ;
     RECT  1.692 79.483 3.69 79.853 ;
     RECT  1.692 79.853 2.574 79.937 ;
     RECT  5.115 79.52 5.706 79.937 ;
     RECT  7.815 79.745 7.905 79.937 ;
     RECT  10.515 79.709 10.605 79.937 ;
     RECT  13.215 79.667 13.305 79.937 ;
     RECT  18.615 79.667 18.705 79.937 ;
     RECT  0.144 79.819 0.558 79.949 ;
     RECT  15.876 79.781 16.434 80.093 ;
     RECT  0.468 79.949 0.558 80.237 ;
     RECT  0.468 80.237 0.486 80.381 ;
     RECT  3.672 79.853 3.69 80.525 ;
     RECT  5.256 79.937 5.706 80.669 ;
     RECT  2.556 79.937 2.574 80.813 ;
     RECT  1.692 79.937 1.71 80.957 ;
     RECT  16.416 80.093 16.434 80.957 ;
     RECT  5.256 80.669 5.274 81.101 ;
     RECT  6.804 79.745 6.822 81.245 ;
    LAYER M4 ;
     RECT  0.084 3.024 2.408 3.048 ;
     RECT  0.06 3.048 2.408 3.168 ;
     RECT  0.084 3.168 2.408 3.192 ;
     RECT  0.06 3.192 2.408 3.312 ;
     RECT  0.084 3.312 2.408 3.336 ;
     RECT  0.06 3.336 2.408 3.456 ;
     RECT  0.084 3.456 2.408 3.48 ;
     RECT  0.06 3.48 2.408 3.6 ;
     RECT  0.084 3.6 2.408 3.624 ;
     RECT  0.06 3.624 2.408 3.744 ;
     RECT  0.084 3.744 2.408 3.768 ;
     RECT  0.06 3.768 2.408 3.888 ;
     RECT  0.084 3.888 2.408 3.912 ;
     RECT  0.06 3.912 2.408 4.032 ;
     RECT  0.084 4.032 2.408 4.056 ;
     RECT  0.06 4.056 2.408 4.176 ;
     RECT  0.084 4.176 2.408 4.2 ;
     RECT  0.06 4.2 2.408 4.32 ;
     RECT  0.084 4.32 2.408 4.344 ;
     RECT  0.06 4.344 2.408 4.464 ;
     RECT  0.084 4.464 2.408 4.488 ;
     RECT  0.06 4.488 2.408 4.608 ;
     RECT  0.084 4.608 2.408 4.632 ;
     RECT  0.06 4.632 2.408 4.752 ;
     RECT  0.084 4.752 2.408 4.776 ;
     RECT  0.06 4.776 2.408 4.896 ;
     RECT  0.084 4.896 2.408 4.92 ;
     RECT  0.06 4.92 2.408 5.04 ;
     RECT  0.084 5.04 2.408 5.064 ;
     RECT  0.06 5.064 2.408 5.184 ;
     RECT  0.084 5.184 2.408 5.208 ;
     RECT  0.06 5.208 2.408 5.328 ;
     RECT  0.084 5.328 2.408 5.352 ;
     RECT  0.06 5.352 2.408 5.472 ;
     RECT  0.084 5.472 2.408 5.496 ;
     RECT  0.06 5.496 2.408 5.616 ;
     RECT  0.084 5.616 2.408 5.64 ;
     RECT  0.06 5.64 2.408 5.76 ;
     RECT  0.084 5.76 2.408 5.784 ;
     RECT  0.06 5.784 2.408 5.904 ;
     RECT  0.084 5.904 2.408 5.928 ;
     RECT  0.06 5.928 2.408 6.048 ;
     RECT  0.084 6.048 2.408 6.072 ;
     RECT  0.06 6.072 2.408 6.192 ;
     RECT  0.084 6.192 2.408 6.216 ;
     RECT  0.06 6.216 2.408 6.336 ;
     RECT  0.084 6.336 2.408 6.36 ;
     RECT  0.06 6.36 2.408 6.48 ;
     RECT  0.084 6.48 2.408 6.504 ;
     RECT  0.06 6.504 2.408 6.624 ;
     RECT  0.084 6.624 2.408 6.648 ;
     RECT  0.06 6.648 2.408 6.768 ;
     RECT  0.084 6.768 2.408 6.792 ;
     RECT  0.06 6.792 2.408 6.912 ;
     RECT  0.084 6.912 2.408 6.936 ;
     RECT  0.06 6.936 2.408 7.056 ;
     RECT  0.084 7.056 2.408 7.08 ;
     RECT  0.06 7.08 2.408 7.2 ;
     RECT  0.084 7.2 2.408 7.224 ;
     RECT  0.06 7.224 2.408 7.344 ;
     RECT  0.084 7.344 2.408 7.368 ;
     RECT  0.06 7.368 2.408 7.488 ;
     RECT  0.084 7.488 2.408 7.512 ;
     RECT  0.06 7.512 2.408 7.632 ;
     RECT  0.084 7.632 2.408 7.656 ;
     RECT  0.06 7.656 2.408 7.776 ;
     RECT  0.084 7.776 2.408 7.8 ;
     RECT  0.06 7.8 2.408 7.92 ;
     RECT  0.084 7.92 2.408 7.944 ;
     RECT  0.06 7.944 2.408 8.064 ;
     RECT  0.084 8.064 2.408 8.088 ;
     RECT  0.06 8.088 2.408 8.208 ;
     RECT  0.084 8.208 2.408 8.232 ;
     RECT  0.06 8.232 2.408 8.352 ;
     RECT  0.084 8.352 2.408 8.376 ;
     RECT  0.06 8.376 2.408 8.496 ;
     RECT  0.084 8.496 2.408 8.52 ;
     RECT  0.06 8.52 2.408 8.64 ;
     RECT  0.084 8.64 2.408 8.664 ;
     RECT  0.06 8.664 2.408 8.784 ;
     RECT  0.084 8.784 2.408 8.808 ;
     RECT  0.06 8.808 2.408 8.928 ;
     RECT  0.084 8.928 2.408 8.952 ;
     RECT  0.06 8.952 2.408 9.072 ;
     RECT  0.084 9.072 2.408 9.096 ;
     RECT  0.06 9.096 2.408 9.216 ;
     RECT  0.084 9.216 2.408 9.24 ;
     RECT  0.06 9.24 2.408 9.36 ;
     RECT  0.084 9.36 2.408 9.384 ;
     RECT  0.06 9.384 2.408 9.504 ;
     RECT  0.084 9.504 2.408 9.528 ;
     RECT  0.06 9.528 2.408 9.648 ;
     RECT  0.084 9.648 2.408 9.672 ;
     RECT  0.06 9.672 2.408 9.792 ;
     RECT  0.084 9.792 2.408 9.816 ;
     RECT  0.06 9.816 2.408 9.936 ;
     RECT  0.084 9.936 2.408 9.96 ;
     RECT  0.06 9.96 2.408 10.08 ;
     RECT  0.084 10.08 2.408 10.104 ;
     RECT  0.06 10.104 2.408 10.224 ;
     RECT  0.084 10.224 2.408 10.248 ;
     RECT  0.06 10.248 2.408 10.368 ;
     RECT  0.084 10.368 2.408 10.392 ;
     RECT  0.06 10.392 2.408 10.512 ;
     RECT  0.084 10.512 2.408 10.536 ;
     RECT  0.06 10.536 2.408 10.656 ;
     RECT  0.084 10.656 2.408 10.68 ;
     RECT  0.06 10.68 2.408 10.8 ;
     RECT  0.084 10.8 2.408 10.824 ;
     RECT  0.06 10.824 2.408 10.944 ;
     RECT  0.084 10.944 2.408 10.968 ;
     RECT  0.06 10.968 2.408 11.088 ;
     RECT  0.084 11.088 2.408 11.112 ;
     RECT  0.06 11.112 2.408 11.232 ;
     RECT  0.084 11.232 2.408 11.256 ;
     RECT  0.06 11.256 2.408 11.376 ;
     RECT  0.084 11.376 2.408 11.4 ;
     RECT  0.06 11.4 2.408 11.52 ;
     RECT  0.084 11.52 2.408 11.544 ;
     RECT  0.06 11.544 2.408 11.664 ;
     RECT  0.084 11.664 2.408 11.688 ;
     RECT  0.06 11.688 2.408 11.808 ;
     RECT  0.084 11.808 2.408 11.832 ;
     RECT  0.06 11.832 2.408 11.952 ;
     RECT  0.084 11.952 2.408 11.976 ;
     RECT  0.06 11.976 2.408 12.096 ;
     RECT  0.084 12.096 2.408 12.12 ;
     RECT  0.06 12.12 2.408 12.24 ;
     RECT  0.084 12.24 2.408 12.264 ;
     RECT  0.06 12.264 2.408 12.384 ;
     RECT  0.084 12.384 2.408 12.408 ;
     RECT  0.06 12.408 2.408 12.528 ;
     RECT  0.084 12.528 2.408 12.552 ;
     RECT  0.06 12.552 2.408 12.672 ;
     RECT  0.084 12.672 2.408 12.696 ;
     RECT  0.06 12.696 2.408 12.816 ;
     RECT  0.084 12.816 2.408 12.84 ;
     RECT  0.06 12.84 2.408 12.96 ;
     RECT  0.084 12.96 2.408 12.984 ;
     RECT  0.06 12.984 2.408 13.104 ;
     RECT  0.084 13.104 2.408 13.128 ;
     RECT  0.06 13.128 2.408 13.248 ;
     RECT  0.084 13.248 2.408 13.272 ;
     RECT  0.06 13.272 2.408 13.392 ;
     RECT  0.084 13.392 2.408 13.416 ;
     RECT  0.06 13.416 2.408 13.536 ;
     RECT  0.084 13.536 2.408 13.56 ;
     RECT  0.06 13.56 2.408 13.68 ;
     RECT  0.084 13.68 2.408 13.704 ;
     RECT  0.06 13.704 2.408 13.824 ;
     RECT  0.084 13.824 2.408 13.848 ;
     RECT  0.06 13.848 2.408 13.968 ;
     RECT  0.084 13.968 2.408 13.992 ;
     RECT  0.06 13.992 2.408 14.112 ;
     RECT  0.084 14.112 2.408 14.136 ;
     RECT  0.06 14.136 2.408 14.256 ;
     RECT  0.084 14.256 2.408 14.28 ;
     RECT  0.06 14.28 2.408 14.4 ;
     RECT  0.084 14.4 2.408 14.424 ;
     RECT  0.06 14.424 2.408 14.544 ;
     RECT  0.084 14.544 2.408 14.568 ;
     RECT  0.06 14.568 2.408 14.688 ;
     RECT  0.084 14.688 2.408 14.712 ;
     RECT  0.06 14.712 2.408 14.832 ;
     RECT  0.084 14.832 2.408 14.856 ;
     RECT  0.06 14.856 2.408 14.976 ;
     RECT  0.084 14.976 2.408 15 ;
     RECT  0.06 15 2.408 15.12 ;
     RECT  0.084 15.12 2.408 15.144 ;
     RECT  0.06 15.144 2.408 15.264 ;
     RECT  0.084 15.264 2.408 15.288 ;
     RECT  0.06 15.288 2.408 15.408 ;
     RECT  0.084 15.408 2.408 15.432 ;
     RECT  0.06 15.432 2.408 15.552 ;
     RECT  0.084 15.552 2.408 15.576 ;
     RECT  0.06 15.576 2.408 15.696 ;
     RECT  0.084 15.696 2.408 15.72 ;
     RECT  0.06 15.72 2.408 15.84 ;
     RECT  0.084 15.84 2.408 15.864 ;
     RECT  0.06 15.864 2.408 15.984 ;
     RECT  0.084 15.984 2.408 16.008 ;
     RECT  0.06 16.008 2.408 16.128 ;
     RECT  0.084 16.128 2.408 16.152 ;
     RECT  0.06 16.152 2.408 16.272 ;
     RECT  0.084 16.272 2.408 16.296 ;
     RECT  0.06 16.296 2.408 16.416 ;
     RECT  0.084 16.416 2.408 16.44 ;
     RECT  0.06 16.44 2.408 16.56 ;
     RECT  0.084 16.56 2.408 16.584 ;
     RECT  0.06 16.584 2.408 16.704 ;
     RECT  0.084 16.704 2.408 16.728 ;
     RECT  0.06 16.728 2.408 16.848 ;
     RECT  0.084 16.848 2.408 16.872 ;
     RECT  0.06 16.872 2.408 16.992 ;
     RECT  0.084 16.992 2.408 17.016 ;
     RECT  0.06 17.016 2.408 17.136 ;
     RECT  0.084 17.136 2.408 17.16 ;
     RECT  0.06 17.16 2.408 17.28 ;
     RECT  0.084 17.28 2.408 17.304 ;
     RECT  0.06 17.304 2.408 17.424 ;
     RECT  0.084 17.424 2.408 17.448 ;
     RECT  0.06 17.448 2.408 17.568 ;
     RECT  0.084 17.568 2.408 17.592 ;
     RECT  0.06 17.592 2.408 17.712 ;
     RECT  0.084 17.712 2.408 17.736 ;
     RECT  0.06 17.736 2.408 17.856 ;
     RECT  0.084 17.856 2.408 17.88 ;
     RECT  0.06 17.88 2.408 18 ;
     RECT  0.084 18 2.408 18.024 ;
     RECT  0.06 18.024 2.408 18.144 ;
     RECT  0.084 18.144 2.408 18.168 ;
     RECT  0.06 18.168 2.408 18.288 ;
     RECT  0.084 18.288 2.408 18.312 ;
     RECT  0.06 18.312 2.408 18.432 ;
     RECT  0.084 18.432 2.408 18.456 ;
     RECT  0.06 18.456 2.408 18.576 ;
     RECT  0.084 18.576 2.408 18.6 ;
     RECT  0.06 18.6 2.408 18.72 ;
     RECT  0.084 18.72 2.408 18.744 ;
     RECT  0.06 18.744 2.408 18.864 ;
     RECT  0.084 18.864 2.408 18.888 ;
     RECT  0.06 18.888 2.408 19.008 ;
     RECT  0.084 19.008 2.408 19.032 ;
     RECT  0.06 19.032 2.408 19.152 ;
     RECT  0.084 19.152 2.408 19.176 ;
     RECT  0.06 19.176 2.408 19.296 ;
     RECT  0.084 19.296 2.408 19.32 ;
     RECT  0.06 19.32 2.408 19.44 ;
     RECT  0.084 19.44 2.408 19.464 ;
     RECT  0.06 19.464 2.408 19.584 ;
     RECT  0.084 19.584 2.408 19.608 ;
     RECT  0.06 19.608 2.408 19.728 ;
     RECT  0.084 19.728 2.408 19.752 ;
     RECT  0.06 19.752 2.408 19.872 ;
     RECT  0.084 19.872 2.408 19.896 ;
     RECT  0.06 19.896 2.408 20.016 ;
     RECT  0.084 20.016 2.408 20.04 ;
     RECT  0.06 20.04 2.408 20.16 ;
     RECT  0.084 20.16 2.408 20.184 ;
     RECT  0.06 20.184 2.408 20.304 ;
     RECT  0.084 20.304 2.408 20.328 ;
     RECT  0.06 20.328 2.408 20.448 ;
     RECT  0.084 20.448 2.408 20.472 ;
     RECT  0.06 20.472 2.408 20.592 ;
     RECT  0.084 20.592 2.408 20.616 ;
     RECT  0.06 20.616 2.408 20.736 ;
     RECT  0.084 20.736 2.408 20.76 ;
     RECT  0.06 20.76 2.408 20.88 ;
     RECT  0.084 20.88 2.408 20.904 ;
     RECT  0.06 20.904 2.408 21.024 ;
     RECT  0.084 21.024 2.408 21.048 ;
     RECT  0.06 21.048 2.408 21.168 ;
     RECT  0.084 21.168 2.408 21.192 ;
     RECT  0.06 21.192 2.408 21.312 ;
     RECT  0.084 21.312 2.408 21.336 ;
     RECT  0.06 21.336 2.408 21.456 ;
     RECT  0.084 21.456 2.408 21.48 ;
     RECT  0.06 21.48 2.408 21.6 ;
     RECT  0.084 21.6 2.408 21.624 ;
     RECT  0.06 21.624 2.408 21.744 ;
     RECT  0.084 21.744 2.408 21.768 ;
     RECT  0.06 21.768 2.408 21.888 ;
     RECT  0.084 21.888 2.408 21.912 ;
     RECT  0.06 21.912 2.408 22.032 ;
     RECT  0.084 22.032 2.408 22.056 ;
     RECT  0.06 22.056 2.408 22.176 ;
     RECT  0.084 22.176 2.408 22.2 ;
     RECT  0.06 22.2 2.408 22.32 ;
     RECT  0.084 22.32 2.408 22.344 ;
     RECT  0.06 22.344 2.408 22.464 ;
     RECT  0.084 22.464 2.408 22.488 ;
     RECT  0.06 22.488 2.408 22.608 ;
     RECT  0.084 22.608 2.408 22.632 ;
     RECT  0.06 22.632 2.408 22.752 ;
     RECT  0.084 22.752 2.408 22.776 ;
     RECT  0.06 22.776 2.408 22.896 ;
     RECT  0.084 22.896 2.408 22.92 ;
     RECT  0.06 22.92 2.408 23.04 ;
     RECT  0.084 23.04 2.408 23.064 ;
     RECT  0.06 23.064 2.408 23.184 ;
     RECT  0.084 23.184 2.408 23.208 ;
     RECT  0.06 23.208 2.408 23.328 ;
     RECT  0.084 23.328 2.408 23.352 ;
     RECT  0.06 23.352 2.408 23.472 ;
     RECT  0.084 23.472 2.408 23.496 ;
     RECT  0.06 23.496 2.408 23.616 ;
     RECT  0.084 23.616 2.408 23.64 ;
     RECT  0.084 24.912 2.408 24.936 ;
     RECT  0.06 24.936 2.408 25.056 ;
     RECT  0.084 25.056 2.408 25.08 ;
     RECT  0.06 25.08 2.408 25.2 ;
     RECT  0.084 25.2 2.408 25.224 ;
     RECT  0.06 25.224 2.408 25.344 ;
     RECT  0.084 25.344 2.408 25.368 ;
     RECT  0.06 25.368 2.408 25.488 ;
     RECT  0.084 25.488 2.408 25.512 ;
     RECT  0.06 25.512 2.408 25.632 ;
     RECT  0.084 25.632 2.408 25.656 ;
     RECT  0.06 25.656 2.408 25.776 ;
     RECT  0.084 25.776 2.408 25.8 ;
     RECT  0.06 25.8 2.408 25.92 ;
     RECT  0.084 25.92 2.408 25.944 ;
     RECT  0.06 25.944 2.408 26.064 ;
     RECT  0.084 26.064 2.408 26.088 ;
     RECT  0.06 26.088 2.408 26.208 ;
     RECT  0.084 26.208 2.408 26.232 ;
     RECT  0.06 26.232 2.408 26.352 ;
     RECT  0.084 26.352 2.408 26.376 ;
     RECT  0.06 26.376 2.408 26.496 ;
     RECT  0.084 26.496 2.408 26.52 ;
     RECT  0.06 26.52 2.408 26.64 ;
     RECT  0.084 26.64 2.408 26.664 ;
     RECT  0.06 26.664 2.408 26.784 ;
     RECT  0.084 26.784 2.408 26.808 ;
     RECT  0.06 26.808 2.408 26.928 ;
     RECT  0.084 26.928 2.408 26.952 ;
     RECT  0.06 26.952 2.408 27.072 ;
     RECT  0.084 27.072 2.408 27.096 ;
     RECT  0.06 27.096 2.408 27.216 ;
     RECT  0.084 27.216 2.408 27.24 ;
     RECT  0.06 27.24 2.408 27.36 ;
     RECT  0.084 27.36 2.408 27.384 ;
     RECT  0.06 27.384 2.408 27.504 ;
     RECT  0.084 27.504 2.408 27.528 ;
     RECT  0.06 27.528 2.408 27.648 ;
     RECT  0.084 27.648 2.408 27.672 ;
     RECT  0.06 27.672 2.408 27.792 ;
     RECT  0.084 27.792 2.408 27.816 ;
     RECT  0.06 27.816 2.408 27.936 ;
     RECT  0.084 27.936 2.408 27.96 ;
     RECT  0.06 27.96 2.408 28.08 ;
     RECT  0.084 28.08 2.408 28.104 ;
     RECT  0.06 28.104 2.408 28.224 ;
     RECT  0.084 28.224 2.408 28.248 ;
     RECT  0.06 28.248 2.408 28.368 ;
     RECT  0.084 28.368 2.408 28.392 ;
     RECT  0.06 28.392 2.408 28.512 ;
     RECT  0.084 28.512 2.408 28.536 ;
     RECT  0.06 28.536 2.408 28.656 ;
     RECT  0.084 28.656 2.408 28.68 ;
     RECT  0.06 28.68 2.408 28.8 ;
     RECT  0.084 28.8 2.408 28.824 ;
     RECT  0.06 28.824 2.408 28.944 ;
     RECT  0.084 28.944 2.408 28.968 ;
     RECT  0.06 28.968 2.408 29.088 ;
     RECT  0.084 29.088 2.408 29.112 ;
     RECT  0.06 29.112 2.408 29.232 ;
     RECT  0.084 29.232 2.408 29.256 ;
     RECT  0.06 29.256 2.408 29.376 ;
     RECT  0.084 29.376 2.408 29.4 ;
     RECT  0.06 29.4 2.408 29.52 ;
     RECT  0.084 29.52 2.408 29.544 ;
     RECT  0.06 29.544 2.408 29.664 ;
     RECT  0.084 29.664 2.408 29.688 ;
     RECT  0.06 29.688 2.408 29.808 ;
     RECT  0.084 29.808 2.408 29.832 ;
     RECT  0.06 29.832 2.408 29.952 ;
     RECT  0.084 29.952 2.408 29.976 ;
     RECT  0.06 29.976 2.408 30.096 ;
     RECT  0.084 30.096 2.408 30.12 ;
     RECT  0.06 30.12 2.408 30.24 ;
     RECT  0.084 30.24 2.408 30.264 ;
     RECT  0.06 30.264 2.408 30.384 ;
     RECT  0.084 30.384 2.408 30.408 ;
     RECT  0.06 30.408 2.408 30.528 ;
     RECT  0.084 30.528 2.408 30.552 ;
     RECT  0.06 30.552 2.408 30.672 ;
     RECT  0.084 30.672 2.408 30.696 ;
     RECT  0.06 30.696 2.408 30.816 ;
     RECT  0.084 30.816 2.408 30.84 ;
     RECT  0.06 30.84 2.408 30.96 ;
     RECT  0.084 30.96 2.408 30.984 ;
     RECT  0.06 30.984 2.408 31.104 ;
     RECT  0.084 31.104 2.408 31.128 ;
     RECT  0.06 31.128 2.408 31.248 ;
     RECT  0.084 31.248 2.408 31.272 ;
     RECT  0.06 31.272 2.408 31.392 ;
     RECT  0.084 31.392 2.408 31.416 ;
     RECT  0.06 31.416 2.408 31.536 ;
     RECT  0.084 31.536 2.408 31.56 ;
     RECT  0.06 31.56 2.408 31.68 ;
     RECT  0.084 31.68 2.408 31.704 ;
     RECT  0.06 31.704 2.408 31.824 ;
     RECT  0.084 31.824 2.408 31.848 ;
     RECT  0.06 31.848 2.408 31.968 ;
     RECT  0.084 31.968 2.408 31.992 ;
     RECT  0.06 31.992 2.408 32.112 ;
     RECT  0.084 32.112 2.408 32.136 ;
     RECT  0.06 32.136 2.408 32.256 ;
     RECT  0.084 32.256 2.408 32.28 ;
     RECT  0.06 32.28 2.408 32.4 ;
     RECT  0.084 32.4 2.408 32.424 ;
     RECT  0.06 32.424 2.408 32.544 ;
     RECT  0.084 32.544 2.408 32.568 ;
     RECT  0.06 32.568 2.408 32.688 ;
     RECT  0.084 32.688 2.408 32.712 ;
     RECT  0.06 32.712 2.408 32.832 ;
     RECT  0.084 32.832 2.408 32.856 ;
     RECT  0.06 32.856 2.408 32.976 ;
     RECT  0.084 32.976 2.408 33 ;
     RECT  0.06 33 2.408 33.12 ;
     RECT  0.084 33.12 2.408 33.144 ;
     RECT  0.06 33.144 2.408 33.264 ;
     RECT  0.084 33.264 2.408 33.288 ;
     RECT  0.06 33.288 2.408 33.408 ;
     RECT  0.084 33.408 2.408 33.432 ;
     RECT  0.06 33.432 2.408 33.552 ;
     RECT  0.084 33.552 2.408 33.576 ;
     RECT  0.06 33.576 2.408 33.696 ;
     RECT  0.084 33.696 2.408 33.72 ;
     RECT  0.06 33.72 2.408 33.84 ;
     RECT  0.084 33.84 2.408 33.864 ;
     RECT  0.06 33.864 2.408 33.984 ;
     RECT  0.084 33.984 2.408 34.008 ;
     RECT  0.06 34.008 2.408 34.128 ;
     RECT  0.084 34.128 2.408 34.152 ;
     RECT  0.06 34.152 2.408 34.272 ;
     RECT  0.084 34.272 2.408 34.296 ;
     RECT  0.06 34.296 2.408 34.416 ;
     RECT  0.084 34.416 2.408 34.44 ;
     RECT  0.06 34.44 2.408 34.56 ;
     RECT  0.084 34.56 2.408 34.584 ;
     RECT  0.06 34.584 2.408 34.704 ;
     RECT  0.084 34.704 2.408 34.728 ;
     RECT  0.06 34.728 2.408 34.848 ;
     RECT  0.084 34.848 2.408 34.872 ;
     RECT  0.06 34.872 2.408 34.992 ;
     RECT  0.084 34.992 2.408 35.016 ;
     RECT  0.06 35.016 2.408 35.136 ;
     RECT  0.084 35.136 2.408 35.16 ;
     RECT  0.06 35.16 2.408 35.28 ;
     RECT  0.084 35.28 2.408 35.304 ;
     RECT  0.06 35.304 2.408 35.424 ;
     RECT  0.084 35.424 2.408 35.448 ;
     RECT  0.06 35.448 2.408 35.568 ;
     RECT  0.084 35.568 2.408 35.592 ;
     RECT  0.06 35.592 2.408 35.712 ;
     RECT  0.084 35.712 2.408 35.736 ;
     RECT  0.06 35.736 2.408 35.856 ;
     RECT  0.084 35.856 2.408 35.88 ;
     RECT  0.06 35.88 2.408 36 ;
     RECT  0.084 36 2.408 36.024 ;
     RECT  0.06 36.024 2.408 36.144 ;
     RECT  0.084 36.144 2.408 36.168 ;
     RECT  0.06 36.168 2.408 36.288 ;
     RECT  0.084 36.288 2.408 36.312 ;
     RECT  0.06 36.312 2.408 36.432 ;
     RECT  0.084 36.432 2.408 36.456 ;
     RECT  0.06 36.456 2.408 36.576 ;
     RECT  0.084 36.576 2.408 36.6 ;
     RECT  0.06 36.6 2.408 36.72 ;
     RECT  0.084 36.72 2.408 36.744 ;
     RECT  0.06 36.744 2.408 36.864 ;
     RECT  0.084 36.864 2.408 36.888 ;
     RECT  0.06 36.888 2.408 37.008 ;
     RECT  0.084 37.008 2.408 37.032 ;
     RECT  0.06 37.032 2.408 37.152 ;
     RECT  0.084 37.152 2.408 37.176 ;
     RECT  0.06 37.176 2.408 37.296 ;
     RECT  0.084 37.296 2.408 37.32 ;
     RECT  0.06 37.32 2.408 37.44 ;
     RECT  0.084 37.44 2.408 37.464 ;
     RECT  0.06 37.464 2.408 37.584 ;
     RECT  0.084 37.584 2.408 37.608 ;
     RECT  0.06 37.608 2.408 37.728 ;
     RECT  0.084 37.728 2.408 37.752 ;
     RECT  0.06 37.752 2.408 37.872 ;
     RECT  0.084 37.872 2.408 37.896 ;
     RECT  0.06 37.896 2.408 38.016 ;
     RECT  0.084 38.016 2.408 38.04 ;
     RECT  0.06 38.04 2.408 38.16 ;
     RECT  0.084 38.16 2.408 38.184 ;
     RECT  0.06 38.184 2.408 38.304 ;
     RECT  0.084 38.304 2.408 38.328 ;
     RECT  0.06 38.328 2.408 38.448 ;
     RECT  0.084 38.448 2.408 38.472 ;
     RECT  0.06 38.472 2.408 38.592 ;
     RECT  0.084 38.592 2.408 38.616 ;
     RECT  0.06 38.616 2.408 38.736 ;
     RECT  0.084 38.736 2.408 38.76 ;
     RECT  0.06 38.76 2.408 38.88 ;
     RECT  0.084 38.88 2.408 38.904 ;
     RECT  0.06 38.904 2.408 39.024 ;
     RECT  0.084 39.024 2.408 39.048 ;
     RECT  0.06 39.048 2.408 39.168 ;
     RECT  0.084 39.168 2.408 39.192 ;
     RECT  0.06 39.192 2.408 39.312 ;
     RECT  0.084 39.312 2.408 39.336 ;
     RECT  0.06 39.336 2.408 39.456 ;
     RECT  0.084 39.456 2.408 39.48 ;
     RECT  0.06 39.48 2.408 39.6 ;
     RECT  0.084 39.6 2.408 39.624 ;
     RECT  0.06 39.624 2.408 39.744 ;
     RECT  0.084 39.744 2.408 39.768 ;
     RECT  0.06 39.768 2.408 39.888 ;
     RECT  0.084 39.888 2.408 39.912 ;
     RECT  0.06 39.912 2.408 40.032 ;
     RECT  0.084 40.032 2.408 40.056 ;
     RECT  0.06 40.056 2.408 40.176 ;
     RECT  0.084 40.176 2.408 40.2 ;
     RECT  0.06 40.2 2.408 40.32 ;
     RECT  0.084 40.32 2.408 40.344 ;
     RECT  0.06 40.344 2.408 40.464 ;
     RECT  0.084 40.464 2.408 40.488 ;
     RECT  0.06 40.488 2.408 40.608 ;
     RECT  0.084 40.608 2.408 40.632 ;
     RECT  0.06 40.632 2.408 40.752 ;
     RECT  0.084 40.752 2.408 40.776 ;
     RECT  0.06 40.776 2.408 40.896 ;
     RECT  0.084 40.896 2.408 40.92 ;
     RECT  0.06 40.92 2.408 41.04 ;
     RECT  0.084 41.04 2.408 41.064 ;
     RECT  0.06 41.064 2.408 41.184 ;
     RECT  0.084 41.184 2.408 41.208 ;
     RECT  0.06 41.208 2.408 41.328 ;
     RECT  0.084 41.328 2.408 41.352 ;
     RECT  0.06 41.352 2.408 41.472 ;
     RECT  0.084 41.472 2.408 41.496 ;
     RECT  0.06 41.496 2.408 41.616 ;
     RECT  0.084 41.616 2.408 41.64 ;
     RECT  0.06 41.64 2.408 41.76 ;
     RECT  0.084 41.76 2.408 41.784 ;
     RECT  0.06 41.784 2.408 41.904 ;
     RECT  0.084 41.904 2.408 41.928 ;
     RECT  0.06 41.928 2.408 42.048 ;
     RECT  0.084 42.048 2.408 42.072 ;
     RECT  0.06 42.072 2.408 42.192 ;
     RECT  0.084 42.192 2.408 42.216 ;
     RECT  0.06 42.216 2.408 42.336 ;
     RECT  0.084 42.336 2.408 42.36 ;
     RECT  0.06 42.36 2.408 42.48 ;
     RECT  0.084 42.48 2.408 42.504 ;
     RECT  0.06 42.504 2.408 42.624 ;
     RECT  0.084 42.624 2.408 42.648 ;
     RECT  0.06 42.648 2.408 42.768 ;
     RECT  0.084 42.768 2.408 42.792 ;
     RECT  0.06 42.792 2.408 42.912 ;
     RECT  0.084 42.912 2.408 42.936 ;
     RECT  0.06 42.936 2.408 43.056 ;
     RECT  0.084 43.056 2.408 43.08 ;
     RECT  0.06 43.08 2.408 43.2 ;
     RECT  0.084 43.2 2.408 43.224 ;
     RECT  0.06 43.224 2.408 43.344 ;
     RECT  0.084 43.344 2.408 43.368 ;
     RECT  0.06 43.368 2.408 43.488 ;
     RECT  0.084 43.488 2.408 43.512 ;
     RECT  0.06 43.512 2.408 43.632 ;
     RECT  0.084 43.632 2.408 43.656 ;
     RECT  0.06 43.656 2.408 43.776 ;
     RECT  0.084 43.776 2.408 43.8 ;
     RECT  0.06 43.8 2.408 43.92 ;
     RECT  0.084 43.92 2.408 43.944 ;
     RECT  0.06 43.944 2.408 44.064 ;
     RECT  0.084 44.064 2.408 44.088 ;
     RECT  0.06 44.088 2.408 44.208 ;
     RECT  0.084 44.208 2.408 44.232 ;
     RECT  0.06 44.232 2.408 44.352 ;
     RECT  0.084 44.352 2.408 44.376 ;
     RECT  0.06 44.376 2.408 44.496 ;
     RECT  0.084 44.496 2.408 44.52 ;
     RECT  0.06 44.52 2.408 44.64 ;
     RECT  0.084 44.64 2.408 44.664 ;
     RECT  0.06 44.664 2.408 44.784 ;
     RECT  0.084 44.784 2.408 44.808 ;
     RECT  0.06 44.808 2.408 44.928 ;
     RECT  0.084 44.928 2.408 44.952 ;
     RECT  0.06 44.952 2.408 45.072 ;
     RECT  0.084 45.072 2.408 45.096 ;
     RECT  0.06 45.096 2.408 45.216 ;
     RECT  0.084 45.216 2.408 45.24 ;
     RECT  0.06 45.24 2.408 45.36 ;
     RECT  0.084 45.36 2.408 45.384 ;
     RECT  0.06 45.384 2.408 45.504 ;
     RECT  0.084 45.504 2.408 45.528 ;
     RECT  0.06 45.528 2.408 45.648 ;
     RECT  0.084 45.648 2.408 45.672 ;
     RECT  0.06 45.672 2.408 45.792 ;
     RECT  0.084 45.792 2.408 45.816 ;
     RECT  0.06 45.816 2.408 45.936 ;
     RECT  0.084 45.936 2.408 45.96 ;
     RECT  0.06 45.96 2.408 46.08 ;
     RECT  0.084 46.08 2.408 46.104 ;
     RECT  0.06 46.104 2.408 46.224 ;
     RECT  0.084 46.224 2.408 46.248 ;
     RECT  0.06 46.248 2.408 46.368 ;
     RECT  0.084 46.368 2.408 46.392 ;
     RECT  0.06 46.392 2.408 46.512 ;
     RECT  0.084 46.512 2.408 46.536 ;
     RECT  0.06 46.536 2.408 46.656 ;
     RECT  0.084 46.656 2.408 46.68 ;
     RECT  0.06 46.68 2.408 46.8 ;
     RECT  0.084 46.8 2.408 46.824 ;
     RECT  0.06 46.824 2.408 46.944 ;
     RECT  0.084 46.944 2.408 46.968 ;
     RECT  0.06 46.968 2.408 47.088 ;
     RECT  0.084 47.088 2.408 47.112 ;
     RECT  0.06 47.112 2.408 47.232 ;
     RECT  0.084 47.232 2.408 47.256 ;
     RECT  0.06 47.256 2.408 47.376 ;
     RECT  0.084 47.376 2.408 47.4 ;
     RECT  0.06 47.4 2.408 47.52 ;
     RECT  0.084 47.52 2.408 47.544 ;
     RECT  0.06 47.544 2.408 47.664 ;
     RECT  0.084 47.664 2.408 47.688 ;
     RECT  0.06 47.688 2.408 47.808 ;
     RECT  0.084 47.808 2.408 47.832 ;
     RECT  0.06 47.832 2.408 47.952 ;
     RECT  0.084 47.952 2.408 47.976 ;
     RECT  0.06 47.976 2.408 48.096 ;
     RECT  0.084 48.096 2.408 48.12 ;
     RECT  0.06 48.12 2.408 48.24 ;
     RECT  0.084 48.24 2.408 48.264 ;
     RECT  0.06 48.264 2.408 48.384 ;
     RECT  0.084 48.384 2.408 48.408 ;
     RECT  0.06 48.408 2.408 48.528 ;
     RECT  0.084 48.528 2.408 48.552 ;
     RECT  0.06 48.552 2.408 48.672 ;
     RECT  0.084 48.672 2.408 48.696 ;
     RECT  0.06 48.696 2.408 48.816 ;
     RECT  0.084 48.816 2.408 48.84 ;
     RECT  0.06 48.84 2.408 48.96 ;
     RECT  0.084 48.96 2.408 48.984 ;
     RECT  0.06 48.984 2.408 49.104 ;
     RECT  0.084 49.104 2.408 49.128 ;
     RECT  0.06 49.128 2.408 49.248 ;
     RECT  0.084 49.248 2.408 49.272 ;
     RECT  0.06 49.272 2.408 49.392 ;
     RECT  0.084 49.392 2.408 49.416 ;
     RECT  0.06 49.416 2.408 49.536 ;
     RECT  0.084 49.536 2.408 49.56 ;
     RECT  0.06 49.56 2.408 49.68 ;
     RECT  0.084 49.68 2.408 49.704 ;
     RECT  0.06 49.704 2.408 49.824 ;
     RECT  0.084 49.824 2.408 49.848 ;
     RECT  0.06 49.848 2.408 49.968 ;
     RECT  0.084 49.968 2.408 49.992 ;
     RECT  0.06 49.992 2.408 50.112 ;
     RECT  0.084 50.112 2.408 50.136 ;
     RECT  0.06 50.136 2.408 50.256 ;
     RECT  0.084 50.256 2.408 50.28 ;
     RECT  0.06 50.28 2.408 50.4 ;
     RECT  0.084 50.4 2.408 50.424 ;
     RECT  0.06 50.424 2.408 50.544 ;
     RECT  0.084 50.544 2.408 50.568 ;
     RECT  0.06 50.568 2.408 50.688 ;
     RECT  0.084 50.688 2.408 50.712 ;
     RECT  0.06 50.712 2.408 50.832 ;
     RECT  0.084 50.832 2.408 50.856 ;
     RECT  0.06 50.856 2.408 50.976 ;
     RECT  0.084 50.976 2.408 51 ;
     RECT  0.06 51 2.408 51.12 ;
     RECT  0.084 51.12 2.408 51.144 ;
     RECT  0.06 51.144 2.408 51.264 ;
     RECT  0.084 51.264 2.408 51.288 ;
     RECT  0.06 51.288 2.408 51.408 ;
     RECT  0.084 51.408 2.408 51.432 ;
     RECT  0.06 51.432 2.408 51.552 ;
     RECT  0.084 51.552 2.408 51.576 ;
     RECT  0.06 51.576 2.408 51.696 ;
     RECT  0.084 51.696 2.408 51.72 ;
     RECT  0.06 51.72 2.408 51.84 ;
     RECT  0.084 51.84 2.408 51.864 ;
     RECT  0.06 51.864 2.408 51.984 ;
     RECT  0.084 51.984 2.408 52.008 ;
     RECT  0.06 52.008 2.408 52.128 ;
     RECT  0.084 52.128 2.408 52.152 ;
     RECT  0.06 52.152 2.408 52.272 ;
     RECT  0.084 52.272 2.408 52.296 ;
     RECT  0.06 52.296 2.408 52.416 ;
     RECT  0.084 52.416 2.408 52.44 ;
     RECT  0.084 53.712 2.408 53.736 ;
     RECT  0.06 53.736 2.408 53.856 ;
     RECT  0.084 53.856 2.408 53.88 ;
     RECT  0.06 53.88 2.408 54 ;
     RECT  0.084 54 2.408 54.024 ;
     RECT  0.06 54.024 2.408 54.144 ;
     RECT  0.084 54.144 2.408 54.168 ;
     RECT  0.06 54.168 2.408 54.288 ;
     RECT  0.084 54.288 2.408 54.312 ;
     RECT  0.06 54.312 2.408 54.432 ;
     RECT  0.084 54.432 2.408 54.456 ;
     RECT  0.06 54.456 2.408 54.576 ;
     RECT  0.084 54.576 2.408 54.6 ;
     RECT  0.06 54.6 2.408 54.72 ;
     RECT  0.084 54.72 2.408 54.744 ;
     RECT  0.06 54.744 2.408 54.864 ;
     RECT  0.084 54.864 2.408 54.888 ;
     RECT  0.06 54.888 2.408 55.008 ;
     RECT  0.084 55.008 2.408 55.032 ;
     RECT  0.06 55.032 2.408 55.152 ;
     RECT  0.084 55.152 2.408 55.176 ;
     RECT  0.06 55.176 2.408 55.296 ;
     RECT  0.084 55.296 2.408 55.32 ;
     RECT  0.06 55.32 2.408 55.44 ;
     RECT  0.084 55.44 2.408 55.464 ;
     RECT  0.06 55.464 2.408 55.584 ;
     RECT  0.084 55.584 2.408 55.608 ;
     RECT  0.06 55.608 2.408 55.728 ;
     RECT  0.084 55.728 2.408 55.752 ;
     RECT  0.06 55.752 2.408 55.872 ;
     RECT  0.084 55.872 2.408 55.896 ;
     RECT  0.06 55.896 2.408 56.016 ;
     RECT  0.084 56.016 2.408 56.04 ;
     RECT  0.06 56.04 2.408 56.16 ;
     RECT  0.084 56.16 2.408 56.184 ;
     RECT  0.06 56.184 2.408 56.304 ;
     RECT  0.084 56.304 2.408 56.328 ;
     RECT  0.06 56.328 2.408 56.448 ;
     RECT  0.084 56.448 2.408 56.472 ;
     RECT  0.06 56.472 2.408 56.592 ;
     RECT  0.084 56.592 2.408 56.616 ;
     RECT  0.06 56.616 2.408 56.736 ;
     RECT  0.084 56.736 2.408 56.76 ;
     RECT  0.06 56.76 2.408 56.88 ;
     RECT  0.084 56.88 2.408 56.904 ;
     RECT  0.06 56.904 2.408 57.024 ;
     RECT  0.084 57.024 2.408 57.048 ;
     RECT  0.06 57.048 2.408 57.168 ;
     RECT  0.084 57.168 2.408 57.192 ;
     RECT  0.06 57.192 2.408 57.312 ;
     RECT  0.084 57.312 2.408 57.336 ;
     RECT  0.06 57.336 2.408 57.456 ;
     RECT  0.084 57.456 2.408 57.48 ;
     RECT  0.06 57.48 2.408 57.6 ;
     RECT  0.084 57.6 2.408 57.624 ;
     RECT  0.06 57.624 2.408 57.744 ;
     RECT  0.084 57.744 2.408 57.768 ;
     RECT  0.06 57.768 2.408 57.888 ;
     RECT  0.084 57.888 2.408 57.912 ;
     RECT  0.06 57.912 2.408 58.032 ;
     RECT  0.084 58.032 2.408 58.056 ;
     RECT  0.06 58.056 2.408 58.176 ;
     RECT  0.084 58.176 2.408 58.2 ;
     RECT  0.06 58.2 2.408 58.32 ;
     RECT  0.084 58.32 2.408 58.344 ;
     RECT  0.06 58.344 2.408 58.464 ;
     RECT  0.084 58.464 2.408 58.488 ;
     RECT  0.06 58.488 2.408 58.608 ;
     RECT  0.084 58.608 2.408 58.632 ;
     RECT  0.06 58.632 2.408 58.752 ;
     RECT  0.084 58.752 2.408 58.776 ;
     RECT  0.06 58.776 2.408 58.896 ;
     RECT  0.084 58.896 2.408 58.92 ;
     RECT  0.06 58.92 2.408 59.04 ;
     RECT  0.084 59.04 2.408 59.064 ;
     RECT  0.06 59.064 2.408 59.184 ;
     RECT  0.084 59.184 2.408 59.208 ;
     RECT  0.06 59.208 2.408 59.328 ;
     RECT  0.084 59.328 2.408 59.352 ;
     RECT  0.06 59.352 2.408 59.472 ;
     RECT  0.084 59.472 2.408 59.496 ;
     RECT  0.06 59.496 2.408 59.616 ;
     RECT  0.084 59.616 2.408 59.64 ;
     RECT  0.06 59.64 2.408 59.76 ;
     RECT  0.084 59.76 2.408 59.784 ;
     RECT  0.06 59.784 2.408 59.904 ;
     RECT  0.084 59.904 2.408 59.928 ;
     RECT  0.06 59.928 2.408 60.048 ;
     RECT  0.084 60.048 2.408 60.072 ;
     RECT  0.06 60.072 2.408 60.192 ;
     RECT  0.084 60.192 2.408 60.216 ;
     RECT  0.06 60.216 2.408 60.336 ;
     RECT  0.084 60.336 2.408 60.36 ;
     RECT  0.06 60.36 2.408 60.48 ;
     RECT  0.084 60.48 2.408 60.504 ;
     RECT  0.06 60.504 2.408 60.624 ;
     RECT  0.084 60.624 2.408 60.648 ;
     RECT  0.06 60.648 2.408 60.768 ;
     RECT  0.084 60.768 2.408 60.792 ;
     RECT  0.06 60.792 2.408 60.912 ;
     RECT  0.084 60.912 2.408 60.936 ;
     RECT  0.06 60.936 2.408 61.056 ;
     RECT  0.084 61.056 2.408 61.08 ;
     RECT  0.06 61.08 2.408 61.2 ;
     RECT  0.084 61.2 2.408 61.224 ;
     RECT  0.06 61.224 2.408 61.344 ;
     RECT  0.084 61.344 2.408 61.368 ;
     RECT  0.06 61.368 2.408 61.488 ;
     RECT  0.084 61.488 2.408 61.512 ;
     RECT  0.06 61.512 2.408 61.632 ;
     RECT  0.084 61.632 2.408 61.656 ;
     RECT  0.06 61.656 2.408 61.776 ;
     RECT  0.084 61.776 2.408 61.8 ;
     RECT  0.06 61.8 2.408 61.92 ;
     RECT  0.084 61.92 2.408 61.944 ;
     RECT  0.06 61.944 2.408 62.064 ;
     RECT  0.084 62.064 2.408 62.088 ;
     RECT  0.06 62.088 2.408 62.208 ;
     RECT  0.084 62.208 2.408 62.232 ;
     RECT  0.06 62.232 2.408 62.352 ;
     RECT  0.084 62.352 2.408 62.376 ;
     RECT  0.06 62.376 2.408 62.496 ;
     RECT  0.084 62.496 2.408 62.52 ;
     RECT  0.06 62.52 2.408 62.64 ;
     RECT  0.084 62.64 2.408 62.664 ;
     RECT  0.06 62.664 2.408 62.784 ;
     RECT  0.084 62.784 2.408 62.808 ;
     RECT  0.06 62.808 2.408 62.928 ;
     RECT  0.084 62.928 2.408 62.952 ;
     RECT  0.06 62.952 2.408 63.072 ;
     RECT  0.084 63.072 2.408 63.096 ;
     RECT  0.06 63.096 2.408 63.216 ;
     RECT  0.084 63.216 2.408 63.24 ;
     RECT  0.06 63.24 2.408 63.36 ;
     RECT  0.084 63.36 2.408 63.384 ;
     RECT  0.06 63.384 2.408 63.504 ;
     RECT  0.084 63.504 2.408 63.528 ;
     RECT  0.06 63.528 2.408 63.648 ;
     RECT  0.084 63.648 2.408 63.672 ;
     RECT  0.06 63.672 2.408 63.792 ;
     RECT  0.084 63.792 2.408 63.816 ;
     RECT  0.06 63.816 2.408 63.936 ;
     RECT  0.084 63.936 2.408 63.96 ;
     RECT  0.06 63.96 2.408 64.08 ;
     RECT  0.084 64.08 2.408 64.104 ;
     RECT  0.06 64.104 2.408 64.224 ;
     RECT  0.084 64.224 2.408 64.248 ;
     RECT  0.06 64.248 2.408 64.368 ;
     RECT  0.084 64.368 2.408 64.392 ;
     RECT  0.06 64.392 2.408 64.512 ;
     RECT  0.084 64.512 2.408 64.536 ;
     RECT  0.06 64.536 2.408 64.656 ;
     RECT  0.084 64.656 2.408 64.68 ;
     RECT  0.06 64.68 2.408 64.8 ;
     RECT  0.084 64.8 2.408 64.824 ;
     RECT  0.06 64.824 2.408 64.944 ;
     RECT  0.084 64.944 2.408 64.968 ;
     RECT  0.06 64.968 2.408 65.088 ;
     RECT  0.084 65.088 2.408 65.112 ;
     RECT  0.06 65.112 2.408 65.232 ;
     RECT  0.084 65.232 2.408 65.256 ;
     RECT  0.06 65.256 2.408 65.376 ;
     RECT  0.084 65.376 2.408 65.4 ;
     RECT  0.06 65.4 2.408 65.52 ;
     RECT  0.084 65.52 2.408 65.544 ;
     RECT  0.06 65.544 2.408 65.664 ;
     RECT  0.084 65.664 2.408 65.688 ;
     RECT  0.06 65.688 2.408 65.808 ;
     RECT  0.084 65.808 2.408 65.832 ;
     RECT  0.06 65.832 2.408 65.952 ;
     RECT  0.084 65.952 2.408 65.976 ;
     RECT  0.06 65.976 2.408 66.096 ;
     RECT  0.084 66.096 2.408 66.12 ;
     RECT  0.06 66.12 2.408 66.24 ;
     RECT  0.084 66.24 2.408 66.264 ;
     RECT  0.06 66.264 2.408 66.384 ;
     RECT  0.084 66.384 2.408 66.408 ;
     RECT  0.06 66.408 2.408 66.528 ;
     RECT  0.084 66.528 2.408 66.552 ;
     RECT  0.06 66.552 2.408 66.672 ;
     RECT  0.084 66.672 2.408 66.696 ;
     RECT  0.06 66.696 2.408 66.816 ;
     RECT  0.084 66.816 2.408 66.84 ;
     RECT  0.06 66.84 2.408 66.96 ;
     RECT  0.084 66.96 2.408 66.984 ;
     RECT  0.06 66.984 2.408 67.104 ;
     RECT  0.084 67.104 2.408 67.128 ;
     RECT  0.06 67.128 2.408 67.248 ;
     RECT  0.084 67.248 2.408 67.272 ;
     RECT  0.06 67.272 2.408 67.392 ;
     RECT  0.084 67.392 2.408 67.416 ;
     RECT  0.06 67.416 2.408 67.536 ;
     RECT  0.084 67.536 2.408 67.56 ;
     RECT  0.06 67.56 2.408 67.68 ;
     RECT  0.084 67.68 2.408 67.704 ;
     RECT  0.06 67.704 2.408 67.824 ;
     RECT  0.084 67.824 2.408 67.848 ;
     RECT  0.06 67.848 2.408 67.968 ;
     RECT  0.084 67.968 2.408 67.992 ;
     RECT  0.06 67.992 2.408 68.112 ;
     RECT  0.084 68.112 2.408 68.136 ;
     RECT  0.06 68.136 2.408 68.256 ;
     RECT  0.084 68.256 2.408 68.28 ;
     RECT  0.06 68.28 2.408 68.4 ;
     RECT  0.084 68.4 2.408 68.424 ;
     RECT  0.06 68.424 2.408 68.544 ;
     RECT  0.084 68.544 2.408 68.568 ;
     RECT  0.06 68.568 2.408 68.688 ;
     RECT  0.084 68.688 2.408 68.712 ;
     RECT  0.06 68.712 2.408 68.832 ;
     RECT  0.084 68.832 2.408 68.856 ;
     RECT  0.06 68.856 2.408 68.976 ;
     RECT  0.084 68.976 2.408 69 ;
     RECT  0.06 69 2.408 69.12 ;
     RECT  0.084 69.12 2.408 69.144 ;
     RECT  0.06 69.144 2.408 69.264 ;
     RECT  0.084 69.264 2.408 69.288 ;
     RECT  0.06 69.288 2.408 69.408 ;
     RECT  0.084 69.408 2.408 69.432 ;
     RECT  0.06 69.432 2.408 69.552 ;
     RECT  0.084 69.552 2.408 69.576 ;
     RECT  0.06 69.576 2.408 69.696 ;
     RECT  0.084 69.696 2.408 69.72 ;
     RECT  0.06 69.72 2.408 69.84 ;
     RECT  0.084 69.84 2.408 69.864 ;
     RECT  0.06 69.864 2.408 69.984 ;
     RECT  0.084 69.984 2.408 70.008 ;
     RECT  0.06 70.008 2.408 70.128 ;
     RECT  0.084 70.128 2.408 70.152 ;
     RECT  0.06 70.152 2.408 70.272 ;
     RECT  0.084 70.272 2.408 70.296 ;
     RECT  0.06 70.296 2.408 70.416 ;
     RECT  0.084 70.416 2.408 70.44 ;
     RECT  0.06 70.44 2.408 70.56 ;
     RECT  0.084 70.56 2.408 70.584 ;
     RECT  0.06 70.584 2.408 70.704 ;
     RECT  0.084 70.704 2.408 70.728 ;
     RECT  0.06 70.728 2.408 70.848 ;
     RECT  0.084 70.848 2.408 70.872 ;
     RECT  0.06 70.872 2.408 70.992 ;
     RECT  0.084 70.992 2.408 71.016 ;
     RECT  0.06 71.016 2.408 71.136 ;
     RECT  0.084 71.136 2.408 71.16 ;
     RECT  0.06 71.16 2.408 71.28 ;
     RECT  0.084 71.28 2.408 71.304 ;
     RECT  0.06 71.304 2.408 71.424 ;
     RECT  0.084 71.424 2.408 71.448 ;
     RECT  0.06 71.448 2.408 71.568 ;
     RECT  0.084 71.568 2.408 71.592 ;
     RECT  0.06 71.592 2.408 71.712 ;
     RECT  0.084 71.712 2.408 71.736 ;
     RECT  0.06 71.736 2.408 71.856 ;
     RECT  0.084 71.856 2.408 71.88 ;
     RECT  0.06 71.88 2.408 72 ;
     RECT  0.084 72 2.408 72.024 ;
     RECT  0.06 72.024 2.408 72.144 ;
     RECT  0.084 72.144 2.408 72.168 ;
     RECT  0.06 72.168 2.408 72.288 ;
     RECT  0.084 72.288 2.408 72.312 ;
     RECT  0.06 72.312 2.408 72.432 ;
     RECT  0.084 72.432 2.408 72.456 ;
     RECT  0.06 72.456 2.408 72.576 ;
     RECT  0.084 72.576 2.408 72.6 ;
     RECT  0.06 72.6 2.408 72.72 ;
     RECT  0.084 72.72 2.408 72.744 ;
     RECT  0.06 72.744 2.408 72.864 ;
     RECT  0.084 72.864 2.408 72.888 ;
     RECT  0.06 72.888 2.408 73.008 ;
     RECT  0.084 73.008 2.408 73.032 ;
     RECT  0.06 73.032 2.408 73.152 ;
     RECT  0.084 73.152 2.408 73.176 ;
     RECT  0.06 73.176 2.408 73.296 ;
     RECT  0.084 73.296 2.408 73.32 ;
     RECT  0.06 73.32 2.408 73.44 ;
     RECT  0.084 73.44 2.408 73.464 ;
     RECT  0.06 73.464 2.408 73.584 ;
     RECT  0.084 73.584 2.408 73.608 ;
     RECT  0.06 73.608 2.408 73.728 ;
     RECT  0.084 73.728 2.408 73.752 ;
     RECT  0.06 73.752 2.408 73.872 ;
     RECT  0.084 73.872 2.408 73.896 ;
     RECT  0.06 73.896 2.408 74.016 ;
     RECT  0.084 74.016 2.408 74.04 ;
     RECT  0.06 74.04 2.408 74.16 ;
     RECT  0.084 74.16 2.408 74.184 ;
     RECT  0.06 74.184 2.408 74.304 ;
     RECT  0.084 74.304 2.408 74.328 ;
     RECT  0.06 74.328 2.408 74.448 ;
     RECT  0.084 74.448 2.408 74.472 ;
     RECT  0.06 74.472 2.408 74.592 ;
     RECT  0.084 74.592 2.408 74.616 ;
     RECT  0.06 74.616 2.408 74.736 ;
     RECT  0.084 74.736 2.408 74.76 ;
     RECT  0.06 74.76 2.408 74.88 ;
     RECT  0.084 74.88 2.408 74.904 ;
     RECT  0.06 74.904 2.408 75.024 ;
     RECT  0.084 75.024 2.408 75.048 ;
     RECT  0.06 75.048 2.408 75.168 ;
     RECT  0.084 75.168 2.408 75.192 ;
     RECT  0.06 75.192 2.408 75.312 ;
     RECT  0.084 75.312 2.408 75.336 ;
     RECT  0.06 75.336 2.408 75.456 ;
     RECT  0.084 75.456 2.408 75.48 ;
     RECT  0.06 75.48 2.408 75.6 ;
     RECT  0.084 75.6 2.408 75.624 ;
     RECT  0.06 75.624 2.408 75.744 ;
     RECT  0.084 75.744 2.408 75.768 ;
     RECT  0.06 75.768 2.408 75.888 ;
     RECT  0.084 75.888 2.408 75.912 ;
     RECT  0.06 75.912 2.408 76.032 ;
     RECT  0.084 76.032 2.408 76.056 ;
     RECT  0.06 76.056 2.408 76.176 ;
     RECT  0.084 76.176 2.408 76.2 ;
     RECT  0.06 76.2 2.408 76.32 ;
     RECT  0.084 76.32 2.408 76.344 ;
     RECT  0.06 76.344 2.408 76.464 ;
     RECT  0.084 76.464 2.408 76.488 ;
     RECT  0.06 76.488 2.408 76.608 ;
     RECT  0.084 76.608 2.408 76.632 ;
     RECT  0.06 76.632 2.408 76.752 ;
     RECT  0.084 76.752 2.408 76.776 ;
     RECT  0.06 76.776 2.408 76.896 ;
     RECT  0.084 76.896 2.408 76.92 ;
     RECT  0.06 76.92 2.408 77.04 ;
     RECT  0.084 77.04 2.408 77.064 ;
     RECT  0.06 77.064 2.408 77.184 ;
     RECT  0.084 77.184 2.408 77.208 ;
     RECT  0.06 77.208 2.408 77.328 ;
     RECT  0.084 77.328 2.408 77.352 ;
     RECT  0.06 77.352 2.408 77.472 ;
     RECT  0.084 77.472 2.408 77.496 ;
     RECT  0.06 77.496 2.408 77.616 ;
     RECT  0.084 77.616 2.408 77.64 ;
     RECT  0.06 77.64 2.408 77.76 ;
     RECT  0.084 77.76 2.408 77.784 ;
     RECT  0.06 77.784 2.408 77.904 ;
     RECT  0.084 77.904 2.408 77.928 ;
     RECT  0.06 77.928 2.408 78.048 ;
     RECT  0.084 78.048 2.408 78.072 ;
     RECT  0.06 78.072 2.408 78.192 ;
     RECT  0.084 78.192 2.408 78.216 ;
     RECT  0.06 78.216 2.408 78.336 ;
     RECT  0.084 78.336 2.408 78.36 ;
     RECT  0.06 78.36 2.408 78.48 ;
     RECT  0.084 78.48 2.408 78.504 ;
     RECT  0.06 78.504 2.408 78.624 ;
     RECT  0.084 78.624 2.408 78.648 ;
     RECT  0.06 78.648 2.408 78.768 ;
     RECT  0.084 78.768 2.408 78.792 ;
     RECT  0.06 78.792 2.408 78.912 ;
     RECT  0.084 78.912 2.408 78.936 ;
     RECT  0.06 78.936 2.408 79.056 ;
     RECT  0.084 79.056 2.408 79.08 ;
     RECT  0.06 79.08 2.408 79.2 ;
     RECT  0.084 79.2 2.408 79.224 ;
     RECT  0.06 79.224 2.408 79.344 ;
     RECT  0.084 79.344 2.408 79.368 ;
     RECT  0.06 79.368 2.408 79.488 ;
     RECT  0.084 79.488 2.408 79.512 ;
     RECT  0.06 79.512 2.408 79.632 ;
     RECT  0.084 79.632 2.408 79.656 ;
     RECT  0.06 79.656 2.408 79.776 ;
     RECT  0.084 79.776 2.408 79.8 ;
     RECT  0.06 79.8 2.408 79.92 ;
     RECT  0.084 79.92 2.408 79.944 ;
     RECT  0.06 79.944 2.408 80.064 ;
     RECT  0.084 80.064 2.408 80.088 ;
     RECT  0.06 80.088 2.408 80.208 ;
     RECT  0.084 80.208 2.408 80.232 ;
     RECT  0.06 80.232 2.408 80.352 ;
     RECT  0.084 80.352 2.408 80.376 ;
     RECT  0.06 80.376 2.408 80.496 ;
     RECT  0.084 80.496 2.408 80.52 ;
     RECT  0.06 80.52 2.408 80.64 ;
     RECT  0.084 80.64 2.408 80.664 ;
     RECT  0.06 80.664 2.408 80.784 ;
     RECT  0.084 80.784 2.408 80.808 ;
     RECT  0.06 80.808 2.408 80.928 ;
     RECT  0.084 80.928 2.408 80.952 ;
     RECT  0.06 80.952 2.408 81.072 ;
     RECT  0.084 81.072 2.408 81.096 ;
     RECT  0.06 81.096 2.408 81.216 ;
     RECT  0.084 81.216 2.408 81.24 ;
     RECT  2.408 2.148 2.512 81.24 ;
     RECT  2.512 2.418 2.704 81.24 ;
     RECT  2.704 24.912 2.837 52.44 ;
     RECT  2.704 53.76 3.305 81.24 ;
     RECT  2.837 25.152 3.34 52.44 ;
     RECT  3.34 39.744 3.347 52.44 ;
     RECT  3.305 53.76 3.388 76.536 ;
     RECT  3.347 39.744 4.025 52.248 ;
     RECT  3.305 77.808 4.525 81.24 ;
     RECT  3.388 54.048 4.921 76.536 ;
     RECT  4.025 47.664 4.957 52.248 ;
     RECT  2.704 3.168 5.108 23.64 ;
     RECT  3.34 25.152 5.108 38.568 ;
     RECT  4.025 39.744 5.108 46.584 ;
     RECT  4.957 47.664 5.108 52.728 ;
     RECT  4.921 53.856 5.108 76.536 ;
     RECT  4.525 77.52 5.108 81.24 ;
     RECT  5.108 2.148 5.212 81.24 ;
     RECT  5.212 2.418 5.404 81.24 ;
     RECT  5.404 62.784 5.465 63.816 ;
     RECT  5.404 7.872 5.501 9.816 ;
     RECT  5.404 65.52 5.501 68.952 ;
     RECT  5.404 6.336 5.537 6.84 ;
     RECT  5.404 47.712 5.555 50.184 ;
     RECT  5.404 27.36 5.573 32.856 ;
     RECT  5.555 50.16 5.573 50.184 ;
     RECT  5.404 77.664 5.573 81.24 ;
     RECT  5.404 4.128 5.609 5.304 ;
     RECT  5.404 11.952 5.609 19.608 ;
     RECT  5.404 57.024 5.609 57.048 ;
     RECT  5.404 58.416 5.609 60.936 ;
     RECT  5.537 6.816 5.645 6.84 ;
     RECT  5.404 21.12 5.645 23.88 ;
     RECT  5.465 63.36 5.645 63.384 ;
     RECT  5.573 27.36 5.681 31.128 ;
     RECT  5.573 32.16 5.681 32.856 ;
     RECT  5.404 34.08 5.681 36.6 ;
     RECT  5.681 32.16 5.699 32.472 ;
     RECT  5.681 34.368 5.699 36.6 ;
     RECT  5.609 16.272 5.717 19.608 ;
     RECT  5.404 70.272 5.717 74.328 ;
     RECT  5.573 77.904 5.717 81.24 ;
     RECT  5.717 18 5.747 19.224 ;
     RECT  5.645 21.12 5.747 22.488 ;
     RECT  5.404 53.856 5.747 55.8 ;
     RECT  5.404 75.408 5.747 76.44 ;
     RECT  5.717 72 5.753 74.328 ;
     RECT  5.747 76.416 5.788 76.44 ;
     RECT  5.404 10.8 5.789 10.824 ;
     RECT  5.681 27.36 5.789 30.984 ;
     RECT  5.699 34.368 5.789 36.504 ;
     RECT  5.404 38.688 5.789 42.744 ;
     RECT  5.404 44.976 5.789 45.528 ;
     RECT  5.404 51.168 5.789 52.824 ;
     RECT  5.501 65.52 5.789 68.664 ;
     RECT  5.753 74.064 5.789 74.328 ;
     RECT  5.404 24.864 5.825 26.232 ;
     RECT  5.789 27.36 5.825 29.064 ;
     RECT  5.789 30.96 5.825 30.984 ;
     RECT  5.825 24.96 5.843 26.232 ;
     RECT  5.609 58.416 5.843 60.648 ;
     RECT  5.753 72 5.861 72.936 ;
     RECT  5.609 4.128 5.939 5.064 ;
     RECT  5.747 19.2 6.005 19.224 ;
     RECT  5.645 23.616 6.005 23.88 ;
     RECT  5.843 25.68 6.005 26.232 ;
     RECT  5.825 27.6 6.005 29.064 ;
     RECT  5.747 53.952 6.005 54.936 ;
     RECT  5.555 47.712 6.083 49.176 ;
     RECT  5.699 32.4 6.149 32.472 ;
     RECT  6.005 54.912 6.221 54.936 ;
     RECT  5.609 11.952 6.227 15 ;
     RECT  5.747 21.12 6.227 21.144 ;
     RECT  5.747 75.408 6.275 75.432 ;
     RECT  5.789 35.328 6.293 36.504 ;
     RECT  5.789 65.664 6.293 68.664 ;
     RECT  6.227 11.952 6.397 13.848 ;
     RECT  5.789 40.032 6.473 42.744 ;
     RECT  5.939 4.128 6.505 4.152 ;
     RECT  5.404 46.56 6.689 46.68 ;
     RECT  6.083 48.192 6.689 49.176 ;
     RECT  6.473 40.608 6.721 42.744 ;
     RECT  6.689 49.008 6.761 49.176 ;
     RECT  5.717 16.272 6.829 16.824 ;
     RECT  5.747 18 6.829 18.024 ;
     RECT  6.005 27.6 6.829 28.344 ;
     RECT  5.789 51.744 6.829 52.824 ;
     RECT  5.717 81.216 6.833 81.24 ;
     RECT  5.843 58.656 6.865 60.648 ;
     RECT  6.149 32.448 6.901 32.472 ;
     RECT  6.829 34.32 6.901 34.344 ;
     RECT  6.649 38.112 6.901 38.136 ;
     RECT  6.901 32.448 6.929 32.568 ;
     RECT  6.901 34.128 6.929 34.344 ;
     RECT  6.829 62.544 6.937 62.568 ;
     RECT  5.717 78.624 6.937 79.704 ;
     RECT  6.829 51.552 6.973 53.016 ;
     RECT  5.717 70.656 7.004 70.68 ;
     RECT  5.501 7.872 7.045 9.768 ;
     RECT  6.397 11.136 7.045 13.848 ;
     RECT  5.789 44.976 7.045 45 ;
     RECT  6.937 78.096 7.045 79.704 ;
     RECT  6.865 6.384 7.117 6.408 ;
     RECT  6.721 40.608 7.148 43.224 ;
     RECT  5.861 72 7.225 72.84 ;
     RECT  6.973 50.784 7.333 53.016 ;
     RECT  6.227 14.976 7.369 15 ;
     RECT  6.829 16.272 7.369 18.024 ;
     RECT  6.865 56.064 7.369 56.088 ;
     RECT  7.045 7.872 7.429 13.848 ;
     RECT  7.369 14.976 7.429 18.024 ;
     RECT  7.333 50.784 7.477 53.4 ;
     RECT  6.293 65.664 7.477 65.688 ;
     RECT  6.293 66.72 7.477 68.664 ;
     RECT  7.004 70.656 7.58 70.968 ;
     RECT  7.225 72 7.58 72.936 ;
     RECT  7.58 70.656 7.621 72.936 ;
     RECT  7.429 7.872 7.765 18.024 ;
     RECT  6.505 4.032 7.808 4.152 ;
     RECT  7.117 5.568 7.808 6.408 ;
     RECT  7.765 7.872 7.808 18.744 ;
     RECT  7.585 20.256 7.808 20.28 ;
     RECT  5.747 22.464 7.808 22.488 ;
     RECT  6.005 23.616 7.808 23.64 ;
     RECT  6.005 25.68 7.808 25.8 ;
     RECT  6.829 27.408 7.808 28.344 ;
     RECT  7.292 29.376 7.808 29.4 ;
     RECT  7.333 30.576 7.808 30.6 ;
     RECT  6.929 32.448 7.808 34.344 ;
     RECT  6.293 35.328 7.808 36.456 ;
     RECT  6.901 38.112 7.808 39.048 ;
     RECT  7.148 40.608 7.808 43.56 ;
     RECT  7.045 44.64 7.808 45 ;
     RECT  6.689 46.656 7.808 46.68 ;
     RECT  6.761 49.008 7.808 49.032 ;
     RECT  7.477 50.784 7.808 53.544 ;
     RECT  7.369 55.44 7.808 56.088 ;
     RECT  6.865 58.656 7.808 61.224 ;
     RECT  6.937 62.256 7.808 62.568 ;
     RECT  6.721 64.416 7.808 64.44 ;
     RECT  7.477 65.664 7.808 68.664 ;
     RECT  7.621 69.984 7.808 72.936 ;
     RECT  5.789 74.304 7.808 74.328 ;
     RECT  6.829 75.936 7.808 75.96 ;
     RECT  7.045 77.28 7.808 79.704 ;
     RECT  7.808 2.148 7.912 79.932 ;
     RECT  7.912 2.418 8.104 79.662 ;
     RECT  8.104 11.136 8.165 11.736 ;
     RECT  8.104 62.544 8.165 62.664 ;
     RECT  8.104 76.368 8.165 77.304 ;
     RECT  8.104 25.776 8.237 25.8 ;
     RECT  8.104 51.888 8.237 53.544 ;
     RECT  8.104 55.44 8.243 55.992 ;
     RECT  8.104 18 8.245 18.6 ;
     RECT  8.104 5.568 8.273 5.592 ;
     RECT  8.104 27.36 8.291 27.384 ;
     RECT  8.237 51.888 8.291 53.4 ;
     RECT  8.104 69.984 8.291 70.008 ;
     RECT  8.104 66.672 8.345 66.696 ;
     RECT  8.104 68.928 8.345 68.952 ;
     RECT  8.165 76.368 8.353 76.392 ;
     RECT  8.104 28.848 8.381 28.872 ;
     RECT  8.104 43.728 8.381 44.664 ;
     RECT  8.165 62.64 8.453 62.664 ;
     RECT  8.104 78.624 8.453 78.936 ;
     RECT  8.381 43.728 8.489 43.752 ;
     RECT  8.453 78.624 8.561 78.744 ;
     RECT  8.104 65.568 8.569 65.592 ;
     RECT  8.291 52.032 8.597 53.4 ;
     RECT  8.104 13.632 8.633 13.656 ;
     RECT  8.561 78.624 8.633 78.648 ;
     RECT  8.104 60.384 8.813 60.936 ;
     RECT  8.104 38.976 8.849 39.432 ;
     RECT  8.104 50.736 8.849 50.76 ;
     RECT  8.104 56.976 8.849 57 ;
     RECT  8.104 45.696 9.065 45.72 ;
     RECT  8.597 52.704 9.173 53.4 ;
     RECT  8.104 30.576 9.385 30.6 ;
     RECT  9.349 14.496 9.436 14.52 ;
     RECT  8.813 60.384 9.457 60.408 ;
     RECT  9.173 52.704 9.533 53.304 ;
     RECT  9.533 52.704 9.565 53.016 ;
     RECT  9.385 29.808 9.637 30.6 ;
     RECT  8.849 38.976 9.961 39.384 ;
     RECT  8.104 40.512 9.961 40.632 ;
     RECT  9.637 29.808 10.069 30.936 ;
     RECT  10.033 33.072 10.141 33.096 ;
     RECT  10.076 6.24 10.508 6.264 ;
     RECT  8.165 11.136 10.508 11.16 ;
     RECT  10.465 13.632 10.508 13.656 ;
     RECT  8.104 16.8 10.508 16.824 ;
     RECT  8.245 18 10.508 18.024 ;
     RECT  10.069 29.808 10.508 30.984 ;
     RECT  10.141 33.072 10.508 33.336 ;
     RECT  9.493 34.464 10.508 34.488 ;
     RECT  9.961 38.976 10.508 40.632 ;
     RECT  10.465 41.712 10.508 41.736 ;
     RECT  9.349 45.024 10.508 45.048 ;
     RECT  9.565 52.176 10.508 53.016 ;
     RECT  8.243 55.44 10.508 55.464 ;
     RECT  9.457 59.76 10.508 60.408 ;
     RECT  10.465 62.208 10.508 62.232 ;
     RECT  10.465 63.792 10.508 63.816 ;
     RECT  10.508 2.148 10.612 79.932 ;
     RECT  10.612 2.418 10.804 79.662 ;
     RECT  10.804 52.176 10.829 52.296 ;
     RECT  10.829 52.176 11.117 52.2 ;
     RECT  10.804 38.784 11.153 41.64 ;
     RECT  11.153 39.744 11.225 41.64 ;
     RECT  10.804 4.704 11.795 4.728 ;
     RECT  11.977 53.568 12.085 53.592 ;
     RECT  11.225 39.744 12.265 40.632 ;
     RECT  10.804 59.76 12.733 59.784 ;
     RECT  10.804 77.328 12.757 77.352 ;
     RECT  10.804 11.136 13.208 11.16 ;
     RECT  10.804 13.632 13.208 13.656 ;
     RECT  10.804 16.8 13.208 16.824 ;
     RECT  10.804 18 13.208 18.024 ;
     RECT  10.804 20.112 13.208 20.136 ;
     RECT  10.804 25.488 13.208 25.512 ;
     RECT  12.265 26.784 13.208 26.808 ;
     RECT  10.804 29.808 13.208 30.984 ;
     RECT  10.804 33.408 13.208 33.432 ;
     RECT  12.121 34.752 13.208 34.776 ;
     RECT  12.265 38.832 13.208 40.632 ;
     RECT  11.225 41.616 13.208 41.64 ;
     RECT  12.085 43.344 13.208 43.368 ;
     RECT  12.265 46.704 13.208 46.728 ;
     RECT  12.733 50.112 13.208 50.136 ;
     RECT  12.085 52.992 13.208 53.592 ;
     RECT  10.804 55.44 13.208 55.464 ;
     RECT  12.733 59.76 13.208 60.072 ;
     RECT  10.804 62.208 13.208 62.232 ;
     RECT  11.941 67.68 13.208 67.704 ;
     RECT  12.757 77.28 13.208 77.352 ;
     RECT  13.208 2.148 13.312 79.932 ;
     RECT  13.312 2.148 13.345 79.662 ;
     RECT  13.345 1.584 13.504 79.662 ;
     RECT  13.504 48.96 13.565 48.984 ;
     RECT  13.504 29.808 13.601 30.984 ;
     RECT  13.504 53.568 13.601 53.688 ;
     RECT  13.504 54.72 14.249 55.464 ;
     RECT  13.504 39.744 14.636 40.632 ;
     RECT  13.504 41.616 14.636 41.64 ;
     RECT  13.504 59.76 14.641 60.072 ;
     RECT  13.504 32.064 14.677 32.088 ;
     RECT  13.504 34.752 14.717 34.776 ;
     RECT  14.677 31.968 14.749 32.088 ;
     RECT  13.504 33.408 14.749 33.432 ;
     RECT  14.636 39.744 14.761 41.64 ;
     RECT  5.557 0.048 14.821 0.072 ;
     RECT  13.504 20.016 14.821 20.04 ;
     RECT  13.601 29.904 14.821 30.984 ;
     RECT  14.749 31.968 14.821 33.432 ;
     RECT  13.504 37.296 14.821 37.32 ;
     RECT  14.761 41.616 14.821 41.64 ;
     RECT  13.601 53.664 14.821 53.688 ;
     RECT  13.504 62.208 14.857 62.232 ;
     RECT  13.504 63.216 14.857 63.24 ;
     RECT  14.821 0.048 14.861 0.168 ;
     RECT  13.504 13.632 14.861 13.992 ;
     RECT  14.821 20.016 14.861 20.136 ;
     RECT  14.821 29.904 14.861 33.432 ;
     RECT  14.821 37.296 14.861 37.416 ;
     RECT  14.821 41.616 14.861 41.736 ;
     RECT  14.821 53.328 14.861 53.688 ;
     RECT  14.857 62.208 14.897 63.24 ;
     RECT  14.861 29.904 15.037 33.336 ;
     RECT  14.861 0.144 15.041 0.168 ;
     RECT  14.861 41.712 15.145 41.736 ;
     RECT  13.504 46.8 15.181 46.824 ;
     RECT  14.641 59.184 15.217 60.072 ;
     RECT  14.861 37.392 15.433 37.416 ;
     RECT  15.145 41.712 15.433 42.216 ;
     RECT  13.504 43.344 15.433 43.944 ;
     RECT  15.469 79.248 15.637 79.272 ;
     RECT  13.504 11.136 15.649 11.16 ;
     RECT  13.504 25.488 15.721 26.088 ;
     RECT  15.325 27.072 15.721 27.096 ;
     RECT  15.637 78.48 15.865 79.272 ;
     RECT  13.504 1.584 15.908 1.608 ;
     RECT  15.649 11.136 15.908 11.976 ;
     RECT  14.861 13.632 15.908 13.896 ;
     RECT  13.504 18 15.908 18.024 ;
     RECT  14.861 20.112 15.908 20.136 ;
     RECT  14.893 24.48 15.908 24.504 ;
     RECT  15.721 25.488 15.908 27.096 ;
     RECT  15.037 29.76 15.908 33.336 ;
     RECT  15.433 37.392 15.908 37.896 ;
     RECT  14.761 39.744 15.908 40.632 ;
     RECT  15.433 41.712 15.908 43.944 ;
     RECT  15.181 46.8 15.908 46.872 ;
     RECT  13.504 50.112 15.908 50.136 ;
     RECT  14.861 53.328 15.908 53.592 ;
     RECT  14.249 55.44 15.908 55.464 ;
     RECT  15.217 59.184 15.908 60.936 ;
     RECT  14.897 62.208 15.908 63.096 ;
     RECT  13.504 67.68 15.908 67.704 ;
     RECT  13.504 70.848 15.908 70.872 ;
     RECT  14.641 72.432 15.908 72.456 ;
     RECT  13.504 76.464 15.908 77.352 ;
     RECT  15.865 78.48 15.908 80.088 ;
     RECT  15.908 1.584 16.019 80.088 ;
     RECT  16.019 1.584 16.204 79.662 ;
     RECT  16.117 80.928 16.445 80.952 ;
     RECT  16.204 58.704 16.805 60.936 ;
     RECT  16.204 67.584 17.197 67.704 ;
     RECT  16.204 24.48 17.233 24.504 ;
     RECT  16.204 25.488 17.233 27.096 ;
     RECT  17.197 66.816 17.269 67.704 ;
     RECT  16.204 39.744 17.305 44.376 ;
     RECT  16.204 20.112 17.341 21.432 ;
     RECT  16.204 76.032 17.413 77.352 ;
     RECT  17.305 39.744 17.453 45.048 ;
     RECT  16.204 74.304 17.557 74.904 ;
     RECT  16.204 46.8 17.629 47.976 ;
     RECT  16.204 49.584 17.629 50.136 ;
     RECT  16.805 59.184 17.629 60.936 ;
     RECT  16.204 62.208 17.629 64.104 ;
     RECT  16.204 29.76 17.665 33.336 ;
     RECT  16.204 34.704 17.665 34.728 ;
     RECT  16.204 36 17.665 36.024 ;
     RECT  17.629 46.8 17.665 50.136 ;
     RECT  17.629 51.408 17.665 51.432 ;
     RECT  16.204 52.704 17.665 53.592 ;
     RECT  16.204 68.976 17.665 69.336 ;
     RECT  16.204 70.368 17.665 70.872 ;
     RECT  16.204 72 17.665 72.456 ;
     RECT  17.341 20.112 17.737 22.008 ;
     RECT  16.204 37.392 17.881 38.76 ;
     RECT  17.453 39.744 17.881 44.376 ;
     RECT  17.269 66.816 17.917 67.896 ;
     RECT  17.665 68.976 17.917 72.456 ;
     RECT  17.737 20.112 18.025 22.344 ;
     RECT  17.233 24.48 18.097 27.096 ;
     RECT  17.917 66.816 18.133 72.456 ;
     RECT  16.204 8.208 18.205 11.976 ;
     RECT  16.204 17.952 18.205 18.024 ;
     RECT  17.665 29.76 18.205 33.576 ;
     RECT  17.665 34.704 18.205 36.024 ;
     RECT  17.629 59.184 18.205 64.104 ;
     RECT  17.665 45.744 18.241 45.768 ;
     RECT  17.665 46.8 18.241 54.216 ;
     RECT  16.204 55.44 18.241 55.992 ;
     RECT  18.205 58.752 18.241 64.104 ;
     RECT  17.413 75.984 18.241 77.352 ;
     RECT  18.241 55.44 18.277 56.04 ;
     RECT  16.204 1.584 18.313 1.608 ;
     RECT  16.204 13.632 18.421 15.288 ;
     RECT  18.205 29.76 18.421 36.024 ;
     RECT  18.133 66.576 18.457 72.456 ;
     RECT  17.341 4.656 18.493 4.68 ;
     RECT  18.061 3.6 18.529 3.624 ;
     RECT  18.493 4.656 18.529 4.776 ;
     RECT  18.421 13.632 18.565 15.576 ;
     RECT  17.557 73.632 18.565 74.904 ;
     RECT  18.241 75.984 18.565 77.64 ;
     RECT  18.313 1.296 18.608 1.608 ;
     RECT  18.529 3.6 18.608 4.776 ;
     RECT  17.629 6.336 18.608 6.36 ;
     RECT  18.205 7.632 18.608 11.976 ;
     RECT  18.565 13.632 18.608 15.864 ;
     RECT  18.205 17.424 18.608 18.024 ;
     RECT  18.025 19.584 18.608 22.344 ;
     RECT  18.097 23.616 18.608 27.096 ;
     RECT  18.421 29.76 18.608 36.36 ;
     RECT  17.881 37.392 18.608 44.376 ;
     RECT  18.241 45.744 18.608 54.216 ;
     RECT  18.277 55.44 18.608 56.616 ;
     RECT  18.241 58.752 18.608 64.392 ;
     RECT  18.457 66.576 18.608 72.504 ;
     RECT  18.565 73.632 18.608 77.64 ;
     RECT  16.204 78.624 18.608 78.648 ;
     RECT  18.608 1.296 18.712 79.932 ;
     RECT  18.712 1.296 18.904 79.662 ;
     RECT  18.904 1.296 19.897 27.96 ;
     RECT  18.904 58.32 19.897 64.392 ;
     RECT  18.904 65.52 19.897 78.648 ;
     RECT  19.897 0.72 19.933 27.96 ;
     RECT  19.897 58.32 20.509 78.648 ;
     RECT  18.904 29.76 20.977 57.048 ;
     RECT  19.933 0.72 21.481 28.104 ;
     RECT  21.481 0.72 21.516 0.744 ;
     RECT  21.481 0.744 21.564 0.864 ;
     RECT  21.481 0.864 21.516 0.888 ;
     RECT  21.481 0.888 21.564 1.008 ;
     RECT  21.481 1.008 21.516 1.032 ;
     RECT  21.481 1.032 21.564 1.152 ;
     RECT  21.481 1.152 21.516 1.176 ;
     RECT  21.481 1.176 21.564 1.296 ;
     RECT  21.481 1.296 21.516 1.32 ;
     RECT  21.481 1.32 21.564 1.44 ;
     RECT  21.481 1.44 21.516 1.464 ;
     RECT  21.481 1.464 21.564 1.584 ;
     RECT  21.481 1.584 21.516 1.608 ;
     RECT  21.481 1.608 21.564 1.728 ;
     RECT  21.481 1.728 21.516 1.752 ;
     RECT  21.481 1.752 21.564 1.872 ;
     RECT  21.481 1.872 21.516 1.896 ;
     RECT  21.481 1.896 21.564 2.016 ;
     RECT  21.481 2.016 21.516 2.04 ;
     RECT  21.481 2.04 21.564 2.16 ;
     RECT  21.481 2.16 21.516 2.184 ;
     RECT  21.481 2.184 21.564 2.304 ;
     RECT  21.481 2.304 21.516 2.328 ;
     RECT  21.481 2.328 21.564 2.448 ;
     RECT  21.481 2.448 21.516 2.472 ;
     RECT  21.481 2.472 21.564 2.592 ;
     RECT  21.481 2.592 21.516 2.616 ;
     RECT  21.481 2.616 21.564 2.736 ;
     RECT  21.481 2.736 21.516 2.76 ;
     RECT  21.481 2.76 21.564 2.88 ;
     RECT  21.481 2.88 21.516 2.904 ;
     RECT  21.481 2.904 21.564 3.024 ;
     RECT  21.481 3.024 21.516 3.048 ;
     RECT  21.481 3.048 21.564 3.168 ;
     RECT  21.481 3.168 21.516 3.192 ;
     RECT  21.481 3.192 21.564 3.312 ;
     RECT  21.481 3.312 21.516 3.336 ;
     RECT  21.481 3.336 21.564 3.456 ;
     RECT  21.481 3.456 21.516 3.48 ;
     RECT  21.481 3.48 21.564 3.6 ;
     RECT  21.481 3.6 21.516 3.624 ;
     RECT  21.481 3.624 21.564 3.744 ;
     RECT  21.481 3.744 21.516 3.768 ;
     RECT  21.481 3.768 21.564 3.888 ;
     RECT  21.481 3.888 21.516 3.912 ;
     RECT  21.481 3.912 21.564 4.032 ;
     RECT  21.481 4.032 21.516 4.056 ;
     RECT  21.481 4.056 21.564 4.176 ;
     RECT  21.481 4.176 21.516 4.2 ;
     RECT  21.481 4.2 21.564 4.32 ;
     RECT  21.481 4.32 21.516 4.344 ;
     RECT  21.481 4.344 21.564 4.464 ;
     RECT  21.481 4.464 21.516 4.488 ;
     RECT  21.481 4.488 21.564 4.608 ;
     RECT  21.481 4.608 21.516 4.632 ;
     RECT  21.481 4.632 21.564 4.752 ;
     RECT  21.481 4.752 21.516 4.776 ;
     RECT  21.481 4.776 21.564 4.896 ;
     RECT  21.481 4.896 21.516 4.92 ;
     RECT  21.481 4.92 21.564 5.04 ;
     RECT  21.481 5.04 21.516 5.064 ;
     RECT  21.481 5.064 21.564 5.184 ;
     RECT  21.481 5.184 21.516 5.208 ;
     RECT  21.481 5.208 21.564 5.328 ;
     RECT  21.481 5.328 21.516 5.352 ;
     RECT  21.481 5.352 21.564 5.472 ;
     RECT  21.481 5.472 21.516 5.496 ;
     RECT  21.481 5.496 21.564 5.616 ;
     RECT  21.481 5.616 21.516 5.64 ;
     RECT  21.481 5.64 21.564 5.76 ;
     RECT  21.481 5.76 21.516 5.784 ;
     RECT  21.481 5.784 21.564 5.904 ;
     RECT  21.481 5.904 21.516 5.928 ;
     RECT  21.481 5.928 21.564 6.048 ;
     RECT  21.481 6.048 21.516 6.072 ;
     RECT  21.481 6.072 21.564 6.192 ;
     RECT  21.481 6.192 21.516 6.216 ;
     RECT  21.481 6.216 21.564 6.336 ;
     RECT  21.481 6.336 21.516 6.36 ;
     RECT  21.481 6.36 21.564 6.48 ;
     RECT  21.481 6.48 21.516 6.504 ;
     RECT  21.481 6.504 21.564 6.624 ;
     RECT  21.481 6.624 21.516 6.648 ;
     RECT  21.481 6.648 21.564 6.768 ;
     RECT  21.481 6.768 21.516 6.792 ;
     RECT  21.481 6.792 21.564 6.912 ;
     RECT  21.481 6.912 21.516 6.936 ;
     RECT  21.481 6.936 21.564 7.056 ;
     RECT  21.481 7.056 21.516 7.08 ;
     RECT  21.481 7.08 21.564 7.2 ;
     RECT  21.481 7.2 21.516 7.224 ;
     RECT  21.481 7.224 21.564 7.344 ;
     RECT  21.481 7.344 21.516 7.368 ;
     RECT  21.481 7.368 21.564 7.488 ;
     RECT  21.481 7.488 21.516 7.512 ;
     RECT  21.481 7.512 21.564 7.632 ;
     RECT  21.481 7.632 21.516 7.656 ;
     RECT  21.481 7.656 21.564 7.776 ;
     RECT  21.481 7.776 21.516 7.8 ;
     RECT  21.481 7.8 21.564 7.92 ;
     RECT  21.481 7.92 21.516 7.944 ;
     RECT  21.481 7.944 21.564 8.064 ;
     RECT  21.481 8.064 21.516 8.088 ;
     RECT  21.481 8.088 21.564 8.208 ;
     RECT  21.481 8.208 21.516 8.232 ;
     RECT  21.481 8.232 21.564 8.352 ;
     RECT  21.481 8.352 21.516 8.376 ;
     RECT  21.481 8.376 21.564 8.496 ;
     RECT  21.481 8.496 21.516 8.52 ;
     RECT  21.481 8.52 21.564 8.64 ;
     RECT  21.481 8.64 21.516 8.664 ;
     RECT  21.481 8.664 21.564 8.784 ;
     RECT  21.481 8.784 21.516 8.808 ;
     RECT  21.481 8.808 21.564 8.928 ;
     RECT  21.481 8.928 21.516 8.952 ;
     RECT  21.481 8.952 21.564 9.072 ;
     RECT  21.481 9.072 21.516 9.096 ;
     RECT  21.481 9.096 21.564 9.216 ;
     RECT  21.481 9.216 21.516 9.24 ;
     RECT  21.481 9.24 21.564 9.36 ;
     RECT  21.481 9.36 21.516 9.384 ;
     RECT  21.481 9.384 21.564 9.504 ;
     RECT  21.481 9.504 21.516 9.528 ;
     RECT  21.481 9.528 21.564 9.648 ;
     RECT  21.481 9.648 21.516 9.672 ;
     RECT  21.481 9.672 21.564 9.792 ;
     RECT  21.481 9.792 21.516 9.816 ;
     RECT  21.481 9.816 21.564 9.936 ;
     RECT  21.481 9.936 21.516 9.96 ;
     RECT  21.481 9.96 21.564 10.08 ;
     RECT  21.481 10.08 21.516 10.104 ;
     RECT  21.481 10.104 21.564 10.224 ;
     RECT  21.481 10.224 21.516 10.248 ;
     RECT  21.481 10.248 21.564 10.368 ;
     RECT  21.481 10.368 21.516 10.392 ;
     RECT  21.481 10.392 21.564 10.512 ;
     RECT  21.481 10.512 21.516 10.536 ;
     RECT  21.481 10.536 21.564 10.656 ;
     RECT  21.481 10.656 21.516 10.68 ;
     RECT  21.481 10.68 21.564 10.8 ;
     RECT  21.481 10.8 21.516 10.824 ;
     RECT  21.481 10.824 21.564 10.944 ;
     RECT  21.481 10.944 21.516 10.968 ;
     RECT  21.481 10.968 21.564 11.088 ;
     RECT  21.481 11.088 21.516 11.112 ;
     RECT  21.481 11.112 21.564 11.232 ;
     RECT  21.481 11.232 21.516 11.256 ;
     RECT  21.481 11.256 21.564 11.376 ;
     RECT  21.481 11.376 21.516 11.4 ;
     RECT  21.481 11.4 21.564 11.52 ;
     RECT  21.481 11.52 21.516 11.544 ;
     RECT  21.481 11.544 21.564 11.664 ;
     RECT  21.481 11.664 21.516 11.688 ;
     RECT  21.481 11.688 21.564 11.808 ;
     RECT  21.481 11.808 21.516 11.832 ;
     RECT  21.481 11.832 21.564 11.952 ;
     RECT  21.481 11.952 21.516 11.976 ;
     RECT  21.481 11.976 21.564 12.096 ;
     RECT  21.481 12.096 21.516 12.12 ;
     RECT  21.481 12.12 21.564 12.24 ;
     RECT  21.481 12.24 21.516 12.264 ;
     RECT  21.481 12.264 21.564 12.384 ;
     RECT  21.481 12.384 21.516 12.408 ;
     RECT  21.481 12.408 21.564 12.528 ;
     RECT  21.481 12.528 21.516 12.552 ;
     RECT  21.481 12.552 21.564 12.672 ;
     RECT  21.481 12.672 21.516 12.696 ;
     RECT  21.481 12.696 21.564 12.816 ;
     RECT  21.481 12.816 21.516 12.84 ;
     RECT  21.481 12.84 21.564 12.96 ;
     RECT  21.481 12.96 21.516 12.984 ;
     RECT  21.481 12.984 21.564 13.104 ;
     RECT  21.481 13.104 21.516 13.128 ;
     RECT  21.481 13.128 21.564 13.248 ;
     RECT  21.481 13.248 21.516 13.272 ;
     RECT  21.481 13.272 21.564 13.392 ;
     RECT  21.481 13.392 21.516 13.416 ;
     RECT  21.481 13.416 21.564 13.536 ;
     RECT  21.481 13.536 21.516 13.56 ;
     RECT  21.481 13.56 21.564 13.68 ;
     RECT  21.481 13.68 21.516 13.704 ;
     RECT  21.481 13.704 21.564 13.824 ;
     RECT  21.481 13.824 21.516 13.848 ;
     RECT  21.481 13.848 21.564 13.968 ;
     RECT  21.481 13.968 21.516 13.992 ;
     RECT  21.481 13.992 21.564 14.112 ;
     RECT  21.481 14.112 21.516 14.136 ;
     RECT  21.481 14.136 21.564 14.256 ;
     RECT  21.481 14.256 21.516 14.28 ;
     RECT  21.481 14.28 21.564 14.4 ;
     RECT  21.481 14.4 21.516 14.424 ;
     RECT  21.481 14.424 21.564 14.544 ;
     RECT  21.481 14.544 21.516 14.568 ;
     RECT  21.481 14.568 21.564 14.688 ;
     RECT  21.481 14.688 21.516 14.712 ;
     RECT  21.481 14.712 21.564 14.832 ;
     RECT  21.481 14.832 21.516 14.856 ;
     RECT  21.481 14.856 21.564 14.976 ;
     RECT  21.481 14.976 21.516 15 ;
     RECT  21.481 15 21.564 15.12 ;
     RECT  21.481 15.12 21.516 15.144 ;
     RECT  21.481 15.144 21.564 15.264 ;
     RECT  21.481 15.264 21.516 15.288 ;
     RECT  21.481 15.288 21.564 15.408 ;
     RECT  21.481 15.408 21.516 15.432 ;
     RECT  21.481 15.432 21.564 15.552 ;
     RECT  21.481 15.552 21.516 15.576 ;
     RECT  21.481 15.576 21.564 15.696 ;
     RECT  21.481 15.696 21.516 15.72 ;
     RECT  21.481 15.72 21.564 15.84 ;
     RECT  21.481 15.84 21.516 15.864 ;
     RECT  21.481 15.864 21.564 15.984 ;
     RECT  21.481 15.984 21.516 16.008 ;
     RECT  21.481 16.008 21.564 16.128 ;
     RECT  21.481 16.128 21.516 16.152 ;
     RECT  21.481 16.152 21.564 16.272 ;
     RECT  21.481 16.272 21.516 16.296 ;
     RECT  21.481 16.296 21.564 16.416 ;
     RECT  21.481 16.416 21.516 16.44 ;
     RECT  21.481 16.44 21.564 16.56 ;
     RECT  21.481 16.56 21.516 16.584 ;
     RECT  21.481 16.584 21.564 16.704 ;
     RECT  21.481 16.704 21.516 16.728 ;
     RECT  21.481 16.728 21.564 16.848 ;
     RECT  21.481 16.848 21.516 16.872 ;
     RECT  21.481 16.872 21.564 16.992 ;
     RECT  21.481 16.992 21.516 17.016 ;
     RECT  21.481 17.016 21.564 17.136 ;
     RECT  21.481 17.136 21.516 17.16 ;
     RECT  21.481 17.16 21.564 17.28 ;
     RECT  21.481 17.28 21.516 17.304 ;
     RECT  21.481 17.304 21.564 17.424 ;
     RECT  21.481 17.424 21.516 17.448 ;
     RECT  21.481 17.448 21.564 17.568 ;
     RECT  21.481 17.568 21.516 17.592 ;
     RECT  21.481 17.592 21.564 17.712 ;
     RECT  21.481 17.712 21.516 17.736 ;
     RECT  21.481 17.736 21.564 17.856 ;
     RECT  21.481 17.856 21.516 17.88 ;
     RECT  21.481 17.88 21.564 18 ;
     RECT  21.481 18 21.516 18.024 ;
     RECT  21.481 18.024 21.564 18.144 ;
     RECT  21.481 18.144 21.516 18.168 ;
     RECT  21.481 18.168 21.564 18.288 ;
     RECT  21.481 18.288 21.516 18.312 ;
     RECT  21.481 18.312 21.564 18.432 ;
     RECT  21.481 18.432 21.516 18.456 ;
     RECT  21.481 18.456 21.564 18.576 ;
     RECT  21.481 18.576 21.516 18.6 ;
     RECT  21.481 18.6 21.564 18.72 ;
     RECT  21.481 18.72 21.516 18.744 ;
     RECT  21.481 18.744 21.564 18.864 ;
     RECT  21.481 18.864 21.516 18.888 ;
     RECT  21.481 18.888 21.564 19.008 ;
     RECT  21.481 19.008 21.516 19.032 ;
     RECT  21.481 19.032 21.564 19.152 ;
     RECT  21.481 19.152 21.516 19.176 ;
     RECT  21.481 19.176 21.564 19.296 ;
     RECT  21.481 19.296 21.516 19.32 ;
     RECT  21.481 19.32 21.564 19.44 ;
     RECT  21.481 19.44 21.516 19.464 ;
     RECT  21.481 19.464 21.564 19.584 ;
     RECT  21.481 19.584 21.516 19.608 ;
     RECT  21.481 19.608 21.564 19.728 ;
     RECT  21.481 19.728 21.516 19.752 ;
     RECT  21.481 19.752 21.564 19.872 ;
     RECT  21.481 19.872 21.516 19.896 ;
     RECT  21.481 19.896 21.564 20.016 ;
     RECT  21.481 20.016 21.516 20.04 ;
     RECT  21.481 20.04 21.564 20.16 ;
     RECT  21.481 20.16 21.516 20.184 ;
     RECT  21.481 20.184 21.564 20.304 ;
     RECT  21.481 20.304 21.516 20.328 ;
     RECT  21.481 20.328 21.564 20.448 ;
     RECT  21.481 20.448 21.516 20.472 ;
     RECT  21.481 20.472 21.564 20.592 ;
     RECT  21.481 20.592 21.516 20.616 ;
     RECT  21.481 20.616 21.564 20.736 ;
     RECT  21.481 20.736 21.516 20.76 ;
     RECT  21.481 20.76 21.564 20.88 ;
     RECT  21.481 20.88 21.516 20.904 ;
     RECT  21.481 20.904 21.564 21.024 ;
     RECT  21.481 21.024 21.516 21.048 ;
     RECT  21.481 21.048 21.564 21.168 ;
     RECT  21.481 21.168 21.516 21.192 ;
     RECT  21.481 21.192 21.564 21.312 ;
     RECT  21.481 21.312 21.516 21.336 ;
     RECT  21.481 21.336 21.564 21.456 ;
     RECT  21.481 21.456 21.516 21.48 ;
     RECT  21.481 21.48 21.564 21.6 ;
     RECT  21.481 21.6 21.516 21.624 ;
     RECT  21.481 21.624 21.564 21.744 ;
     RECT  21.481 21.744 21.516 21.768 ;
     RECT  21.481 21.768 21.564 21.888 ;
     RECT  21.481 21.888 21.516 21.912 ;
     RECT  21.481 21.912 21.564 22.032 ;
     RECT  21.481 22.032 21.516 22.056 ;
     RECT  21.481 22.056 21.564 22.176 ;
     RECT  21.481 22.176 21.516 22.2 ;
     RECT  21.481 22.2 21.564 22.32 ;
     RECT  21.481 22.32 21.516 22.344 ;
     RECT  21.481 22.344 21.564 22.464 ;
     RECT  21.481 22.464 21.516 22.488 ;
     RECT  21.481 22.488 21.564 22.608 ;
     RECT  21.481 22.608 21.516 22.632 ;
     RECT  21.481 22.632 21.564 22.752 ;
     RECT  21.481 22.752 21.516 22.776 ;
     RECT  21.481 22.776 21.564 22.896 ;
     RECT  21.481 22.896 21.516 22.92 ;
     RECT  21.481 22.92 21.564 23.04 ;
     RECT  21.481 23.04 21.516 23.064 ;
     RECT  21.481 23.064 21.564 23.184 ;
     RECT  21.481 23.184 21.516 23.208 ;
     RECT  21.481 23.208 21.564 23.328 ;
     RECT  21.481 23.328 21.516 23.352 ;
     RECT  21.481 23.352 21.564 23.472 ;
     RECT  21.481 23.472 21.516 23.496 ;
     RECT  21.481 23.496 21.564 23.616 ;
     RECT  21.481 23.616 21.516 23.64 ;
     RECT  21.481 23.64 21.564 23.76 ;
     RECT  21.481 23.76 21.516 23.784 ;
     RECT  21.481 23.784 21.564 23.904 ;
     RECT  21.481 23.904 21.516 23.928 ;
     RECT  21.481 23.928 21.564 24.048 ;
     RECT  21.481 24.048 21.516 24.072 ;
     RECT  21.481 24.072 21.564 24.192 ;
     RECT  21.481 24.192 21.516 24.216 ;
     RECT  21.481 24.216 21.564 24.336 ;
     RECT  21.481 24.336 21.516 24.36 ;
     RECT  21.481 24.36 21.564 24.48 ;
     RECT  21.481 24.48 21.516 24.504 ;
     RECT  21.481 24.504 21.564 24.624 ;
     RECT  21.481 24.624 21.516 24.648 ;
     RECT  21.481 24.648 21.564 24.768 ;
     RECT  21.481 24.768 21.516 24.792 ;
     RECT  21.481 24.792 21.564 24.912 ;
     RECT  21.481 24.912 21.516 24.936 ;
     RECT  21.481 24.936 21.564 25.056 ;
     RECT  21.481 25.056 21.516 25.08 ;
     RECT  21.481 25.08 21.564 25.2 ;
     RECT  21.481 25.2 21.516 25.224 ;
     RECT  21.481 25.224 21.564 25.344 ;
     RECT  21.481 25.344 21.516 25.368 ;
     RECT  21.481 25.368 21.564 25.488 ;
     RECT  21.481 25.488 21.516 25.512 ;
     RECT  21.481 25.512 21.564 25.632 ;
     RECT  21.481 25.632 21.516 25.656 ;
     RECT  21.481 25.656 21.564 25.776 ;
     RECT  21.481 25.776 21.516 25.8 ;
     RECT  21.481 25.8 21.564 25.92 ;
     RECT  21.481 25.92 21.516 25.944 ;
     RECT  21.481 25.944 21.564 26.064 ;
     RECT  21.481 26.064 21.516 26.088 ;
     RECT  21.481 26.088 21.564 26.208 ;
     RECT  21.481 26.208 21.516 26.232 ;
     RECT  21.481 26.232 21.564 26.352 ;
     RECT  21.481 26.352 21.516 26.376 ;
     RECT  21.481 26.376 21.564 26.496 ;
     RECT  21.481 26.496 21.516 26.52 ;
     RECT  21.481 26.52 21.564 26.64 ;
     RECT  21.481 26.64 21.516 26.664 ;
     RECT  21.481 26.664 21.564 26.784 ;
     RECT  21.481 26.784 21.516 26.808 ;
     RECT  21.481 26.808 21.564 26.928 ;
     RECT  21.481 26.928 21.516 26.952 ;
     RECT  21.481 26.952 21.564 27.072 ;
     RECT  21.481 27.072 21.516 27.096 ;
     RECT  21.481 27.096 21.564 27.216 ;
     RECT  21.481 27.216 21.516 27.24 ;
     RECT  21.481 27.24 21.564 27.36 ;
     RECT  21.481 27.36 21.516 27.384 ;
     RECT  21.481 27.384 21.564 27.504 ;
     RECT  21.481 27.504 21.516 27.528 ;
     RECT  21.481 27.528 21.564 27.648 ;
     RECT  21.481 27.648 21.516 27.672 ;
     RECT  21.481 27.672 21.564 27.792 ;
     RECT  21.481 27.792 21.516 27.816 ;
     RECT  21.481 27.816 21.564 27.936 ;
     RECT  21.481 27.936 21.516 27.96 ;
     RECT  21.481 27.96 21.564 28.08 ;
     RECT  21.481 28.08 21.516 28.104 ;
     RECT  21.481 28.104 21.564 28.224 ;
     RECT  21.481 28.224 21.516 28.248 ;
     RECT  20.977 29.52 21.516 29.544 ;
     RECT  20.977 29.544 21.564 29.664 ;
     RECT  20.977 29.664 21.516 29.688 ;
     RECT  20.977 29.688 21.564 29.808 ;
     RECT  20.977 29.808 21.516 29.832 ;
     RECT  20.977 29.832 21.564 29.952 ;
     RECT  20.977 29.952 21.516 29.976 ;
     RECT  20.977 29.976 21.564 30.096 ;
     RECT  20.977 30.096 21.516 30.12 ;
     RECT  20.977 30.12 21.564 30.24 ;
     RECT  20.977 30.24 21.516 30.264 ;
     RECT  20.977 30.264 21.564 30.384 ;
     RECT  20.977 30.384 21.516 30.408 ;
     RECT  20.977 30.408 21.564 30.528 ;
     RECT  20.977 30.528 21.516 30.552 ;
     RECT  20.977 30.552 21.564 30.672 ;
     RECT  20.977 30.672 21.516 30.696 ;
     RECT  20.977 30.696 21.564 30.816 ;
     RECT  20.977 30.816 21.516 30.84 ;
     RECT  20.977 30.84 21.564 30.96 ;
     RECT  20.977 30.96 21.516 30.984 ;
     RECT  20.977 30.984 21.564 31.104 ;
     RECT  20.977 31.104 21.516 31.128 ;
     RECT  20.977 31.128 21.564 31.248 ;
     RECT  20.977 31.248 21.516 31.272 ;
     RECT  20.977 31.272 21.564 31.392 ;
     RECT  20.977 31.392 21.516 31.416 ;
     RECT  20.977 31.416 21.564 31.536 ;
     RECT  20.977 31.536 21.516 31.56 ;
     RECT  20.977 31.56 21.564 31.68 ;
     RECT  20.977 31.68 21.516 31.704 ;
     RECT  20.977 31.704 21.564 31.824 ;
     RECT  20.977 31.824 21.516 31.848 ;
     RECT  20.977 31.848 21.564 31.968 ;
     RECT  20.977 31.968 21.516 31.992 ;
     RECT  20.977 31.992 21.564 32.112 ;
     RECT  20.977 32.112 21.516 32.136 ;
     RECT  20.977 32.136 21.564 32.256 ;
     RECT  20.977 32.256 21.516 32.28 ;
     RECT  20.977 32.28 21.564 32.4 ;
     RECT  20.977 32.4 21.516 32.424 ;
     RECT  20.977 32.424 21.564 32.544 ;
     RECT  20.977 32.544 21.516 32.568 ;
     RECT  20.977 32.568 21.564 32.688 ;
     RECT  20.977 32.688 21.516 32.712 ;
     RECT  20.977 32.712 21.564 32.832 ;
     RECT  20.977 32.832 21.516 32.856 ;
     RECT  20.977 32.856 21.564 32.976 ;
     RECT  20.977 32.976 21.516 33 ;
     RECT  20.977 33 21.564 33.12 ;
     RECT  20.977 33.12 21.516 33.144 ;
     RECT  20.977 33.144 21.564 33.264 ;
     RECT  20.977 33.264 21.516 33.288 ;
     RECT  20.977 33.288 21.564 33.408 ;
     RECT  20.977 33.408 21.516 33.432 ;
     RECT  20.977 33.432 21.564 33.552 ;
     RECT  20.977 33.552 21.516 33.576 ;
     RECT  20.977 33.576 21.564 33.696 ;
     RECT  20.977 33.696 21.516 33.72 ;
     RECT  20.977 33.72 21.564 33.84 ;
     RECT  20.977 33.84 21.516 33.864 ;
     RECT  20.977 33.864 21.564 33.984 ;
     RECT  20.977 33.984 21.516 34.008 ;
     RECT  20.977 34.008 21.564 34.128 ;
     RECT  20.977 34.128 21.516 34.152 ;
     RECT  20.977 34.152 21.564 34.272 ;
     RECT  20.977 34.272 21.516 34.296 ;
     RECT  20.977 34.296 21.564 34.416 ;
     RECT  20.977 34.416 21.516 34.44 ;
     RECT  20.977 34.44 21.564 34.56 ;
     RECT  20.977 34.56 21.516 34.584 ;
     RECT  20.977 34.584 21.564 34.704 ;
     RECT  20.977 34.704 21.516 34.728 ;
     RECT  20.977 34.728 21.564 34.848 ;
     RECT  20.977 34.848 21.516 34.872 ;
     RECT  20.977 34.872 21.564 34.992 ;
     RECT  20.977 34.992 21.516 35.016 ;
     RECT  20.977 35.016 21.564 35.136 ;
     RECT  20.977 35.136 21.516 35.16 ;
     RECT  20.977 35.16 21.564 35.28 ;
     RECT  20.977 35.28 21.516 35.304 ;
     RECT  20.977 35.304 21.564 35.424 ;
     RECT  20.977 35.424 21.516 35.448 ;
     RECT  20.977 35.448 21.564 35.568 ;
     RECT  20.977 35.568 21.516 35.592 ;
     RECT  20.977 35.592 21.564 35.712 ;
     RECT  20.977 35.712 21.516 35.736 ;
     RECT  20.977 35.736 21.564 35.856 ;
     RECT  20.977 35.856 21.516 35.88 ;
     RECT  20.977 35.88 21.564 36 ;
     RECT  20.977 36 21.516 36.024 ;
     RECT  20.977 36.024 21.564 36.144 ;
     RECT  20.977 36.144 21.516 36.168 ;
     RECT  20.977 36.168 21.564 36.288 ;
     RECT  20.977 36.288 21.516 36.312 ;
     RECT  20.977 36.312 21.564 36.432 ;
     RECT  20.977 36.432 21.516 36.456 ;
     RECT  20.977 36.456 21.564 36.576 ;
     RECT  20.977 36.576 21.516 36.6 ;
     RECT  20.977 36.6 21.564 36.72 ;
     RECT  20.977 36.72 21.516 36.744 ;
     RECT  20.977 36.744 21.564 36.864 ;
     RECT  20.977 36.864 21.516 36.888 ;
     RECT  20.977 36.888 21.564 37.008 ;
     RECT  20.977 37.008 21.516 37.032 ;
     RECT  20.977 37.032 21.564 37.152 ;
     RECT  20.977 37.152 21.516 37.176 ;
     RECT  20.977 37.176 21.564 37.296 ;
     RECT  20.977 37.296 21.516 37.32 ;
     RECT  20.977 37.32 21.564 37.44 ;
     RECT  20.977 37.44 21.516 37.464 ;
     RECT  20.977 37.464 21.564 37.584 ;
     RECT  20.977 37.584 21.516 37.608 ;
     RECT  20.977 37.608 21.564 37.728 ;
     RECT  20.977 37.728 21.516 37.752 ;
     RECT  20.977 37.752 21.564 37.872 ;
     RECT  20.977 37.872 21.516 37.896 ;
     RECT  20.977 37.896 21.564 38.016 ;
     RECT  20.977 38.016 21.516 38.04 ;
     RECT  20.977 38.04 21.564 38.16 ;
     RECT  20.977 38.16 21.516 38.184 ;
     RECT  20.977 38.184 21.564 38.304 ;
     RECT  20.977 38.304 21.516 38.328 ;
     RECT  20.977 38.328 21.564 38.448 ;
     RECT  20.977 38.448 21.516 38.472 ;
     RECT  20.977 38.472 21.564 38.592 ;
     RECT  20.977 38.592 21.516 38.616 ;
     RECT  20.977 38.616 21.564 38.736 ;
     RECT  20.977 38.736 21.516 38.76 ;
     RECT  20.977 38.76 21.564 38.88 ;
     RECT  20.977 38.88 21.516 38.904 ;
     RECT  20.977 38.904 21.564 39.024 ;
     RECT  20.977 39.024 21.516 39.048 ;
     RECT  20.977 39.048 21.564 39.168 ;
     RECT  20.977 39.168 21.516 39.192 ;
     RECT  20.977 39.192 21.564 39.312 ;
     RECT  20.977 39.312 21.516 39.336 ;
     RECT  20.977 39.336 21.564 39.456 ;
     RECT  20.977 39.456 21.516 39.48 ;
     RECT  20.977 39.48 21.564 39.6 ;
     RECT  20.977 39.6 21.516 39.624 ;
     RECT  20.977 39.624 21.564 39.744 ;
     RECT  20.977 39.744 21.516 39.768 ;
     RECT  20.977 39.768 21.564 39.888 ;
     RECT  20.977 39.888 21.516 39.912 ;
     RECT  20.977 39.912 21.564 40.032 ;
     RECT  20.977 40.032 21.516 40.056 ;
     RECT  20.977 40.056 21.564 40.176 ;
     RECT  20.977 40.176 21.516 40.2 ;
     RECT  20.977 40.2 21.564 40.32 ;
     RECT  20.977 40.32 21.516 40.344 ;
     RECT  20.977 40.344 21.564 40.464 ;
     RECT  20.977 40.464 21.516 40.488 ;
     RECT  20.977 40.488 21.564 40.608 ;
     RECT  20.977 40.608 21.516 40.632 ;
     RECT  20.977 40.632 21.564 40.752 ;
     RECT  20.977 40.752 21.516 40.776 ;
     RECT  20.977 40.776 21.564 40.896 ;
     RECT  20.977 40.896 21.516 40.92 ;
     RECT  20.977 40.92 21.564 41.04 ;
     RECT  20.977 41.04 21.516 41.064 ;
     RECT  20.977 41.064 21.564 41.184 ;
     RECT  20.977 41.184 21.516 41.208 ;
     RECT  20.977 41.208 21.564 41.328 ;
     RECT  20.977 41.328 21.516 41.352 ;
     RECT  20.977 41.352 21.564 41.472 ;
     RECT  20.977 41.472 21.516 41.496 ;
     RECT  20.977 41.496 21.564 41.616 ;
     RECT  20.977 41.616 21.516 41.64 ;
     RECT  20.977 41.64 21.564 41.76 ;
     RECT  20.977 41.76 21.516 41.784 ;
     RECT  20.977 41.784 21.564 41.904 ;
     RECT  20.977 41.904 21.516 41.928 ;
     RECT  20.977 41.928 21.564 42.048 ;
     RECT  20.977 42.048 21.516 42.072 ;
     RECT  20.977 42.072 21.564 42.192 ;
     RECT  20.977 42.192 21.516 42.216 ;
     RECT  20.977 42.216 21.564 42.336 ;
     RECT  20.977 42.336 21.516 42.36 ;
     RECT  20.977 42.36 21.564 42.48 ;
     RECT  20.977 42.48 21.516 42.504 ;
     RECT  20.977 42.504 21.564 42.624 ;
     RECT  20.977 42.624 21.516 42.648 ;
     RECT  20.977 42.648 21.564 42.768 ;
     RECT  20.977 42.768 21.516 42.792 ;
     RECT  20.977 42.792 21.564 42.912 ;
     RECT  20.977 42.912 21.516 42.936 ;
     RECT  20.977 42.936 21.564 43.056 ;
     RECT  20.977 43.056 21.516 43.08 ;
     RECT  20.977 43.08 21.564 43.2 ;
     RECT  20.977 43.2 21.516 43.224 ;
     RECT  20.977 43.224 21.564 43.344 ;
     RECT  20.977 43.344 21.516 43.368 ;
     RECT  20.977 43.368 21.564 43.488 ;
     RECT  20.977 43.488 21.516 43.512 ;
     RECT  20.977 43.512 21.564 43.632 ;
     RECT  20.977 43.632 21.516 43.656 ;
     RECT  20.977 43.656 21.564 43.776 ;
     RECT  20.977 43.776 21.516 43.8 ;
     RECT  20.977 43.8 21.564 43.92 ;
     RECT  20.977 43.92 21.516 43.944 ;
     RECT  20.977 43.944 21.564 44.064 ;
     RECT  20.977 44.064 21.516 44.088 ;
     RECT  20.977 44.088 21.564 44.208 ;
     RECT  20.977 44.208 21.516 44.232 ;
     RECT  20.977 44.232 21.564 44.352 ;
     RECT  20.977 44.352 21.516 44.376 ;
     RECT  20.977 44.376 21.564 44.496 ;
     RECT  20.977 44.496 21.516 44.52 ;
     RECT  20.977 44.52 21.564 44.64 ;
     RECT  20.977 44.64 21.516 44.664 ;
     RECT  20.977 44.664 21.564 44.784 ;
     RECT  20.977 44.784 21.516 44.808 ;
     RECT  20.977 44.808 21.564 44.928 ;
     RECT  20.977 44.928 21.516 44.952 ;
     RECT  20.977 44.952 21.564 45.072 ;
     RECT  20.977 45.072 21.516 45.096 ;
     RECT  20.977 45.096 21.564 45.216 ;
     RECT  20.977 45.216 21.516 45.24 ;
     RECT  20.977 45.24 21.564 45.36 ;
     RECT  20.977 45.36 21.516 45.384 ;
     RECT  20.977 45.384 21.564 45.504 ;
     RECT  20.977 45.504 21.516 45.528 ;
     RECT  20.977 45.528 21.564 45.648 ;
     RECT  20.977 45.648 21.516 45.672 ;
     RECT  20.977 45.672 21.564 45.792 ;
     RECT  20.977 45.792 21.516 45.816 ;
     RECT  20.977 45.816 21.564 45.936 ;
     RECT  20.977 45.936 21.516 45.96 ;
     RECT  20.977 45.96 21.564 46.08 ;
     RECT  20.977 46.08 21.516 46.104 ;
     RECT  20.977 46.104 21.564 46.224 ;
     RECT  20.977 46.224 21.516 46.248 ;
     RECT  20.977 46.248 21.564 46.368 ;
     RECT  20.977 46.368 21.516 46.392 ;
     RECT  20.977 46.392 21.564 46.512 ;
     RECT  20.977 46.512 21.516 46.536 ;
     RECT  20.977 46.536 21.564 46.656 ;
     RECT  20.977 46.656 21.516 46.68 ;
     RECT  20.977 46.68 21.564 46.8 ;
     RECT  20.977 46.8 21.516 46.824 ;
     RECT  20.977 46.824 21.564 46.944 ;
     RECT  20.977 46.944 21.516 46.968 ;
     RECT  20.977 46.968 21.564 47.088 ;
     RECT  20.977 47.088 21.516 47.112 ;
     RECT  20.977 47.112 21.564 47.232 ;
     RECT  20.977 47.232 21.516 47.256 ;
     RECT  20.977 47.256 21.564 47.376 ;
     RECT  20.977 47.376 21.516 47.4 ;
     RECT  20.977 47.4 21.564 47.52 ;
     RECT  20.977 47.52 21.516 47.544 ;
     RECT  20.977 47.544 21.564 47.664 ;
     RECT  20.977 47.664 21.516 47.688 ;
     RECT  20.977 47.688 21.564 47.808 ;
     RECT  20.977 47.808 21.516 47.832 ;
     RECT  20.977 47.832 21.564 47.952 ;
     RECT  20.977 47.952 21.516 47.976 ;
     RECT  20.977 47.976 21.564 48.096 ;
     RECT  20.977 48.096 21.516 48.12 ;
     RECT  20.977 48.12 21.564 48.24 ;
     RECT  20.977 48.24 21.516 48.264 ;
     RECT  20.977 48.264 21.564 48.384 ;
     RECT  20.977 48.384 21.516 48.408 ;
     RECT  20.977 48.408 21.564 48.528 ;
     RECT  20.977 48.528 21.516 48.552 ;
     RECT  20.977 48.552 21.564 48.672 ;
     RECT  20.977 48.672 21.516 48.696 ;
     RECT  20.977 48.696 21.564 48.816 ;
     RECT  20.977 48.816 21.516 48.84 ;
     RECT  20.977 48.84 21.564 48.96 ;
     RECT  20.977 48.96 21.516 48.984 ;
     RECT  20.977 48.984 21.564 49.104 ;
     RECT  20.977 49.104 21.516 49.128 ;
     RECT  20.977 49.128 21.564 49.248 ;
     RECT  20.977 49.248 21.516 49.272 ;
     RECT  20.977 49.272 21.564 49.392 ;
     RECT  20.977 49.392 21.516 49.416 ;
     RECT  20.977 49.416 21.564 49.536 ;
     RECT  20.977 49.536 21.516 49.56 ;
     RECT  20.977 49.56 21.564 49.68 ;
     RECT  20.977 49.68 21.516 49.704 ;
     RECT  20.977 49.704 21.564 49.824 ;
     RECT  20.977 49.824 21.516 49.848 ;
     RECT  20.977 49.848 21.564 49.968 ;
     RECT  20.977 49.968 21.516 49.992 ;
     RECT  20.977 49.992 21.564 50.112 ;
     RECT  20.977 50.112 21.516 50.136 ;
     RECT  20.977 50.136 21.564 50.256 ;
     RECT  20.977 50.256 21.516 50.28 ;
     RECT  20.977 50.28 21.564 50.4 ;
     RECT  20.977 50.4 21.516 50.424 ;
     RECT  20.977 50.424 21.564 50.544 ;
     RECT  20.977 50.544 21.516 50.568 ;
     RECT  20.977 50.568 21.564 50.688 ;
     RECT  20.977 50.688 21.516 50.712 ;
     RECT  20.977 50.712 21.564 50.832 ;
     RECT  20.977 50.832 21.516 50.856 ;
     RECT  20.977 50.856 21.564 50.976 ;
     RECT  20.977 50.976 21.516 51 ;
     RECT  20.977 51 21.564 51.12 ;
     RECT  20.977 51.12 21.516 51.144 ;
     RECT  20.977 51.144 21.564 51.264 ;
     RECT  20.977 51.264 21.516 51.288 ;
     RECT  20.977 51.288 21.564 51.408 ;
     RECT  20.977 51.408 21.516 51.432 ;
     RECT  20.977 51.432 21.564 51.552 ;
     RECT  20.977 51.552 21.516 51.576 ;
     RECT  20.977 51.576 21.564 51.696 ;
     RECT  20.977 51.696 21.516 51.72 ;
     RECT  20.977 51.72 21.564 51.84 ;
     RECT  20.977 51.84 21.516 51.864 ;
     RECT  20.977 51.864 21.564 51.984 ;
     RECT  20.977 51.984 21.516 52.008 ;
     RECT  20.977 52.008 21.564 52.128 ;
     RECT  20.977 52.128 21.516 52.152 ;
     RECT  20.977 52.152 21.564 52.272 ;
     RECT  20.977 52.272 21.516 52.296 ;
     RECT  20.977 52.296 21.564 52.416 ;
     RECT  20.977 52.416 21.516 52.44 ;
     RECT  20.977 52.44 21.564 52.56 ;
     RECT  20.977 52.56 21.516 52.584 ;
     RECT  20.977 52.584 21.564 52.704 ;
     RECT  20.977 52.704 21.516 52.728 ;
     RECT  20.977 52.728 21.564 52.848 ;
     RECT  20.977 52.848 21.516 52.872 ;
     RECT  20.977 52.872 21.564 52.992 ;
     RECT  20.977 52.992 21.516 53.016 ;
     RECT  20.977 53.016 21.564 53.136 ;
     RECT  20.977 53.136 21.516 53.16 ;
     RECT  20.977 53.16 21.564 53.28 ;
     RECT  20.977 53.28 21.516 53.304 ;
     RECT  20.977 53.304 21.564 53.424 ;
     RECT  20.977 53.424 21.516 53.448 ;
     RECT  20.977 53.448 21.564 53.568 ;
     RECT  20.977 53.568 21.516 53.592 ;
     RECT  20.977 53.592 21.564 53.712 ;
     RECT  20.977 53.712 21.516 53.736 ;
     RECT  20.977 53.736 21.564 53.856 ;
     RECT  20.977 53.856 21.516 53.88 ;
     RECT  20.977 53.88 21.564 54 ;
     RECT  20.977 54 21.516 54.024 ;
     RECT  20.977 54.024 21.564 54.144 ;
     RECT  20.977 54.144 21.516 54.168 ;
     RECT  20.977 54.168 21.564 54.288 ;
     RECT  20.977 54.288 21.516 54.312 ;
     RECT  20.977 54.312 21.564 54.432 ;
     RECT  20.977 54.432 21.516 54.456 ;
     RECT  20.977 54.456 21.564 54.576 ;
     RECT  20.977 54.576 21.516 54.6 ;
     RECT  20.977 54.6 21.564 54.72 ;
     RECT  20.977 54.72 21.516 54.744 ;
     RECT  20.977 54.744 21.564 54.864 ;
     RECT  20.977 54.864 21.516 54.888 ;
     RECT  20.977 54.888 21.564 55.008 ;
     RECT  20.977 55.008 21.516 55.032 ;
     RECT  20.977 55.032 21.564 55.152 ;
     RECT  20.977 55.152 21.516 55.176 ;
     RECT  20.977 55.176 21.564 55.296 ;
     RECT  20.977 55.296 21.516 55.32 ;
     RECT  20.977 55.32 21.564 55.44 ;
     RECT  20.977 55.44 21.516 55.464 ;
     RECT  20.977 55.464 21.564 55.584 ;
     RECT  20.977 55.584 21.516 55.608 ;
     RECT  20.977 55.608 21.564 55.728 ;
     RECT  20.977 55.728 21.516 55.752 ;
     RECT  20.977 55.752 21.564 55.872 ;
     RECT  20.977 55.872 21.516 55.896 ;
     RECT  20.977 55.896 21.564 56.016 ;
     RECT  20.977 56.016 21.516 56.04 ;
     RECT  20.977 56.04 21.564 56.16 ;
     RECT  20.977 56.16 21.516 56.184 ;
     RECT  20.977 56.184 21.564 56.304 ;
     RECT  20.977 56.304 21.516 56.328 ;
     RECT  20.977 56.328 21.564 56.448 ;
     RECT  20.977 56.448 21.516 56.472 ;
     RECT  20.977 56.472 21.564 56.592 ;
     RECT  20.977 56.592 21.516 56.616 ;
     RECT  20.977 56.616 21.564 56.736 ;
     RECT  20.977 56.736 21.516 56.76 ;
     RECT  20.977 56.76 21.564 56.88 ;
     RECT  20.977 56.88 21.516 56.904 ;
     RECT  20.977 56.904 21.564 57.024 ;
     RECT  20.977 57.024 21.516 57.048 ;
     RECT  20.509 58.32 21.516 58.344 ;
     RECT  20.509 58.344 21.564 58.464 ;
     RECT  20.509 58.464 21.516 58.488 ;
     RECT  20.509 58.488 21.564 58.608 ;
     RECT  20.509 58.608 21.516 58.632 ;
     RECT  20.509 58.632 21.564 58.752 ;
     RECT  20.509 58.752 21.516 58.776 ;
     RECT  20.509 58.776 21.564 58.896 ;
     RECT  20.509 58.896 21.516 58.92 ;
     RECT  20.509 58.92 21.564 59.04 ;
     RECT  20.509 59.04 21.516 59.064 ;
     RECT  20.509 59.064 21.564 59.184 ;
     RECT  20.509 59.184 21.516 59.208 ;
     RECT  20.509 59.208 21.564 59.328 ;
     RECT  20.509 59.328 21.516 59.352 ;
     RECT  20.509 59.352 21.564 59.472 ;
     RECT  20.509 59.472 21.516 59.496 ;
     RECT  20.509 59.496 21.564 59.616 ;
     RECT  20.509 59.616 21.516 59.64 ;
     RECT  20.509 59.64 21.564 59.76 ;
     RECT  20.509 59.76 21.516 59.784 ;
     RECT  20.509 59.784 21.564 59.904 ;
     RECT  20.509 59.904 21.516 59.928 ;
     RECT  20.509 59.928 21.564 60.048 ;
     RECT  20.509 60.048 21.516 60.072 ;
     RECT  20.509 60.072 21.564 60.192 ;
     RECT  20.509 60.192 21.516 60.216 ;
     RECT  20.509 60.216 21.564 60.336 ;
     RECT  20.509 60.336 21.516 60.36 ;
     RECT  20.509 60.36 21.564 60.48 ;
     RECT  20.509 60.48 21.516 60.504 ;
     RECT  20.509 60.504 21.564 60.624 ;
     RECT  20.509 60.624 21.516 60.648 ;
     RECT  20.509 60.648 21.564 60.768 ;
     RECT  20.509 60.768 21.516 60.792 ;
     RECT  20.509 60.792 21.564 60.912 ;
     RECT  20.509 60.912 21.516 60.936 ;
     RECT  20.509 60.936 21.564 61.056 ;
     RECT  20.509 61.056 21.516 61.08 ;
     RECT  20.509 61.08 21.564 61.2 ;
     RECT  20.509 61.2 21.516 61.224 ;
     RECT  20.509 61.224 21.564 61.344 ;
     RECT  20.509 61.344 21.516 61.368 ;
     RECT  20.509 61.368 21.564 61.488 ;
     RECT  20.509 61.488 21.516 61.512 ;
     RECT  20.509 61.512 21.564 61.632 ;
     RECT  20.509 61.632 21.516 61.656 ;
     RECT  20.509 61.656 21.564 61.776 ;
     RECT  20.509 61.776 21.516 61.8 ;
     RECT  20.509 61.8 21.564 61.92 ;
     RECT  20.509 61.92 21.516 61.944 ;
     RECT  20.509 61.944 21.564 62.064 ;
     RECT  20.509 62.064 21.516 62.088 ;
     RECT  20.509 62.088 21.564 62.208 ;
     RECT  20.509 62.208 21.516 62.232 ;
     RECT  20.509 62.232 21.564 62.352 ;
     RECT  20.509 62.352 21.516 62.376 ;
     RECT  20.509 62.376 21.564 62.496 ;
     RECT  20.509 62.496 21.516 62.52 ;
     RECT  20.509 62.52 21.564 62.64 ;
     RECT  20.509 62.64 21.516 62.664 ;
     RECT  20.509 62.664 21.564 62.784 ;
     RECT  20.509 62.784 21.516 62.808 ;
     RECT  20.509 62.808 21.564 62.928 ;
     RECT  20.509 62.928 21.516 62.952 ;
     RECT  20.509 62.952 21.564 63.072 ;
     RECT  20.509 63.072 21.516 63.096 ;
     RECT  20.509 63.096 21.564 63.216 ;
     RECT  20.509 63.216 21.516 63.24 ;
     RECT  20.509 63.24 21.564 63.36 ;
     RECT  20.509 63.36 21.516 63.384 ;
     RECT  20.509 63.384 21.564 63.504 ;
     RECT  20.509 63.504 21.516 63.528 ;
     RECT  20.509 63.528 21.564 63.648 ;
     RECT  20.509 63.648 21.516 63.672 ;
     RECT  20.509 63.672 21.564 63.792 ;
     RECT  20.509 63.792 21.516 63.816 ;
     RECT  20.509 63.816 21.564 63.936 ;
     RECT  20.509 63.936 21.516 63.96 ;
     RECT  20.509 63.96 21.564 64.08 ;
     RECT  20.509 64.08 21.516 64.104 ;
     RECT  20.509 64.104 21.564 64.224 ;
     RECT  20.509 64.224 21.516 64.248 ;
     RECT  20.509 64.248 21.564 64.368 ;
     RECT  20.509 64.368 21.516 64.392 ;
     RECT  20.509 64.392 21.564 64.512 ;
     RECT  20.509 64.512 21.516 64.536 ;
     RECT  20.509 64.536 21.564 64.656 ;
     RECT  20.509 64.656 21.516 64.68 ;
     RECT  20.509 64.68 21.564 64.8 ;
     RECT  20.509 64.8 21.516 64.824 ;
     RECT  20.509 64.824 21.564 64.944 ;
     RECT  20.509 64.944 21.516 64.968 ;
     RECT  20.509 64.968 21.564 65.088 ;
     RECT  20.509 65.088 21.516 65.112 ;
     RECT  20.509 65.112 21.564 65.232 ;
     RECT  20.509 65.232 21.516 65.256 ;
     RECT  20.509 65.256 21.564 65.376 ;
     RECT  20.509 65.376 21.516 65.4 ;
     RECT  20.509 65.4 21.564 65.52 ;
     RECT  20.509 65.52 21.516 65.544 ;
     RECT  20.509 65.544 21.564 65.664 ;
     RECT  20.509 65.664 21.516 65.688 ;
     RECT  20.509 65.688 21.564 65.808 ;
     RECT  20.509 65.808 21.516 65.832 ;
     RECT  20.509 65.832 21.564 65.952 ;
     RECT  20.509 65.952 21.516 65.976 ;
     RECT  20.509 65.976 21.564 66.096 ;
     RECT  20.509 66.096 21.516 66.12 ;
     RECT  20.509 66.12 21.564 66.24 ;
     RECT  20.509 66.24 21.516 66.264 ;
     RECT  20.509 66.264 21.564 66.384 ;
     RECT  20.509 66.384 21.516 66.408 ;
     RECT  20.509 66.408 21.564 66.528 ;
     RECT  20.509 66.528 21.516 66.552 ;
     RECT  20.509 66.552 21.564 66.672 ;
     RECT  20.509 66.672 21.516 66.696 ;
     RECT  20.509 66.696 21.564 66.816 ;
     RECT  20.509 66.816 21.516 66.84 ;
     RECT  20.509 66.84 21.564 66.96 ;
     RECT  20.509 66.96 21.516 66.984 ;
     RECT  20.509 66.984 21.564 67.104 ;
     RECT  20.509 67.104 21.516 67.128 ;
     RECT  20.509 67.128 21.564 67.248 ;
     RECT  20.509 67.248 21.516 67.272 ;
     RECT  20.509 67.272 21.564 67.392 ;
     RECT  20.509 67.392 21.516 67.416 ;
     RECT  20.509 67.416 21.564 67.536 ;
     RECT  20.509 67.536 21.516 67.56 ;
     RECT  20.509 67.56 21.564 67.68 ;
     RECT  20.509 67.68 21.516 67.704 ;
     RECT  20.509 67.704 21.564 67.824 ;
     RECT  20.509 67.824 21.516 67.848 ;
     RECT  20.509 67.848 21.564 67.968 ;
     RECT  20.509 67.968 21.516 67.992 ;
     RECT  20.509 67.992 21.564 68.112 ;
     RECT  20.509 68.112 21.516 68.136 ;
     RECT  20.509 68.136 21.564 68.256 ;
     RECT  20.509 68.256 21.516 68.28 ;
     RECT  20.509 68.28 21.564 68.4 ;
     RECT  20.509 68.4 21.516 68.424 ;
     RECT  20.509 68.424 21.564 68.544 ;
     RECT  20.509 68.544 21.516 68.568 ;
     RECT  20.509 68.568 21.564 68.688 ;
     RECT  20.509 68.688 21.516 68.712 ;
     RECT  20.509 68.712 21.564 68.832 ;
     RECT  20.509 68.832 21.516 68.856 ;
     RECT  20.509 68.856 21.564 68.976 ;
     RECT  20.509 68.976 21.516 69 ;
     RECT  20.509 69 21.564 69.12 ;
     RECT  20.509 69.12 21.516 69.144 ;
     RECT  20.509 69.144 21.564 69.264 ;
     RECT  20.509 69.264 21.516 69.288 ;
     RECT  20.509 69.288 21.564 69.408 ;
     RECT  20.509 69.408 21.516 69.432 ;
     RECT  20.509 69.432 21.564 69.552 ;
     RECT  20.509 69.552 21.516 69.576 ;
     RECT  20.509 69.576 21.564 69.696 ;
     RECT  20.509 69.696 21.516 69.72 ;
     RECT  20.509 69.72 21.564 69.84 ;
     RECT  20.509 69.84 21.516 69.864 ;
     RECT  20.509 69.864 21.564 69.984 ;
     RECT  20.509 69.984 21.516 70.008 ;
     RECT  20.509 70.008 21.564 70.128 ;
     RECT  20.509 70.128 21.516 70.152 ;
     RECT  20.509 70.152 21.564 70.272 ;
     RECT  20.509 70.272 21.516 70.296 ;
     RECT  20.509 70.296 21.564 70.416 ;
     RECT  20.509 70.416 21.516 70.44 ;
     RECT  20.509 70.44 21.564 70.56 ;
     RECT  20.509 70.56 21.516 70.584 ;
     RECT  20.509 70.584 21.564 70.704 ;
     RECT  20.509 70.704 21.516 70.728 ;
     RECT  20.509 70.728 21.564 70.848 ;
     RECT  20.509 70.848 21.516 70.872 ;
     RECT  20.509 70.872 21.564 70.992 ;
     RECT  20.509 70.992 21.516 71.016 ;
     RECT  20.509 71.016 21.564 71.136 ;
     RECT  20.509 71.136 21.516 71.16 ;
     RECT  20.509 71.16 21.564 71.28 ;
     RECT  20.509 71.28 21.516 71.304 ;
     RECT  20.509 71.304 21.564 71.424 ;
     RECT  20.509 71.424 21.516 71.448 ;
     RECT  20.509 71.448 21.564 71.568 ;
     RECT  20.509 71.568 21.516 71.592 ;
     RECT  20.509 71.592 21.564 71.712 ;
     RECT  20.509 71.712 21.516 71.736 ;
     RECT  20.509 71.736 21.564 71.856 ;
     RECT  20.509 71.856 21.516 71.88 ;
     RECT  20.509 71.88 21.564 72 ;
     RECT  20.509 72 21.516 72.024 ;
     RECT  20.509 72.024 21.564 72.144 ;
     RECT  20.509 72.144 21.516 72.168 ;
     RECT  20.509 72.168 21.564 72.288 ;
     RECT  20.509 72.288 21.516 72.312 ;
     RECT  20.509 72.312 21.564 72.432 ;
     RECT  20.509 72.432 21.516 72.456 ;
     RECT  20.509 72.456 21.564 72.576 ;
     RECT  20.509 72.576 21.516 72.6 ;
     RECT  20.509 72.6 21.564 72.72 ;
     RECT  20.509 72.72 21.516 72.744 ;
     RECT  20.509 72.744 21.564 72.864 ;
     RECT  20.509 72.864 21.516 72.888 ;
     RECT  20.509 72.888 21.564 73.008 ;
     RECT  20.509 73.008 21.516 73.032 ;
     RECT  20.509 73.032 21.564 73.152 ;
     RECT  20.509 73.152 21.516 73.176 ;
     RECT  20.509 73.176 21.564 73.296 ;
     RECT  20.509 73.296 21.516 73.32 ;
     RECT  20.509 73.32 21.564 73.44 ;
     RECT  20.509 73.44 21.516 73.464 ;
     RECT  20.509 73.464 21.564 73.584 ;
     RECT  20.509 73.584 21.516 73.608 ;
     RECT  20.509 73.608 21.564 73.728 ;
     RECT  20.509 73.728 21.516 73.752 ;
     RECT  20.509 73.752 21.564 73.872 ;
     RECT  20.509 73.872 21.516 73.896 ;
     RECT  20.509 73.896 21.564 74.016 ;
     RECT  20.509 74.016 21.516 74.04 ;
     RECT  20.509 74.04 21.564 74.16 ;
     RECT  20.509 74.16 21.516 74.184 ;
     RECT  20.509 74.184 21.564 74.304 ;
     RECT  20.509 74.304 21.516 74.328 ;
     RECT  20.509 74.328 21.564 74.448 ;
     RECT  20.509 74.448 21.516 74.472 ;
     RECT  20.509 74.472 21.564 74.592 ;
     RECT  20.509 74.592 21.516 74.616 ;
     RECT  20.509 74.616 21.564 74.736 ;
     RECT  20.509 74.736 21.516 74.76 ;
     RECT  20.509 74.76 21.564 74.88 ;
     RECT  20.509 74.88 21.516 74.904 ;
     RECT  20.509 74.904 21.564 75.024 ;
     RECT  20.509 75.024 21.516 75.048 ;
     RECT  20.509 75.048 21.564 75.168 ;
     RECT  20.509 75.168 21.516 75.192 ;
     RECT  20.509 75.192 21.564 75.312 ;
     RECT  20.509 75.312 21.516 75.336 ;
     RECT  20.509 75.336 21.564 75.456 ;
     RECT  20.509 75.456 21.516 75.48 ;
     RECT  20.509 75.48 21.564 75.6 ;
     RECT  20.509 75.6 21.516 75.624 ;
     RECT  20.509 75.624 21.564 75.744 ;
     RECT  20.509 75.744 21.516 75.768 ;
     RECT  20.509 75.768 21.564 75.888 ;
     RECT  20.509 75.888 21.516 75.912 ;
     RECT  20.509 75.912 21.564 76.032 ;
     RECT  20.509 76.032 21.516 76.056 ;
     RECT  20.509 76.056 21.564 76.176 ;
     RECT  20.509 76.176 21.516 76.2 ;
     RECT  20.509 76.2 21.564 76.32 ;
     RECT  20.509 76.32 21.516 76.344 ;
     RECT  20.509 76.344 21.564 76.464 ;
     RECT  20.509 76.464 21.516 76.488 ;
     RECT  20.509 76.488 21.564 76.608 ;
     RECT  20.509 76.608 21.516 76.632 ;
     RECT  20.509 76.632 21.564 76.752 ;
     RECT  20.509 76.752 21.516 76.776 ;
     RECT  20.509 76.776 21.564 76.896 ;
     RECT  20.509 76.896 21.516 76.92 ;
     RECT  20.509 76.92 21.564 77.04 ;
     RECT  20.509 77.04 21.516 77.064 ;
     RECT  20.509 77.064 21.564 77.184 ;
     RECT  20.509 77.184 21.516 77.208 ;
     RECT  20.509 77.208 21.564 77.328 ;
     RECT  20.509 77.328 21.516 77.352 ;
     RECT  20.509 77.352 21.564 77.472 ;
     RECT  20.509 77.472 21.516 77.496 ;
     RECT  20.509 77.496 21.564 77.616 ;
     RECT  20.509 77.616 21.516 77.64 ;
     RECT  20.509 77.64 21.564 77.76 ;
     RECT  20.509 77.76 21.516 77.784 ;
     RECT  20.509 77.784 21.564 77.904 ;
     RECT  20.509 77.904 21.516 77.928 ;
     RECT  20.509 77.928 21.564 78.048 ;
     RECT  20.509 78.048 21.516 78.072 ;
     RECT  20.509 78.072 21.564 78.192 ;
     RECT  20.509 78.192 21.516 78.216 ;
     RECT  20.509 78.216 21.564 78.336 ;
     RECT  20.509 78.336 21.516 78.36 ;
     RECT  20.509 78.36 21.564 78.48 ;
     RECT  20.509 78.48 21.516 78.504 ;
     RECT  20.509 78.504 21.564 78.624 ;
     RECT  20.509 78.624 21.516 78.648 ;
     RECT  20.509 78.648 21.564 78.768 ;
     RECT  20.509 78.768 21.516 78.792 ;
     RECT  20.509 78.792 21.564 78.912 ;
     RECT  20.509 78.912 21.516 78.936 ;
    LAYER M5 ;
     RECT  5.568 0.037 5.592 2.137 ;
     RECT  2.4 2.137 2.52 2.151 ;
     RECT  7.8 2.137 7.92 2.151 ;
     RECT  10.5 2.137 10.62 2.151 ;
     RECT  13.2 2.137 13.32 2.151 ;
     RECT  15.9 2.137 16.02 2.151 ;
     RECT  18.6 2.137 18.72 2.151 ;
     RECT  2.4 2.151 2.712 3.925 ;
     RECT  10.5 2.151 10.812 4.693 ;
     RECT  5.1 2.137 5.592 5.029 ;
     RECT  2.4 3.925 3.288 5.219 ;
     RECT  10.5 4.693 11.784 6.229 ;
     RECT  21.408 7.621 21.432 7.763 ;
     RECT  7.8 2.151 8.112 8.293 ;
     RECT  5.1 5.029 5.928 8.435 ;
     RECT  2.4 5.219 2.712 9.205 ;
     RECT  2.304 9.205 2.712 9.347 ;
     RECT  2.4 9.347 2.712 9.397 ;
     RECT  5.1 8.435 5.592 9.397 ;
     RECT  7.056 8.293 8.112 10.307 ;
     RECT  4.752 9.397 5.592 10.789 ;
     RECT  4.752 10.789 5.688 11.317 ;
     RECT  4.512 11.317 5.688 11.941 ;
     RECT  7.8 10.307 8.112 11.941 ;
     RECT  4.512 11.941 6.216 12.563 ;
     RECT  2.4 9.397 3.24 12.755 ;
     RECT  7.584 11.941 8.112 13.139 ;
     RECT  7.8 13.139 8.112 13.621 ;
     RECT  5.1 12.563 6.216 14.197 ;
     RECT  7.8 13.621 8.52 14.197 ;
     RECT  7.44 14.197 8.52 14.485 ;
     RECT  10.128 6.229 11.784 14.485 ;
     RECT  0.144 14.389 0.168 14.531 ;
     RECT  7.44 14.485 11.784 15.443 ;
     RECT  2.4 12.755 2.712 15.877 ;
     RECT  4.56 14.197 6.216 15.925 ;
     RECT  13.2 2.151 13.512 16.789 ;
     RECT  7.8 15.443 11.784 17.605 ;
     RECT  2.4 15.877 3.288 18.709 ;
     RECT  4.464 15.925 6.216 18.709 ;
     RECT  2.4 18.709 6.216 18.995 ;
     RECT  7.68 17.605 11.784 20.291 ;
     RECT  4.224 18.995 6.216 21.155 ;
     RECT  2.4 18.995 3.096 21.683 ;
     RECT  4.464 21.155 5.736 23.845 ;
     RECT  4.464 23.845 5.928 25.715 ;
     RECT  18.6 2.151 18.912 26.341 ;
     RECT  4.464 25.715 5.832 28.213 ;
     RECT  4.464 28.213 5.928 28.355 ;
     RECT  2.4 21.683 2.712 29.365 ;
     RECT  7.8 20.291 11.784 29.365 ;
     RECT  15.9 2.151 16.212 30.565 ;
     RECT  7.344 29.365 11.784 30.611 ;
     RECT  7.8 30.611 11.784 32.533 ;
     RECT  2.4 29.365 3.432 33.253 ;
     RECT  2.304 33.253 3.432 33.395 ;
     RECT  6.96 32.533 11.784 34.117 ;
     RECT  2.4 33.395 3.432 34.355 ;
     RECT  6.912 34.117 11.784 35.363 ;
     RECT  2.4 34.355 2.712 38.245 ;
     RECT  2.4 38.245 3.288 38.963 ;
     RECT  15.648 30.565 16.212 41.029 ;
     RECT  14.688 41.029 16.212 41.459 ;
     RECT  7.2 35.363 11.784 41.605 ;
     RECT  2.4 38.963 2.712 42.133 ;
     RECT  2.4 42.133 3.336 42.517 ;
     RECT  2.304 42.517 3.336 42.659 ;
     RECT  6.864 41.605 11.784 42.755 ;
     RECT  2.4 42.659 3.336 43.475 ;
     RECT  7.2 42.755 11.784 43.571 ;
     RECT  2.4 43.475 2.712 44.725 ;
     RECT  2.208 44.725 2.712 44.963 ;
     RECT  4.464 28.355 5.832 44.965 ;
     RECT  7.8 43.571 11.784 45.059 ;
     RECT  2.4 44.963 2.712 50.581 ;
     RECT  2.304 50.581 2.712 50.725 ;
     RECT  2.304 50.725 3.096 51.299 ;
     RECT  2.4 51.299 3.096 51.395 ;
     RECT  4.464 44.965 6.072 51.829 ;
     RECT  2.4 51.395 2.712 52.405 ;
     RECT  4.176 51.829 6.072 52.405 ;
     RECT  2.4 52.405 6.072 53.795 ;
     RECT  4.176 53.795 6.072 55.043 ;
     RECT  2.4 53.795 2.712 58.501 ;
     RECT  2.256 58.501 2.712 58.643 ;
     RECT  4.464 55.043 6.072 58.645 ;
     RECT  7.8 45.059 8.52 58.645 ;
     RECT  2.4 58.643 2.712 59.893 ;
     RECT  2.304 59.893 2.712 60.035 ;
     RECT  4.464 58.645 8.52 60.035 ;
     RECT  2.4 60.035 2.712 60.373 ;
     RECT  10.128 45.059 11.784 60.419 ;
     RECT  2.4 60.373 3.192 61.525 ;
     RECT  2.304 61.525 3.192 61.619 ;
     RECT  2.304 61.619 2.808 61.715 ;
     RECT  4.464 60.035 6.216 64.885 ;
     RECT  7.8 60.035 8.52 65.603 ;
     RECT  2.4 61.715 2.808 65.893 ;
     RECT  3.984 64.885 6.216 65.893 ;
     RECT  2.4 65.893 6.216 65.989 ;
     RECT  7.8 65.603 8.328 66.085 ;
     RECT  2.16 65.989 6.216 66.131 ;
     RECT  2.4 66.131 6.216 66.755 ;
     RECT  7.488 66.085 8.328 66.755 ;
     RECT  4.464 66.755 6.216 67.283 ;
     RECT  2.4 66.755 3.144 67.523 ;
     RECT  18.6 26.341 19.656 67.573 ;
     RECT  18.6 67.573 19.752 67.715 ;
     RECT  5.1 67.283 6.216 68.917 ;
     RECT  2.4 67.523 2.808 69.251 ;
     RECT  4.992 68.917 6.216 69.587 ;
     RECT  7.8 66.755 8.328 69.973 ;
     RECT  5.1 69.587 6.216 70.933 ;
     RECT  7.632 69.973 8.328 70.933 ;
     RECT  5.1 70.933 8.328 72.467 ;
     RECT  5.1 72.467 6.264 74.053 ;
     RECT  4.992 74.053 6.264 74.819 ;
     RECT  5.1 74.819 6.264 75.443 ;
     RECT  2.4 69.251 2.712 76.069 ;
     RECT  7.8 72.467 8.328 76.403 ;
     RECT  5.1 75.443 5.736 76.451 ;
     RECT  12.768 16.789 13.512 77.315 ;
     RECT  10.5 60.419 11.784 77.363 ;
     RECT  2.4 76.069 3.192 78.131 ;
     RECT  15.648 41.459 16.212 79.283 ;
     RECT  2.4 78.131 2.712 79.929 ;
     RECT  5.1 76.451 5.412 79.929 ;
     RECT  7.8 76.403 8.112 79.929 ;
     RECT  10.5 77.363 10.812 79.929 ;
     RECT  13.2 77.315 13.512 79.929 ;
     RECT  15.9 79.283 16.212 79.929 ;
     RECT  18.6 67.715 18.912 79.929 ;
     RECT  2.4 79.929 2.52 79.943 ;
     RECT  5.1 79.929 5.22 79.943 ;
     RECT  7.8 79.929 7.92 79.943 ;
     RECT  10.5 79.929 10.62 79.943 ;
     RECT  13.2 79.929 13.32 79.943 ;
     RECT  15.9 79.929 16.02 79.943 ;
     RECT  18.6 79.929 18.72 79.943 ;
     RECT  15.984 79.943 16.008 80.917 ;
     RECT  15.984 80.917 16.152 81.996 ;
     RECT  16.008 81.996 16.128 82.064 ;
     RECT  11.784 4.693 13.2 16.789 ;
     RECT  5.928 8.293 7.056 8.435 ;
     RECT  5.592 8.435 7.056 10.307 ;
     RECT  3.24 9.397 4.752 11.317 ;
     RECT  5.592 10.307 5.688 10.789 ;
     RECT  3.24 11.317 4.512 12.563 ;
     RECT  6.216 11.941 7.584 13.139 ;
     RECT  6.216 13.139 7.8 14.197 ;
     RECT  6.216 14.197 7.44 15.443 ;
     RECT  3.288 15.877 4.56 15.925 ;
     RECT  3.288 15.925 4.464 18.709 ;
     RECT  11.784 16.789 12.768 77.315 ;
     RECT  6.216 17.605 7.68 20.291 ;
     RECT  3.096 18.995 4.224 21.155 ;
     RECT  3.096 21.155 4.464 21.683 ;
     RECT  5.832 28.355 5.928 29.365 ;
     RECT  3.432 29.365 4.464 34.355 ;
     RECT  5.832 29.365 7.344 30.611 ;
     RECT  5.832 32.533 6.96 34.117 ;
     RECT  5.832 34.117 6.912 35.363 ;
     RECT  5.832 35.363 7.2 41.605 ;
     RECT  3.288 38.245 4.464 38.963 ;
     RECT  13.512 41.029 14.688 41.459 ;
     RECT  5.832 41.605 6.864 42.755 ;
     RECT  3.336 42.133 4.464 43.475 ;
     RECT  5.832 42.755 7.2 43.571 ;
     RECT  5.832 43.571 6.072 44.965 ;
     RECT  3.096 50.725 4.464 51.395 ;
     RECT  2.712 51.395 4.464 51.829 ;
     RECT  2.712 51.829 4.176 52.405 ;
     RECT  2.712 53.795 4.176 55.043 ;
     RECT  2.304 58.643 2.4 59.893 ;
     RECT  2.304 60.035 2.4 61.525 ;
     RECT  3.192 60.373 4.464 61.619 ;
     RECT  2.808 64.885 3.984 65.893 ;
     RECT  6.216 66.085 7.488 66.755 ;
     RECT  3.144 66.755 4.464 67.283 ;
     RECT  6.216 69.973 7.632 70.933 ;
     RECT  11.784 77.315 13.2 77.363 ;
     RECT  16.02 79.929 16.152 79.943 ;
     RECT  16.008 79.943 16.152 80.917 ;
  END
END qkd_rlysh_528
END LIBRARY
